VERSION 5.8 ;
BUSBITCHARS "[]" ;
DIVIDERCHAR "/" ;
UNITS
    DATABASE MICRONS 1000 ;
END UNITS

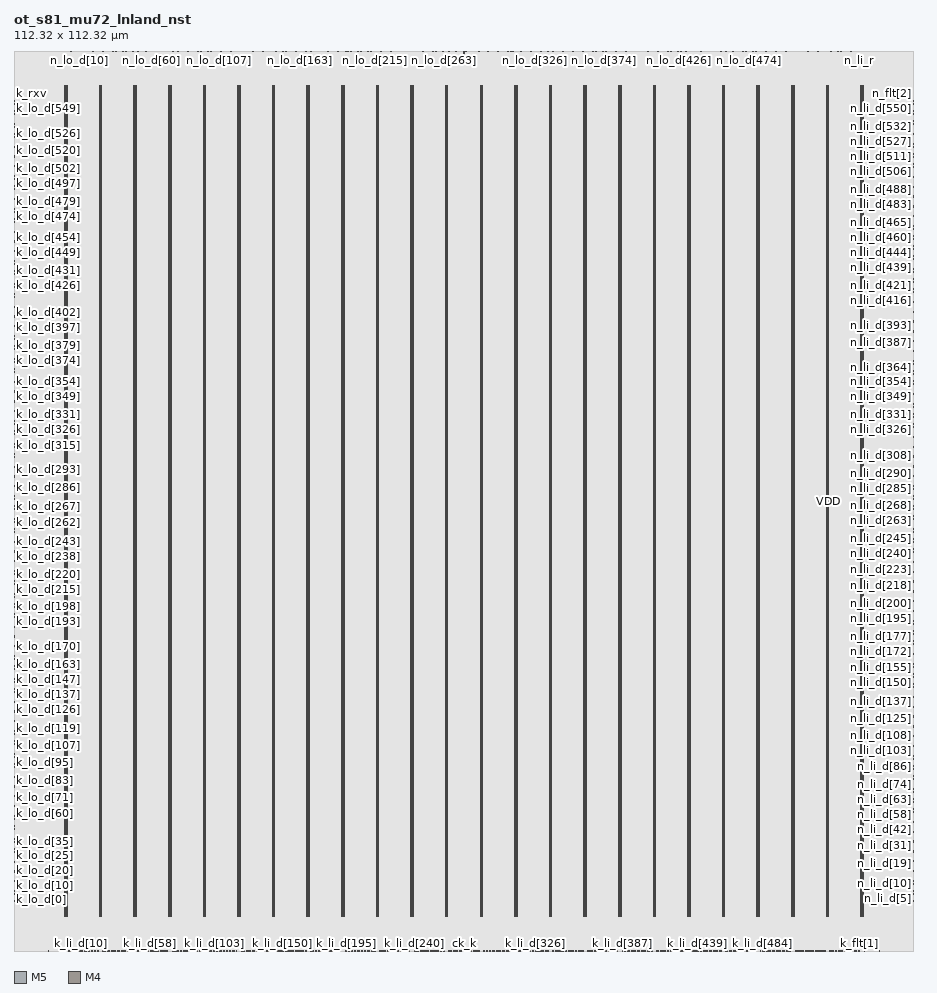
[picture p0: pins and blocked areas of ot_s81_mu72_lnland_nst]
MACRO ot_s81_mu72_lnland_nst
  FOREIGN ot_s81_mu72_lnland_nst 0 0 ;
  CLASS BLOCK ;
  SIZE 112.32 BY 112.32 ;
  PIN ck_k
    DIRECTION INPUT ;
    USE SIGNAL ;
    PORT
      LAYER M5 ;
        RECT  56.148 0 56.196 0.48 ;
    END
  END ck_k
  PIN ck_n
    DIRECTION INPUT ;
    USE SIGNAL ;
    PORT
      LAYER M5 ;
        RECT  56.148 111.84 56.196 112.32 ;
    END
  END ck_n
  PIN k_flt[0]
    DIRECTION OUTPUT ;
    USE SIGNAL ;
    PORT
      LAYER M5 ;
        RECT  105.504 0 105.528 0.084 ;
    END
  END k_flt[0]
  PIN k_flt[1]
    DIRECTION OUTPUT ;
    USE SIGNAL ;
    PORT
      LAYER M5 ;
        RECT  105.552 0 105.576 0.084 ;
    END
  END k_flt[1]
  PIN k_flt[2]
    DIRECTION OUTPUT ;
    USE SIGNAL ;
    PORT
      LAYER M5 ;
        RECT  106.128 0 106.152 0.084 ;
    END
  END k_flt[2]
  PIN k_li_d[0]
    DIRECTION OUTPUT ;
    USE SIGNAL ;
    PORT
      LAYER M5 ;
        RECT  6.816 0 6.84 0.084 ;
    END
  END k_li_d[0]
  PIN k_li_d[100]
    DIRECTION OUTPUT ;
    USE SIGNAL ;
    PORT
      LAYER M5 ;
        RECT  24.528 0 24.552 0.084 ;
    END
  END k_li_d[100]
  PIN k_li_d[101]
    DIRECTION OUTPUT ;
    USE SIGNAL ;
    PORT
      LAYER M5 ;
        RECT  24.672 0 24.696 0.084 ;
    END
  END k_li_d[101]
  PIN k_li_d[102]
    DIRECTION OUTPUT ;
    USE SIGNAL ;
    PORT
      LAYER M5 ;
        RECT  24.864 0 24.888 0.084 ;
    END
  END k_li_d[102]
  PIN k_li_d[103]
    DIRECTION OUTPUT ;
    USE SIGNAL ;
    PORT
      LAYER M5 ;
        RECT  25.056 0 25.08 0.084 ;
    END
  END k_li_d[103]
  PIN k_li_d[104]
    DIRECTION OUTPUT ;
    USE SIGNAL ;
    PORT
      LAYER M5 ;
        RECT  25.248 0 25.272 0.084 ;
    END
  END k_li_d[104]
  PIN k_li_d[105]
    DIRECTION OUTPUT ;
    USE SIGNAL ;
    PORT
      LAYER M5 ;
        RECT  25.392 0 25.416 0.084 ;
    END
  END k_li_d[105]
  PIN k_li_d[106]
    DIRECTION OUTPUT ;
    USE SIGNAL ;
    PORT
      LAYER M5 ;
        RECT  25.584 0 25.608 0.084 ;
    END
  END k_li_d[106]
  PIN k_li_d[107]
    DIRECTION OUTPUT ;
    USE SIGNAL ;
    PORT
      LAYER M5 ;
        RECT  25.776 0 25.8 0.084 ;
    END
  END k_li_d[107]
  PIN k_li_d[108]
    DIRECTION OUTPUT ;
    USE SIGNAL ;
    PORT
      LAYER M5 ;
        RECT  25.92 0 25.944 0.084 ;
    END
  END k_li_d[108]
  PIN k_li_d[109]
    DIRECTION OUTPUT ;
    USE SIGNAL ;
    PORT
      LAYER M5 ;
        RECT  26.112 0 26.136 0.084 ;
    END
  END k_li_d[109]
  PIN k_li_d[10]
    DIRECTION OUTPUT ;
    USE SIGNAL ;
    PORT
      LAYER M5 ;
        RECT  8.352 0 8.376 0.084 ;
    END
  END k_li_d[10]
  PIN k_li_d[110]
    DIRECTION OUTPUT ;
    USE SIGNAL ;
    PORT
      LAYER M5 ;
        RECT  26.304 0 26.328 0.084 ;
    END
  END k_li_d[110]
  PIN k_li_d[111]
    DIRECTION OUTPUT ;
    USE SIGNAL ;
    PORT
      LAYER M5 ;
        RECT  26.496 0 26.52 0.084 ;
    END
  END k_li_d[111]
  PIN k_li_d[112]
    DIRECTION OUTPUT ;
    USE SIGNAL ;
    PORT
      LAYER M5 ;
        RECT  26.64 0 26.664 0.084 ;
    END
  END k_li_d[112]
  PIN k_li_d[113]
    DIRECTION OUTPUT ;
    USE SIGNAL ;
    PORT
      LAYER M5 ;
        RECT  26.832 0 26.856 0.084 ;
    END
  END k_li_d[113]
  PIN k_li_d[114]
    DIRECTION OUTPUT ;
    USE SIGNAL ;
    PORT
      LAYER M5 ;
        RECT  27.024 0 27.048 0.084 ;
    END
  END k_li_d[114]
  PIN k_li_d[115]
    DIRECTION OUTPUT ;
    USE SIGNAL ;
    PORT
      LAYER M5 ;
        RECT  27.216 0 27.24 0.084 ;
    END
  END k_li_d[115]
  PIN k_li_d[116]
    DIRECTION OUTPUT ;
    USE SIGNAL ;
    PORT
      LAYER M5 ;
        RECT  27.36 0 27.384 0.084 ;
    END
  END k_li_d[116]
  PIN k_li_d[117]
    DIRECTION OUTPUT ;
    USE SIGNAL ;
    PORT
      LAYER M5 ;
        RECT  27.552 0 27.576 0.084 ;
    END
  END k_li_d[117]
  PIN k_li_d[118]
    DIRECTION OUTPUT ;
    USE SIGNAL ;
    PORT
      LAYER M5 ;
        RECT  27.744 0 27.768 0.084 ;
    END
  END k_li_d[118]
  PIN k_li_d[119]
    DIRECTION OUTPUT ;
    USE SIGNAL ;
    PORT
      LAYER M5 ;
        RECT  27.792 0 27.816 0.084 ;
    END
  END k_li_d[119]
  PIN k_li_d[11]
    DIRECTION OUTPUT ;
    USE SIGNAL ;
    PORT
      LAYER M5 ;
        RECT  8.544 0 8.568 0.084 ;
    END
  END k_li_d[11]
  PIN k_li_d[120]
    DIRECTION OUTPUT ;
    USE SIGNAL ;
    PORT
      LAYER M5 ;
        RECT  28.368 0 28.392 0.084 ;
    END
  END k_li_d[120]
  PIN k_li_d[121]
    DIRECTION OUTPUT ;
    USE SIGNAL ;
    PORT
      LAYER M5 ;
        RECT  28.416 0 28.44 0.084 ;
    END
  END k_li_d[121]
  PIN k_li_d[122]
    DIRECTION OUTPUT ;
    USE SIGNAL ;
    PORT
      LAYER M5 ;
        RECT  28.464 0 28.488 0.084 ;
    END
  END k_li_d[122]
  PIN k_li_d[123]
    DIRECTION OUTPUT ;
    USE SIGNAL ;
    PORT
      LAYER M5 ;
        RECT  28.608 0 28.632 0.084 ;
    END
  END k_li_d[123]
  PIN k_li_d[124]
    DIRECTION OUTPUT ;
    USE SIGNAL ;
    PORT
      LAYER M5 ;
        RECT  28.8 0 28.824 0.084 ;
    END
  END k_li_d[124]
  PIN k_li_d[125]
    DIRECTION OUTPUT ;
    USE SIGNAL ;
    PORT
      LAYER M5 ;
        RECT  28.992 0 29.016 0.084 ;
    END
  END k_li_d[125]
  PIN k_li_d[126]
    DIRECTION OUTPUT ;
    USE SIGNAL ;
    PORT
      LAYER M5 ;
        RECT  29.184 0 29.208 0.084 ;
    END
  END k_li_d[126]
  PIN k_li_d[127]
    DIRECTION OUTPUT ;
    USE SIGNAL ;
    PORT
      LAYER M5 ;
        RECT  29.328 0 29.352 0.084 ;
    END
  END k_li_d[127]
  PIN k_li_d[128]
    DIRECTION OUTPUT ;
    USE SIGNAL ;
    PORT
      LAYER M5 ;
        RECT  29.52 0 29.544 0.084 ;
    END
  END k_li_d[128]
  PIN k_li_d[129]
    DIRECTION OUTPUT ;
    USE SIGNAL ;
    PORT
      LAYER M5 ;
        RECT  29.712 0 29.736 0.084 ;
    END
  END k_li_d[129]
  PIN k_li_d[12]
    DIRECTION OUTPUT ;
    USE SIGNAL ;
    PORT
      LAYER M5 ;
        RECT  8.736 0 8.76 0.084 ;
    END
  END k_li_d[12]
  PIN k_li_d[130]
    DIRECTION OUTPUT ;
    USE SIGNAL ;
    PORT
      LAYER M5 ;
        RECT  29.904 0 29.928 0.084 ;
    END
  END k_li_d[130]
  PIN k_li_d[131]
    DIRECTION OUTPUT ;
    USE SIGNAL ;
    PORT
      LAYER M5 ;
        RECT  30.048 0 30.072 0.084 ;
    END
  END k_li_d[131]
  PIN k_li_d[132]
    DIRECTION OUTPUT ;
    USE SIGNAL ;
    PORT
      LAYER M5 ;
        RECT  30.24 0 30.264 0.084 ;
    END
  END k_li_d[132]
  PIN k_li_d[133]
    DIRECTION OUTPUT ;
    USE SIGNAL ;
    PORT
      LAYER M5 ;
        RECT  30.432 0 30.456 0.084 ;
    END
  END k_li_d[133]
  PIN k_li_d[134]
    DIRECTION OUTPUT ;
    USE SIGNAL ;
    PORT
      LAYER M5 ;
        RECT  30.624 0 30.648 0.084 ;
    END
  END k_li_d[134]
  PIN k_li_d[135]
    DIRECTION OUTPUT ;
    USE SIGNAL ;
    PORT
      LAYER M5 ;
        RECT  30.768 0 30.792 0.084 ;
    END
  END k_li_d[135]
  PIN k_li_d[136]
    DIRECTION OUTPUT ;
    USE SIGNAL ;
    PORT
      LAYER M5 ;
        RECT  30.96 0 30.984 0.084 ;
    END
  END k_li_d[136]
  PIN k_li_d[137]
    DIRECTION OUTPUT ;
    USE SIGNAL ;
    PORT
      LAYER M5 ;
        RECT  31.152 0 31.176 0.084 ;
    END
  END k_li_d[137]
  PIN k_li_d[138]
    DIRECTION OUTPUT ;
    USE SIGNAL ;
    PORT
      LAYER M5 ;
        RECT  31.296 0 31.32 0.084 ;
    END
  END k_li_d[138]
  PIN k_li_d[139]
    DIRECTION OUTPUT ;
    USE SIGNAL ;
    PORT
      LAYER M5 ;
        RECT  31.488 0 31.512 0.084 ;
    END
  END k_li_d[139]
  PIN k_li_d[13]
    DIRECTION OUTPUT ;
    USE SIGNAL ;
    PORT
      LAYER M5 ;
        RECT  8.928 0 8.952 0.084 ;
    END
  END k_li_d[13]
  PIN k_li_d[140]
    DIRECTION OUTPUT ;
    USE SIGNAL ;
    PORT
      LAYER M5 ;
        RECT  31.68 0 31.704 0.084 ;
    END
  END k_li_d[140]
  PIN k_li_d[141]
    DIRECTION OUTPUT ;
    USE SIGNAL ;
    PORT
      LAYER M5 ;
        RECT  31.872 0 31.896 0.084 ;
    END
  END k_li_d[141]
  PIN k_li_d[142]
    DIRECTION OUTPUT ;
    USE SIGNAL ;
    PORT
      LAYER M5 ;
        RECT  32.016 0 32.04 0.084 ;
    END
  END k_li_d[142]
  PIN k_li_d[143]
    DIRECTION OUTPUT ;
    USE SIGNAL ;
    PORT
      LAYER M5 ;
        RECT  32.112 0 32.136 0.084 ;
    END
  END k_li_d[143]
  PIN k_li_d[144]
    DIRECTION OUTPUT ;
    USE SIGNAL ;
    PORT
      LAYER M5 ;
        RECT  32.688 0 32.712 0.084 ;
    END
  END k_li_d[144]
  PIN k_li_d[145]
    DIRECTION OUTPUT ;
    USE SIGNAL ;
    PORT
      LAYER M5 ;
        RECT  32.736 0 32.76 0.084 ;
    END
  END k_li_d[145]
  PIN k_li_d[146]
    DIRECTION OUTPUT ;
    USE SIGNAL ;
    PORT
      LAYER M5 ;
        RECT  32.784 0 32.808 0.084 ;
    END
  END k_li_d[146]
  PIN k_li_d[147]
    DIRECTION OUTPUT ;
    USE SIGNAL ;
    PORT
      LAYER M5 ;
        RECT  32.928 0 32.952 0.084 ;
    END
  END k_li_d[147]
  PIN k_li_d[148]
    DIRECTION OUTPUT ;
    USE SIGNAL ;
    PORT
      LAYER M5 ;
        RECT  33.12 0 33.144 0.084 ;
    END
  END k_li_d[148]
  PIN k_li_d[149]
    DIRECTION OUTPUT ;
    USE SIGNAL ;
    PORT
      LAYER M5 ;
        RECT  33.312 0 33.336 0.084 ;
    END
  END k_li_d[149]
  PIN k_li_d[14]
    DIRECTION OUTPUT ;
    USE SIGNAL ;
    PORT
      LAYER M5 ;
        RECT  9.072 0 9.096 0.084 ;
    END
  END k_li_d[14]
  PIN k_li_d[150]
    DIRECTION OUTPUT ;
    USE SIGNAL ;
    PORT
      LAYER M5 ;
        RECT  33.456 0 33.48 0.084 ;
    END
  END k_li_d[150]
  PIN k_li_d[151]
    DIRECTION OUTPUT ;
    USE SIGNAL ;
    PORT
      LAYER M5 ;
        RECT  33.648 0 33.672 0.084 ;
    END
  END k_li_d[151]
  PIN k_li_d[152]
    DIRECTION OUTPUT ;
    USE SIGNAL ;
    PORT
      LAYER M5 ;
        RECT  33.84 0 33.864 0.084 ;
    END
  END k_li_d[152]
  PIN k_li_d[153]
    DIRECTION OUTPUT ;
    USE SIGNAL ;
    PORT
      LAYER M5 ;
        RECT  34.032 0 34.056 0.084 ;
    END
  END k_li_d[153]
  PIN k_li_d[154]
    DIRECTION OUTPUT ;
    USE SIGNAL ;
    PORT
      LAYER M5 ;
        RECT  34.176 0 34.2 0.084 ;
    END
  END k_li_d[154]
  PIN k_li_d[155]
    DIRECTION OUTPUT ;
    USE SIGNAL ;
    PORT
      LAYER M5 ;
        RECT  34.368 0 34.392 0.084 ;
    END
  END k_li_d[155]
  PIN k_li_d[156]
    DIRECTION OUTPUT ;
    USE SIGNAL ;
    PORT
      LAYER M5 ;
        RECT  34.56 0 34.584 0.084 ;
    END
  END k_li_d[156]
  PIN k_li_d[157]
    DIRECTION OUTPUT ;
    USE SIGNAL ;
    PORT
      LAYER M5 ;
        RECT  34.704 0 34.728 0.084 ;
    END
  END k_li_d[157]
  PIN k_li_d[158]
    DIRECTION OUTPUT ;
    USE SIGNAL ;
    PORT
      LAYER M5 ;
        RECT  34.896 0 34.92 0.084 ;
    END
  END k_li_d[158]
  PIN k_li_d[159]
    DIRECTION OUTPUT ;
    USE SIGNAL ;
    PORT
      LAYER M5 ;
        RECT  35.088 0 35.112 0.084 ;
    END
  END k_li_d[159]
  PIN k_li_d[15]
    DIRECTION OUTPUT ;
    USE SIGNAL ;
    PORT
      LAYER M5 ;
        RECT  9.264 0 9.288 0.084 ;
    END
  END k_li_d[15]
  PIN k_li_d[160]
    DIRECTION OUTPUT ;
    USE SIGNAL ;
    PORT
      LAYER M5 ;
        RECT  35.28 0 35.304 0.084 ;
    END
  END k_li_d[160]
  PIN k_li_d[161]
    DIRECTION OUTPUT ;
    USE SIGNAL ;
    PORT
      LAYER M5 ;
        RECT  35.424 0 35.448 0.084 ;
    END
  END k_li_d[161]
  PIN k_li_d[162]
    DIRECTION OUTPUT ;
    USE SIGNAL ;
    PORT
      LAYER M5 ;
        RECT  35.616 0 35.64 0.084 ;
    END
  END k_li_d[162]
  PIN k_li_d[163]
    DIRECTION OUTPUT ;
    USE SIGNAL ;
    PORT
      LAYER M5 ;
        RECT  35.808 0 35.832 0.084 ;
    END
  END k_li_d[163]
  PIN k_li_d[164]
    DIRECTION OUTPUT ;
    USE SIGNAL ;
    PORT
      LAYER M5 ;
        RECT  36 0 36.024 0.084 ;
    END
  END k_li_d[164]
  PIN k_li_d[165]
    DIRECTION OUTPUT ;
    USE SIGNAL ;
    PORT
      LAYER M5 ;
        RECT  36.144 0 36.168 0.084 ;
    END
  END k_li_d[165]
  PIN k_li_d[166]
    DIRECTION OUTPUT ;
    USE SIGNAL ;
    PORT
      LAYER M5 ;
        RECT  36.336 0 36.36 0.084 ;
    END
  END k_li_d[166]
  PIN k_li_d[167]
    DIRECTION OUTPUT ;
    USE SIGNAL ;
    PORT
      LAYER M5 ;
        RECT  36.432 0 36.456 0.084 ;
    END
  END k_li_d[167]
  PIN k_li_d[168]
    DIRECTION OUTPUT ;
    USE SIGNAL ;
    PORT
      LAYER M5 ;
        RECT  37.008 0 37.032 0.084 ;
    END
  END k_li_d[168]
  PIN k_li_d[169]
    DIRECTION OUTPUT ;
    USE SIGNAL ;
    PORT
      LAYER M5 ;
        RECT  37.056 0 37.08 0.084 ;
    END
  END k_li_d[169]
  PIN k_li_d[16]
    DIRECTION OUTPUT ;
    USE SIGNAL ;
    PORT
      LAYER M5 ;
        RECT  9.456 0 9.48 0.084 ;
    END
  END k_li_d[16]
  PIN k_li_d[170]
    DIRECTION OUTPUT ;
    USE SIGNAL ;
    PORT
      LAYER M5 ;
        RECT  37.104 0 37.128 0.084 ;
    END
  END k_li_d[170]
  PIN k_li_d[171]
    DIRECTION OUTPUT ;
    USE SIGNAL ;
    PORT
      LAYER M5 ;
        RECT  37.248 0 37.272 0.084 ;
    END
  END k_li_d[171]
  PIN k_li_d[172]
    DIRECTION OUTPUT ;
    USE SIGNAL ;
    PORT
      LAYER M5 ;
        RECT  37.392 0 37.416 0.084 ;
    END
  END k_li_d[172]
  PIN k_li_d[173]
    DIRECTION OUTPUT ;
    USE SIGNAL ;
    PORT
      LAYER M5 ;
        RECT  37.584 0 37.608 0.084 ;
    END
  END k_li_d[173]
  PIN k_li_d[174]
    DIRECTION OUTPUT ;
    USE SIGNAL ;
    PORT
      LAYER M5 ;
        RECT  37.776 0 37.8 0.084 ;
    END
  END k_li_d[174]
  PIN k_li_d[175]
    DIRECTION OUTPUT ;
    USE SIGNAL ;
    PORT
      LAYER M5 ;
        RECT  37.968 0 37.992 0.084 ;
    END
  END k_li_d[175]
  PIN k_li_d[176]
    DIRECTION OUTPUT ;
    USE SIGNAL ;
    PORT
      LAYER M5 ;
        RECT  38.112 0 38.136 0.084 ;
    END
  END k_li_d[176]
  PIN k_li_d[177]
    DIRECTION OUTPUT ;
    USE SIGNAL ;
    PORT
      LAYER M5 ;
        RECT  38.304 0 38.328 0.084 ;
    END
  END k_li_d[177]
  PIN k_li_d[178]
    DIRECTION OUTPUT ;
    USE SIGNAL ;
    PORT
      LAYER M5 ;
        RECT  38.496 0 38.52 0.084 ;
    END
  END k_li_d[178]
  PIN k_li_d[179]
    DIRECTION OUTPUT ;
    USE SIGNAL ;
    PORT
      LAYER M5 ;
        RECT  38.688 0 38.712 0.084 ;
    END
  END k_li_d[179]
  PIN k_li_d[17]
    DIRECTION OUTPUT ;
    USE SIGNAL ;
    PORT
      LAYER M5 ;
        RECT  9.648 0 9.672 0.084 ;
    END
  END k_li_d[17]
  PIN k_li_d[180]
    DIRECTION OUTPUT ;
    USE SIGNAL ;
    PORT
      LAYER M5 ;
        RECT  38.832 0 38.856 0.084 ;
    END
  END k_li_d[180]
  PIN k_li_d[181]
    DIRECTION OUTPUT ;
    USE SIGNAL ;
    PORT
      LAYER M5 ;
        RECT  39.024 0 39.048 0.084 ;
    END
  END k_li_d[181]
  PIN k_li_d[182]
    DIRECTION OUTPUT ;
    USE SIGNAL ;
    PORT
      LAYER M5 ;
        RECT  39.216 0 39.24 0.084 ;
    END
  END k_li_d[182]
  PIN k_li_d[183]
    DIRECTION OUTPUT ;
    USE SIGNAL ;
    PORT
      LAYER M5 ;
        RECT  39.408 0 39.432 0.084 ;
    END
  END k_li_d[183]
  PIN k_li_d[184]
    DIRECTION OUTPUT ;
    USE SIGNAL ;
    PORT
      LAYER M5 ;
        RECT  39.552 0 39.576 0.084 ;
    END
  END k_li_d[184]
  PIN k_li_d[185]
    DIRECTION OUTPUT ;
    USE SIGNAL ;
    PORT
      LAYER M5 ;
        RECT  39.744 0 39.768 0.084 ;
    END
  END k_li_d[185]
  PIN k_li_d[186]
    DIRECTION OUTPUT ;
    USE SIGNAL ;
    PORT
      LAYER M5 ;
        RECT  39.936 0 39.96 0.084 ;
    END
  END k_li_d[186]
  PIN k_li_d[187]
    DIRECTION OUTPUT ;
    USE SIGNAL ;
    PORT
      LAYER M5 ;
        RECT  40.08 0 40.104 0.084 ;
    END
  END k_li_d[187]
  PIN k_li_d[188]
    DIRECTION OUTPUT ;
    USE SIGNAL ;
    PORT
      LAYER M5 ;
        RECT  40.272 0 40.296 0.084 ;
    END
  END k_li_d[188]
  PIN k_li_d[189]
    DIRECTION OUTPUT ;
    USE SIGNAL ;
    PORT
      LAYER M5 ;
        RECT  40.464 0 40.488 0.084 ;
    END
  END k_li_d[189]
  PIN k_li_d[18]
    DIRECTION OUTPUT ;
    USE SIGNAL ;
    PORT
      LAYER M5 ;
        RECT  9.792 0 9.816 0.084 ;
    END
  END k_li_d[18]
  PIN k_li_d[190]
    DIRECTION OUTPUT ;
    USE SIGNAL ;
    PORT
      LAYER M5 ;
        RECT  40.656 0 40.68 0.084 ;
    END
  END k_li_d[190]
  PIN k_li_d[191]
    DIRECTION OUTPUT ;
    USE SIGNAL ;
    PORT
      LAYER M5 ;
        RECT  40.752 0 40.776 0.084 ;
    END
  END k_li_d[191]
  PIN k_li_d[192]
    DIRECTION OUTPUT ;
    USE SIGNAL ;
    PORT
      LAYER M5 ;
        RECT  41.328 0 41.352 0.084 ;
    END
  END k_li_d[192]
  PIN k_li_d[193]
    DIRECTION OUTPUT ;
    USE SIGNAL ;
    PORT
      LAYER M5 ;
        RECT  41.376 0 41.4 0.084 ;
    END
  END k_li_d[193]
  PIN k_li_d[194]
    DIRECTION OUTPUT ;
    USE SIGNAL ;
    PORT
      LAYER M5 ;
        RECT  41.424 0 41.448 0.084 ;
    END
  END k_li_d[194]
  PIN k_li_d[195]
    DIRECTION OUTPUT ;
    USE SIGNAL ;
    PORT
      LAYER M5 ;
        RECT  41.52 0 41.544 0.084 ;
    END
  END k_li_d[195]
  PIN k_li_d[196]
    DIRECTION OUTPUT ;
    USE SIGNAL ;
    PORT
      LAYER M5 ;
        RECT  41.712 0 41.736 0.084 ;
    END
  END k_li_d[196]
  PIN k_li_d[197]
    DIRECTION OUTPUT ;
    USE SIGNAL ;
    PORT
      LAYER M5 ;
        RECT  41.904 0 41.928 0.084 ;
    END
  END k_li_d[197]
  PIN k_li_d[198]
    DIRECTION OUTPUT ;
    USE SIGNAL ;
    PORT
      LAYER M5 ;
        RECT  42.096 0 42.12 0.084 ;
    END
  END k_li_d[198]
  PIN k_li_d[199]
    DIRECTION OUTPUT ;
    USE SIGNAL ;
    PORT
      LAYER M5 ;
        RECT  42.24 0 42.264 0.084 ;
    END
  END k_li_d[199]
  PIN k_li_d[19]
    DIRECTION OUTPUT ;
    USE SIGNAL ;
    PORT
      LAYER M5 ;
        RECT  9.984 0 10.008 0.084 ;
    END
  END k_li_d[19]
  PIN k_li_d[1]
    DIRECTION OUTPUT ;
    USE SIGNAL ;
    PORT
      LAYER M5 ;
        RECT  6.864 0 6.888 0.084 ;
    END
  END k_li_d[1]
  PIN k_li_d[200]
    DIRECTION OUTPUT ;
    USE SIGNAL ;
    PORT
      LAYER M5 ;
        RECT  42.432 0 42.456 0.084 ;
    END
  END k_li_d[200]
  PIN k_li_d[201]
    DIRECTION OUTPUT ;
    USE SIGNAL ;
    PORT
      LAYER M5 ;
        RECT  42.624 0 42.648 0.084 ;
    END
  END k_li_d[201]
  PIN k_li_d[202]
    DIRECTION OUTPUT ;
    USE SIGNAL ;
    PORT
      LAYER M5 ;
        RECT  42.816 0 42.84 0.084 ;
    END
  END k_li_d[202]
  PIN k_li_d[203]
    DIRECTION OUTPUT ;
    USE SIGNAL ;
    PORT
      LAYER M5 ;
        RECT  42.96 0 42.984 0.084 ;
    END
  END k_li_d[203]
  PIN k_li_d[204]
    DIRECTION OUTPUT ;
    USE SIGNAL ;
    PORT
      LAYER M5 ;
        RECT  43.152 0 43.176 0.084 ;
    END
  END k_li_d[204]
  PIN k_li_d[205]
    DIRECTION OUTPUT ;
    USE SIGNAL ;
    PORT
      LAYER M5 ;
        RECT  43.344 0 43.368 0.084 ;
    END
  END k_li_d[205]
  PIN k_li_d[206]
    DIRECTION OUTPUT ;
    USE SIGNAL ;
    PORT
      LAYER M5 ;
        RECT  43.488 0 43.512 0.084 ;
    END
  END k_li_d[206]
  PIN k_li_d[207]
    DIRECTION OUTPUT ;
    USE SIGNAL ;
    PORT
      LAYER M5 ;
        RECT  43.68 0 43.704 0.084 ;
    END
  END k_li_d[207]
  PIN k_li_d[208]
    DIRECTION OUTPUT ;
    USE SIGNAL ;
    PORT
      LAYER M5 ;
        RECT  43.872 0 43.896 0.084 ;
    END
  END k_li_d[208]
  PIN k_li_d[209]
    DIRECTION OUTPUT ;
    USE SIGNAL ;
    PORT
      LAYER M5 ;
        RECT  44.064 0 44.088 0.084 ;
    END
  END k_li_d[209]
  PIN k_li_d[20]
    DIRECTION OUTPUT ;
    USE SIGNAL ;
    PORT
      LAYER M5 ;
        RECT  10.176 0 10.2 0.084 ;
    END
  END k_li_d[20]
  PIN k_li_d[210]
    DIRECTION OUTPUT ;
    USE SIGNAL ;
    PORT
      LAYER M5 ;
        RECT  44.208 0 44.232 0.084 ;
    END
  END k_li_d[210]
  PIN k_li_d[211]
    DIRECTION OUTPUT ;
    USE SIGNAL ;
    PORT
      LAYER M5 ;
        RECT  44.4 0 44.424 0.084 ;
    END
  END k_li_d[211]
  PIN k_li_d[212]
    DIRECTION OUTPUT ;
    USE SIGNAL ;
    PORT
      LAYER M5 ;
        RECT  44.592 0 44.616 0.084 ;
    END
  END k_li_d[212]
  PIN k_li_d[213]
    DIRECTION OUTPUT ;
    USE SIGNAL ;
    PORT
      LAYER M5 ;
        RECT  44.784 0 44.808 0.084 ;
    END
  END k_li_d[213]
  PIN k_li_d[214]
    DIRECTION OUTPUT ;
    USE SIGNAL ;
    PORT
      LAYER M5 ;
        RECT  44.928 0 44.952 0.084 ;
    END
  END k_li_d[214]
  PIN k_li_d[215]
    DIRECTION OUTPUT ;
    USE SIGNAL ;
    PORT
      LAYER M5 ;
        RECT  45.072 0 45.096 0.084 ;
    END
  END k_li_d[215]
  PIN k_li_d[216]
    DIRECTION OUTPUT ;
    USE SIGNAL ;
    PORT
      LAYER M5 ;
        RECT  45.648 0 45.672 0.084 ;
    END
  END k_li_d[216]
  PIN k_li_d[217]
    DIRECTION OUTPUT ;
    USE SIGNAL ;
    PORT
      LAYER M5 ;
        RECT  45.696 0 45.72 0.084 ;
    END
  END k_li_d[217]
  PIN k_li_d[218]
    DIRECTION OUTPUT ;
    USE SIGNAL ;
    PORT
      LAYER M5 ;
        RECT  45.744 0 45.768 0.084 ;
    END
  END k_li_d[218]
  PIN k_li_d[219]
    DIRECTION OUTPUT ;
    USE SIGNAL ;
    PORT
      LAYER M5 ;
        RECT  45.84 0 45.864 0.084 ;
    END
  END k_li_d[219]
  PIN k_li_d[21]
    DIRECTION OUTPUT ;
    USE SIGNAL ;
    PORT
      LAYER M5 ;
        RECT  10.368 0 10.392 0.084 ;
    END
  END k_li_d[21]
  PIN k_li_d[220]
    DIRECTION OUTPUT ;
    USE SIGNAL ;
    PORT
      LAYER M5 ;
        RECT  46.032 0 46.056 0.084 ;
    END
  END k_li_d[220]
  PIN k_li_d[221]
    DIRECTION OUTPUT ;
    USE SIGNAL ;
    PORT
      LAYER M5 ;
        RECT  46.176 0 46.2 0.084 ;
    END
  END k_li_d[221]
  PIN k_li_d[222]
    DIRECTION OUTPUT ;
    USE SIGNAL ;
    PORT
      LAYER M5 ;
        RECT  46.368 0 46.392 0.084 ;
    END
  END k_li_d[222]
  PIN k_li_d[223]
    DIRECTION OUTPUT ;
    USE SIGNAL ;
    PORT
      LAYER M5 ;
        RECT  46.56 0 46.584 0.084 ;
    END
  END k_li_d[223]
  PIN k_li_d[224]
    DIRECTION OUTPUT ;
    USE SIGNAL ;
    PORT
      LAYER M5 ;
        RECT  46.752 0 46.776 0.084 ;
    END
  END k_li_d[224]
  PIN k_li_d[225]
    DIRECTION OUTPUT ;
    USE SIGNAL ;
    PORT
      LAYER M5 ;
        RECT  46.896 0 46.92 0.084 ;
    END
  END k_li_d[225]
  PIN k_li_d[226]
    DIRECTION OUTPUT ;
    USE SIGNAL ;
    PORT
      LAYER M5 ;
        RECT  47.088 0 47.112 0.084 ;
    END
  END k_li_d[226]
  PIN k_li_d[227]
    DIRECTION OUTPUT ;
    USE SIGNAL ;
    PORT
      LAYER M5 ;
        RECT  47.28 0 47.304 0.084 ;
    END
  END k_li_d[227]
  PIN k_li_d[228]
    DIRECTION OUTPUT ;
    USE SIGNAL ;
    PORT
      LAYER M5 ;
        RECT  47.472 0 47.496 0.084 ;
    END
  END k_li_d[228]
  PIN k_li_d[229]
    DIRECTION OUTPUT ;
    USE SIGNAL ;
    PORT
      LAYER M5 ;
        RECT  47.616 0 47.64 0.084 ;
    END
  END k_li_d[229]
  PIN k_li_d[22]
    DIRECTION OUTPUT ;
    USE SIGNAL ;
    PORT
      LAYER M5 ;
        RECT  10.512 0 10.536 0.084 ;
    END
  END k_li_d[22]
  PIN k_li_d[230]
    DIRECTION OUTPUT ;
    USE SIGNAL ;
    PORT
      LAYER M5 ;
        RECT  47.808 0 47.832 0.084 ;
    END
  END k_li_d[230]
  PIN k_li_d[231]
    DIRECTION OUTPUT ;
    USE SIGNAL ;
    PORT
      LAYER M5 ;
        RECT  48 0 48.024 0.084 ;
    END
  END k_li_d[231]
  PIN k_li_d[232]
    DIRECTION OUTPUT ;
    USE SIGNAL ;
    PORT
      LAYER M5 ;
        RECT  48.192 0 48.216 0.084 ;
    END
  END k_li_d[232]
  PIN k_li_d[233]
    DIRECTION OUTPUT ;
    USE SIGNAL ;
    PORT
      LAYER M5 ;
        RECT  48.336 0 48.36 0.084 ;
    END
  END k_li_d[233]
  PIN k_li_d[234]
    DIRECTION OUTPUT ;
    USE SIGNAL ;
    PORT
      LAYER M5 ;
        RECT  48.528 0 48.552 0.084 ;
    END
  END k_li_d[234]
  PIN k_li_d[235]
    DIRECTION OUTPUT ;
    USE SIGNAL ;
    PORT
      LAYER M5 ;
        RECT  48.72 0 48.744 0.084 ;
    END
  END k_li_d[235]
  PIN k_li_d[236]
    DIRECTION OUTPUT ;
    USE SIGNAL ;
    PORT
      LAYER M5 ;
        RECT  48.864 0 48.888 0.084 ;
    END
  END k_li_d[236]
  PIN k_li_d[237]
    DIRECTION OUTPUT ;
    USE SIGNAL ;
    PORT
      LAYER M5 ;
        RECT  49.056 0 49.08 0.084 ;
    END
  END k_li_d[237]
  PIN k_li_d[238]
    DIRECTION OUTPUT ;
    USE SIGNAL ;
    PORT
      LAYER M5 ;
        RECT  49.248 0 49.272 0.084 ;
    END
  END k_li_d[238]
  PIN k_li_d[239]
    DIRECTION OUTPUT ;
    USE SIGNAL ;
    PORT
      LAYER M5 ;
        RECT  49.392 0 49.416 0.084 ;
    END
  END k_li_d[239]
  PIN k_li_d[23]
    DIRECTION OUTPUT ;
    USE SIGNAL ;
    PORT
      LAYER M5 ;
        RECT  11.088 0 11.112 0.084 ;
    END
  END k_li_d[23]
  PIN k_li_d[240]
    DIRECTION OUTPUT ;
    USE SIGNAL ;
    PORT
      LAYER M5 ;
        RECT  49.968 0 49.992 0.084 ;
    END
  END k_li_d[240]
  PIN k_li_d[241]
    DIRECTION OUTPUT ;
    USE SIGNAL ;
    PORT
      LAYER M5 ;
        RECT  50.016 0 50.04 0.084 ;
    END
  END k_li_d[241]
  PIN k_li_d[242]
    DIRECTION OUTPUT ;
    USE SIGNAL ;
    PORT
      LAYER M5 ;
        RECT  50.064 0 50.088 0.084 ;
    END
  END k_li_d[242]
  PIN k_li_d[243]
    DIRECTION OUTPUT ;
    USE SIGNAL ;
    PORT
      LAYER M5 ;
        RECT  50.16 0 50.184 0.084 ;
    END
  END k_li_d[243]
  PIN k_li_d[244]
    DIRECTION OUTPUT ;
    USE SIGNAL ;
    PORT
      LAYER M5 ;
        RECT  50.304 0 50.328 0.084 ;
    END
  END k_li_d[244]
  PIN k_li_d[245]
    DIRECTION OUTPUT ;
    USE SIGNAL ;
    PORT
      LAYER M5 ;
        RECT  50.496 0 50.52 0.084 ;
    END
  END k_li_d[245]
  PIN k_li_d[246]
    DIRECTION OUTPUT ;
    USE SIGNAL ;
    PORT
      LAYER M5 ;
        RECT  50.688 0 50.712 0.084 ;
    END
  END k_li_d[246]
  PIN k_li_d[247]
    DIRECTION OUTPUT ;
    USE SIGNAL ;
    PORT
      LAYER M5 ;
        RECT  50.88 0 50.904 0.084 ;
    END
  END k_li_d[247]
  PIN k_li_d[248]
    DIRECTION OUTPUT ;
    USE SIGNAL ;
    PORT
      LAYER M5 ;
        RECT  51.024 0 51.048 0.084 ;
    END
  END k_li_d[248]
  PIN k_li_d[249]
    DIRECTION OUTPUT ;
    USE SIGNAL ;
    PORT
      LAYER M5 ;
        RECT  51.216 0 51.24 0.084 ;
    END
  END k_li_d[249]
  PIN k_li_d[24]
    DIRECTION OUTPUT ;
    USE SIGNAL ;
    PORT
      LAYER M5 ;
        RECT  11.136 0 11.16 0.084 ;
    END
  END k_li_d[24]
  PIN k_li_d[250]
    DIRECTION OUTPUT ;
    USE SIGNAL ;
    PORT
      LAYER M5 ;
        RECT  51.408 0 51.432 0.084 ;
    END
  END k_li_d[250]
  PIN k_li_d[251]
    DIRECTION OUTPUT ;
    USE SIGNAL ;
    PORT
      LAYER M5 ;
        RECT  51.6 0 51.624 0.084 ;
    END
  END k_li_d[251]
  PIN k_li_d[252]
    DIRECTION OUTPUT ;
    USE SIGNAL ;
    PORT
      LAYER M5 ;
        RECT  51.744 0 51.768 0.084 ;
    END
  END k_li_d[252]
  PIN k_li_d[253]
    DIRECTION OUTPUT ;
    USE SIGNAL ;
    PORT
      LAYER M5 ;
        RECT  51.936 0 51.96 0.084 ;
    END
  END k_li_d[253]
  PIN k_li_d[254]
    DIRECTION OUTPUT ;
    USE SIGNAL ;
    PORT
      LAYER M5 ;
        RECT  52.128 0 52.152 0.084 ;
    END
  END k_li_d[254]
  PIN k_li_d[255]
    DIRECTION OUTPUT ;
    USE SIGNAL ;
    PORT
      LAYER M5 ;
        RECT  52.272 0 52.296 0.084 ;
    END
  END k_li_d[255]
  PIN k_li_d[256]
    DIRECTION OUTPUT ;
    USE SIGNAL ;
    PORT
      LAYER M5 ;
        RECT  52.464 0 52.488 0.084 ;
    END
  END k_li_d[256]
  PIN k_li_d[257]
    DIRECTION OUTPUT ;
    USE SIGNAL ;
    PORT
      LAYER M5 ;
        RECT  52.656 0 52.68 0.084 ;
    END
  END k_li_d[257]
  PIN k_li_d[258]
    DIRECTION OUTPUT ;
    USE SIGNAL ;
    PORT
      LAYER M5 ;
        RECT  52.848 0 52.872 0.084 ;
    END
  END k_li_d[258]
  PIN k_li_d[259]
    DIRECTION OUTPUT ;
    USE SIGNAL ;
    PORT
      LAYER M5 ;
        RECT  52.992 0 53.016 0.084 ;
    END
  END k_li_d[259]
  PIN k_li_d[25]
    DIRECTION OUTPUT ;
    USE SIGNAL ;
    PORT
      LAYER M5 ;
        RECT  11.184 0 11.208 0.084 ;
    END
  END k_li_d[25]
  PIN k_li_d[260]
    DIRECTION OUTPUT ;
    USE SIGNAL ;
    PORT
      LAYER M5 ;
        RECT  53.184 0 53.208 0.084 ;
    END
  END k_li_d[260]
  PIN k_li_d[261]
    DIRECTION OUTPUT ;
    USE SIGNAL ;
    PORT
      LAYER M5 ;
        RECT  53.376 0 53.4 0.084 ;
    END
  END k_li_d[261]
  PIN k_li_d[262]
    DIRECTION OUTPUT ;
    USE SIGNAL ;
    PORT
      LAYER M5 ;
        RECT  53.568 0 53.592 0.084 ;
    END
  END k_li_d[262]
  PIN k_li_d[263]
    DIRECTION OUTPUT ;
    USE SIGNAL ;
    PORT
      LAYER M5 ;
        RECT  53.712 0 53.736 0.084 ;
    END
  END k_li_d[263]
  PIN k_li_d[264]
    DIRECTION OUTPUT ;
    USE SIGNAL ;
    PORT
      LAYER M5 ;
        RECT  54.288 0 54.312 0.084 ;
    END
  END k_li_d[264]
  PIN k_li_d[265]
    DIRECTION OUTPUT ;
    USE SIGNAL ;
    PORT
      LAYER M5 ;
        RECT  54.336 0 54.36 0.084 ;
    END
  END k_li_d[265]
  PIN k_li_d[266]
    DIRECTION OUTPUT ;
    USE SIGNAL ;
    PORT
      LAYER M5 ;
        RECT  54.384 0 54.408 0.084 ;
    END
  END k_li_d[266]
  PIN k_li_d[267]
    DIRECTION OUTPUT ;
    USE SIGNAL ;
    PORT
      LAYER M5 ;
        RECT  54.432 0 54.456 0.084 ;
    END
  END k_li_d[267]
  PIN k_li_d[268]
    DIRECTION OUTPUT ;
    USE SIGNAL ;
    PORT
      LAYER M5 ;
        RECT  54.624 0 54.648 0.084 ;
    END
  END k_li_d[268]
  PIN k_li_d[269]
    DIRECTION OUTPUT ;
    USE SIGNAL ;
    PORT
      LAYER M5 ;
        RECT  54.816 0 54.84 0.084 ;
    END
  END k_li_d[269]
  PIN k_li_d[26]
    DIRECTION OUTPUT ;
    USE SIGNAL ;
    PORT
      LAYER M5 ;
        RECT  11.232 0 11.256 0.084 ;
    END
  END k_li_d[26]
  PIN k_li_d[270]
    DIRECTION OUTPUT ;
    USE SIGNAL ;
    PORT
      LAYER M5 ;
        RECT  54.96 0 54.984 0.084 ;
    END
  END k_li_d[270]
  PIN k_li_d[271]
    DIRECTION OUTPUT ;
    USE SIGNAL ;
    PORT
      LAYER M5 ;
        RECT  55.152 0 55.176 0.084 ;
    END
  END k_li_d[271]
  PIN k_li_d[272]
    DIRECTION OUTPUT ;
    USE SIGNAL ;
    PORT
      LAYER M5 ;
        RECT  55.344 0 55.368 0.084 ;
    END
  END k_li_d[272]
  PIN k_li_d[273]
    DIRECTION OUTPUT ;
    USE SIGNAL ;
    PORT
      LAYER M5 ;
        RECT  55.536 0 55.56 0.084 ;
    END
  END k_li_d[273]
  PIN k_li_d[274]
    DIRECTION OUTPUT ;
    USE SIGNAL ;
    PORT
      LAYER M5 ;
        RECT  55.68 0 55.704 0.084 ;
    END
  END k_li_d[274]
  PIN k_li_d[275]
    DIRECTION OUTPUT ;
    USE SIGNAL ;
    PORT
      LAYER M5 ;
        RECT  55.872 0 55.896 0.084 ;
    END
  END k_li_d[275]
  PIN k_li_d[276]
    DIRECTION OUTPUT ;
    USE SIGNAL ;
    PORT
      LAYER M5 ;
        RECT  56.064 0 56.088 0.084 ;
    END
  END k_li_d[276]
  PIN k_li_d[277]
    DIRECTION OUTPUT ;
    USE SIGNAL ;
    PORT
      LAYER M5 ;
        RECT  56.256 0 56.28 0.084 ;
    END
  END k_li_d[277]
  PIN k_li_d[278]
    DIRECTION OUTPUT ;
    USE SIGNAL ;
    PORT
      LAYER M5 ;
        RECT  56.4 0 56.424 0.084 ;
    END
  END k_li_d[278]
  PIN k_li_d[279]
    DIRECTION OUTPUT ;
    USE SIGNAL ;
    PORT
      LAYER M5 ;
        RECT  56.592 0 56.616 0.084 ;
    END
  END k_li_d[279]
  PIN k_li_d[27]
    DIRECTION OUTPUT ;
    USE SIGNAL ;
    PORT
      LAYER M5 ;
        RECT  11.424 0 11.448 0.084 ;
    END
  END k_li_d[27]
  PIN k_li_d[280]
    DIRECTION OUTPUT ;
    USE SIGNAL ;
    PORT
      LAYER M5 ;
        RECT  56.784 0 56.808 0.084 ;
    END
  END k_li_d[280]
  PIN k_li_d[281]
    DIRECTION OUTPUT ;
    USE SIGNAL ;
    PORT
      LAYER M5 ;
        RECT  56.976 0 57 0.084 ;
    END
  END k_li_d[281]
  PIN k_li_d[282]
    DIRECTION OUTPUT ;
    USE SIGNAL ;
    PORT
      LAYER M5 ;
        RECT  57.12 0 57.144 0.084 ;
    END
  END k_li_d[282]
  PIN k_li_d[283]
    DIRECTION OUTPUT ;
    USE SIGNAL ;
    PORT
      LAYER M5 ;
        RECT  57.312 0 57.336 0.084 ;
    END
  END k_li_d[283]
  PIN k_li_d[284]
    DIRECTION OUTPUT ;
    USE SIGNAL ;
    PORT
      LAYER M5 ;
        RECT  57.504 0 57.528 0.084 ;
    END
  END k_li_d[284]
  PIN k_li_d[285]
    DIRECTION OUTPUT ;
    USE SIGNAL ;
    PORT
      LAYER M5 ;
        RECT  57.648 0 57.672 0.084 ;
    END
  END k_li_d[285]
  PIN k_li_d[286]
    DIRECTION OUTPUT ;
    USE SIGNAL ;
    PORT
      LAYER M5 ;
        RECT  57.84 0 57.864 0.084 ;
    END
  END k_li_d[286]
  PIN k_li_d[287]
    DIRECTION OUTPUT ;
    USE SIGNAL ;
    PORT
      LAYER M5 ;
        RECT  57.936 0 57.96 0.084 ;
    END
  END k_li_d[287]
  PIN k_li_d[288]
    DIRECTION OUTPUT ;
    USE SIGNAL ;
    PORT
      LAYER M5 ;
        RECT  57.984 0 58.008 0.084 ;
    END
  END k_li_d[288]
  PIN k_li_d[289]
    DIRECTION OUTPUT ;
    USE SIGNAL ;
    PORT
      LAYER M5 ;
        RECT  58.032 0 58.056 0.084 ;
    END
  END k_li_d[289]
  PIN k_li_d[28]
    DIRECTION OUTPUT ;
    USE SIGNAL ;
    PORT
      LAYER M5 ;
        RECT  11.616 0 11.64 0.084 ;
    END
  END k_li_d[28]
  PIN k_li_d[290]
    DIRECTION OUTPUT ;
    USE SIGNAL ;
    PORT
      LAYER M5 ;
        RECT  58.608 0 58.632 0.084 ;
    END
  END k_li_d[290]
  PIN k_li_d[291]
    DIRECTION OUTPUT ;
    USE SIGNAL ;
    PORT
      LAYER M5 ;
        RECT  58.752 0 58.776 0.084 ;
    END
  END k_li_d[291]
  PIN k_li_d[292]
    DIRECTION OUTPUT ;
    USE SIGNAL ;
    PORT
      LAYER M5 ;
        RECT  58.944 0 58.968 0.084 ;
    END
  END k_li_d[292]
  PIN k_li_d[293]
    DIRECTION OUTPUT ;
    USE SIGNAL ;
    PORT
      LAYER M5 ;
        RECT  59.088 0 59.112 0.084 ;
    END
  END k_li_d[293]
  PIN k_li_d[294]
    DIRECTION OUTPUT ;
    USE SIGNAL ;
    PORT
      LAYER M5 ;
        RECT  59.28 0 59.304 0.084 ;
    END
  END k_li_d[294]
  PIN k_li_d[295]
    DIRECTION OUTPUT ;
    USE SIGNAL ;
    PORT
      LAYER M5 ;
        RECT  59.472 0 59.496 0.084 ;
    END
  END k_li_d[295]
  PIN k_li_d[296]
    DIRECTION OUTPUT ;
    USE SIGNAL ;
    PORT
      LAYER M5 ;
        RECT  59.664 0 59.688 0.084 ;
    END
  END k_li_d[296]
  PIN k_li_d[297]
    DIRECTION OUTPUT ;
    USE SIGNAL ;
    PORT
      LAYER M5 ;
        RECT  59.808 0 59.832 0.084 ;
    END
  END k_li_d[297]
  PIN k_li_d[298]
    DIRECTION OUTPUT ;
    USE SIGNAL ;
    PORT
      LAYER M5 ;
        RECT  60 0 60.024 0.084 ;
    END
  END k_li_d[298]
  PIN k_li_d[299]
    DIRECTION OUTPUT ;
    USE SIGNAL ;
    PORT
      LAYER M5 ;
        RECT  60.192 0 60.216 0.084 ;
    END
  END k_li_d[299]
  PIN k_li_d[29]
    DIRECTION OUTPUT ;
    USE SIGNAL ;
    PORT
      LAYER M5 ;
        RECT  11.76 0 11.784 0.084 ;
    END
  END k_li_d[29]
  PIN k_li_d[2]
    DIRECTION OUTPUT ;
    USE SIGNAL ;
    PORT
      LAYER M5 ;
        RECT  6.96 0 6.984 0.084 ;
    END
  END k_li_d[2]
  PIN k_li_d[300]
    DIRECTION OUTPUT ;
    USE SIGNAL ;
    PORT
      LAYER M5 ;
        RECT  60.384 0 60.408 0.084 ;
    END
  END k_li_d[300]
  PIN k_li_d[301]
    DIRECTION OUTPUT ;
    USE SIGNAL ;
    PORT
      LAYER M5 ;
        RECT  60.528 0 60.552 0.084 ;
    END
  END k_li_d[301]
  PIN k_li_d[302]
    DIRECTION OUTPUT ;
    USE SIGNAL ;
    PORT
      LAYER M5 ;
        RECT  60.72 0 60.744 0.084 ;
    END
  END k_li_d[302]
  PIN k_li_d[303]
    DIRECTION OUTPUT ;
    USE SIGNAL ;
    PORT
      LAYER M5 ;
        RECT  60.912 0 60.936 0.084 ;
    END
  END k_li_d[303]
  PIN k_li_d[304]
    DIRECTION OUTPUT ;
    USE SIGNAL ;
    PORT
      LAYER M5 ;
        RECT  61.056 0 61.08 0.084 ;
    END
  END k_li_d[304]
  PIN k_li_d[305]
    DIRECTION OUTPUT ;
    USE SIGNAL ;
    PORT
      LAYER M5 ;
        RECT  61.248 0 61.272 0.084 ;
    END
  END k_li_d[305]
  PIN k_li_d[306]
    DIRECTION OUTPUT ;
    USE SIGNAL ;
    PORT
      LAYER M5 ;
        RECT  61.44 0 61.464 0.084 ;
    END
  END k_li_d[306]
  PIN k_li_d[307]
    DIRECTION OUTPUT ;
    USE SIGNAL ;
    PORT
      LAYER M5 ;
        RECT  61.632 0 61.656 0.084 ;
    END
  END k_li_d[307]
  PIN k_li_d[308]
    DIRECTION OUTPUT ;
    USE SIGNAL ;
    PORT
      LAYER M5 ;
        RECT  61.776 0 61.8 0.084 ;
    END
  END k_li_d[308]
  PIN k_li_d[309]
    DIRECTION OUTPUT ;
    USE SIGNAL ;
    PORT
      LAYER M5 ;
        RECT  61.968 0 61.992 0.084 ;
    END
  END k_li_d[309]
  PIN k_li_d[30]
    DIRECTION OUTPUT ;
    USE SIGNAL ;
    PORT
      LAYER M5 ;
        RECT  11.952 0 11.976 0.084 ;
    END
  END k_li_d[30]
  PIN k_li_d[310]
    DIRECTION OUTPUT ;
    USE SIGNAL ;
    PORT
      LAYER M5 ;
        RECT  62.16 0 62.184 0.084 ;
    END
  END k_li_d[310]
  PIN k_li_d[311]
    DIRECTION OUTPUT ;
    USE SIGNAL ;
    PORT
      LAYER M5 ;
        RECT  62.256 0 62.28 0.084 ;
    END
  END k_li_d[311]
  PIN k_li_d[312]
    DIRECTION OUTPUT ;
    USE SIGNAL ;
    PORT
      LAYER M5 ;
        RECT  62.304 0 62.328 0.084 ;
    END
  END k_li_d[312]
  PIN k_li_d[313]
    DIRECTION OUTPUT ;
    USE SIGNAL ;
    PORT
      LAYER M5 ;
        RECT  62.352 0 62.376 0.084 ;
    END
  END k_li_d[313]
  PIN k_li_d[314]
    DIRECTION OUTPUT ;
    USE SIGNAL ;
    PORT
      LAYER M5 ;
        RECT  62.928 0 62.952 0.084 ;
    END
  END k_li_d[314]
  PIN k_li_d[315]
    DIRECTION OUTPUT ;
    USE SIGNAL ;
    PORT
      LAYER M5 ;
        RECT  63.072 0 63.096 0.084 ;
    END
  END k_li_d[315]
  PIN k_li_d[316]
    DIRECTION OUTPUT ;
    USE SIGNAL ;
    PORT
      LAYER M5 ;
        RECT  63.216 0 63.24 0.084 ;
    END
  END k_li_d[316]
  PIN k_li_d[317]
    DIRECTION OUTPUT ;
    USE SIGNAL ;
    PORT
      LAYER M5 ;
        RECT  63.408 0 63.432 0.084 ;
    END
  END k_li_d[317]
  PIN k_li_d[318]
    DIRECTION OUTPUT ;
    USE SIGNAL ;
    PORT
      LAYER M5 ;
        RECT  63.6 0 63.624 0.084 ;
    END
  END k_li_d[318]
  PIN k_li_d[319]
    DIRECTION OUTPUT ;
    USE SIGNAL ;
    PORT
      LAYER M5 ;
        RECT  63.744 0 63.768 0.084 ;
    END
  END k_li_d[319]
  PIN k_li_d[31]
    DIRECTION OUTPUT ;
    USE SIGNAL ;
    PORT
      LAYER M5 ;
        RECT  12.144 0 12.168 0.084 ;
    END
  END k_li_d[31]
  PIN k_li_d[320]
    DIRECTION OUTPUT ;
    USE SIGNAL ;
    PORT
      LAYER M5 ;
        RECT  63.936 0 63.96 0.084 ;
    END
  END k_li_d[320]
  PIN k_li_d[321]
    DIRECTION OUTPUT ;
    USE SIGNAL ;
    PORT
      LAYER M5 ;
        RECT  64.128 0 64.152 0.084 ;
    END
  END k_li_d[321]
  PIN k_li_d[322]
    DIRECTION OUTPUT ;
    USE SIGNAL ;
    PORT
      LAYER M5 ;
        RECT  64.32 0 64.344 0.084 ;
    END
  END k_li_d[322]
  PIN k_li_d[323]
    DIRECTION OUTPUT ;
    USE SIGNAL ;
    PORT
      LAYER M5 ;
        RECT  64.464 0 64.488 0.084 ;
    END
  END k_li_d[323]
  PIN k_li_d[324]
    DIRECTION OUTPUT ;
    USE SIGNAL ;
    PORT
      LAYER M5 ;
        RECT  64.656 0 64.68 0.084 ;
    END
  END k_li_d[324]
  PIN k_li_d[325]
    DIRECTION OUTPUT ;
    USE SIGNAL ;
    PORT
      LAYER M5 ;
        RECT  64.848 0 64.872 0.084 ;
    END
  END k_li_d[325]
  PIN k_li_d[326]
    DIRECTION OUTPUT ;
    USE SIGNAL ;
    PORT
      LAYER M5 ;
        RECT  65.04 0 65.064 0.084 ;
    END
  END k_li_d[326]
  PIN k_li_d[327]
    DIRECTION OUTPUT ;
    USE SIGNAL ;
    PORT
      LAYER M5 ;
        RECT  65.184 0 65.208 0.084 ;
    END
  END k_li_d[327]
  PIN k_li_d[328]
    DIRECTION OUTPUT ;
    USE SIGNAL ;
    PORT
      LAYER M5 ;
        RECT  65.376 0 65.4 0.084 ;
    END
  END k_li_d[328]
  PIN k_li_d[329]
    DIRECTION OUTPUT ;
    USE SIGNAL ;
    PORT
      LAYER M5 ;
        RECT  65.568 0 65.592 0.084 ;
    END
  END k_li_d[329]
  PIN k_li_d[32]
    DIRECTION OUTPUT ;
    USE SIGNAL ;
    PORT
      LAYER M5 ;
        RECT  12.336 0 12.36 0.084 ;
    END
  END k_li_d[32]
  PIN k_li_d[330]
    DIRECTION OUTPUT ;
    USE SIGNAL ;
    PORT
      LAYER M5 ;
        RECT  65.76 0 65.784 0.084 ;
    END
  END k_li_d[330]
  PIN k_li_d[331]
    DIRECTION OUTPUT ;
    USE SIGNAL ;
    PORT
      LAYER M5 ;
        RECT  65.904 0 65.928 0.084 ;
    END
  END k_li_d[331]
  PIN k_li_d[332]
    DIRECTION OUTPUT ;
    USE SIGNAL ;
    PORT
      LAYER M5 ;
        RECT  66.096 0 66.12 0.084 ;
    END
  END k_li_d[332]
  PIN k_li_d[333]
    DIRECTION OUTPUT ;
    USE SIGNAL ;
    PORT
      LAYER M5 ;
        RECT  66.288 0 66.312 0.084 ;
    END
  END k_li_d[333]
  PIN k_li_d[334]
    DIRECTION OUTPUT ;
    USE SIGNAL ;
    PORT
      LAYER M5 ;
        RECT  66.432 0 66.456 0.084 ;
    END
  END k_li_d[334]
  PIN k_li_d[335]
    DIRECTION OUTPUT ;
    USE SIGNAL ;
    PORT
      LAYER M5 ;
        RECT  66.576 0 66.6 0.084 ;
    END
  END k_li_d[335]
  PIN k_li_d[336]
    DIRECTION OUTPUT ;
    USE SIGNAL ;
    PORT
      LAYER M5 ;
        RECT  66.624 0 66.648 0.084 ;
    END
  END k_li_d[336]
  PIN k_li_d[337]
    DIRECTION OUTPUT ;
    USE SIGNAL ;
    PORT
      LAYER M5 ;
        RECT  66.672 0 66.696 0.084 ;
    END
  END k_li_d[337]
  PIN k_li_d[338]
    DIRECTION OUTPUT ;
    USE SIGNAL ;
    PORT
      LAYER M5 ;
        RECT  67.248 0 67.272 0.084 ;
    END
  END k_li_d[338]
  PIN k_li_d[339]
    DIRECTION OUTPUT ;
    USE SIGNAL ;
    PORT
      LAYER M5 ;
        RECT  67.344 0 67.368 0.084 ;
    END
  END k_li_d[339]
  PIN k_li_d[33]
    DIRECTION OUTPUT ;
    USE SIGNAL ;
    PORT
      LAYER M5 ;
        RECT  12.48 0 12.504 0.084 ;
    END
  END k_li_d[33]
  PIN k_li_d[340]
    DIRECTION OUTPUT ;
    USE SIGNAL ;
    PORT
      LAYER M5 ;
        RECT  67.536 0 67.56 0.084 ;
    END
  END k_li_d[340]
  PIN k_li_d[341]
    DIRECTION OUTPUT ;
    USE SIGNAL ;
    PORT
      LAYER M5 ;
        RECT  67.728 0 67.752 0.084 ;
    END
  END k_li_d[341]
  PIN k_li_d[342]
    DIRECTION OUTPUT ;
    USE SIGNAL ;
    PORT
      LAYER M5 ;
        RECT  67.872 0 67.896 0.084 ;
    END
  END k_li_d[342]
  PIN k_li_d[343]
    DIRECTION OUTPUT ;
    USE SIGNAL ;
    PORT
      LAYER M5 ;
        RECT  68.064 0 68.088 0.084 ;
    END
  END k_li_d[343]
  PIN k_li_d[344]
    DIRECTION OUTPUT ;
    USE SIGNAL ;
    PORT
      LAYER M5 ;
        RECT  68.256 0 68.28 0.084 ;
    END
  END k_li_d[344]
  PIN k_li_d[345]
    DIRECTION OUTPUT ;
    USE SIGNAL ;
    PORT
      LAYER M5 ;
        RECT  68.448 0 68.472 0.084 ;
    END
  END k_li_d[345]
  PIN k_li_d[346]
    DIRECTION OUTPUT ;
    USE SIGNAL ;
    PORT
      LAYER M5 ;
        RECT  68.592 0 68.616 0.084 ;
    END
  END k_li_d[346]
  PIN k_li_d[347]
    DIRECTION OUTPUT ;
    USE SIGNAL ;
    PORT
      LAYER M5 ;
        RECT  68.784 0 68.808 0.084 ;
    END
  END k_li_d[347]
  PIN k_li_d[348]
    DIRECTION OUTPUT ;
    USE SIGNAL ;
    PORT
      LAYER M5 ;
        RECT  68.976 0 69 0.084 ;
    END
  END k_li_d[348]
  PIN k_li_d[349]
    DIRECTION OUTPUT ;
    USE SIGNAL ;
    PORT
      LAYER M5 ;
        RECT  69.168 0 69.192 0.084 ;
    END
  END k_li_d[349]
  PIN k_li_d[34]
    DIRECTION OUTPUT ;
    USE SIGNAL ;
    PORT
      LAYER M5 ;
        RECT  12.672 0 12.696 0.084 ;
    END
  END k_li_d[34]
  PIN k_li_d[350]
    DIRECTION OUTPUT ;
    USE SIGNAL ;
    PORT
      LAYER M5 ;
        RECT  69.312 0 69.336 0.084 ;
    END
  END k_li_d[350]
  PIN k_li_d[351]
    DIRECTION OUTPUT ;
    USE SIGNAL ;
    PORT
      LAYER M5 ;
        RECT  69.504 0 69.528 0.084 ;
    END
  END k_li_d[351]
  PIN k_li_d[352]
    DIRECTION OUTPUT ;
    USE SIGNAL ;
    PORT
      LAYER M5 ;
        RECT  69.696 0 69.72 0.084 ;
    END
  END k_li_d[352]
  PIN k_li_d[353]
    DIRECTION OUTPUT ;
    USE SIGNAL ;
    PORT
      LAYER M5 ;
        RECT  69.84 0 69.864 0.084 ;
    END
  END k_li_d[353]
  PIN k_li_d[354]
    DIRECTION OUTPUT ;
    USE SIGNAL ;
    PORT
      LAYER M5 ;
        RECT  70.032 0 70.056 0.084 ;
    END
  END k_li_d[354]
  PIN k_li_d[355]
    DIRECTION OUTPUT ;
    USE SIGNAL ;
    PORT
      LAYER M5 ;
        RECT  70.224 0 70.248 0.084 ;
    END
  END k_li_d[355]
  PIN k_li_d[356]
    DIRECTION OUTPUT ;
    USE SIGNAL ;
    PORT
      LAYER M5 ;
        RECT  70.416 0 70.44 0.084 ;
    END
  END k_li_d[356]
  PIN k_li_d[357]
    DIRECTION OUTPUT ;
    USE SIGNAL ;
    PORT
      LAYER M5 ;
        RECT  70.56 0 70.584 0.084 ;
    END
  END k_li_d[357]
  PIN k_li_d[358]
    DIRECTION OUTPUT ;
    USE SIGNAL ;
    PORT
      LAYER M5 ;
        RECT  70.752 0 70.776 0.084 ;
    END
  END k_li_d[358]
  PIN k_li_d[359]
    DIRECTION OUTPUT ;
    USE SIGNAL ;
    PORT
      LAYER M5 ;
        RECT  70.896 0 70.92 0.084 ;
    END
  END k_li_d[359]
  PIN k_li_d[35]
    DIRECTION OUTPUT ;
    USE SIGNAL ;
    PORT
      LAYER M5 ;
        RECT  12.864 0 12.888 0.084 ;
    END
  END k_li_d[35]
  PIN k_li_d[360]
    DIRECTION OUTPUT ;
    USE SIGNAL ;
    PORT
      LAYER M5 ;
        RECT  70.944 0 70.968 0.084 ;
    END
  END k_li_d[360]
  PIN k_li_d[361]
    DIRECTION OUTPUT ;
    USE SIGNAL ;
    PORT
      LAYER M5 ;
        RECT  70.992 0 71.016 0.084 ;
    END
  END k_li_d[361]
  PIN k_li_d[362]
    DIRECTION OUTPUT ;
    USE SIGNAL ;
    PORT
      LAYER M5 ;
        RECT  71.568 0 71.592 0.084 ;
    END
  END k_li_d[362]
  PIN k_li_d[363]
    DIRECTION OUTPUT ;
    USE SIGNAL ;
    PORT
      LAYER M5 ;
        RECT  71.664 0 71.688 0.084 ;
    END
  END k_li_d[363]
  PIN k_li_d[364]
    DIRECTION OUTPUT ;
    USE SIGNAL ;
    PORT
      LAYER M5 ;
        RECT  71.856 0 71.88 0.084 ;
    END
  END k_li_d[364]
  PIN k_li_d[365]
    DIRECTION OUTPUT ;
    USE SIGNAL ;
    PORT
      LAYER M5 ;
        RECT  72 0 72.024 0.084 ;
    END
  END k_li_d[365]
  PIN k_li_d[366]
    DIRECTION OUTPUT ;
    USE SIGNAL ;
    PORT
      LAYER M5 ;
        RECT  72.192 0 72.216 0.084 ;
    END
  END k_li_d[366]
  PIN k_li_d[367]
    DIRECTION OUTPUT ;
    USE SIGNAL ;
    PORT
      LAYER M5 ;
        RECT  72.384 0 72.408 0.084 ;
    END
  END k_li_d[367]
  PIN k_li_d[368]
    DIRECTION OUTPUT ;
    USE SIGNAL ;
    PORT
      LAYER M5 ;
        RECT  72.528 0 72.552 0.084 ;
    END
  END k_li_d[368]
  PIN k_li_d[369]
    DIRECTION OUTPUT ;
    USE SIGNAL ;
    PORT
      LAYER M5 ;
        RECT  72.72 0 72.744 0.084 ;
    END
  END k_li_d[369]
  PIN k_li_d[36]
    DIRECTION OUTPUT ;
    USE SIGNAL ;
    PORT
      LAYER M5 ;
        RECT  13.056 0 13.08 0.084 ;
    END
  END k_li_d[36]
  PIN k_li_d[370]
    DIRECTION OUTPUT ;
    USE SIGNAL ;
    PORT
      LAYER M5 ;
        RECT  72.912 0 72.936 0.084 ;
    END
  END k_li_d[370]
  PIN k_li_d[371]
    DIRECTION OUTPUT ;
    USE SIGNAL ;
    PORT
      LAYER M5 ;
        RECT  73.104 0 73.128 0.084 ;
    END
  END k_li_d[371]
  PIN k_li_d[372]
    DIRECTION OUTPUT ;
    USE SIGNAL ;
    PORT
      LAYER M5 ;
        RECT  73.248 0 73.272 0.084 ;
    END
  END k_li_d[372]
  PIN k_li_d[373]
    DIRECTION OUTPUT ;
    USE SIGNAL ;
    PORT
      LAYER M5 ;
        RECT  73.44 0 73.464 0.084 ;
    END
  END k_li_d[373]
  PIN k_li_d[374]
    DIRECTION OUTPUT ;
    USE SIGNAL ;
    PORT
      LAYER M5 ;
        RECT  73.632 0 73.656 0.084 ;
    END
  END k_li_d[374]
  PIN k_li_d[375]
    DIRECTION OUTPUT ;
    USE SIGNAL ;
    PORT
      LAYER M5 ;
        RECT  73.824 0 73.848 0.084 ;
    END
  END k_li_d[375]
  PIN k_li_d[376]
    DIRECTION OUTPUT ;
    USE SIGNAL ;
    PORT
      LAYER M5 ;
        RECT  73.968 0 73.992 0.084 ;
    END
  END k_li_d[376]
  PIN k_li_d[377]
    DIRECTION OUTPUT ;
    USE SIGNAL ;
    PORT
      LAYER M5 ;
        RECT  74.16 0 74.184 0.084 ;
    END
  END k_li_d[377]
  PIN k_li_d[378]
    DIRECTION OUTPUT ;
    USE SIGNAL ;
    PORT
      LAYER M5 ;
        RECT  74.352 0 74.376 0.084 ;
    END
  END k_li_d[378]
  PIN k_li_d[379]
    DIRECTION OUTPUT ;
    USE SIGNAL ;
    PORT
      LAYER M5 ;
        RECT  74.544 0 74.568 0.084 ;
    END
  END k_li_d[379]
  PIN k_li_d[37]
    DIRECTION OUTPUT ;
    USE SIGNAL ;
    PORT
      LAYER M5 ;
        RECT  13.2 0 13.224 0.084 ;
    END
  END k_li_d[37]
  PIN k_li_d[380]
    DIRECTION OUTPUT ;
    USE SIGNAL ;
    PORT
      LAYER M5 ;
        RECT  74.688 0 74.712 0.084 ;
    END
  END k_li_d[380]
  PIN k_li_d[381]
    DIRECTION OUTPUT ;
    USE SIGNAL ;
    PORT
      LAYER M5 ;
        RECT  74.88 0 74.904 0.084 ;
    END
  END k_li_d[381]
  PIN k_li_d[382]
    DIRECTION OUTPUT ;
    USE SIGNAL ;
    PORT
      LAYER M5 ;
        RECT  75.072 0 75.096 0.084 ;
    END
  END k_li_d[382]
  PIN k_li_d[383]
    DIRECTION OUTPUT ;
    USE SIGNAL ;
    PORT
      LAYER M5 ;
        RECT  75.216 0 75.24 0.084 ;
    END
  END k_li_d[383]
  PIN k_li_d[384]
    DIRECTION OUTPUT ;
    USE SIGNAL ;
    PORT
      LAYER M5 ;
        RECT  75.264 0 75.288 0.084 ;
    END
  END k_li_d[384]
  PIN k_li_d[385]
    DIRECTION OUTPUT ;
    USE SIGNAL ;
    PORT
      LAYER M5 ;
        RECT  75.312 0 75.336 0.084 ;
    END
  END k_li_d[385]
  PIN k_li_d[386]
    DIRECTION OUTPUT ;
    USE SIGNAL ;
    PORT
      LAYER M5 ;
        RECT  75.888 0 75.912 0.084 ;
    END
  END k_li_d[386]
  PIN k_li_d[387]
    DIRECTION OUTPUT ;
    USE SIGNAL ;
    PORT
      LAYER M5 ;
        RECT  75.936 0 75.96 0.084 ;
    END
  END k_li_d[387]
  PIN k_li_d[388]
    DIRECTION OUTPUT ;
    USE SIGNAL ;
    PORT
      LAYER M5 ;
        RECT  76.128 0 76.152 0.084 ;
    END
  END k_li_d[388]
  PIN k_li_d[389]
    DIRECTION OUTPUT ;
    USE SIGNAL ;
    PORT
      LAYER M5 ;
        RECT  76.32 0 76.344 0.084 ;
    END
  END k_li_d[389]
  PIN k_li_d[38]
    DIRECTION OUTPUT ;
    USE SIGNAL ;
    PORT
      LAYER M5 ;
        RECT  13.392 0 13.416 0.084 ;
    END
  END k_li_d[38]
  PIN k_li_d[390]
    DIRECTION OUTPUT ;
    USE SIGNAL ;
    PORT
      LAYER M5 ;
        RECT  76.512 0 76.536 0.084 ;
    END
  END k_li_d[390]
  PIN k_li_d[391]
    DIRECTION OUTPUT ;
    USE SIGNAL ;
    PORT
      LAYER M5 ;
        RECT  76.656 0 76.68 0.084 ;
    END
  END k_li_d[391]
  PIN k_li_d[392]
    DIRECTION OUTPUT ;
    USE SIGNAL ;
    PORT
      LAYER M5 ;
        RECT  76.848 0 76.872 0.084 ;
    END
  END k_li_d[392]
  PIN k_li_d[393]
    DIRECTION OUTPUT ;
    USE SIGNAL ;
    PORT
      LAYER M5 ;
        RECT  77.04 0 77.064 0.084 ;
    END
  END k_li_d[393]
  PIN k_li_d[394]
    DIRECTION OUTPUT ;
    USE SIGNAL ;
    PORT
      LAYER M5 ;
        RECT  77.232 0 77.256 0.084 ;
    END
  END k_li_d[394]
  PIN k_li_d[395]
    DIRECTION OUTPUT ;
    USE SIGNAL ;
    PORT
      LAYER M5 ;
        RECT  77.376 0 77.4 0.084 ;
    END
  END k_li_d[395]
  PIN k_li_d[396]
    DIRECTION OUTPUT ;
    USE SIGNAL ;
    PORT
      LAYER M5 ;
        RECT  77.568 0 77.592 0.084 ;
    END
  END k_li_d[396]
  PIN k_li_d[397]
    DIRECTION OUTPUT ;
    USE SIGNAL ;
    PORT
      LAYER M5 ;
        RECT  77.76 0 77.784 0.084 ;
    END
  END k_li_d[397]
  PIN k_li_d[398]
    DIRECTION OUTPUT ;
    USE SIGNAL ;
    PORT
      LAYER M5 ;
        RECT  77.952 0 77.976 0.084 ;
    END
  END k_li_d[398]
  PIN k_li_d[399]
    DIRECTION OUTPUT ;
    USE SIGNAL ;
    PORT
      LAYER M5 ;
        RECT  78.096 0 78.12 0.084 ;
    END
  END k_li_d[399]
  PIN k_li_d[39]
    DIRECTION OUTPUT ;
    USE SIGNAL ;
    PORT
      LAYER M5 ;
        RECT  13.584 0 13.608 0.084 ;
    END
  END k_li_d[39]
  PIN k_li_d[3]
    DIRECTION OUTPUT ;
    USE SIGNAL ;
    PORT
      LAYER M5 ;
        RECT  7.104 0 7.128 0.084 ;
    END
  END k_li_d[3]
  PIN k_li_d[400]
    DIRECTION OUTPUT ;
    USE SIGNAL ;
    PORT
      LAYER M5 ;
        RECT  78.288 0 78.312 0.084 ;
    END
  END k_li_d[400]
  PIN k_li_d[401]
    DIRECTION OUTPUT ;
    USE SIGNAL ;
    PORT
      LAYER M5 ;
        RECT  78.48 0 78.504 0.084 ;
    END
  END k_li_d[401]
  PIN k_li_d[402]
    DIRECTION OUTPUT ;
    USE SIGNAL ;
    PORT
      LAYER M5 ;
        RECT  78.624 0 78.648 0.084 ;
    END
  END k_li_d[402]
  PIN k_li_d[403]
    DIRECTION OUTPUT ;
    USE SIGNAL ;
    PORT
      LAYER M5 ;
        RECT  78.816 0 78.84 0.084 ;
    END
  END k_li_d[403]
  PIN k_li_d[404]
    DIRECTION OUTPUT ;
    USE SIGNAL ;
    PORT
      LAYER M5 ;
        RECT  79.008 0 79.032 0.084 ;
    END
  END k_li_d[404]
  PIN k_li_d[405]
    DIRECTION OUTPUT ;
    USE SIGNAL ;
    PORT
      LAYER M5 ;
        RECT  79.2 0 79.224 0.084 ;
    END
  END k_li_d[405]
  PIN k_li_d[406]
    DIRECTION OUTPUT ;
    USE SIGNAL ;
    PORT
      LAYER M5 ;
        RECT  79.344 0 79.368 0.084 ;
    END
  END k_li_d[406]
  PIN k_li_d[407]
    DIRECTION OUTPUT ;
    USE SIGNAL ;
    PORT
      LAYER M5 ;
        RECT  79.536 0 79.56 0.084 ;
    END
  END k_li_d[407]
  PIN k_li_d[408]
    DIRECTION OUTPUT ;
    USE SIGNAL ;
    PORT
      LAYER M5 ;
        RECT  79.584 0 79.608 0.084 ;
    END
  END k_li_d[408]
  PIN k_li_d[409]
    DIRECTION OUTPUT ;
    USE SIGNAL ;
    PORT
      LAYER M5 ;
        RECT  79.632 0 79.656 0.084 ;
    END
  END k_li_d[409]
  PIN k_li_d[40]
    DIRECTION OUTPUT ;
    USE SIGNAL ;
    PORT
      LAYER M5 ;
        RECT  13.728 0 13.752 0.084 ;
    END
  END k_li_d[40]
  PIN k_li_d[410]
    DIRECTION OUTPUT ;
    USE SIGNAL ;
    PORT
      LAYER M5 ;
        RECT  80.208 0 80.232 0.084 ;
    END
  END k_li_d[410]
  PIN k_li_d[411]
    DIRECTION OUTPUT ;
    USE SIGNAL ;
    PORT
      LAYER M5 ;
        RECT  80.256 0 80.28 0.084 ;
    END
  END k_li_d[411]
  PIN k_li_d[412]
    DIRECTION OUTPUT ;
    USE SIGNAL ;
    PORT
      LAYER M5 ;
        RECT  80.448 0 80.472 0.084 ;
    END
  END k_li_d[412]
  PIN k_li_d[413]
    DIRECTION OUTPUT ;
    USE SIGNAL ;
    PORT
      LAYER M5 ;
        RECT  80.64 0 80.664 0.084 ;
    END
  END k_li_d[413]
  PIN k_li_d[414]
    DIRECTION OUTPUT ;
    USE SIGNAL ;
    PORT
      LAYER M5 ;
        RECT  80.784 0 80.808 0.084 ;
    END
  END k_li_d[414]
  PIN k_li_d[415]
    DIRECTION OUTPUT ;
    USE SIGNAL ;
    PORT
      LAYER M5 ;
        RECT  80.976 0 81 0.084 ;
    END
  END k_li_d[415]
  PIN k_li_d[416]
    DIRECTION OUTPUT ;
    USE SIGNAL ;
    PORT
      LAYER M5 ;
        RECT  81.168 0 81.192 0.084 ;
    END
  END k_li_d[416]
  PIN k_li_d[417]
    DIRECTION OUTPUT ;
    USE SIGNAL ;
    PORT
      LAYER M5 ;
        RECT  81.312 0 81.336 0.084 ;
    END
  END k_li_d[417]
  PIN k_li_d[418]
    DIRECTION OUTPUT ;
    USE SIGNAL ;
    PORT
      LAYER M5 ;
        RECT  81.504 0 81.528 0.084 ;
    END
  END k_li_d[418]
  PIN k_li_d[419]
    DIRECTION OUTPUT ;
    USE SIGNAL ;
    PORT
      LAYER M5 ;
        RECT  81.696 0 81.72 0.084 ;
    END
  END k_li_d[419]
  PIN k_li_d[41]
    DIRECTION OUTPUT ;
    USE SIGNAL ;
    PORT
      LAYER M5 ;
        RECT  13.92 0 13.944 0.084 ;
    END
  END k_li_d[41]
  PIN k_li_d[420]
    DIRECTION OUTPUT ;
    USE SIGNAL ;
    PORT
      LAYER M5 ;
        RECT  81.888 0 81.912 0.084 ;
    END
  END k_li_d[420]
  PIN k_li_d[421]
    DIRECTION OUTPUT ;
    USE SIGNAL ;
    PORT
      LAYER M5 ;
        RECT  82.032 0 82.056 0.084 ;
    END
  END k_li_d[421]
  PIN k_li_d[422]
    DIRECTION OUTPUT ;
    USE SIGNAL ;
    PORT
      LAYER M5 ;
        RECT  82.224 0 82.248 0.084 ;
    END
  END k_li_d[422]
  PIN k_li_d[423]
    DIRECTION OUTPUT ;
    USE SIGNAL ;
    PORT
      LAYER M5 ;
        RECT  82.416 0 82.44 0.084 ;
    END
  END k_li_d[423]
  PIN k_li_d[424]
    DIRECTION OUTPUT ;
    USE SIGNAL ;
    PORT
      LAYER M5 ;
        RECT  82.608 0 82.632 0.084 ;
    END
  END k_li_d[424]
  PIN k_li_d[425]
    DIRECTION OUTPUT ;
    USE SIGNAL ;
    PORT
      LAYER M5 ;
        RECT  82.752 0 82.776 0.084 ;
    END
  END k_li_d[425]
  PIN k_li_d[426]
    DIRECTION OUTPUT ;
    USE SIGNAL ;
    PORT
      LAYER M5 ;
        RECT  82.944 0 82.968 0.084 ;
    END
  END k_li_d[426]
  PIN k_li_d[427]
    DIRECTION OUTPUT ;
    USE SIGNAL ;
    PORT
      LAYER M5 ;
        RECT  83.136 0 83.16 0.084 ;
    END
  END k_li_d[427]
  PIN k_li_d[428]
    DIRECTION OUTPUT ;
    USE SIGNAL ;
    PORT
      LAYER M5 ;
        RECT  83.328 0 83.352 0.084 ;
    END
  END k_li_d[428]
  PIN k_li_d[429]
    DIRECTION OUTPUT ;
    USE SIGNAL ;
    PORT
      LAYER M5 ;
        RECT  83.472 0 83.496 0.084 ;
    END
  END k_li_d[429]
  PIN k_li_d[42]
    DIRECTION OUTPUT ;
    USE SIGNAL ;
    PORT
      LAYER M5 ;
        RECT  14.112 0 14.136 0.084 ;
    END
  END k_li_d[42]
  PIN k_li_d[430]
    DIRECTION OUTPUT ;
    USE SIGNAL ;
    PORT
      LAYER M5 ;
        RECT  83.664 0 83.688 0.084 ;
    END
  END k_li_d[430]
  PIN k_li_d[431]
    DIRECTION OUTPUT ;
    USE SIGNAL ;
    PORT
      LAYER M5 ;
        RECT  83.856 0 83.88 0.084 ;
    END
  END k_li_d[431]
  PIN k_li_d[432]
    DIRECTION OUTPUT ;
    USE SIGNAL ;
    PORT
      LAYER M5 ;
        RECT  83.904 0 83.928 0.084 ;
    END
  END k_li_d[432]
  PIN k_li_d[433]
    DIRECTION OUTPUT ;
    USE SIGNAL ;
    PORT
      LAYER M5 ;
        RECT  83.952 0 83.976 0.084 ;
    END
  END k_li_d[433]
  PIN k_li_d[434]
    DIRECTION OUTPUT ;
    USE SIGNAL ;
    PORT
      LAYER M5 ;
        RECT  84.528 0 84.552 0.084 ;
    END
  END k_li_d[434]
  PIN k_li_d[435]
    DIRECTION OUTPUT ;
    USE SIGNAL ;
    PORT
      LAYER M5 ;
        RECT  84.576 0 84.6 0.084 ;
    END
  END k_li_d[435]
  PIN k_li_d[436]
    DIRECTION OUTPUT ;
    USE SIGNAL ;
    PORT
      LAYER M5 ;
        RECT  84.72 0 84.744 0.084 ;
    END
  END k_li_d[436]
  PIN k_li_d[437]
    DIRECTION OUTPUT ;
    USE SIGNAL ;
    PORT
      LAYER M5 ;
        RECT  84.912 0 84.936 0.084 ;
    END
  END k_li_d[437]
  PIN k_li_d[438]
    DIRECTION OUTPUT ;
    USE SIGNAL ;
    PORT
      LAYER M5 ;
        RECT  85.104 0 85.128 0.084 ;
    END
  END k_li_d[438]
  PIN k_li_d[439]
    DIRECTION OUTPUT ;
    USE SIGNAL ;
    PORT
      LAYER M5 ;
        RECT  85.296 0 85.32 0.084 ;
    END
  END k_li_d[439]
  PIN k_li_d[43]
    DIRECTION OUTPUT ;
    USE SIGNAL ;
    PORT
      LAYER M5 ;
        RECT  14.304 0 14.328 0.084 ;
    END
  END k_li_d[43]
  PIN k_li_d[440]
    DIRECTION OUTPUT ;
    USE SIGNAL ;
    PORT
      LAYER M5 ;
        RECT  85.44 0 85.464 0.084 ;
    END
  END k_li_d[440]
  PIN k_li_d[441]
    DIRECTION OUTPUT ;
    USE SIGNAL ;
    PORT
      LAYER M5 ;
        RECT  85.632 0 85.656 0.084 ;
    END
  END k_li_d[441]
  PIN k_li_d[442]
    DIRECTION OUTPUT ;
    USE SIGNAL ;
    PORT
      LAYER M5 ;
        RECT  85.824 0 85.848 0.084 ;
    END
  END k_li_d[442]
  PIN k_li_d[443]
    DIRECTION OUTPUT ;
    USE SIGNAL ;
    PORT
      LAYER M5 ;
        RECT  86.016 0 86.04 0.084 ;
    END
  END k_li_d[443]
  PIN k_li_d[444]
    DIRECTION OUTPUT ;
    USE SIGNAL ;
    PORT
      LAYER M5 ;
        RECT  86.16 0 86.184 0.084 ;
    END
  END k_li_d[444]
  PIN k_li_d[445]
    DIRECTION OUTPUT ;
    USE SIGNAL ;
    PORT
      LAYER M5 ;
        RECT  86.352 0 86.376 0.084 ;
    END
  END k_li_d[445]
  PIN k_li_d[446]
    DIRECTION OUTPUT ;
    USE SIGNAL ;
    PORT
      LAYER M5 ;
        RECT  86.544 0 86.568 0.084 ;
    END
  END k_li_d[446]
  PIN k_li_d[447]
    DIRECTION OUTPUT ;
    USE SIGNAL ;
    PORT
      LAYER M5 ;
        RECT  86.736 0 86.76 0.084 ;
    END
  END k_li_d[447]
  PIN k_li_d[448]
    DIRECTION OUTPUT ;
    USE SIGNAL ;
    PORT
      LAYER M5 ;
        RECT  86.88 0 86.904 0.084 ;
    END
  END k_li_d[448]
  PIN k_li_d[449]
    DIRECTION OUTPUT ;
    USE SIGNAL ;
    PORT
      LAYER M5 ;
        RECT  87.072 0 87.096 0.084 ;
    END
  END k_li_d[449]
  PIN k_li_d[44]
    DIRECTION OUTPUT ;
    USE SIGNAL ;
    PORT
      LAYER M5 ;
        RECT  14.448 0 14.472 0.084 ;
    END
  END k_li_d[44]
  PIN k_li_d[450]
    DIRECTION OUTPUT ;
    USE SIGNAL ;
    PORT
      LAYER M5 ;
        RECT  87.264 0 87.288 0.084 ;
    END
  END k_li_d[450]
  PIN k_li_d[451]
    DIRECTION OUTPUT ;
    USE SIGNAL ;
    PORT
      LAYER M5 ;
        RECT  87.408 0 87.432 0.084 ;
    END
  END k_li_d[451]
  PIN k_li_d[452]
    DIRECTION OUTPUT ;
    USE SIGNAL ;
    PORT
      LAYER M5 ;
        RECT  87.6 0 87.624 0.084 ;
    END
  END k_li_d[452]
  PIN k_li_d[453]
    DIRECTION OUTPUT ;
    USE SIGNAL ;
    PORT
      LAYER M5 ;
        RECT  87.792 0 87.816 0.084 ;
    END
  END k_li_d[453]
  PIN k_li_d[454]
    DIRECTION OUTPUT ;
    USE SIGNAL ;
    PORT
      LAYER M5 ;
        RECT  87.984 0 88.008 0.084 ;
    END
  END k_li_d[454]
  PIN k_li_d[455]
    DIRECTION OUTPUT ;
    USE SIGNAL ;
    PORT
      LAYER M5 ;
        RECT  88.128 0 88.152 0.084 ;
    END
  END k_li_d[455]
  PIN k_li_d[456]
    DIRECTION OUTPUT ;
    USE SIGNAL ;
    PORT
      LAYER M5 ;
        RECT  88.176 0 88.2 0.084 ;
    END
  END k_li_d[456]
  PIN k_li_d[457]
    DIRECTION OUTPUT ;
    USE SIGNAL ;
    PORT
      LAYER M5 ;
        RECT  88.224 0 88.248 0.084 ;
    END
  END k_li_d[457]
  PIN k_li_d[458]
    DIRECTION OUTPUT ;
    USE SIGNAL ;
    PORT
      LAYER M5 ;
        RECT  88.272 0 88.296 0.084 ;
    END
  END k_li_d[458]
  PIN k_li_d[459]
    DIRECTION OUTPUT ;
    USE SIGNAL ;
    PORT
      LAYER M5 ;
        RECT  88.848 0 88.872 0.084 ;
    END
  END k_li_d[459]
  PIN k_li_d[45]
    DIRECTION OUTPUT ;
    USE SIGNAL ;
    PORT
      LAYER M5 ;
        RECT  14.64 0 14.664 0.084 ;
    END
  END k_li_d[45]
  PIN k_li_d[460]
    DIRECTION OUTPUT ;
    USE SIGNAL ;
    PORT
      LAYER M5 ;
        RECT  89.04 0 89.064 0.084 ;
    END
  END k_li_d[460]
  PIN k_li_d[461]
    DIRECTION OUTPUT ;
    USE SIGNAL ;
    PORT
      LAYER M5 ;
        RECT  89.232 0 89.256 0.084 ;
    END
  END k_li_d[461]
  PIN k_li_d[462]
    DIRECTION OUTPUT ;
    USE SIGNAL ;
    PORT
      LAYER M5 ;
        RECT  89.424 0 89.448 0.084 ;
    END
  END k_li_d[462]
  PIN k_li_d[463]
    DIRECTION OUTPUT ;
    USE SIGNAL ;
    PORT
      LAYER M5 ;
        RECT  89.568 0 89.592 0.084 ;
    END
  END k_li_d[463]
  PIN k_li_d[464]
    DIRECTION OUTPUT ;
    USE SIGNAL ;
    PORT
      LAYER M5 ;
        RECT  89.76 0 89.784 0.084 ;
    END
  END k_li_d[464]
  PIN k_li_d[465]
    DIRECTION OUTPUT ;
    USE SIGNAL ;
    PORT
      LAYER M5 ;
        RECT  89.952 0 89.976 0.084 ;
    END
  END k_li_d[465]
  PIN k_li_d[466]
    DIRECTION OUTPUT ;
    USE SIGNAL ;
    PORT
      LAYER M5 ;
        RECT  90.096 0 90.12 0.084 ;
    END
  END k_li_d[466]
  PIN k_li_d[467]
    DIRECTION OUTPUT ;
    USE SIGNAL ;
    PORT
      LAYER M5 ;
        RECT  90.288 0 90.312 0.084 ;
    END
  END k_li_d[467]
  PIN k_li_d[468]
    DIRECTION OUTPUT ;
    USE SIGNAL ;
    PORT
      LAYER M5 ;
        RECT  90.48 0 90.504 0.084 ;
    END
  END k_li_d[468]
  PIN k_li_d[469]
    DIRECTION OUTPUT ;
    USE SIGNAL ;
    PORT
      LAYER M5 ;
        RECT  90.672 0 90.696 0.084 ;
    END
  END k_li_d[469]
  PIN k_li_d[46]
    DIRECTION OUTPUT ;
    USE SIGNAL ;
    PORT
      LAYER M5 ;
        RECT  14.832 0 14.856 0.084 ;
    END
  END k_li_d[46]
  PIN k_li_d[470]
    DIRECTION OUTPUT ;
    USE SIGNAL ;
    PORT
      LAYER M5 ;
        RECT  90.816 0 90.84 0.084 ;
    END
  END k_li_d[470]
  PIN k_li_d[471]
    DIRECTION OUTPUT ;
    USE SIGNAL ;
    PORT
      LAYER M5 ;
        RECT  91.008 0 91.032 0.084 ;
    END
  END k_li_d[471]
  PIN k_li_d[472]
    DIRECTION OUTPUT ;
    USE SIGNAL ;
    PORT
      LAYER M5 ;
        RECT  91.2 0 91.224 0.084 ;
    END
  END k_li_d[472]
  PIN k_li_d[473]
    DIRECTION OUTPUT ;
    USE SIGNAL ;
    PORT
      LAYER M5 ;
        RECT  91.392 0 91.416 0.084 ;
    END
  END k_li_d[473]
  PIN k_li_d[474]
    DIRECTION OUTPUT ;
    USE SIGNAL ;
    PORT
      LAYER M5 ;
        RECT  91.536 0 91.56 0.084 ;
    END
  END k_li_d[474]
  PIN k_li_d[475]
    DIRECTION OUTPUT ;
    USE SIGNAL ;
    PORT
      LAYER M5 ;
        RECT  91.728 0 91.752 0.084 ;
    END
  END k_li_d[475]
  PIN k_li_d[476]
    DIRECTION OUTPUT ;
    USE SIGNAL ;
    PORT
      LAYER M5 ;
        RECT  91.92 0 91.944 0.084 ;
    END
  END k_li_d[476]
  PIN k_li_d[477]
    DIRECTION OUTPUT ;
    USE SIGNAL ;
    PORT
      LAYER M5 ;
        RECT  92.112 0 92.136 0.084 ;
    END
  END k_li_d[477]
  PIN k_li_d[478]
    DIRECTION OUTPUT ;
    USE SIGNAL ;
    PORT
      LAYER M5 ;
        RECT  92.256 0 92.28 0.084 ;
    END
  END k_li_d[478]
  PIN k_li_d[479]
    DIRECTION OUTPUT ;
    USE SIGNAL ;
    PORT
      LAYER M5 ;
        RECT  92.448 0 92.472 0.084 ;
    END
  END k_li_d[479]
  PIN k_li_d[47]
    DIRECTION OUTPUT ;
    USE SIGNAL ;
    PORT
      LAYER M5 ;
        RECT  15.408 0 15.432 0.084 ;
    END
  END k_li_d[47]
  PIN k_li_d[480]
    DIRECTION OUTPUT ;
    USE SIGNAL ;
    PORT
      LAYER M5 ;
        RECT  92.496 0 92.52 0.084 ;
    END
  END k_li_d[480]
  PIN k_li_d[481]
    DIRECTION OUTPUT ;
    USE SIGNAL ;
    PORT
      LAYER M5 ;
        RECT  92.544 0 92.568 0.084 ;
    END
  END k_li_d[481]
  PIN k_li_d[482]
    DIRECTION OUTPUT ;
    USE SIGNAL ;
    PORT
      LAYER M5 ;
        RECT  92.592 0 92.616 0.084 ;
    END
  END k_li_d[482]
  PIN k_li_d[483]
    DIRECTION OUTPUT ;
    USE SIGNAL ;
    PORT
      LAYER M5 ;
        RECT  93.168 0 93.192 0.084 ;
    END
  END k_li_d[483]
  PIN k_li_d[484]
    DIRECTION OUTPUT ;
    USE SIGNAL ;
    PORT
      LAYER M5 ;
        RECT  93.36 0 93.384 0.084 ;
    END
  END k_li_d[484]
  PIN k_li_d[485]
    DIRECTION OUTPUT ;
    USE SIGNAL ;
    PORT
      LAYER M5 ;
        RECT  93.504 0 93.528 0.084 ;
    END
  END k_li_d[485]
  PIN k_li_d[486]
    DIRECTION OUTPUT ;
    USE SIGNAL ;
    PORT
      LAYER M5 ;
        RECT  93.696 0 93.72 0.084 ;
    END
  END k_li_d[486]
  PIN k_li_d[487]
    DIRECTION OUTPUT ;
    USE SIGNAL ;
    PORT
      LAYER M5 ;
        RECT  93.888 0 93.912 0.084 ;
    END
  END k_li_d[487]
  PIN k_li_d[488]
    DIRECTION OUTPUT ;
    USE SIGNAL ;
    PORT
      LAYER M5 ;
        RECT  94.08 0 94.104 0.084 ;
    END
  END k_li_d[488]
  PIN k_li_d[489]
    DIRECTION OUTPUT ;
    USE SIGNAL ;
    PORT
      LAYER M5 ;
        RECT  94.224 0 94.248 0.084 ;
    END
  END k_li_d[489]
  PIN k_li_d[48]
    DIRECTION OUTPUT ;
    USE SIGNAL ;
    PORT
      LAYER M5 ;
        RECT  15.456 0 15.48 0.084 ;
    END
  END k_li_d[48]
  PIN k_li_d[490]
    DIRECTION OUTPUT ;
    USE SIGNAL ;
    PORT
      LAYER M5 ;
        RECT  94.416 0 94.44 0.084 ;
    END
  END k_li_d[490]
  PIN k_li_d[491]
    DIRECTION OUTPUT ;
    USE SIGNAL ;
    PORT
      LAYER M5 ;
        RECT  94.608 0 94.632 0.084 ;
    END
  END k_li_d[491]
  PIN k_li_d[492]
    DIRECTION OUTPUT ;
    USE SIGNAL ;
    PORT
      LAYER M5 ;
        RECT  94.8 0 94.824 0.084 ;
    END
  END k_li_d[492]
  PIN k_li_d[493]
    DIRECTION OUTPUT ;
    USE SIGNAL ;
    PORT
      LAYER M5 ;
        RECT  94.944 0 94.968 0.084 ;
    END
  END k_li_d[493]
  PIN k_li_d[494]
    DIRECTION OUTPUT ;
    USE SIGNAL ;
    PORT
      LAYER M5 ;
        RECT  95.136 0 95.16 0.084 ;
    END
  END k_li_d[494]
  PIN k_li_d[495]
    DIRECTION OUTPUT ;
    USE SIGNAL ;
    PORT
      LAYER M5 ;
        RECT  95.328 0 95.352 0.084 ;
    END
  END k_li_d[495]
  PIN k_li_d[496]
    DIRECTION OUTPUT ;
    USE SIGNAL ;
    PORT
      LAYER M5 ;
        RECT  95.52 0 95.544 0.084 ;
    END
  END k_li_d[496]
  PIN k_li_d[497]
    DIRECTION OUTPUT ;
    USE SIGNAL ;
    PORT
      LAYER M5 ;
        RECT  95.664 0 95.688 0.084 ;
    END
  END k_li_d[497]
  PIN k_li_d[498]
    DIRECTION OUTPUT ;
    USE SIGNAL ;
    PORT
      LAYER M5 ;
        RECT  95.856 0 95.88 0.084 ;
    END
  END k_li_d[498]
  PIN k_li_d[499]
    DIRECTION OUTPUT ;
    USE SIGNAL ;
    PORT
      LAYER M5 ;
        RECT  96.048 0 96.072 0.084 ;
    END
  END k_li_d[499]
  PIN k_li_d[49]
    DIRECTION OUTPUT ;
    USE SIGNAL ;
    PORT
      LAYER M5 ;
        RECT  15.504 0 15.528 0.084 ;
    END
  END k_li_d[49]
  PIN k_li_d[4]
    DIRECTION OUTPUT ;
    USE SIGNAL ;
    PORT
      LAYER M5 ;
        RECT  7.296 0 7.32 0.084 ;
    END
  END k_li_d[4]
  PIN k_li_d[500]
    DIRECTION OUTPUT ;
    USE SIGNAL ;
    PORT
      LAYER M5 ;
        RECT  96.192 0 96.216 0.084 ;
    END
  END k_li_d[500]
  PIN k_li_d[501]
    DIRECTION OUTPUT ;
    USE SIGNAL ;
    PORT
      LAYER M5 ;
        RECT  96.384 0 96.408 0.084 ;
    END
  END k_li_d[501]
  PIN k_li_d[502]
    DIRECTION OUTPUT ;
    USE SIGNAL ;
    PORT
      LAYER M5 ;
        RECT  96.576 0 96.6 0.084 ;
    END
  END k_li_d[502]
  PIN k_li_d[503]
    DIRECTION OUTPUT ;
    USE SIGNAL ;
    PORT
      LAYER M5 ;
        RECT  96.768 0 96.792 0.084 ;
    END
  END k_li_d[503]
  PIN k_li_d[504]
    DIRECTION OUTPUT ;
    USE SIGNAL ;
    PORT
      LAYER M5 ;
        RECT  96.816 0 96.84 0.084 ;
    END
  END k_li_d[504]
  PIN k_li_d[505]
    DIRECTION OUTPUT ;
    USE SIGNAL ;
    PORT
      LAYER M5 ;
        RECT  96.864 0 96.888 0.084 ;
    END
  END k_li_d[505]
  PIN k_li_d[506]
    DIRECTION OUTPUT ;
    USE SIGNAL ;
    PORT
      LAYER M5 ;
        RECT  96.912 0 96.936 0.084 ;
    END
  END k_li_d[506]
  PIN k_li_d[507]
    DIRECTION OUTPUT ;
    USE SIGNAL ;
    PORT
      LAYER M5 ;
        RECT  97.488 0 97.512 0.084 ;
    END
  END k_li_d[507]
  PIN k_li_d[508]
    DIRECTION OUTPUT ;
    USE SIGNAL ;
    PORT
      LAYER M5 ;
        RECT  97.632 0 97.656 0.084 ;
    END
  END k_li_d[508]
  PIN k_li_d[509]
    DIRECTION OUTPUT ;
    USE SIGNAL ;
    PORT
      LAYER M5 ;
        RECT  97.824 0 97.848 0.084 ;
    END
  END k_li_d[509]
  PIN k_li_d[50]
    DIRECTION OUTPUT ;
    USE SIGNAL ;
    PORT
      LAYER M5 ;
        RECT  15.552 0 15.576 0.084 ;
    END
  END k_li_d[50]
  PIN k_li_d[510]
    DIRECTION OUTPUT ;
    USE SIGNAL ;
    PORT
      LAYER M5 ;
        RECT  98.016 0 98.04 0.084 ;
    END
  END k_li_d[510]
  PIN k_li_d[511]
    DIRECTION OUTPUT ;
    USE SIGNAL ;
    PORT
      LAYER M5 ;
        RECT  98.208 0 98.232 0.084 ;
    END
  END k_li_d[511]
  PIN k_li_d[512]
    DIRECTION OUTPUT ;
    USE SIGNAL ;
    PORT
      LAYER M5 ;
        RECT  98.352 0 98.376 0.084 ;
    END
  END k_li_d[512]
  PIN k_li_d[513]
    DIRECTION OUTPUT ;
    USE SIGNAL ;
    PORT
      LAYER M5 ;
        RECT  98.544 0 98.568 0.084 ;
    END
  END k_li_d[513]
  PIN k_li_d[514]
    DIRECTION OUTPUT ;
    USE SIGNAL ;
    PORT
      LAYER M5 ;
        RECT  98.736 0 98.76 0.084 ;
    END
  END k_li_d[514]
  PIN k_li_d[515]
    DIRECTION OUTPUT ;
    USE SIGNAL ;
    PORT
      LAYER M5 ;
        RECT  98.88 0 98.904 0.084 ;
    END
  END k_li_d[515]
  PIN k_li_d[516]
    DIRECTION OUTPUT ;
    USE SIGNAL ;
    PORT
      LAYER M5 ;
        RECT  99.072 0 99.096 0.084 ;
    END
  END k_li_d[516]
  PIN k_li_d[517]
    DIRECTION OUTPUT ;
    USE SIGNAL ;
    PORT
      LAYER M5 ;
        RECT  99.264 0 99.288 0.084 ;
    END
  END k_li_d[517]
  PIN k_li_d[518]
    DIRECTION OUTPUT ;
    USE SIGNAL ;
    PORT
      LAYER M5 ;
        RECT  99.456 0 99.48 0.084 ;
    END
  END k_li_d[518]
  PIN k_li_d[519]
    DIRECTION OUTPUT ;
    USE SIGNAL ;
    PORT
      LAYER M5 ;
        RECT  99.6 0 99.624 0.084 ;
    END
  END k_li_d[519]
  PIN k_li_d[51]
    DIRECTION OUTPUT ;
    USE SIGNAL ;
    PORT
      LAYER M5 ;
        RECT  15.744 0 15.768 0.084 ;
    END
  END k_li_d[51]
  PIN k_li_d[520]
    DIRECTION OUTPUT ;
    USE SIGNAL ;
    PORT
      LAYER M5 ;
        RECT  99.792 0 99.816 0.084 ;
    END
  END k_li_d[520]
  PIN k_li_d[521]
    DIRECTION OUTPUT ;
    USE SIGNAL ;
    PORT
      LAYER M5 ;
        RECT  99.984 0 100.008 0.084 ;
    END
  END k_li_d[521]
  PIN k_li_d[522]
    DIRECTION OUTPUT ;
    USE SIGNAL ;
    PORT
      LAYER M5 ;
        RECT  100.176 0 100.2 0.084 ;
    END
  END k_li_d[522]
  PIN k_li_d[523]
    DIRECTION OUTPUT ;
    USE SIGNAL ;
    PORT
      LAYER M5 ;
        RECT  100.32 0 100.344 0.084 ;
    END
  END k_li_d[523]
  PIN k_li_d[524]
    DIRECTION OUTPUT ;
    USE SIGNAL ;
    PORT
      LAYER M5 ;
        RECT  100.512 0 100.536 0.084 ;
    END
  END k_li_d[524]
  PIN k_li_d[525]
    DIRECTION OUTPUT ;
    USE SIGNAL ;
    PORT
      LAYER M5 ;
        RECT  100.704 0 100.728 0.084 ;
    END
  END k_li_d[525]
  PIN k_li_d[526]
    DIRECTION OUTPUT ;
    USE SIGNAL ;
    PORT
      LAYER M5 ;
        RECT  100.896 0 100.92 0.084 ;
    END
  END k_li_d[526]
  PIN k_li_d[527]
    DIRECTION OUTPUT ;
    USE SIGNAL ;
    PORT
      LAYER M5 ;
        RECT  101.04 0 101.064 0.084 ;
    END
  END k_li_d[527]
  PIN k_li_d[528]
    DIRECTION OUTPUT ;
    USE SIGNAL ;
    PORT
      LAYER M5 ;
        RECT  101.136 0 101.16 0.084 ;
    END
  END k_li_d[528]
  PIN k_li_d[529]
    DIRECTION OUTPUT ;
    USE SIGNAL ;
    PORT
      LAYER M5 ;
        RECT  101.184 0 101.208 0.084 ;
    END
  END k_li_d[529]
  PIN k_li_d[52]
    DIRECTION OUTPUT ;
    USE SIGNAL ;
    PORT
      LAYER M5 ;
        RECT  15.888 0 15.912 0.084 ;
    END
  END k_li_d[52]
  PIN k_li_d[530]
    DIRECTION OUTPUT ;
    USE SIGNAL ;
    PORT
      LAYER M5 ;
        RECT  101.232 0 101.256 0.084 ;
    END
  END k_li_d[530]
  PIN k_li_d[531]
    DIRECTION OUTPUT ;
    USE SIGNAL ;
    PORT
      LAYER M5 ;
        RECT  101.808 0 101.832 0.084 ;
    END
  END k_li_d[531]
  PIN k_li_d[532]
    DIRECTION OUTPUT ;
    USE SIGNAL ;
    PORT
      LAYER M5 ;
        RECT  101.952 0 101.976 0.084 ;
    END
  END k_li_d[532]
  PIN k_li_d[533]
    DIRECTION OUTPUT ;
    USE SIGNAL ;
    PORT
      LAYER M5 ;
        RECT  102.144 0 102.168 0.084 ;
    END
  END k_li_d[533]
  PIN k_li_d[534]
    DIRECTION OUTPUT ;
    USE SIGNAL ;
    PORT
      LAYER M5 ;
        RECT  102.288 0 102.312 0.084 ;
    END
  END k_li_d[534]
  PIN k_li_d[535]
    DIRECTION OUTPUT ;
    USE SIGNAL ;
    PORT
      LAYER M5 ;
        RECT  102.48 0 102.504 0.084 ;
    END
  END k_li_d[535]
  PIN k_li_d[536]
    DIRECTION OUTPUT ;
    USE SIGNAL ;
    PORT
      LAYER M5 ;
        RECT  102.672 0 102.696 0.084 ;
    END
  END k_li_d[536]
  PIN k_li_d[537]
    DIRECTION OUTPUT ;
    USE SIGNAL ;
    PORT
      LAYER M5 ;
        RECT  102.864 0 102.888 0.084 ;
    END
  END k_li_d[537]
  PIN k_li_d[538]
    DIRECTION OUTPUT ;
    USE SIGNAL ;
    PORT
      LAYER M5 ;
        RECT  103.008 0 103.032 0.084 ;
    END
  END k_li_d[538]
  PIN k_li_d[539]
    DIRECTION OUTPUT ;
    USE SIGNAL ;
    PORT
      LAYER M5 ;
        RECT  103.2 0 103.224 0.084 ;
    END
  END k_li_d[539]
  PIN k_li_d[53]
    DIRECTION OUTPUT ;
    USE SIGNAL ;
    PORT
      LAYER M5 ;
        RECT  16.08 0 16.104 0.084 ;
    END
  END k_li_d[53]
  PIN k_li_d[540]
    DIRECTION OUTPUT ;
    USE SIGNAL ;
    PORT
      LAYER M5 ;
        RECT  103.392 0 103.416 0.084 ;
    END
  END k_li_d[540]
  PIN k_li_d[541]
    DIRECTION OUTPUT ;
    USE SIGNAL ;
    PORT
      LAYER M5 ;
        RECT  103.584 0 103.608 0.084 ;
    END
  END k_li_d[541]
  PIN k_li_d[542]
    DIRECTION OUTPUT ;
    USE SIGNAL ;
    PORT
      LAYER M5 ;
        RECT  103.728 0 103.752 0.084 ;
    END
  END k_li_d[542]
  PIN k_li_d[543]
    DIRECTION OUTPUT ;
    USE SIGNAL ;
    PORT
      LAYER M5 ;
        RECT  103.92 0 103.944 0.084 ;
    END
  END k_li_d[543]
  PIN k_li_d[544]
    DIRECTION OUTPUT ;
    USE SIGNAL ;
    PORT
      LAYER M5 ;
        RECT  104.112 0 104.136 0.084 ;
    END
  END k_li_d[544]
  PIN k_li_d[545]
    DIRECTION OUTPUT ;
    USE SIGNAL ;
    PORT
      LAYER M5 ;
        RECT  104.304 0 104.328 0.084 ;
    END
  END k_li_d[545]
  PIN k_li_d[546]
    DIRECTION OUTPUT ;
    USE SIGNAL ;
    PORT
      LAYER M5 ;
        RECT  104.448 0 104.472 0.084 ;
    END
  END k_li_d[546]
  PIN k_li_d[547]
    DIRECTION OUTPUT ;
    USE SIGNAL ;
    PORT
      LAYER M5 ;
        RECT  104.64 0 104.664 0.084 ;
    END
  END k_li_d[547]
  PIN k_li_d[548]
    DIRECTION OUTPUT ;
    USE SIGNAL ;
    PORT
      LAYER M5 ;
        RECT  104.832 0 104.856 0.084 ;
    END
  END k_li_d[548]
  PIN k_li_d[549]
    DIRECTION OUTPUT ;
    USE SIGNAL ;
    PORT
      LAYER M5 ;
        RECT  104.976 0 105 0.084 ;
    END
  END k_li_d[549]
  PIN k_li_d[54]
    DIRECTION OUTPUT ;
    USE SIGNAL ;
    PORT
      LAYER M5 ;
        RECT  16.272 0 16.296 0.084 ;
    END
  END k_li_d[54]
  PIN k_li_d[550]
    DIRECTION OUTPUT ;
    USE SIGNAL ;
    PORT
      LAYER M5 ;
        RECT  105.168 0 105.192 0.084 ;
    END
  END k_li_d[550]
  PIN k_li_d[551]
    DIRECTION OUTPUT ;
    USE SIGNAL ;
    PORT
      LAYER M5 ;
        RECT  105.36 0 105.384 0.084 ;
    END
  END k_li_d[551]
  PIN k_li_d[552]
    DIRECTION OUTPUT ;
    USE SIGNAL ;
    PORT
      LAYER M5 ;
        RECT  105.456 0 105.48 0.084 ;
    END
  END k_li_d[552]
  PIN k_li_d[55]
    DIRECTION OUTPUT ;
    USE SIGNAL ;
    PORT
      LAYER M5 ;
        RECT  16.416 0 16.44 0.084 ;
    END
  END k_li_d[55]
  PIN k_li_d[56]
    DIRECTION OUTPUT ;
    USE SIGNAL ;
    PORT
      LAYER M5 ;
        RECT  16.608 0 16.632 0.084 ;
    END
  END k_li_d[56]
  PIN k_li_d[57]
    DIRECTION OUTPUT ;
    USE SIGNAL ;
    PORT
      LAYER M5 ;
        RECT  16.8 0 16.824 0.084 ;
    END
  END k_li_d[57]
  PIN k_li_d[58]
    DIRECTION OUTPUT ;
    USE SIGNAL ;
    PORT
      LAYER M5 ;
        RECT  16.992 0 17.016 0.084 ;
    END
  END k_li_d[58]
  PIN k_li_d[59]
    DIRECTION OUTPUT ;
    USE SIGNAL ;
    PORT
      LAYER M5 ;
        RECT  17.136 0 17.16 0.084 ;
    END
  END k_li_d[59]
  PIN k_li_d[5]
    DIRECTION OUTPUT ;
    USE SIGNAL ;
    PORT
      LAYER M5 ;
        RECT  7.488 0 7.512 0.084 ;
    END
  END k_li_d[5]
  PIN k_li_d[60]
    DIRECTION OUTPUT ;
    USE SIGNAL ;
    PORT
      LAYER M5 ;
        RECT  17.328 0 17.352 0.084 ;
    END
  END k_li_d[60]
  PIN k_li_d[61]
    DIRECTION OUTPUT ;
    USE SIGNAL ;
    PORT
      LAYER M5 ;
        RECT  17.52 0 17.544 0.084 ;
    END
  END k_li_d[61]
  PIN k_li_d[62]
    DIRECTION OUTPUT ;
    USE SIGNAL ;
    PORT
      LAYER M5 ;
        RECT  17.712 0 17.736 0.084 ;
    END
  END k_li_d[62]
  PIN k_li_d[63]
    DIRECTION OUTPUT ;
    USE SIGNAL ;
    PORT
      LAYER M5 ;
        RECT  17.856 0 17.88 0.084 ;
    END
  END k_li_d[63]
  PIN k_li_d[64]
    DIRECTION OUTPUT ;
    USE SIGNAL ;
    PORT
      LAYER M5 ;
        RECT  18.048 0 18.072 0.084 ;
    END
  END k_li_d[64]
  PIN k_li_d[65]
    DIRECTION OUTPUT ;
    USE SIGNAL ;
    PORT
      LAYER M5 ;
        RECT  18.24 0 18.264 0.084 ;
    END
  END k_li_d[65]
  PIN k_li_d[66]
    DIRECTION OUTPUT ;
    USE SIGNAL ;
    PORT
      LAYER M5 ;
        RECT  18.432 0 18.456 0.084 ;
    END
  END k_li_d[66]
  PIN k_li_d[67]
    DIRECTION OUTPUT ;
    USE SIGNAL ;
    PORT
      LAYER M5 ;
        RECT  18.576 0 18.6 0.084 ;
    END
  END k_li_d[67]
  PIN k_li_d[68]
    DIRECTION OUTPUT ;
    USE SIGNAL ;
    PORT
      LAYER M5 ;
        RECT  18.768 0 18.792 0.084 ;
    END
  END k_li_d[68]
  PIN k_li_d[69]
    DIRECTION OUTPUT ;
    USE SIGNAL ;
    PORT
      LAYER M5 ;
        RECT  18.96 0 18.984 0.084 ;
    END
  END k_li_d[69]
  PIN k_li_d[6]
    DIRECTION OUTPUT ;
    USE SIGNAL ;
    PORT
      LAYER M5 ;
        RECT  7.632 0 7.656 0.084 ;
    END
  END k_li_d[6]
  PIN k_li_d[70]
    DIRECTION OUTPUT ;
    USE SIGNAL ;
    PORT
      LAYER M5 ;
        RECT  19.152 0 19.176 0.084 ;
    END
  END k_li_d[70]
  PIN k_li_d[71]
    DIRECTION OUTPUT ;
    USE SIGNAL ;
    PORT
      LAYER M5 ;
        RECT  19.728 0 19.752 0.084 ;
    END
  END k_li_d[71]
  PIN k_li_d[72]
    DIRECTION OUTPUT ;
    USE SIGNAL ;
    PORT
      LAYER M5 ;
        RECT  19.776 0 19.8 0.084 ;
    END
  END k_li_d[72]
  PIN k_li_d[73]
    DIRECTION OUTPUT ;
    USE SIGNAL ;
    PORT
      LAYER M5 ;
        RECT  19.824 0 19.848 0.084 ;
    END
  END k_li_d[73]
  PIN k_li_d[74]
    DIRECTION OUTPUT ;
    USE SIGNAL ;
    PORT
      LAYER M5 ;
        RECT  19.872 0 19.896 0.084 ;
    END
  END k_li_d[74]
  PIN k_li_d[75]
    DIRECTION OUTPUT ;
    USE SIGNAL ;
    PORT
      LAYER M5 ;
        RECT  20.016 0 20.04 0.084 ;
    END
  END k_li_d[75]
  PIN k_li_d[76]
    DIRECTION OUTPUT ;
    USE SIGNAL ;
    PORT
      LAYER M5 ;
        RECT  20.208 0 20.232 0.084 ;
    END
  END k_li_d[76]
  PIN k_li_d[77]
    DIRECTION OUTPUT ;
    USE SIGNAL ;
    PORT
      LAYER M5 ;
        RECT  20.4 0 20.424 0.084 ;
    END
  END k_li_d[77]
  PIN k_li_d[78]
    DIRECTION OUTPUT ;
    USE SIGNAL ;
    PORT
      LAYER M5 ;
        RECT  20.544 0 20.568 0.084 ;
    END
  END k_li_d[78]
  PIN k_li_d[79]
    DIRECTION OUTPUT ;
    USE SIGNAL ;
    PORT
      LAYER M5 ;
        RECT  20.736 0 20.76 0.084 ;
    END
  END k_li_d[79]
  PIN k_li_d[7]
    DIRECTION OUTPUT ;
    USE SIGNAL ;
    PORT
      LAYER M5 ;
        RECT  7.824 0 7.848 0.084 ;
    END
  END k_li_d[7]
  PIN k_li_d[80]
    DIRECTION OUTPUT ;
    USE SIGNAL ;
    PORT
      LAYER M5 ;
        RECT  20.928 0 20.952 0.084 ;
    END
  END k_li_d[80]
  PIN k_li_d[81]
    DIRECTION OUTPUT ;
    USE SIGNAL ;
    PORT
      LAYER M5 ;
        RECT  21.12 0 21.144 0.084 ;
    END
  END k_li_d[81]
  PIN k_li_d[82]
    DIRECTION OUTPUT ;
    USE SIGNAL ;
    PORT
      LAYER M5 ;
        RECT  21.264 0 21.288 0.084 ;
    END
  END k_li_d[82]
  PIN k_li_d[83]
    DIRECTION OUTPUT ;
    USE SIGNAL ;
    PORT
      LAYER M5 ;
        RECT  21.456 0 21.48 0.084 ;
    END
  END k_li_d[83]
  PIN k_li_d[84]
    DIRECTION OUTPUT ;
    USE SIGNAL ;
    PORT
      LAYER M5 ;
        RECT  21.648 0 21.672 0.084 ;
    END
  END k_li_d[84]
  PIN k_li_d[85]
    DIRECTION OUTPUT ;
    USE SIGNAL ;
    PORT
      LAYER M5 ;
        RECT  21.84 0 21.864 0.084 ;
    END
  END k_li_d[85]
  PIN k_li_d[86]
    DIRECTION OUTPUT ;
    USE SIGNAL ;
    PORT
      LAYER M5 ;
        RECT  21.984 0 22.008 0.084 ;
    END
  END k_li_d[86]
  PIN k_li_d[87]
    DIRECTION OUTPUT ;
    USE SIGNAL ;
    PORT
      LAYER M5 ;
        RECT  22.176 0 22.2 0.084 ;
    END
  END k_li_d[87]
  PIN k_li_d[88]
    DIRECTION OUTPUT ;
    USE SIGNAL ;
    PORT
      LAYER M5 ;
        RECT  22.368 0 22.392 0.084 ;
    END
  END k_li_d[88]
  PIN k_li_d[89]
    DIRECTION OUTPUT ;
    USE SIGNAL ;
    PORT
      LAYER M5 ;
        RECT  22.512 0 22.536 0.084 ;
    END
  END k_li_d[89]
  PIN k_li_d[8]
    DIRECTION OUTPUT ;
    USE SIGNAL ;
    PORT
      LAYER M5 ;
        RECT  8.016 0 8.04 0.084 ;
    END
  END k_li_d[8]
  PIN k_li_d[90]
    DIRECTION OUTPUT ;
    USE SIGNAL ;
    PORT
      LAYER M5 ;
        RECT  22.704 0 22.728 0.084 ;
    END
  END k_li_d[90]
  PIN k_li_d[91]
    DIRECTION OUTPUT ;
    USE SIGNAL ;
    PORT
      LAYER M5 ;
        RECT  22.896 0 22.92 0.084 ;
    END
  END k_li_d[91]
  PIN k_li_d[92]
    DIRECTION OUTPUT ;
    USE SIGNAL ;
    PORT
      LAYER M5 ;
        RECT  23.088 0 23.112 0.084 ;
    END
  END k_li_d[92]
  PIN k_li_d[93]
    DIRECTION OUTPUT ;
    USE SIGNAL ;
    PORT
      LAYER M5 ;
        RECT  23.232 0 23.256 0.084 ;
    END
  END k_li_d[93]
  PIN k_li_d[94]
    DIRECTION OUTPUT ;
    USE SIGNAL ;
    PORT
      LAYER M5 ;
        RECT  23.424 0 23.448 0.084 ;
    END
  END k_li_d[94]
  PIN k_li_d[95]
    DIRECTION OUTPUT ;
    USE SIGNAL ;
    PORT
      LAYER M5 ;
        RECT  23.472 0 23.496 0.084 ;
    END
  END k_li_d[95]
  PIN k_li_d[96]
    DIRECTION OUTPUT ;
    USE SIGNAL ;
    PORT
      LAYER M5 ;
        RECT  24.048 0 24.072 0.084 ;
    END
  END k_li_d[96]
  PIN k_li_d[97]
    DIRECTION OUTPUT ;
    USE SIGNAL ;
    PORT
      LAYER M5 ;
        RECT  24.096 0 24.12 0.084 ;
    END
  END k_li_d[97]
  PIN k_li_d[98]
    DIRECTION OUTPUT ;
    USE SIGNAL ;
    PORT
      LAYER M5 ;
        RECT  24.144 0 24.168 0.084 ;
    END
  END k_li_d[98]
  PIN k_li_d[99]
    DIRECTION OUTPUT ;
    USE SIGNAL ;
    PORT
      LAYER M5 ;
        RECT  24.336 0 24.36 0.084 ;
    END
  END k_li_d[99]
  PIN k_li_d[9]
    DIRECTION OUTPUT ;
    USE SIGNAL ;
    PORT
      LAYER M5 ;
        RECT  8.208 0 8.232 0.084 ;
    END
  END k_li_d[9]
  PIN k_li_r
    DIRECTION INPUT ;
    USE SIGNAL ;
    PORT
      LAYER M4 ;
        RECT  0 105.888 0.084 105.912 ;
    END
  END k_li_r
  PIN k_li_v
    DIRECTION OUTPUT ;
    USE SIGNAL ;
    PORT
      LAYER M5 ;
        RECT  6.768 0 6.792 0.084 ;
    END
  END k_li_v
  PIN k_lo_d[0]
    DIRECTION INPUT ;
    USE SIGNAL ;
    PORT
      LAYER M4 ;
        RECT  0 6.384 0.084 6.408 ;
    END
  END k_lo_d[0]
  PIN k_lo_d[100]
    DIRECTION INPUT ;
    USE SIGNAL ;
    PORT
      LAYER M4 ;
        RECT  0 24.384 0.084 24.408 ;
    END
  END k_lo_d[100]
  PIN k_lo_d[101]
    DIRECTION INPUT ;
    USE SIGNAL ;
    PORT
      LAYER M4 ;
        RECT  0 24.576 0.084 24.6 ;
    END
  END k_lo_d[101]
  PIN k_lo_d[102]
    DIRECTION INPUT ;
    USE SIGNAL ;
    PORT
      LAYER M4 ;
        RECT  0 24.768 0.084 24.792 ;
    END
  END k_lo_d[102]
  PIN k_lo_d[103]
    DIRECTION INPUT ;
    USE SIGNAL ;
    PORT
      LAYER M4 ;
        RECT  0 24.912 0.084 24.936 ;
    END
  END k_lo_d[103]
  PIN k_lo_d[104]
    DIRECTION INPUT ;
    USE SIGNAL ;
    PORT
      LAYER M4 ;
        RECT  0 25.104 0.084 25.128 ;
    END
  END k_lo_d[104]
  PIN k_lo_d[105]
    DIRECTION INPUT ;
    USE SIGNAL ;
    PORT
      LAYER M4 ;
        RECT  0 25.296 0.084 25.32 ;
    END
  END k_lo_d[105]
  PIN k_lo_d[106]
    DIRECTION INPUT ;
    USE SIGNAL ;
    PORT
      LAYER M4 ;
        RECT  0 25.488 0.084 25.512 ;
    END
  END k_lo_d[106]
  PIN k_lo_d[107]
    DIRECTION INPUT ;
    USE SIGNAL ;
    PORT
      LAYER M4 ;
        RECT  0 25.632 0.084 25.656 ;
    END
  END k_lo_d[107]
  PIN k_lo_d[108]
    DIRECTION INPUT ;
    USE SIGNAL ;
    PORT
      LAYER M4 ;
        RECT  0 25.824 0.084 25.848 ;
    END
  END k_lo_d[108]
  PIN k_lo_d[109]
    DIRECTION INPUT ;
    USE SIGNAL ;
    PORT
      LAYER M4 ;
        RECT  0 26.016 0.084 26.04 ;
    END
  END k_lo_d[109]
  PIN k_lo_d[10]
    DIRECTION INPUT ;
    USE SIGNAL ;
    PORT
      LAYER M4 ;
        RECT  0 8.208 0.084 8.232 ;
    END
  END k_lo_d[10]
  PIN k_lo_d[110]
    DIRECTION INPUT ;
    USE SIGNAL ;
    PORT
      LAYER M4 ;
        RECT  0 26.208 0.084 26.232 ;
    END
  END k_lo_d[110]
  PIN k_lo_d[111]
    DIRECTION INPUT ;
    USE SIGNAL ;
    PORT
      LAYER M4 ;
        RECT  0 26.352 0.084 26.376 ;
    END
  END k_lo_d[111]
  PIN k_lo_d[112]
    DIRECTION INPUT ;
    USE SIGNAL ;
    PORT
      LAYER M4 ;
        RECT  0 26.544 0.084 26.568 ;
    END
  END k_lo_d[112]
  PIN k_lo_d[113]
    DIRECTION INPUT ;
    USE SIGNAL ;
    PORT
      LAYER M4 ;
        RECT  0 26.736 0.084 26.76 ;
    END
  END k_lo_d[113]
  PIN k_lo_d[114]
    DIRECTION INPUT ;
    USE SIGNAL ;
    PORT
      LAYER M4 ;
        RECT  0 26.928 0.084 26.952 ;
    END
  END k_lo_d[114]
  PIN k_lo_d[115]
    DIRECTION INPUT ;
    USE SIGNAL ;
    PORT
      LAYER M4 ;
        RECT  0 27.072 0.084 27.096 ;
    END
  END k_lo_d[115]
  PIN k_lo_d[116]
    DIRECTION INPUT ;
    USE SIGNAL ;
    PORT
      LAYER M4 ;
        RECT  0 27.264 0.084 27.288 ;
    END
  END k_lo_d[116]
  PIN k_lo_d[117]
    DIRECTION INPUT ;
    USE SIGNAL ;
    PORT
      LAYER M4 ;
        RECT  0 27.456 0.084 27.48 ;
    END
  END k_lo_d[117]
  PIN k_lo_d[118]
    DIRECTION INPUT ;
    USE SIGNAL ;
    PORT
      LAYER M4 ;
        RECT  0 27.648 0.084 27.672 ;
    END
  END k_lo_d[118]
  PIN k_lo_d[119]
    DIRECTION INPUT ;
    USE SIGNAL ;
    PORT
      LAYER M4 ;
        RECT  0 27.792 0.084 27.816 ;
    END
  END k_lo_d[119]
  PIN k_lo_d[11]
    DIRECTION INPUT ;
    USE SIGNAL ;
    PORT
      LAYER M4 ;
        RECT  0 8.4 0.084 8.424 ;
    END
  END k_lo_d[11]
  PIN k_lo_d[120]
    DIRECTION INPUT ;
    USE SIGNAL ;
    PORT
      LAYER M4 ;
        RECT  0 27.984 0.084 28.008 ;
    END
  END k_lo_d[120]
  PIN k_lo_d[121]
    DIRECTION INPUT ;
    USE SIGNAL ;
    PORT
      LAYER M4 ;
        RECT  0 28.176 0.084 28.2 ;
    END
  END k_lo_d[121]
  PIN k_lo_d[122]
    DIRECTION INPUT ;
    USE SIGNAL ;
    PORT
      LAYER M4 ;
        RECT  0 28.368 0.084 28.392 ;
    END
  END k_lo_d[122]
  PIN k_lo_d[123]
    DIRECTION INPUT ;
    USE SIGNAL ;
    PORT
      LAYER M4 ;
        RECT  0 28.512 0.084 28.536 ;
    END
  END k_lo_d[123]
  PIN k_lo_d[124]
    DIRECTION INPUT ;
    USE SIGNAL ;
    PORT
      LAYER M4 ;
        RECT  0 28.704 0.084 28.728 ;
    END
  END k_lo_d[124]
  PIN k_lo_d[125]
    DIRECTION INPUT ;
    USE SIGNAL ;
    PORT
      LAYER M4 ;
        RECT  0 28.896 0.084 28.92 ;
    END
  END k_lo_d[125]
  PIN k_lo_d[126]
    DIRECTION INPUT ;
    USE SIGNAL ;
    PORT
      LAYER M4 ;
        RECT  0 29.088 0.084 29.112 ;
    END
  END k_lo_d[126]
  PIN k_lo_d[127]
    DIRECTION INPUT ;
    USE SIGNAL ;
    PORT
      LAYER M4 ;
        RECT  0 29.232 0.084 29.256 ;
    END
  END k_lo_d[127]
  PIN k_lo_d[128]
    DIRECTION INPUT ;
    USE SIGNAL ;
    PORT
      LAYER M4 ;
        RECT  0 29.424 0.084 29.448 ;
    END
  END k_lo_d[128]
  PIN k_lo_d[129]
    DIRECTION INPUT ;
    USE SIGNAL ;
    PORT
      LAYER M4 ;
        RECT  0 29.616 0.084 29.64 ;
    END
  END k_lo_d[129]
  PIN k_lo_d[12]
    DIRECTION INPUT ;
    USE SIGNAL ;
    PORT
      LAYER M4 ;
        RECT  0 8.544 0.084 8.568 ;
    END
  END k_lo_d[12]
  PIN k_lo_d[130]
    DIRECTION INPUT ;
    USE SIGNAL ;
    PORT
      LAYER M4 ;
        RECT  0 29.808 0.084 29.832 ;
    END
  END k_lo_d[130]
  PIN k_lo_d[131]
    DIRECTION INPUT ;
    USE SIGNAL ;
    PORT
      LAYER M4 ;
        RECT  0 29.952 0.084 29.976 ;
    END
  END k_lo_d[131]
  PIN k_lo_d[132]
    DIRECTION INPUT ;
    USE SIGNAL ;
    PORT
      LAYER M4 ;
        RECT  0 30.144 0.084 30.168 ;
    END
  END k_lo_d[132]
  PIN k_lo_d[133]
    DIRECTION INPUT ;
    USE SIGNAL ;
    PORT
      LAYER M4 ;
        RECT  0 30.336 0.084 30.36 ;
    END
  END k_lo_d[133]
  PIN k_lo_d[134]
    DIRECTION INPUT ;
    USE SIGNAL ;
    PORT
      LAYER M4 ;
        RECT  0 30.528 0.084 30.552 ;
    END
  END k_lo_d[134]
  PIN k_lo_d[135]
    DIRECTION INPUT ;
    USE SIGNAL ;
    PORT
      LAYER M4 ;
        RECT  0 30.672 0.084 30.696 ;
    END
  END k_lo_d[135]
  PIN k_lo_d[136]
    DIRECTION INPUT ;
    USE SIGNAL ;
    PORT
      LAYER M4 ;
        RECT  0 30.864 0.084 30.888 ;
    END
  END k_lo_d[136]
  PIN k_lo_d[137]
    DIRECTION INPUT ;
    USE SIGNAL ;
    PORT
      LAYER M4 ;
        RECT  0 31.056 0.084 31.08 ;
    END
  END k_lo_d[137]
  PIN k_lo_d[138]
    DIRECTION INPUT ;
    USE SIGNAL ;
    PORT
      LAYER M4 ;
        RECT  0 31.248 0.084 31.272 ;
    END
  END k_lo_d[138]
  PIN k_lo_d[139]
    DIRECTION INPUT ;
    USE SIGNAL ;
    PORT
      LAYER M4 ;
        RECT  0 31.392 0.084 31.416 ;
    END
  END k_lo_d[139]
  PIN k_lo_d[13]
    DIRECTION INPUT ;
    USE SIGNAL ;
    PORT
      LAYER M4 ;
        RECT  0 8.736 0.084 8.76 ;
    END
  END k_lo_d[13]
  PIN k_lo_d[140]
    DIRECTION INPUT ;
    USE SIGNAL ;
    PORT
      LAYER M4 ;
        RECT  0 31.584 0.084 31.608 ;
    END
  END k_lo_d[140]
  PIN k_lo_d[141]
    DIRECTION INPUT ;
    USE SIGNAL ;
    PORT
      LAYER M4 ;
        RECT  0 31.776 0.084 31.8 ;
    END
  END k_lo_d[141]
  PIN k_lo_d[142]
    DIRECTION INPUT ;
    USE SIGNAL ;
    PORT
      LAYER M4 ;
        RECT  0 31.968 0.084 31.992 ;
    END
  END k_lo_d[142]
  PIN k_lo_d[143]
    DIRECTION INPUT ;
    USE SIGNAL ;
    PORT
      LAYER M4 ;
        RECT  0 32.112 0.084 32.136 ;
    END
  END k_lo_d[143]
  PIN k_lo_d[144]
    DIRECTION INPUT ;
    USE SIGNAL ;
    PORT
      LAYER M4 ;
        RECT  0 32.304 0.084 32.328 ;
    END
  END k_lo_d[144]
  PIN k_lo_d[145]
    DIRECTION INPUT ;
    USE SIGNAL ;
    PORT
      LAYER M4 ;
        RECT  0 32.496 0.084 32.52 ;
    END
  END k_lo_d[145]
  PIN k_lo_d[146]
    DIRECTION INPUT ;
    USE SIGNAL ;
    PORT
      LAYER M4 ;
        RECT  0 32.688 0.084 32.712 ;
    END
  END k_lo_d[146]
  PIN k_lo_d[147]
    DIRECTION INPUT ;
    USE SIGNAL ;
    PORT
      LAYER M4 ;
        RECT  0 32.832 0.084 32.856 ;
    END
  END k_lo_d[147]
  PIN k_lo_d[148]
    DIRECTION INPUT ;
    USE SIGNAL ;
    PORT
      LAYER M4 ;
        RECT  0 33.024 0.084 33.048 ;
    END
  END k_lo_d[148]
  PIN k_lo_d[149]
    DIRECTION INPUT ;
    USE SIGNAL ;
    PORT
      LAYER M4 ;
        RECT  0 33.216 0.084 33.24 ;
    END
  END k_lo_d[149]
  PIN k_lo_d[14]
    DIRECTION INPUT ;
    USE SIGNAL ;
    PORT
      LAYER M4 ;
        RECT  0 8.928 0.084 8.952 ;
    END
  END k_lo_d[14]
  PIN k_lo_d[150]
    DIRECTION INPUT ;
    USE SIGNAL ;
    PORT
      LAYER M4 ;
        RECT  0 33.408 0.084 33.432 ;
    END
  END k_lo_d[150]
  PIN k_lo_d[151]
    DIRECTION INPUT ;
    USE SIGNAL ;
    PORT
      LAYER M4 ;
        RECT  0 33.552 0.084 33.576 ;
    END
  END k_lo_d[151]
  PIN k_lo_d[152]
    DIRECTION INPUT ;
    USE SIGNAL ;
    PORT
      LAYER M4 ;
        RECT  0 33.744 0.084 33.768 ;
    END
  END k_lo_d[152]
  PIN k_lo_d[153]
    DIRECTION INPUT ;
    USE SIGNAL ;
    PORT
      LAYER M4 ;
        RECT  0 33.936 0.084 33.96 ;
    END
  END k_lo_d[153]
  PIN k_lo_d[154]
    DIRECTION INPUT ;
    USE SIGNAL ;
    PORT
      LAYER M4 ;
        RECT  0 34.128 0.084 34.152 ;
    END
  END k_lo_d[154]
  PIN k_lo_d[155]
    DIRECTION INPUT ;
    USE SIGNAL ;
    PORT
      LAYER M4 ;
        RECT  0 34.272 0.084 34.296 ;
    END
  END k_lo_d[155]
  PIN k_lo_d[156]
    DIRECTION INPUT ;
    USE SIGNAL ;
    PORT
      LAYER M4 ;
        RECT  0 34.464 0.084 34.488 ;
    END
  END k_lo_d[156]
  PIN k_lo_d[157]
    DIRECTION INPUT ;
    USE SIGNAL ;
    PORT
      LAYER M4 ;
        RECT  0 34.656 0.084 34.68 ;
    END
  END k_lo_d[157]
  PIN k_lo_d[158]
    DIRECTION INPUT ;
    USE SIGNAL ;
    PORT
      LAYER M4 ;
        RECT  0 34.848 0.084 34.872 ;
    END
  END k_lo_d[158]
  PIN k_lo_d[159]
    DIRECTION INPUT ;
    USE SIGNAL ;
    PORT
      LAYER M4 ;
        RECT  0 34.992 0.084 35.016 ;
    END
  END k_lo_d[159]
  PIN k_lo_d[15]
    DIRECTION INPUT ;
    USE SIGNAL ;
    PORT
      LAYER M4 ;
        RECT  0 9.12 0.084 9.144 ;
    END
  END k_lo_d[15]
  PIN k_lo_d[160]
    DIRECTION INPUT ;
    USE SIGNAL ;
    PORT
      LAYER M4 ;
        RECT  0 35.184 0.084 35.208 ;
    END
  END k_lo_d[160]
  PIN k_lo_d[161]
    DIRECTION INPUT ;
    USE SIGNAL ;
    PORT
      LAYER M4 ;
        RECT  0 35.376 0.084 35.4 ;
    END
  END k_lo_d[161]
  PIN k_lo_d[162]
    DIRECTION INPUT ;
    USE SIGNAL ;
    PORT
      LAYER M4 ;
        RECT  0 35.568 0.084 35.592 ;
    END
  END k_lo_d[162]
  PIN k_lo_d[163]
    DIRECTION INPUT ;
    USE SIGNAL ;
    PORT
      LAYER M4 ;
        RECT  0 35.712 0.084 35.736 ;
    END
  END k_lo_d[163]
  PIN k_lo_d[164]
    DIRECTION INPUT ;
    USE SIGNAL ;
    PORT
      LAYER M4 ;
        RECT  0 35.904 0.084 35.928 ;
    END
  END k_lo_d[164]
  PIN k_lo_d[165]
    DIRECTION INPUT ;
    USE SIGNAL ;
    PORT
      LAYER M4 ;
        RECT  0 36.096 0.084 36.12 ;
    END
  END k_lo_d[165]
  PIN k_lo_d[166]
    DIRECTION INPUT ;
    USE SIGNAL ;
    PORT
      LAYER M4 ;
        RECT  0 36.288 0.084 36.312 ;
    END
  END k_lo_d[166]
  PIN k_lo_d[167]
    DIRECTION INPUT ;
    USE SIGNAL ;
    PORT
      LAYER M4 ;
        RECT  0 36.432 0.084 36.456 ;
    END
  END k_lo_d[167]
  PIN k_lo_d[168]
    DIRECTION INPUT ;
    USE SIGNAL ;
    PORT
      LAYER M4 ;
        RECT  0 36.624 0.084 36.648 ;
    END
  END k_lo_d[168]
  PIN k_lo_d[169]
    DIRECTION INPUT ;
    USE SIGNAL ;
    PORT
      LAYER M4 ;
        RECT  0 36.816 0.084 36.84 ;
    END
  END k_lo_d[169]
  PIN k_lo_d[16]
    DIRECTION INPUT ;
    USE SIGNAL ;
    PORT
      LAYER M4 ;
        RECT  0 9.264 0.084 9.288 ;
    END
  END k_lo_d[16]
  PIN k_lo_d[170]
    DIRECTION INPUT ;
    USE SIGNAL ;
    PORT
      LAYER M4 ;
        RECT  0 37.008 0.084 37.032 ;
    END
  END k_lo_d[170]
  PIN k_lo_d[171]
    DIRECTION INPUT ;
    USE SIGNAL ;
    PORT
      LAYER M4 ;
        RECT  0 37.152 0.084 37.176 ;
    END
  END k_lo_d[171]
  PIN k_lo_d[172]
    DIRECTION INPUT ;
    USE SIGNAL ;
    PORT
      LAYER M4 ;
        RECT  0 37.344 0.084 37.368 ;
    END
  END k_lo_d[172]
  PIN k_lo_d[173]
    DIRECTION INPUT ;
    USE SIGNAL ;
    PORT
      LAYER M4 ;
        RECT  0 37.536 0.084 37.56 ;
    END
  END k_lo_d[173]
  PIN k_lo_d[174]
    DIRECTION INPUT ;
    USE SIGNAL ;
    PORT
      LAYER M4 ;
        RECT  0 37.728 0.084 37.752 ;
    END
  END k_lo_d[174]
  PIN k_lo_d[175]
    DIRECTION INPUT ;
    USE SIGNAL ;
    PORT
      LAYER M4 ;
        RECT  0 37.872 0.084 37.896 ;
    END
  END k_lo_d[175]
  PIN k_lo_d[176]
    DIRECTION INPUT ;
    USE SIGNAL ;
    PORT
      LAYER M4 ;
        RECT  0 38.064 0.084 38.088 ;
    END
  END k_lo_d[176]
  PIN k_lo_d[177]
    DIRECTION INPUT ;
    USE SIGNAL ;
    PORT
      LAYER M4 ;
        RECT  0 38.256 0.084 38.28 ;
    END
  END k_lo_d[177]
  PIN k_lo_d[178]
    DIRECTION INPUT ;
    USE SIGNAL ;
    PORT
      LAYER M4 ;
        RECT  0 38.448 0.084 38.472 ;
    END
  END k_lo_d[178]
  PIN k_lo_d[179]
    DIRECTION INPUT ;
    USE SIGNAL ;
    PORT
      LAYER M4 ;
        RECT  0 38.592 0.084 38.616 ;
    END
  END k_lo_d[179]
  PIN k_lo_d[17]
    DIRECTION INPUT ;
    USE SIGNAL ;
    PORT
      LAYER M4 ;
        RECT  0 9.456 0.084 9.48 ;
    END
  END k_lo_d[17]
  PIN k_lo_d[180]
    DIRECTION INPUT ;
    USE SIGNAL ;
    PORT
      LAYER M4 ;
        RECT  0 38.784 0.084 38.808 ;
    END
  END k_lo_d[180]
  PIN k_lo_d[181]
    DIRECTION INPUT ;
    USE SIGNAL ;
    PORT
      LAYER M4 ;
        RECT  0 38.976 0.084 39 ;
    END
  END k_lo_d[181]
  PIN k_lo_d[182]
    DIRECTION INPUT ;
    USE SIGNAL ;
    PORT
      LAYER M4 ;
        RECT  0 39.168 0.084 39.192 ;
    END
  END k_lo_d[182]
  PIN k_lo_d[183]
    DIRECTION INPUT ;
    USE SIGNAL ;
    PORT
      LAYER M4 ;
        RECT  0 39.312 0.084 39.336 ;
    END
  END k_lo_d[183]
  PIN k_lo_d[184]
    DIRECTION INPUT ;
    USE SIGNAL ;
    PORT
      LAYER M4 ;
        RECT  0 39.504 0.084 39.528 ;
    END
  END k_lo_d[184]
  PIN k_lo_d[185]
    DIRECTION INPUT ;
    USE SIGNAL ;
    PORT
      LAYER M4 ;
        RECT  0 39.696 0.084 39.72 ;
    END
  END k_lo_d[185]
  PIN k_lo_d[186]
    DIRECTION INPUT ;
    USE SIGNAL ;
    PORT
      LAYER M4 ;
        RECT  0 39.888 0.084 39.912 ;
    END
  END k_lo_d[186]
  PIN k_lo_d[187]
    DIRECTION INPUT ;
    USE SIGNAL ;
    PORT
      LAYER M4 ;
        RECT  0 40.032 0.084 40.056 ;
    END
  END k_lo_d[187]
  PIN k_lo_d[188]
    DIRECTION INPUT ;
    USE SIGNAL ;
    PORT
      LAYER M4 ;
        RECT  0 40.224 0.084 40.248 ;
    END
  END k_lo_d[188]
  PIN k_lo_d[189]
    DIRECTION INPUT ;
    USE SIGNAL ;
    PORT
      LAYER M4 ;
        RECT  0 40.416 0.084 40.44 ;
    END
  END k_lo_d[189]
  PIN k_lo_d[18]
    DIRECTION INPUT ;
    USE SIGNAL ;
    PORT
      LAYER M4 ;
        RECT  0 9.648 0.084 9.672 ;
    END
  END k_lo_d[18]
  PIN k_lo_d[190]
    DIRECTION INPUT ;
    USE SIGNAL ;
    PORT
      LAYER M4 ;
        RECT  0 40.608 0.084 40.632 ;
    END
  END k_lo_d[190]
  PIN k_lo_d[191]
    DIRECTION INPUT ;
    USE SIGNAL ;
    PORT
      LAYER M4 ;
        RECT  0 40.752 0.084 40.776 ;
    END
  END k_lo_d[191]
  PIN k_lo_d[192]
    DIRECTION INPUT ;
    USE SIGNAL ;
    PORT
      LAYER M4 ;
        RECT  0 40.944 0.084 40.968 ;
    END
  END k_lo_d[192]
  PIN k_lo_d[193]
    DIRECTION INPUT ;
    USE SIGNAL ;
    PORT
      LAYER M4 ;
        RECT  0 41.136 0.084 41.16 ;
    END
  END k_lo_d[193]
  PIN k_lo_d[194]
    DIRECTION INPUT ;
    USE SIGNAL ;
    PORT
      LAYER M4 ;
        RECT  0 41.328 0.084 41.352 ;
    END
  END k_lo_d[194]
  PIN k_lo_d[195]
    DIRECTION INPUT ;
    USE SIGNAL ;
    PORT
      LAYER M4 ;
        RECT  0 41.472 0.084 41.496 ;
    END
  END k_lo_d[195]
  PIN k_lo_d[196]
    DIRECTION INPUT ;
    USE SIGNAL ;
    PORT
      LAYER M4 ;
        RECT  0 41.664 0.084 41.688 ;
    END
  END k_lo_d[196]
  PIN k_lo_d[197]
    DIRECTION INPUT ;
    USE SIGNAL ;
    PORT
      LAYER M4 ;
        RECT  0 41.856 0.084 41.88 ;
    END
  END k_lo_d[197]
  PIN k_lo_d[198]
    DIRECTION INPUT ;
    USE SIGNAL ;
    PORT
      LAYER M4 ;
        RECT  0 42.048 0.084 42.072 ;
    END
  END k_lo_d[198]
  PIN k_lo_d[199]
    DIRECTION INPUT ;
    USE SIGNAL ;
    PORT
      LAYER M4 ;
        RECT  0 42.192 0.084 42.216 ;
    END
  END k_lo_d[199]
  PIN k_lo_d[19]
    DIRECTION INPUT ;
    USE SIGNAL ;
    PORT
      LAYER M4 ;
        RECT  0 9.84 0.084 9.864 ;
    END
  END k_lo_d[19]
  PIN k_lo_d[1]
    DIRECTION INPUT ;
    USE SIGNAL ;
    PORT
      LAYER M4 ;
        RECT  0 6.576 0.084 6.6 ;
    END
  END k_lo_d[1]
  PIN k_lo_d[200]
    DIRECTION INPUT ;
    USE SIGNAL ;
    PORT
      LAYER M4 ;
        RECT  0 42.384 0.084 42.408 ;
    END
  END k_lo_d[200]
  PIN k_lo_d[201]
    DIRECTION INPUT ;
    USE SIGNAL ;
    PORT
      LAYER M4 ;
        RECT  0 42.576 0.084 42.6 ;
    END
  END k_lo_d[201]
  PIN k_lo_d[202]
    DIRECTION INPUT ;
    USE SIGNAL ;
    PORT
      LAYER M4 ;
        RECT  0 42.768 0.084 42.792 ;
    END
  END k_lo_d[202]
  PIN k_lo_d[203]
    DIRECTION INPUT ;
    USE SIGNAL ;
    PORT
      LAYER M4 ;
        RECT  0 42.912 0.084 42.936 ;
    END
  END k_lo_d[203]
  PIN k_lo_d[204]
    DIRECTION INPUT ;
    USE SIGNAL ;
    PORT
      LAYER M4 ;
        RECT  0 43.104 0.084 43.128 ;
    END
  END k_lo_d[204]
  PIN k_lo_d[205]
    DIRECTION INPUT ;
    USE SIGNAL ;
    PORT
      LAYER M4 ;
        RECT  0 43.296 0.084 43.32 ;
    END
  END k_lo_d[205]
  PIN k_lo_d[206]
    DIRECTION INPUT ;
    USE SIGNAL ;
    PORT
      LAYER M4 ;
        RECT  0 43.488 0.084 43.512 ;
    END
  END k_lo_d[206]
  PIN k_lo_d[207]
    DIRECTION INPUT ;
    USE SIGNAL ;
    PORT
      LAYER M4 ;
        RECT  0 43.632 0.084 43.656 ;
    END
  END k_lo_d[207]
  PIN k_lo_d[208]
    DIRECTION INPUT ;
    USE SIGNAL ;
    PORT
      LAYER M4 ;
        RECT  0 43.824 0.084 43.848 ;
    END
  END k_lo_d[208]
  PIN k_lo_d[209]
    DIRECTION INPUT ;
    USE SIGNAL ;
    PORT
      LAYER M4 ;
        RECT  0 44.016 0.084 44.04 ;
    END
  END k_lo_d[209]
  PIN k_lo_d[20]
    DIRECTION INPUT ;
    USE SIGNAL ;
    PORT
      LAYER M4 ;
        RECT  0 9.984 0.084 10.008 ;
    END
  END k_lo_d[20]
  PIN k_lo_d[210]
    DIRECTION INPUT ;
    USE SIGNAL ;
    PORT
      LAYER M4 ;
        RECT  0 44.16 0.084 44.184 ;
    END
  END k_lo_d[210]
  PIN k_lo_d[211]
    DIRECTION INPUT ;
    USE SIGNAL ;
    PORT
      LAYER M4 ;
        RECT  0 44.352 0.084 44.376 ;
    END
  END k_lo_d[211]
  PIN k_lo_d[212]
    DIRECTION INPUT ;
    USE SIGNAL ;
    PORT
      LAYER M4 ;
        RECT  0 44.544 0.084 44.568 ;
    END
  END k_lo_d[212]
  PIN k_lo_d[213]
    DIRECTION INPUT ;
    USE SIGNAL ;
    PORT
      LAYER M4 ;
        RECT  0 44.736 0.084 44.76 ;
    END
  END k_lo_d[213]
  PIN k_lo_d[214]
    DIRECTION INPUT ;
    USE SIGNAL ;
    PORT
      LAYER M4 ;
        RECT  0 44.88 0.084 44.904 ;
    END
  END k_lo_d[214]
  PIN k_lo_d[215]
    DIRECTION INPUT ;
    USE SIGNAL ;
    PORT
      LAYER M4 ;
        RECT  0 45.072 0.084 45.096 ;
    END
  END k_lo_d[215]
  PIN k_lo_d[216]
    DIRECTION INPUT ;
    USE SIGNAL ;
    PORT
      LAYER M4 ;
        RECT  0 45.264 0.084 45.288 ;
    END
  END k_lo_d[216]
  PIN k_lo_d[217]
    DIRECTION INPUT ;
    USE SIGNAL ;
    PORT
      LAYER M4 ;
        RECT  0 45.456 0.084 45.48 ;
    END
  END k_lo_d[217]
  PIN k_lo_d[218]
    DIRECTION INPUT ;
    USE SIGNAL ;
    PORT
      LAYER M4 ;
        RECT  0 45.6 0.084 45.624 ;
    END
  END k_lo_d[218]
  PIN k_lo_d[219]
    DIRECTION INPUT ;
    USE SIGNAL ;
    PORT
      LAYER M4 ;
        RECT  0 45.792 0.084 45.816 ;
    END
  END k_lo_d[219]
  PIN k_lo_d[21]
    DIRECTION INPUT ;
    USE SIGNAL ;
    PORT
      LAYER M4 ;
        RECT  0 10.176 0.084 10.2 ;
    END
  END k_lo_d[21]
  PIN k_lo_d[220]
    DIRECTION INPUT ;
    USE SIGNAL ;
    PORT
      LAYER M4 ;
        RECT  0 45.984 0.084 46.008 ;
    END
  END k_lo_d[220]
  PIN k_lo_d[221]
    DIRECTION INPUT ;
    USE SIGNAL ;
    PORT
      LAYER M4 ;
        RECT  0 46.176 0.084 46.2 ;
    END
  END k_lo_d[221]
  PIN k_lo_d[222]
    DIRECTION INPUT ;
    USE SIGNAL ;
    PORT
      LAYER M4 ;
        RECT  0 46.32 0.084 46.344 ;
    END
  END k_lo_d[222]
  PIN k_lo_d[223]
    DIRECTION INPUT ;
    USE SIGNAL ;
    PORT
      LAYER M4 ;
        RECT  0 46.512 0.084 46.536 ;
    END
  END k_lo_d[223]
  PIN k_lo_d[224]
    DIRECTION INPUT ;
    USE SIGNAL ;
    PORT
      LAYER M4 ;
        RECT  0 46.704 0.084 46.728 ;
    END
  END k_lo_d[224]
  PIN k_lo_d[225]
    DIRECTION INPUT ;
    USE SIGNAL ;
    PORT
      LAYER M4 ;
        RECT  0 46.896 0.084 46.92 ;
    END
  END k_lo_d[225]
  PIN k_lo_d[226]
    DIRECTION INPUT ;
    USE SIGNAL ;
    PORT
      LAYER M4 ;
        RECT  0 47.04 0.084 47.064 ;
    END
  END k_lo_d[226]
  PIN k_lo_d[227]
    DIRECTION INPUT ;
    USE SIGNAL ;
    PORT
      LAYER M4 ;
        RECT  0 47.232 0.084 47.256 ;
    END
  END k_lo_d[227]
  PIN k_lo_d[228]
    DIRECTION INPUT ;
    USE SIGNAL ;
    PORT
      LAYER M4 ;
        RECT  0 47.424 0.084 47.448 ;
    END
  END k_lo_d[228]
  PIN k_lo_d[229]
    DIRECTION INPUT ;
    USE SIGNAL ;
    PORT
      LAYER M4 ;
        RECT  0 47.616 0.084 47.64 ;
    END
  END k_lo_d[229]
  PIN k_lo_d[22]
    DIRECTION INPUT ;
    USE SIGNAL ;
    PORT
      LAYER M4 ;
        RECT  0 10.368 0.084 10.392 ;
    END
  END k_lo_d[22]
  PIN k_lo_d[230]
    DIRECTION INPUT ;
    USE SIGNAL ;
    PORT
      LAYER M4 ;
        RECT  0 47.76 0.084 47.784 ;
    END
  END k_lo_d[230]
  PIN k_lo_d[231]
    DIRECTION INPUT ;
    USE SIGNAL ;
    PORT
      LAYER M4 ;
        RECT  0 47.952 0.084 47.976 ;
    END
  END k_lo_d[231]
  PIN k_lo_d[232]
    DIRECTION INPUT ;
    USE SIGNAL ;
    PORT
      LAYER M4 ;
        RECT  0 48.144 0.084 48.168 ;
    END
  END k_lo_d[232]
  PIN k_lo_d[233]
    DIRECTION INPUT ;
    USE SIGNAL ;
    PORT
      LAYER M4 ;
        RECT  0 48.336 0.084 48.36 ;
    END
  END k_lo_d[233]
  PIN k_lo_d[234]
    DIRECTION INPUT ;
    USE SIGNAL ;
    PORT
      LAYER M4 ;
        RECT  0 48.48 0.084 48.504 ;
    END
  END k_lo_d[234]
  PIN k_lo_d[235]
    DIRECTION INPUT ;
    USE SIGNAL ;
    PORT
      LAYER M4 ;
        RECT  0 48.672 0.084 48.696 ;
    END
  END k_lo_d[235]
  PIN k_lo_d[236]
    DIRECTION INPUT ;
    USE SIGNAL ;
    PORT
      LAYER M4 ;
        RECT  0 48.864 0.084 48.888 ;
    END
  END k_lo_d[236]
  PIN k_lo_d[237]
    DIRECTION INPUT ;
    USE SIGNAL ;
    PORT
      LAYER M4 ;
        RECT  0 49.056 0.084 49.08 ;
    END
  END k_lo_d[237]
  PIN k_lo_d[238]
    DIRECTION INPUT ;
    USE SIGNAL ;
    PORT
      LAYER M4 ;
        RECT  0 49.2 0.084 49.224 ;
    END
  END k_lo_d[238]
  PIN k_lo_d[239]
    DIRECTION INPUT ;
    USE SIGNAL ;
    PORT
      LAYER M4 ;
        RECT  0 49.392 0.084 49.416 ;
    END
  END k_lo_d[239]
  PIN k_lo_d[23]
    DIRECTION INPUT ;
    USE SIGNAL ;
    PORT
      LAYER M4 ;
        RECT  0 10.56 0.084 10.584 ;
    END
  END k_lo_d[23]
  PIN k_lo_d[240]
    DIRECTION INPUT ;
    USE SIGNAL ;
    PORT
      LAYER M4 ;
        RECT  0 49.584 0.084 49.608 ;
    END
  END k_lo_d[240]
  PIN k_lo_d[241]
    DIRECTION INPUT ;
    USE SIGNAL ;
    PORT
      LAYER M4 ;
        RECT  0 49.776 0.084 49.8 ;
    END
  END k_lo_d[241]
  PIN k_lo_d[242]
    DIRECTION INPUT ;
    USE SIGNAL ;
    PORT
      LAYER M4 ;
        RECT  0 49.92 0.084 49.944 ;
    END
  END k_lo_d[242]
  PIN k_lo_d[243]
    DIRECTION INPUT ;
    USE SIGNAL ;
    PORT
      LAYER M4 ;
        RECT  0 50.112 0.084 50.136 ;
    END
  END k_lo_d[243]
  PIN k_lo_d[244]
    DIRECTION INPUT ;
    USE SIGNAL ;
    PORT
      LAYER M4 ;
        RECT  0 50.304 0.084 50.328 ;
    END
  END k_lo_d[244]
  PIN k_lo_d[245]
    DIRECTION INPUT ;
    USE SIGNAL ;
    PORT
      LAYER M4 ;
        RECT  0 50.496 0.084 50.52 ;
    END
  END k_lo_d[245]
  PIN k_lo_d[246]
    DIRECTION INPUT ;
    USE SIGNAL ;
    PORT
      LAYER M4 ;
        RECT  0 50.64 0.084 50.664 ;
    END
  END k_lo_d[246]
  PIN k_lo_d[247]
    DIRECTION INPUT ;
    USE SIGNAL ;
    PORT
      LAYER M4 ;
        RECT  0 50.832 0.084 50.856 ;
    END
  END k_lo_d[247]
  PIN k_lo_d[248]
    DIRECTION INPUT ;
    USE SIGNAL ;
    PORT
      LAYER M4 ;
        RECT  0 51.024 0.084 51.048 ;
    END
  END k_lo_d[248]
  PIN k_lo_d[249]
    DIRECTION INPUT ;
    USE SIGNAL ;
    PORT
      LAYER M4 ;
        RECT  0 51.216 0.084 51.24 ;
    END
  END k_lo_d[249]
  PIN k_lo_d[24]
    DIRECTION INPUT ;
    USE SIGNAL ;
    PORT
      LAYER M4 ;
        RECT  0 10.704 0.084 10.728 ;
    END
  END k_lo_d[24]
  PIN k_lo_d[250]
    DIRECTION INPUT ;
    USE SIGNAL ;
    PORT
      LAYER M4 ;
        RECT  0 51.36 0.084 51.384 ;
    END
  END k_lo_d[250]
  PIN k_lo_d[251]
    DIRECTION INPUT ;
    USE SIGNAL ;
    PORT
      LAYER M4 ;
        RECT  0 51.552 0.084 51.576 ;
    END
  END k_lo_d[251]
  PIN k_lo_d[252]
    DIRECTION INPUT ;
    USE SIGNAL ;
    PORT
      LAYER M4 ;
        RECT  0 51.744 0.084 51.768 ;
    END
  END k_lo_d[252]
  PIN k_lo_d[253]
    DIRECTION INPUT ;
    USE SIGNAL ;
    PORT
      LAYER M4 ;
        RECT  0 51.936 0.084 51.96 ;
    END
  END k_lo_d[253]
  PIN k_lo_d[254]
    DIRECTION INPUT ;
    USE SIGNAL ;
    PORT
      LAYER M4 ;
        RECT  0 52.08 0.084 52.104 ;
    END
  END k_lo_d[254]
  PIN k_lo_d[255]
    DIRECTION INPUT ;
    USE SIGNAL ;
    PORT
      LAYER M4 ;
        RECT  0 52.272 0.084 52.296 ;
    END
  END k_lo_d[255]
  PIN k_lo_d[256]
    DIRECTION INPUT ;
    USE SIGNAL ;
    PORT
      LAYER M4 ;
        RECT  0 52.464 0.084 52.488 ;
    END
  END k_lo_d[256]
  PIN k_lo_d[257]
    DIRECTION INPUT ;
    USE SIGNAL ;
    PORT
      LAYER M4 ;
        RECT  0 52.656 0.084 52.68 ;
    END
  END k_lo_d[257]
  PIN k_lo_d[258]
    DIRECTION INPUT ;
    USE SIGNAL ;
    PORT
      LAYER M4 ;
        RECT  0 52.8 0.084 52.824 ;
    END
  END k_lo_d[258]
  PIN k_lo_d[259]
    DIRECTION INPUT ;
    USE SIGNAL ;
    PORT
      LAYER M4 ;
        RECT  0 52.992 0.084 53.016 ;
    END
  END k_lo_d[259]
  PIN k_lo_d[25]
    DIRECTION INPUT ;
    USE SIGNAL ;
    PORT
      LAYER M4 ;
        RECT  0 10.896 0.084 10.92 ;
    END
  END k_lo_d[25]
  PIN k_lo_d[260]
    DIRECTION INPUT ;
    USE SIGNAL ;
    PORT
      LAYER M4 ;
        RECT  0 53.184 0.084 53.208 ;
    END
  END k_lo_d[260]
  PIN k_lo_d[261]
    DIRECTION INPUT ;
    USE SIGNAL ;
    PORT
      LAYER M4 ;
        RECT  0 53.376 0.084 53.4 ;
    END
  END k_lo_d[261]
  PIN k_lo_d[262]
    DIRECTION INPUT ;
    USE SIGNAL ;
    PORT
      LAYER M4 ;
        RECT  0 53.52 0.084 53.544 ;
    END
  END k_lo_d[262]
  PIN k_lo_d[263]
    DIRECTION INPUT ;
    USE SIGNAL ;
    PORT
      LAYER M4 ;
        RECT  0 53.712 0.084 53.736 ;
    END
  END k_lo_d[263]
  PIN k_lo_d[264]
    DIRECTION INPUT ;
    USE SIGNAL ;
    PORT
      LAYER M4 ;
        RECT  0 53.904 0.084 53.928 ;
    END
  END k_lo_d[264]
  PIN k_lo_d[265]
    DIRECTION INPUT ;
    USE SIGNAL ;
    PORT
      LAYER M4 ;
        RECT  0 54.096 0.084 54.12 ;
    END
  END k_lo_d[265]
  PIN k_lo_d[266]
    DIRECTION INPUT ;
    USE SIGNAL ;
    PORT
      LAYER M4 ;
        RECT  0 54.24 0.084 54.264 ;
    END
  END k_lo_d[266]
  PIN k_lo_d[267]
    DIRECTION INPUT ;
    USE SIGNAL ;
    PORT
      LAYER M4 ;
        RECT  0 54.432 0.084 54.456 ;
    END
  END k_lo_d[267]
  PIN k_lo_d[268]
    DIRECTION INPUT ;
    USE SIGNAL ;
    PORT
      LAYER M4 ;
        RECT  0 54.624 0.084 54.648 ;
    END
  END k_lo_d[268]
  PIN k_lo_d[269]
    DIRECTION INPUT ;
    USE SIGNAL ;
    PORT
      LAYER M4 ;
        RECT  0 54.816 0.084 54.84 ;
    END
  END k_lo_d[269]
  PIN k_lo_d[26]
    DIRECTION INPUT ;
    USE SIGNAL ;
    PORT
      LAYER M4 ;
        RECT  0 11.088 0.084 11.112 ;
    END
  END k_lo_d[26]
  PIN k_lo_d[270]
    DIRECTION INPUT ;
    USE SIGNAL ;
    PORT
      LAYER M4 ;
        RECT  0 54.96 0.084 54.984 ;
    END
  END k_lo_d[270]
  PIN k_lo_d[271]
    DIRECTION INPUT ;
    USE SIGNAL ;
    PORT
      LAYER M4 ;
        RECT  0 55.152 0.084 55.176 ;
    END
  END k_lo_d[271]
  PIN k_lo_d[272]
    DIRECTION INPUT ;
    USE SIGNAL ;
    PORT
      LAYER M4 ;
        RECT  0 55.344 0.084 55.368 ;
    END
  END k_lo_d[272]
  PIN k_lo_d[273]
    DIRECTION INPUT ;
    USE SIGNAL ;
    PORT
      LAYER M4 ;
        RECT  0 55.536 0.084 55.56 ;
    END
  END k_lo_d[273]
  PIN k_lo_d[274]
    DIRECTION INPUT ;
    USE SIGNAL ;
    PORT
      LAYER M4 ;
        RECT  0 55.68 0.084 55.704 ;
    END
  END k_lo_d[274]
  PIN k_lo_d[275]
    DIRECTION INPUT ;
    USE SIGNAL ;
    PORT
      LAYER M4 ;
        RECT  0 55.872 0.084 55.896 ;
    END
  END k_lo_d[275]
  PIN k_lo_d[276]
    DIRECTION INPUT ;
    USE SIGNAL ;
    PORT
      LAYER M4 ;
        RECT  0 56.064 0.084 56.088 ;
    END
  END k_lo_d[276]
  PIN k_lo_d[277]
    DIRECTION INPUT ;
    USE SIGNAL ;
    PORT
      LAYER M4 ;
        RECT  0 56.256 0.084 56.28 ;
    END
  END k_lo_d[277]
  PIN k_lo_d[278]
    DIRECTION INPUT ;
    USE SIGNAL ;
    PORT
      LAYER M4 ;
        RECT  0 56.4 0.084 56.424 ;
    END
  END k_lo_d[278]
  PIN k_lo_d[279]
    DIRECTION INPUT ;
    USE SIGNAL ;
    PORT
      LAYER M4 ;
        RECT  0 56.592 0.084 56.616 ;
    END
  END k_lo_d[279]
  PIN k_lo_d[27]
    DIRECTION INPUT ;
    USE SIGNAL ;
    PORT
      LAYER M4 ;
        RECT  0 11.28 0.084 11.304 ;
    END
  END k_lo_d[27]
  PIN k_lo_d[280]
    DIRECTION INPUT ;
    USE SIGNAL ;
    PORT
      LAYER M4 ;
        RECT  0 56.784 0.084 56.808 ;
    END
  END k_lo_d[280]
  PIN k_lo_d[281]
    DIRECTION INPUT ;
    USE SIGNAL ;
    PORT
      LAYER M4 ;
        RECT  0 56.976 0.084 57 ;
    END
  END k_lo_d[281]
  PIN k_lo_d[282]
    DIRECTION INPUT ;
    USE SIGNAL ;
    PORT
      LAYER M4 ;
        RECT  0 57.12 0.084 57.144 ;
    END
  END k_lo_d[282]
  PIN k_lo_d[283]
    DIRECTION INPUT ;
    USE SIGNAL ;
    PORT
      LAYER M4 ;
        RECT  0 57.312 0.084 57.336 ;
    END
  END k_lo_d[283]
  PIN k_lo_d[284]
    DIRECTION INPUT ;
    USE SIGNAL ;
    PORT
      LAYER M4 ;
        RECT  0 57.504 0.084 57.528 ;
    END
  END k_lo_d[284]
  PIN k_lo_d[285]
    DIRECTION INPUT ;
    USE SIGNAL ;
    PORT
      LAYER M4 ;
        RECT  0 57.696 0.084 57.72 ;
    END
  END k_lo_d[285]
  PIN k_lo_d[286]
    DIRECTION INPUT ;
    USE SIGNAL ;
    PORT
      LAYER M4 ;
        RECT  0 57.84 0.084 57.864 ;
    END
  END k_lo_d[286]
  PIN k_lo_d[287]
    DIRECTION INPUT ;
    USE SIGNAL ;
    PORT
      LAYER M4 ;
        RECT  0 58.032 0.084 58.056 ;
    END
  END k_lo_d[287]
  PIN k_lo_d[288]
    DIRECTION INPUT ;
    USE SIGNAL ;
    PORT
      LAYER M4 ;
        RECT  0 58.224 0.084 58.248 ;
    END
  END k_lo_d[288]
  PIN k_lo_d[289]
    DIRECTION INPUT ;
    USE SIGNAL ;
    PORT
      LAYER M4 ;
        RECT  0 58.416 0.084 58.44 ;
    END
  END k_lo_d[289]
  PIN k_lo_d[28]
    DIRECTION INPUT ;
    USE SIGNAL ;
    PORT
      LAYER M4 ;
        RECT  0 11.424 0.084 11.448 ;
    END
  END k_lo_d[28]
  PIN k_lo_d[290]
    DIRECTION INPUT ;
    USE SIGNAL ;
    PORT
      LAYER M4 ;
        RECT  0 58.56 0.084 58.584 ;
    END
  END k_lo_d[290]
  PIN k_lo_d[291]
    DIRECTION INPUT ;
    USE SIGNAL ;
    PORT
      LAYER M4 ;
        RECT  0 58.752 0.084 58.776 ;
    END
  END k_lo_d[291]
  PIN k_lo_d[292]
    DIRECTION INPUT ;
    USE SIGNAL ;
    PORT
      LAYER M4 ;
        RECT  0 58.944 0.084 58.968 ;
    END
  END k_lo_d[292]
  PIN k_lo_d[293]
    DIRECTION INPUT ;
    USE SIGNAL ;
    PORT
      LAYER M4 ;
        RECT  0 59.136 0.084 59.16 ;
    END
  END k_lo_d[293]
  PIN k_lo_d[294]
    DIRECTION INPUT ;
    USE SIGNAL ;
    PORT
      LAYER M4 ;
        RECT  0 59.28 0.084 59.304 ;
    END
  END k_lo_d[294]
  PIN k_lo_d[295]
    DIRECTION INPUT ;
    USE SIGNAL ;
    PORT
      LAYER M4 ;
        RECT  0 59.472 0.084 59.496 ;
    END
  END k_lo_d[295]
  PIN k_lo_d[296]
    DIRECTION INPUT ;
    USE SIGNAL ;
    PORT
      LAYER M4 ;
        RECT  0 59.664 0.084 59.688 ;
    END
  END k_lo_d[296]
  PIN k_lo_d[297]
    DIRECTION INPUT ;
    USE SIGNAL ;
    PORT
      LAYER M4 ;
        RECT  0 59.856 0.084 59.88 ;
    END
  END k_lo_d[297]
  PIN k_lo_d[298]
    DIRECTION INPUT ;
    USE SIGNAL ;
    PORT
      LAYER M4 ;
        RECT  0 60 0.084 60.024 ;
    END
  END k_lo_d[298]
  PIN k_lo_d[299]
    DIRECTION INPUT ;
    USE SIGNAL ;
    PORT
      LAYER M4 ;
        RECT  0 60.192 0.084 60.216 ;
    END
  END k_lo_d[299]
  PIN k_lo_d[29]
    DIRECTION INPUT ;
    USE SIGNAL ;
    PORT
      LAYER M4 ;
        RECT  0 11.616 0.084 11.64 ;
    END
  END k_lo_d[29]
  PIN k_lo_d[2]
    DIRECTION INPUT ;
    USE SIGNAL ;
    PORT
      LAYER M4 ;
        RECT  0 6.768 0.084 6.792 ;
    END
  END k_lo_d[2]
  PIN k_lo_d[300]
    DIRECTION INPUT ;
    USE SIGNAL ;
    PORT
      LAYER M4 ;
        RECT  0 60.384 0.084 60.408 ;
    END
  END k_lo_d[300]
  PIN k_lo_d[301]
    DIRECTION INPUT ;
    USE SIGNAL ;
    PORT
      LAYER M4 ;
        RECT  0 60.576 0.084 60.6 ;
    END
  END k_lo_d[301]
  PIN k_lo_d[302]
    DIRECTION INPUT ;
    USE SIGNAL ;
    PORT
      LAYER M4 ;
        RECT  0 60.72 0.084 60.744 ;
    END
  END k_lo_d[302]
  PIN k_lo_d[303]
    DIRECTION INPUT ;
    USE SIGNAL ;
    PORT
      LAYER M4 ;
        RECT  0 60.912 0.084 60.936 ;
    END
  END k_lo_d[303]
  PIN k_lo_d[304]
    DIRECTION INPUT ;
    USE SIGNAL ;
    PORT
      LAYER M4 ;
        RECT  0 61.104 0.084 61.128 ;
    END
  END k_lo_d[304]
  PIN k_lo_d[305]
    DIRECTION INPUT ;
    USE SIGNAL ;
    PORT
      LAYER M4 ;
        RECT  0 61.296 0.084 61.32 ;
    END
  END k_lo_d[305]
  PIN k_lo_d[306]
    DIRECTION INPUT ;
    USE SIGNAL ;
    PORT
      LAYER M4 ;
        RECT  0 61.44 0.084 61.464 ;
    END
  END k_lo_d[306]
  PIN k_lo_d[307]
    DIRECTION INPUT ;
    USE SIGNAL ;
    PORT
      LAYER M4 ;
        RECT  0 61.632 0.084 61.656 ;
    END
  END k_lo_d[307]
  PIN k_lo_d[308]
    DIRECTION INPUT ;
    USE SIGNAL ;
    PORT
      LAYER M4 ;
        RECT  0 61.824 0.084 61.848 ;
    END
  END k_lo_d[308]
  PIN k_lo_d[309]
    DIRECTION INPUT ;
    USE SIGNAL ;
    PORT
      LAYER M4 ;
        RECT  0 62.016 0.084 62.04 ;
    END
  END k_lo_d[309]
  PIN k_lo_d[30]
    DIRECTION INPUT ;
    USE SIGNAL ;
    PORT
      LAYER M4 ;
        RECT  0 11.808 0.084 11.832 ;
    END
  END k_lo_d[30]
  PIN k_lo_d[310]
    DIRECTION INPUT ;
    USE SIGNAL ;
    PORT
      LAYER M4 ;
        RECT  0 62.16 0.084 62.184 ;
    END
  END k_lo_d[310]
  PIN k_lo_d[311]
    DIRECTION INPUT ;
    USE SIGNAL ;
    PORT
      LAYER M4 ;
        RECT  0 62.352 0.084 62.376 ;
    END
  END k_lo_d[311]
  PIN k_lo_d[312]
    DIRECTION INPUT ;
    USE SIGNAL ;
    PORT
      LAYER M4 ;
        RECT  0 62.544 0.084 62.568 ;
    END
  END k_lo_d[312]
  PIN k_lo_d[313]
    DIRECTION INPUT ;
    USE SIGNAL ;
    PORT
      LAYER M4 ;
        RECT  0 62.736 0.084 62.76 ;
    END
  END k_lo_d[313]
  PIN k_lo_d[314]
    DIRECTION INPUT ;
    USE SIGNAL ;
    PORT
      LAYER M4 ;
        RECT  0 62.88 0.084 62.904 ;
    END
  END k_lo_d[314]
  PIN k_lo_d[315]
    DIRECTION INPUT ;
    USE SIGNAL ;
    PORT
      LAYER M4 ;
        RECT  0 63.072 0.084 63.096 ;
    END
  END k_lo_d[315]
  PIN k_lo_d[316]
    DIRECTION INPUT ;
    USE SIGNAL ;
    PORT
      LAYER M4 ;
        RECT  0 63.264 0.084 63.288 ;
    END
  END k_lo_d[316]
  PIN k_lo_d[317]
    DIRECTION INPUT ;
    USE SIGNAL ;
    PORT
      LAYER M4 ;
        RECT  0 63.456 0.084 63.48 ;
    END
  END k_lo_d[317]
  PIN k_lo_d[318]
    DIRECTION INPUT ;
    USE SIGNAL ;
    PORT
      LAYER M4 ;
        RECT  0 63.6 0.084 63.624 ;
    END
  END k_lo_d[318]
  PIN k_lo_d[319]
    DIRECTION INPUT ;
    USE SIGNAL ;
    PORT
      LAYER M4 ;
        RECT  0 63.792 0.084 63.816 ;
    END
  END k_lo_d[319]
  PIN k_lo_d[31]
    DIRECTION INPUT ;
    USE SIGNAL ;
    PORT
      LAYER M4 ;
        RECT  0 12 0.084 12.024 ;
    END
  END k_lo_d[31]
  PIN k_lo_d[320]
    DIRECTION INPUT ;
    USE SIGNAL ;
    PORT
      LAYER M4 ;
        RECT  0 63.984 0.084 64.008 ;
    END
  END k_lo_d[320]
  PIN k_lo_d[321]
    DIRECTION INPUT ;
    USE SIGNAL ;
    PORT
      LAYER M4 ;
        RECT  0 64.176 0.084 64.2 ;
    END
  END k_lo_d[321]
  PIN k_lo_d[322]
    DIRECTION INPUT ;
    USE SIGNAL ;
    PORT
      LAYER M4 ;
        RECT  0 64.32 0.084 64.344 ;
    END
  END k_lo_d[322]
  PIN k_lo_d[323]
    DIRECTION INPUT ;
    USE SIGNAL ;
    PORT
      LAYER M4 ;
        RECT  0 64.512 0.084 64.536 ;
    END
  END k_lo_d[323]
  PIN k_lo_d[324]
    DIRECTION INPUT ;
    USE SIGNAL ;
    PORT
      LAYER M4 ;
        RECT  0 64.704 0.084 64.728 ;
    END
  END k_lo_d[324]
  PIN k_lo_d[325]
    DIRECTION INPUT ;
    USE SIGNAL ;
    PORT
      LAYER M4 ;
        RECT  0 64.896 0.084 64.92 ;
    END
  END k_lo_d[325]
  PIN k_lo_d[326]
    DIRECTION INPUT ;
    USE SIGNAL ;
    PORT
      LAYER M4 ;
        RECT  0 65.04 0.084 65.064 ;
    END
  END k_lo_d[326]
  PIN k_lo_d[327]
    DIRECTION INPUT ;
    USE SIGNAL ;
    PORT
      LAYER M4 ;
        RECT  0 65.232 0.084 65.256 ;
    END
  END k_lo_d[327]
  PIN k_lo_d[328]
    DIRECTION INPUT ;
    USE SIGNAL ;
    PORT
      LAYER M4 ;
        RECT  0 65.424 0.084 65.448 ;
    END
  END k_lo_d[328]
  PIN k_lo_d[329]
    DIRECTION INPUT ;
    USE SIGNAL ;
    PORT
      LAYER M4 ;
        RECT  0 65.616 0.084 65.64 ;
    END
  END k_lo_d[329]
  PIN k_lo_d[32]
    DIRECTION INPUT ;
    USE SIGNAL ;
    PORT
      LAYER M4 ;
        RECT  0 12.144 0.084 12.168 ;
    END
  END k_lo_d[32]
  PIN k_lo_d[330]
    DIRECTION INPUT ;
    USE SIGNAL ;
    PORT
      LAYER M4 ;
        RECT  0 65.76 0.084 65.784 ;
    END
  END k_lo_d[330]
  PIN k_lo_d[331]
    DIRECTION INPUT ;
    USE SIGNAL ;
    PORT
      LAYER M4 ;
        RECT  0 65.952 0.084 65.976 ;
    END
  END k_lo_d[331]
  PIN k_lo_d[332]
    DIRECTION INPUT ;
    USE SIGNAL ;
    PORT
      LAYER M4 ;
        RECT  0 66.144 0.084 66.168 ;
    END
  END k_lo_d[332]
  PIN k_lo_d[333]
    DIRECTION INPUT ;
    USE SIGNAL ;
    PORT
      LAYER M4 ;
        RECT  0 66.336 0.084 66.36 ;
    END
  END k_lo_d[333]
  PIN k_lo_d[334]
    DIRECTION INPUT ;
    USE SIGNAL ;
    PORT
      LAYER M4 ;
        RECT  0 66.48 0.084 66.504 ;
    END
  END k_lo_d[334]
  PIN k_lo_d[335]
    DIRECTION INPUT ;
    USE SIGNAL ;
    PORT
      LAYER M4 ;
        RECT  0 66.672 0.084 66.696 ;
    END
  END k_lo_d[335]
  PIN k_lo_d[336]
    DIRECTION INPUT ;
    USE SIGNAL ;
    PORT
      LAYER M4 ;
        RECT  0 66.864 0.084 66.888 ;
    END
  END k_lo_d[336]
  PIN k_lo_d[337]
    DIRECTION INPUT ;
    USE SIGNAL ;
    PORT
      LAYER M4 ;
        RECT  0 67.056 0.084 67.08 ;
    END
  END k_lo_d[337]
  PIN k_lo_d[338]
    DIRECTION INPUT ;
    USE SIGNAL ;
    PORT
      LAYER M4 ;
        RECT  0 67.2 0.084 67.224 ;
    END
  END k_lo_d[338]
  PIN k_lo_d[339]
    DIRECTION INPUT ;
    USE SIGNAL ;
    PORT
      LAYER M4 ;
        RECT  0 67.392 0.084 67.416 ;
    END
  END k_lo_d[339]
  PIN k_lo_d[33]
    DIRECTION INPUT ;
    USE SIGNAL ;
    PORT
      LAYER M4 ;
        RECT  0 12.336 0.084 12.36 ;
    END
  END k_lo_d[33]
  PIN k_lo_d[340]
    DIRECTION INPUT ;
    USE SIGNAL ;
    PORT
      LAYER M4 ;
        RECT  0 67.584 0.084 67.608 ;
    END
  END k_lo_d[340]
  PIN k_lo_d[341]
    DIRECTION INPUT ;
    USE SIGNAL ;
    PORT
      LAYER M4 ;
        RECT  0 67.776 0.084 67.8 ;
    END
  END k_lo_d[341]
  PIN k_lo_d[342]
    DIRECTION INPUT ;
    USE SIGNAL ;
    PORT
      LAYER M4 ;
        RECT  0 67.92 0.084 67.944 ;
    END
  END k_lo_d[342]
  PIN k_lo_d[343]
    DIRECTION INPUT ;
    USE SIGNAL ;
    PORT
      LAYER M4 ;
        RECT  0 68.112 0.084 68.136 ;
    END
  END k_lo_d[343]
  PIN k_lo_d[344]
    DIRECTION INPUT ;
    USE SIGNAL ;
    PORT
      LAYER M4 ;
        RECT  0 68.304 0.084 68.328 ;
    END
  END k_lo_d[344]
  PIN k_lo_d[345]
    DIRECTION INPUT ;
    USE SIGNAL ;
    PORT
      LAYER M4 ;
        RECT  0 68.496 0.084 68.52 ;
    END
  END k_lo_d[345]
  PIN k_lo_d[346]
    DIRECTION INPUT ;
    USE SIGNAL ;
    PORT
      LAYER M4 ;
        RECT  0 68.64 0.084 68.664 ;
    END
  END k_lo_d[346]
  PIN k_lo_d[347]
    DIRECTION INPUT ;
    USE SIGNAL ;
    PORT
      LAYER M4 ;
        RECT  0 68.832 0.084 68.856 ;
    END
  END k_lo_d[347]
  PIN k_lo_d[348]
    DIRECTION INPUT ;
    USE SIGNAL ;
    PORT
      LAYER M4 ;
        RECT  0 69.024 0.084 69.048 ;
    END
  END k_lo_d[348]
  PIN k_lo_d[349]
    DIRECTION INPUT ;
    USE SIGNAL ;
    PORT
      LAYER M4 ;
        RECT  0 69.168 0.084 69.192 ;
    END
  END k_lo_d[349]
  PIN k_lo_d[34]
    DIRECTION INPUT ;
    USE SIGNAL ;
    PORT
      LAYER M4 ;
        RECT  0 12.528 0.084 12.552 ;
    END
  END k_lo_d[34]
  PIN k_lo_d[350]
    DIRECTION INPUT ;
    USE SIGNAL ;
    PORT
      LAYER M4 ;
        RECT  0 69.36 0.084 69.384 ;
    END
  END k_lo_d[350]
  PIN k_lo_d[351]
    DIRECTION INPUT ;
    USE SIGNAL ;
    PORT
      LAYER M4 ;
        RECT  0 69.552 0.084 69.576 ;
    END
  END k_lo_d[351]
  PIN k_lo_d[352]
    DIRECTION INPUT ;
    USE SIGNAL ;
    PORT
      LAYER M4 ;
        RECT  0 69.744 0.084 69.768 ;
    END
  END k_lo_d[352]
  PIN k_lo_d[353]
    DIRECTION INPUT ;
    USE SIGNAL ;
    PORT
      LAYER M4 ;
        RECT  0 69.888 0.084 69.912 ;
    END
  END k_lo_d[353]
  PIN k_lo_d[354]
    DIRECTION INPUT ;
    USE SIGNAL ;
    PORT
      LAYER M4 ;
        RECT  0 70.08 0.084 70.104 ;
    END
  END k_lo_d[354]
  PIN k_lo_d[355]
    DIRECTION INPUT ;
    USE SIGNAL ;
    PORT
      LAYER M4 ;
        RECT  0 70.272 0.084 70.296 ;
    END
  END k_lo_d[355]
  PIN k_lo_d[356]
    DIRECTION INPUT ;
    USE SIGNAL ;
    PORT
      LAYER M4 ;
        RECT  0 70.464 0.084 70.488 ;
    END
  END k_lo_d[356]
  PIN k_lo_d[357]
    DIRECTION INPUT ;
    USE SIGNAL ;
    PORT
      LAYER M4 ;
        RECT  0 70.608 0.084 70.632 ;
    END
  END k_lo_d[357]
  PIN k_lo_d[358]
    DIRECTION INPUT ;
    USE SIGNAL ;
    PORT
      LAYER M4 ;
        RECT  0 70.8 0.084 70.824 ;
    END
  END k_lo_d[358]
  PIN k_lo_d[359]
    DIRECTION INPUT ;
    USE SIGNAL ;
    PORT
      LAYER M4 ;
        RECT  0 70.992 0.084 71.016 ;
    END
  END k_lo_d[359]
  PIN k_lo_d[35]
    DIRECTION INPUT ;
    USE SIGNAL ;
    PORT
      LAYER M4 ;
        RECT  0 12.72 0.084 12.744 ;
    END
  END k_lo_d[35]
  PIN k_lo_d[360]
    DIRECTION INPUT ;
    USE SIGNAL ;
    PORT
      LAYER M4 ;
        RECT  0 71.184 0.084 71.208 ;
    END
  END k_lo_d[360]
  PIN k_lo_d[361]
    DIRECTION INPUT ;
    USE SIGNAL ;
    PORT
      LAYER M4 ;
        RECT  0 71.328 0.084 71.352 ;
    END
  END k_lo_d[361]
  PIN k_lo_d[362]
    DIRECTION INPUT ;
    USE SIGNAL ;
    PORT
      LAYER M4 ;
        RECT  0 71.52 0.084 71.544 ;
    END
  END k_lo_d[362]
  PIN k_lo_d[363]
    DIRECTION INPUT ;
    USE SIGNAL ;
    PORT
      LAYER M4 ;
        RECT  0 71.712 0.084 71.736 ;
    END
  END k_lo_d[363]
  PIN k_lo_d[364]
    DIRECTION INPUT ;
    USE SIGNAL ;
    PORT
      LAYER M4 ;
        RECT  0 71.904 0.084 71.928 ;
    END
  END k_lo_d[364]
  PIN k_lo_d[365]
    DIRECTION INPUT ;
    USE SIGNAL ;
    PORT
      LAYER M4 ;
        RECT  0 72.048 0.084 72.072 ;
    END
  END k_lo_d[365]
  PIN k_lo_d[366]
    DIRECTION INPUT ;
    USE SIGNAL ;
    PORT
      LAYER M4 ;
        RECT  0 72.24 0.084 72.264 ;
    END
  END k_lo_d[366]
  PIN k_lo_d[367]
    DIRECTION INPUT ;
    USE SIGNAL ;
    PORT
      LAYER M4 ;
        RECT  0 72.432 0.084 72.456 ;
    END
  END k_lo_d[367]
  PIN k_lo_d[368]
    DIRECTION INPUT ;
    USE SIGNAL ;
    PORT
      LAYER M4 ;
        RECT  0 72.624 0.084 72.648 ;
    END
  END k_lo_d[368]
  PIN k_lo_d[369]
    DIRECTION INPUT ;
    USE SIGNAL ;
    PORT
      LAYER M4 ;
        RECT  0 72.768 0.084 72.792 ;
    END
  END k_lo_d[369]
  PIN k_lo_d[36]
    DIRECTION INPUT ;
    USE SIGNAL ;
    PORT
      LAYER M4 ;
        RECT  0 12.864 0.084 12.888 ;
    END
  END k_lo_d[36]
  PIN k_lo_d[370]
    DIRECTION INPUT ;
    USE SIGNAL ;
    PORT
      LAYER M4 ;
        RECT  0 72.96 0.084 72.984 ;
    END
  END k_lo_d[370]
  PIN k_lo_d[371]
    DIRECTION INPUT ;
    USE SIGNAL ;
    PORT
      LAYER M4 ;
        RECT  0 73.152 0.084 73.176 ;
    END
  END k_lo_d[371]
  PIN k_lo_d[372]
    DIRECTION INPUT ;
    USE SIGNAL ;
    PORT
      LAYER M4 ;
        RECT  0 73.344 0.084 73.368 ;
    END
  END k_lo_d[372]
  PIN k_lo_d[373]
    DIRECTION INPUT ;
    USE SIGNAL ;
    PORT
      LAYER M4 ;
        RECT  0 73.488 0.084 73.512 ;
    END
  END k_lo_d[373]
  PIN k_lo_d[374]
    DIRECTION INPUT ;
    USE SIGNAL ;
    PORT
      LAYER M4 ;
        RECT  0 73.68 0.084 73.704 ;
    END
  END k_lo_d[374]
  PIN k_lo_d[375]
    DIRECTION INPUT ;
    USE SIGNAL ;
    PORT
      LAYER M4 ;
        RECT  0 73.872 0.084 73.896 ;
    END
  END k_lo_d[375]
  PIN k_lo_d[376]
    DIRECTION INPUT ;
    USE SIGNAL ;
    PORT
      LAYER M4 ;
        RECT  0 74.064 0.084 74.088 ;
    END
  END k_lo_d[376]
  PIN k_lo_d[377]
    DIRECTION INPUT ;
    USE SIGNAL ;
    PORT
      LAYER M4 ;
        RECT  0 74.208 0.084 74.232 ;
    END
  END k_lo_d[377]
  PIN k_lo_d[378]
    DIRECTION INPUT ;
    USE SIGNAL ;
    PORT
      LAYER M4 ;
        RECT  0 74.4 0.084 74.424 ;
    END
  END k_lo_d[378]
  PIN k_lo_d[379]
    DIRECTION INPUT ;
    USE SIGNAL ;
    PORT
      LAYER M4 ;
        RECT  0 74.592 0.084 74.616 ;
    END
  END k_lo_d[379]
  PIN k_lo_d[37]
    DIRECTION INPUT ;
    USE SIGNAL ;
    PORT
      LAYER M4 ;
        RECT  0 13.056 0.084 13.08 ;
    END
  END k_lo_d[37]
  PIN k_lo_d[380]
    DIRECTION INPUT ;
    USE SIGNAL ;
    PORT
      LAYER M4 ;
        RECT  0 74.784 0.084 74.808 ;
    END
  END k_lo_d[380]
  PIN k_lo_d[381]
    DIRECTION INPUT ;
    USE SIGNAL ;
    PORT
      LAYER M4 ;
        RECT  0 74.928 0.084 74.952 ;
    END
  END k_lo_d[381]
  PIN k_lo_d[382]
    DIRECTION INPUT ;
    USE SIGNAL ;
    PORT
      LAYER M4 ;
        RECT  0 75.12 0.084 75.144 ;
    END
  END k_lo_d[382]
  PIN k_lo_d[383]
    DIRECTION INPUT ;
    USE SIGNAL ;
    PORT
      LAYER M4 ;
        RECT  0 75.312 0.084 75.336 ;
    END
  END k_lo_d[383]
  PIN k_lo_d[384]
    DIRECTION INPUT ;
    USE SIGNAL ;
    PORT
      LAYER M4 ;
        RECT  0 75.504 0.084 75.528 ;
    END
  END k_lo_d[384]
  PIN k_lo_d[385]
    DIRECTION INPUT ;
    USE SIGNAL ;
    PORT
      LAYER M4 ;
        RECT  0 75.648 0.084 75.672 ;
    END
  END k_lo_d[385]
  PIN k_lo_d[386]
    DIRECTION INPUT ;
    USE SIGNAL ;
    PORT
      LAYER M4 ;
        RECT  0 75.84 0.084 75.864 ;
    END
  END k_lo_d[386]
  PIN k_lo_d[387]
    DIRECTION INPUT ;
    USE SIGNAL ;
    PORT
      LAYER M4 ;
        RECT  0 76.032 0.084 76.056 ;
    END
  END k_lo_d[387]
  PIN k_lo_d[388]
    DIRECTION INPUT ;
    USE SIGNAL ;
    PORT
      LAYER M4 ;
        RECT  0 76.224 0.084 76.248 ;
    END
  END k_lo_d[388]
  PIN k_lo_d[389]
    DIRECTION INPUT ;
    USE SIGNAL ;
    PORT
      LAYER M4 ;
        RECT  0 76.368 0.084 76.392 ;
    END
  END k_lo_d[389]
  PIN k_lo_d[38]
    DIRECTION INPUT ;
    USE SIGNAL ;
    PORT
      LAYER M4 ;
        RECT  0 13.248 0.084 13.272 ;
    END
  END k_lo_d[38]
  PIN k_lo_d[390]
    DIRECTION INPUT ;
    USE SIGNAL ;
    PORT
      LAYER M4 ;
        RECT  0 76.56 0.084 76.584 ;
    END
  END k_lo_d[390]
  PIN k_lo_d[391]
    DIRECTION INPUT ;
    USE SIGNAL ;
    PORT
      LAYER M4 ;
        RECT  0 76.752 0.084 76.776 ;
    END
  END k_lo_d[391]
  PIN k_lo_d[392]
    DIRECTION INPUT ;
    USE SIGNAL ;
    PORT
      LAYER M4 ;
        RECT  0 76.944 0.084 76.968 ;
    END
  END k_lo_d[392]
  PIN k_lo_d[393]
    DIRECTION INPUT ;
    USE SIGNAL ;
    PORT
      LAYER M4 ;
        RECT  0 77.088 0.084 77.112 ;
    END
  END k_lo_d[393]
  PIN k_lo_d[394]
    DIRECTION INPUT ;
    USE SIGNAL ;
    PORT
      LAYER M4 ;
        RECT  0 77.28 0.084 77.304 ;
    END
  END k_lo_d[394]
  PIN k_lo_d[395]
    DIRECTION INPUT ;
    USE SIGNAL ;
    PORT
      LAYER M4 ;
        RECT  0 77.472 0.084 77.496 ;
    END
  END k_lo_d[395]
  PIN k_lo_d[396]
    DIRECTION INPUT ;
    USE SIGNAL ;
    PORT
      LAYER M4 ;
        RECT  0 77.664 0.084 77.688 ;
    END
  END k_lo_d[396]
  PIN k_lo_d[397]
    DIRECTION INPUT ;
    USE SIGNAL ;
    PORT
      LAYER M4 ;
        RECT  0 77.808 0.084 77.832 ;
    END
  END k_lo_d[397]
  PIN k_lo_d[398]
    DIRECTION INPUT ;
    USE SIGNAL ;
    PORT
      LAYER M4 ;
        RECT  0 78 0.084 78.024 ;
    END
  END k_lo_d[398]
  PIN k_lo_d[399]
    DIRECTION INPUT ;
    USE SIGNAL ;
    PORT
      LAYER M4 ;
        RECT  0 78.192 0.084 78.216 ;
    END
  END k_lo_d[399]
  PIN k_lo_d[39]
    DIRECTION INPUT ;
    USE SIGNAL ;
    PORT
      LAYER M4 ;
        RECT  0 13.44 0.084 13.464 ;
    END
  END k_lo_d[39]
  PIN k_lo_d[3]
    DIRECTION INPUT ;
    USE SIGNAL ;
    PORT
      LAYER M4 ;
        RECT  0 6.96 0.084 6.984 ;
    END
  END k_lo_d[3]
  PIN k_lo_d[400]
    DIRECTION INPUT ;
    USE SIGNAL ;
    PORT
      LAYER M4 ;
        RECT  0 78.384 0.084 78.408 ;
    END
  END k_lo_d[400]
  PIN k_lo_d[401]
    DIRECTION INPUT ;
    USE SIGNAL ;
    PORT
      LAYER M4 ;
        RECT  0 78.528 0.084 78.552 ;
    END
  END k_lo_d[401]
  PIN k_lo_d[402]
    DIRECTION INPUT ;
    USE SIGNAL ;
    PORT
      LAYER M4 ;
        RECT  0 78.72 0.084 78.744 ;
    END
  END k_lo_d[402]
  PIN k_lo_d[403]
    DIRECTION INPUT ;
    USE SIGNAL ;
    PORT
      LAYER M4 ;
        RECT  0 78.912 0.084 78.936 ;
    END
  END k_lo_d[403]
  PIN k_lo_d[404]
    DIRECTION INPUT ;
    USE SIGNAL ;
    PORT
      LAYER M4 ;
        RECT  0 79.104 0.084 79.128 ;
    END
  END k_lo_d[404]
  PIN k_lo_d[405]
    DIRECTION INPUT ;
    USE SIGNAL ;
    PORT
      LAYER M4 ;
        RECT  0 79.248 0.084 79.272 ;
    END
  END k_lo_d[405]
  PIN k_lo_d[406]
    DIRECTION INPUT ;
    USE SIGNAL ;
    PORT
      LAYER M4 ;
        RECT  0 79.44 0.084 79.464 ;
    END
  END k_lo_d[406]
  PIN k_lo_d[407]
    DIRECTION INPUT ;
    USE SIGNAL ;
    PORT
      LAYER M4 ;
        RECT  0 79.632 0.084 79.656 ;
    END
  END k_lo_d[407]
  PIN k_lo_d[408]
    DIRECTION INPUT ;
    USE SIGNAL ;
    PORT
      LAYER M4 ;
        RECT  0 79.824 0.084 79.848 ;
    END
  END k_lo_d[408]
  PIN k_lo_d[409]
    DIRECTION INPUT ;
    USE SIGNAL ;
    PORT
      LAYER M4 ;
        RECT  0 79.968 0.084 79.992 ;
    END
  END k_lo_d[409]
  PIN k_lo_d[40]
    DIRECTION INPUT ;
    USE SIGNAL ;
    PORT
      LAYER M4 ;
        RECT  0 13.584 0.084 13.608 ;
    END
  END k_lo_d[40]
  PIN k_lo_d[410]
    DIRECTION INPUT ;
    USE SIGNAL ;
    PORT
      LAYER M4 ;
        RECT  0 80.16 0.084 80.184 ;
    END
  END k_lo_d[410]
  PIN k_lo_d[411]
    DIRECTION INPUT ;
    USE SIGNAL ;
    PORT
      LAYER M4 ;
        RECT  0 80.352 0.084 80.376 ;
    END
  END k_lo_d[411]
  PIN k_lo_d[412]
    DIRECTION INPUT ;
    USE SIGNAL ;
    PORT
      LAYER M4 ;
        RECT  0 80.544 0.084 80.568 ;
    END
  END k_lo_d[412]
  PIN k_lo_d[413]
    DIRECTION INPUT ;
    USE SIGNAL ;
    PORT
      LAYER M4 ;
        RECT  0 80.688 0.084 80.712 ;
    END
  END k_lo_d[413]
  PIN k_lo_d[414]
    DIRECTION INPUT ;
    USE SIGNAL ;
    PORT
      LAYER M4 ;
        RECT  0 80.88 0.084 80.904 ;
    END
  END k_lo_d[414]
  PIN k_lo_d[415]
    DIRECTION INPUT ;
    USE SIGNAL ;
    PORT
      LAYER M4 ;
        RECT  0 81.072 0.084 81.096 ;
    END
  END k_lo_d[415]
  PIN k_lo_d[416]
    DIRECTION INPUT ;
    USE SIGNAL ;
    PORT
      LAYER M4 ;
        RECT  0 81.264 0.084 81.288 ;
    END
  END k_lo_d[416]
  PIN k_lo_d[417]
    DIRECTION INPUT ;
    USE SIGNAL ;
    PORT
      LAYER M4 ;
        RECT  0 81.408 0.084 81.432 ;
    END
  END k_lo_d[417]
  PIN k_lo_d[418]
    DIRECTION INPUT ;
    USE SIGNAL ;
    PORT
      LAYER M4 ;
        RECT  0 81.6 0.084 81.624 ;
    END
  END k_lo_d[418]
  PIN k_lo_d[419]
    DIRECTION INPUT ;
    USE SIGNAL ;
    PORT
      LAYER M4 ;
        RECT  0 81.792 0.084 81.816 ;
    END
  END k_lo_d[419]
  PIN k_lo_d[41]
    DIRECTION INPUT ;
    USE SIGNAL ;
    PORT
      LAYER M4 ;
        RECT  0 13.776 0.084 13.8 ;
    END
  END k_lo_d[41]
  PIN k_lo_d[420]
    DIRECTION INPUT ;
    USE SIGNAL ;
    PORT
      LAYER M4 ;
        RECT  0 81.984 0.084 82.008 ;
    END
  END k_lo_d[420]
  PIN k_lo_d[421]
    DIRECTION INPUT ;
    USE SIGNAL ;
    PORT
      LAYER M4 ;
        RECT  0 82.128 0.084 82.152 ;
    END
  END k_lo_d[421]
  PIN k_lo_d[422]
    DIRECTION INPUT ;
    USE SIGNAL ;
    PORT
      LAYER M4 ;
        RECT  0 82.32 0.084 82.344 ;
    END
  END k_lo_d[422]
  PIN k_lo_d[423]
    DIRECTION INPUT ;
    USE SIGNAL ;
    PORT
      LAYER M4 ;
        RECT  0 82.512 0.084 82.536 ;
    END
  END k_lo_d[423]
  PIN k_lo_d[424]
    DIRECTION INPUT ;
    USE SIGNAL ;
    PORT
      LAYER M4 ;
        RECT  0 82.704 0.084 82.728 ;
    END
  END k_lo_d[424]
  PIN k_lo_d[425]
    DIRECTION INPUT ;
    USE SIGNAL ;
    PORT
      LAYER M4 ;
        RECT  0 82.848 0.084 82.872 ;
    END
  END k_lo_d[425]
  PIN k_lo_d[426]
    DIRECTION INPUT ;
    USE SIGNAL ;
    PORT
      LAYER M4 ;
        RECT  0 83.04 0.084 83.064 ;
    END
  END k_lo_d[426]
  PIN k_lo_d[427]
    DIRECTION INPUT ;
    USE SIGNAL ;
    PORT
      LAYER M4 ;
        RECT  0 83.232 0.084 83.256 ;
    END
  END k_lo_d[427]
  PIN k_lo_d[428]
    DIRECTION INPUT ;
    USE SIGNAL ;
    PORT
      LAYER M4 ;
        RECT  0 83.424 0.084 83.448 ;
    END
  END k_lo_d[428]
  PIN k_lo_d[429]
    DIRECTION INPUT ;
    USE SIGNAL ;
    PORT
      LAYER M4 ;
        RECT  0 83.568 0.084 83.592 ;
    END
  END k_lo_d[429]
  PIN k_lo_d[42]
    DIRECTION INPUT ;
    USE SIGNAL ;
    PORT
      LAYER M4 ;
        RECT  0 13.968 0.084 13.992 ;
    END
  END k_lo_d[42]
  PIN k_lo_d[430]
    DIRECTION INPUT ;
    USE SIGNAL ;
    PORT
      LAYER M4 ;
        RECT  0 83.76 0.084 83.784 ;
    END
  END k_lo_d[430]
  PIN k_lo_d[431]
    DIRECTION INPUT ;
    USE SIGNAL ;
    PORT
      LAYER M4 ;
        RECT  0 83.952 0.084 83.976 ;
    END
  END k_lo_d[431]
  PIN k_lo_d[432]
    DIRECTION INPUT ;
    USE SIGNAL ;
    PORT
      LAYER M4 ;
        RECT  0 84.144 0.084 84.168 ;
    END
  END k_lo_d[432]
  PIN k_lo_d[433]
    DIRECTION INPUT ;
    USE SIGNAL ;
    PORT
      LAYER M4 ;
        RECT  0 84.288 0.084 84.312 ;
    END
  END k_lo_d[433]
  PIN k_lo_d[434]
    DIRECTION INPUT ;
    USE SIGNAL ;
    PORT
      LAYER M4 ;
        RECT  0 84.48 0.084 84.504 ;
    END
  END k_lo_d[434]
  PIN k_lo_d[435]
    DIRECTION INPUT ;
    USE SIGNAL ;
    PORT
      LAYER M4 ;
        RECT  0 84.672 0.084 84.696 ;
    END
  END k_lo_d[435]
  PIN k_lo_d[436]
    DIRECTION INPUT ;
    USE SIGNAL ;
    PORT
      LAYER M4 ;
        RECT  0 84.864 0.084 84.888 ;
    END
  END k_lo_d[436]
  PIN k_lo_d[437]
    DIRECTION INPUT ;
    USE SIGNAL ;
    PORT
      LAYER M4 ;
        RECT  0 85.008 0.084 85.032 ;
    END
  END k_lo_d[437]
  PIN k_lo_d[438]
    DIRECTION INPUT ;
    USE SIGNAL ;
    PORT
      LAYER M4 ;
        RECT  0 85.2 0.084 85.224 ;
    END
  END k_lo_d[438]
  PIN k_lo_d[439]
    DIRECTION INPUT ;
    USE SIGNAL ;
    PORT
      LAYER M4 ;
        RECT  0 85.392 0.084 85.416 ;
    END
  END k_lo_d[439]
  PIN k_lo_d[43]
    DIRECTION INPUT ;
    USE SIGNAL ;
    PORT
      LAYER M4 ;
        RECT  0 14.16 0.084 14.184 ;
    END
  END k_lo_d[43]
  PIN k_lo_d[440]
    DIRECTION INPUT ;
    USE SIGNAL ;
    PORT
      LAYER M4 ;
        RECT  0 85.584 0.084 85.608 ;
    END
  END k_lo_d[440]
  PIN k_lo_d[441]
    DIRECTION INPUT ;
    USE SIGNAL ;
    PORT
      LAYER M4 ;
        RECT  0 85.728 0.084 85.752 ;
    END
  END k_lo_d[441]
  PIN k_lo_d[442]
    DIRECTION INPUT ;
    USE SIGNAL ;
    PORT
      LAYER M4 ;
        RECT  0 85.92 0.084 85.944 ;
    END
  END k_lo_d[442]
  PIN k_lo_d[443]
    DIRECTION INPUT ;
    USE SIGNAL ;
    PORT
      LAYER M4 ;
        RECT  0 86.112 0.084 86.136 ;
    END
  END k_lo_d[443]
  PIN k_lo_d[444]
    DIRECTION INPUT ;
    USE SIGNAL ;
    PORT
      LAYER M4 ;
        RECT  0 86.304 0.084 86.328 ;
    END
  END k_lo_d[444]
  PIN k_lo_d[445]
    DIRECTION INPUT ;
    USE SIGNAL ;
    PORT
      LAYER M4 ;
        RECT  0 86.448 0.084 86.472 ;
    END
  END k_lo_d[445]
  PIN k_lo_d[446]
    DIRECTION INPUT ;
    USE SIGNAL ;
    PORT
      LAYER M4 ;
        RECT  0 86.64 0.084 86.664 ;
    END
  END k_lo_d[446]
  PIN k_lo_d[447]
    DIRECTION INPUT ;
    USE SIGNAL ;
    PORT
      LAYER M4 ;
        RECT  0 86.832 0.084 86.856 ;
    END
  END k_lo_d[447]
  PIN k_lo_d[448]
    DIRECTION INPUT ;
    USE SIGNAL ;
    PORT
      LAYER M4 ;
        RECT  0 87.024 0.084 87.048 ;
    END
  END k_lo_d[448]
  PIN k_lo_d[449]
    DIRECTION INPUT ;
    USE SIGNAL ;
    PORT
      LAYER M4 ;
        RECT  0 87.168 0.084 87.192 ;
    END
  END k_lo_d[449]
  PIN k_lo_d[44]
    DIRECTION INPUT ;
    USE SIGNAL ;
    PORT
      LAYER M4 ;
        RECT  0 14.304 0.084 14.328 ;
    END
  END k_lo_d[44]
  PIN k_lo_d[450]
    DIRECTION INPUT ;
    USE SIGNAL ;
    PORT
      LAYER M4 ;
        RECT  0 87.36 0.084 87.384 ;
    END
  END k_lo_d[450]
  PIN k_lo_d[451]
    DIRECTION INPUT ;
    USE SIGNAL ;
    PORT
      LAYER M4 ;
        RECT  0 87.552 0.084 87.576 ;
    END
  END k_lo_d[451]
  PIN k_lo_d[452]
    DIRECTION INPUT ;
    USE SIGNAL ;
    PORT
      LAYER M4 ;
        RECT  0 87.744 0.084 87.768 ;
    END
  END k_lo_d[452]
  PIN k_lo_d[453]
    DIRECTION INPUT ;
    USE SIGNAL ;
    PORT
      LAYER M4 ;
        RECT  0 87.888 0.084 87.912 ;
    END
  END k_lo_d[453]
  PIN k_lo_d[454]
    DIRECTION INPUT ;
    USE SIGNAL ;
    PORT
      LAYER M4 ;
        RECT  0 88.08 0.084 88.104 ;
    END
  END k_lo_d[454]
  PIN k_lo_d[455]
    DIRECTION INPUT ;
    USE SIGNAL ;
    PORT
      LAYER M4 ;
        RECT  0 88.272 0.084 88.296 ;
    END
  END k_lo_d[455]
  PIN k_lo_d[456]
    DIRECTION INPUT ;
    USE SIGNAL ;
    PORT
      LAYER M4 ;
        RECT  0 88.464 0.084 88.488 ;
    END
  END k_lo_d[456]
  PIN k_lo_d[457]
    DIRECTION INPUT ;
    USE SIGNAL ;
    PORT
      LAYER M4 ;
        RECT  0 88.608 0.084 88.632 ;
    END
  END k_lo_d[457]
  PIN k_lo_d[458]
    DIRECTION INPUT ;
    USE SIGNAL ;
    PORT
      LAYER M4 ;
        RECT  0 88.8 0.084 88.824 ;
    END
  END k_lo_d[458]
  PIN k_lo_d[459]
    DIRECTION INPUT ;
    USE SIGNAL ;
    PORT
      LAYER M4 ;
        RECT  0 88.992 0.084 89.016 ;
    END
  END k_lo_d[459]
  PIN k_lo_d[45]
    DIRECTION INPUT ;
    USE SIGNAL ;
    PORT
      LAYER M4 ;
        RECT  0 14.496 0.084 14.52 ;
    END
  END k_lo_d[45]
  PIN k_lo_d[460]
    DIRECTION INPUT ;
    USE SIGNAL ;
    PORT
      LAYER M4 ;
        RECT  0 89.184 0.084 89.208 ;
    END
  END k_lo_d[460]
  PIN k_lo_d[461]
    DIRECTION INPUT ;
    USE SIGNAL ;
    PORT
      LAYER M4 ;
        RECT  0 89.328 0.084 89.352 ;
    END
  END k_lo_d[461]
  PIN k_lo_d[462]
    DIRECTION INPUT ;
    USE SIGNAL ;
    PORT
      LAYER M4 ;
        RECT  0 89.52 0.084 89.544 ;
    END
  END k_lo_d[462]
  PIN k_lo_d[463]
    DIRECTION INPUT ;
    USE SIGNAL ;
    PORT
      LAYER M4 ;
        RECT  0 89.712 0.084 89.736 ;
    END
  END k_lo_d[463]
  PIN k_lo_d[464]
    DIRECTION INPUT ;
    USE SIGNAL ;
    PORT
      LAYER M4 ;
        RECT  0 89.904 0.084 89.928 ;
    END
  END k_lo_d[464]
  PIN k_lo_d[465]
    DIRECTION INPUT ;
    USE SIGNAL ;
    PORT
      LAYER M4 ;
        RECT  0 90.048 0.084 90.072 ;
    END
  END k_lo_d[465]
  PIN k_lo_d[466]
    DIRECTION INPUT ;
    USE SIGNAL ;
    PORT
      LAYER M4 ;
        RECT  0 90.24 0.084 90.264 ;
    END
  END k_lo_d[466]
  PIN k_lo_d[467]
    DIRECTION INPUT ;
    USE SIGNAL ;
    PORT
      LAYER M4 ;
        RECT  0 90.432 0.084 90.456 ;
    END
  END k_lo_d[467]
  PIN k_lo_d[468]
    DIRECTION INPUT ;
    USE SIGNAL ;
    PORT
      LAYER M4 ;
        RECT  0 90.624 0.084 90.648 ;
    END
  END k_lo_d[468]
  PIN k_lo_d[469]
    DIRECTION INPUT ;
    USE SIGNAL ;
    PORT
      LAYER M4 ;
        RECT  0 90.768 0.084 90.792 ;
    END
  END k_lo_d[469]
  PIN k_lo_d[46]
    DIRECTION INPUT ;
    USE SIGNAL ;
    PORT
      LAYER M4 ;
        RECT  0 14.688 0.084 14.712 ;
    END
  END k_lo_d[46]
  PIN k_lo_d[470]
    DIRECTION INPUT ;
    USE SIGNAL ;
    PORT
      LAYER M4 ;
        RECT  0 90.96 0.084 90.984 ;
    END
  END k_lo_d[470]
  PIN k_lo_d[471]
    DIRECTION INPUT ;
    USE SIGNAL ;
    PORT
      LAYER M4 ;
        RECT  0 91.152 0.084 91.176 ;
    END
  END k_lo_d[471]
  PIN k_lo_d[472]
    DIRECTION INPUT ;
    USE SIGNAL ;
    PORT
      LAYER M4 ;
        RECT  0 91.344 0.084 91.368 ;
    END
  END k_lo_d[472]
  PIN k_lo_d[473]
    DIRECTION INPUT ;
    USE SIGNAL ;
    PORT
      LAYER M4 ;
        RECT  0 91.488 0.084 91.512 ;
    END
  END k_lo_d[473]
  PIN k_lo_d[474]
    DIRECTION INPUT ;
    USE SIGNAL ;
    PORT
      LAYER M4 ;
        RECT  0 91.68 0.084 91.704 ;
    END
  END k_lo_d[474]
  PIN k_lo_d[475]
    DIRECTION INPUT ;
    USE SIGNAL ;
    PORT
      LAYER M4 ;
        RECT  0 91.872 0.084 91.896 ;
    END
  END k_lo_d[475]
  PIN k_lo_d[476]
    DIRECTION INPUT ;
    USE SIGNAL ;
    PORT
      LAYER M4 ;
        RECT  0 92.064 0.084 92.088 ;
    END
  END k_lo_d[476]
  PIN k_lo_d[477]
    DIRECTION INPUT ;
    USE SIGNAL ;
    PORT
      LAYER M4 ;
        RECT  0 92.208 0.084 92.232 ;
    END
  END k_lo_d[477]
  PIN k_lo_d[478]
    DIRECTION INPUT ;
    USE SIGNAL ;
    PORT
      LAYER M4 ;
        RECT  0 92.4 0.084 92.424 ;
    END
  END k_lo_d[478]
  PIN k_lo_d[479]
    DIRECTION INPUT ;
    USE SIGNAL ;
    PORT
      LAYER M4 ;
        RECT  0 92.592 0.084 92.616 ;
    END
  END k_lo_d[479]
  PIN k_lo_d[47]
    DIRECTION INPUT ;
    USE SIGNAL ;
    PORT
      LAYER M4 ;
        RECT  0 14.88 0.084 14.904 ;
    END
  END k_lo_d[47]
  PIN k_lo_d[480]
    DIRECTION INPUT ;
    USE SIGNAL ;
    PORT
      LAYER M4 ;
        RECT  0 92.784 0.084 92.808 ;
    END
  END k_lo_d[480]
  PIN k_lo_d[481]
    DIRECTION INPUT ;
    USE SIGNAL ;
    PORT
      LAYER M4 ;
        RECT  0 92.928 0.084 92.952 ;
    END
  END k_lo_d[481]
  PIN k_lo_d[482]
    DIRECTION INPUT ;
    USE SIGNAL ;
    PORT
      LAYER M4 ;
        RECT  0 93.12 0.084 93.144 ;
    END
  END k_lo_d[482]
  PIN k_lo_d[483]
    DIRECTION INPUT ;
    USE SIGNAL ;
    PORT
      LAYER M4 ;
        RECT  0 93.312 0.084 93.336 ;
    END
  END k_lo_d[483]
  PIN k_lo_d[484]
    DIRECTION INPUT ;
    USE SIGNAL ;
    PORT
      LAYER M4 ;
        RECT  0 93.504 0.084 93.528 ;
    END
  END k_lo_d[484]
  PIN k_lo_d[485]
    DIRECTION INPUT ;
    USE SIGNAL ;
    PORT
      LAYER M4 ;
        RECT  0 93.648 0.084 93.672 ;
    END
  END k_lo_d[485]
  PIN k_lo_d[486]
    DIRECTION INPUT ;
    USE SIGNAL ;
    PORT
      LAYER M4 ;
        RECT  0 93.84 0.084 93.864 ;
    END
  END k_lo_d[486]
  PIN k_lo_d[487]
    DIRECTION INPUT ;
    USE SIGNAL ;
    PORT
      LAYER M4 ;
        RECT  0 94.032 0.084 94.056 ;
    END
  END k_lo_d[487]
  PIN k_lo_d[488]
    DIRECTION INPUT ;
    USE SIGNAL ;
    PORT
      LAYER M4 ;
        RECT  0 94.176 0.084 94.2 ;
    END
  END k_lo_d[488]
  PIN k_lo_d[489]
    DIRECTION INPUT ;
    USE SIGNAL ;
    PORT
      LAYER M4 ;
        RECT  0 94.368 0.084 94.392 ;
    END
  END k_lo_d[489]
  PIN k_lo_d[48]
    DIRECTION INPUT ;
    USE SIGNAL ;
    PORT
      LAYER M4 ;
        RECT  0 15.024 0.084 15.048 ;
    END
  END k_lo_d[48]
  PIN k_lo_d[490]
    DIRECTION INPUT ;
    USE SIGNAL ;
    PORT
      LAYER M4 ;
        RECT  0 94.56 0.084 94.584 ;
    END
  END k_lo_d[490]
  PIN k_lo_d[491]
    DIRECTION INPUT ;
    USE SIGNAL ;
    PORT
      LAYER M4 ;
        RECT  0 94.752 0.084 94.776 ;
    END
  END k_lo_d[491]
  PIN k_lo_d[492]
    DIRECTION INPUT ;
    USE SIGNAL ;
    PORT
      LAYER M4 ;
        RECT  0 94.896 0.084 94.92 ;
    END
  END k_lo_d[492]
  PIN k_lo_d[493]
    DIRECTION INPUT ;
    USE SIGNAL ;
    PORT
      LAYER M4 ;
        RECT  0 95.088 0.084 95.112 ;
    END
  END k_lo_d[493]
  PIN k_lo_d[494]
    DIRECTION INPUT ;
    USE SIGNAL ;
    PORT
      LAYER M4 ;
        RECT  0 95.28 0.084 95.304 ;
    END
  END k_lo_d[494]
  PIN k_lo_d[495]
    DIRECTION INPUT ;
    USE SIGNAL ;
    PORT
      LAYER M4 ;
        RECT  0 95.472 0.084 95.496 ;
    END
  END k_lo_d[495]
  PIN k_lo_d[496]
    DIRECTION INPUT ;
    USE SIGNAL ;
    PORT
      LAYER M4 ;
        RECT  0 95.616 0.084 95.64 ;
    END
  END k_lo_d[496]
  PIN k_lo_d[497]
    DIRECTION INPUT ;
    USE SIGNAL ;
    PORT
      LAYER M4 ;
        RECT  0 95.808 0.084 95.832 ;
    END
  END k_lo_d[497]
  PIN k_lo_d[498]
    DIRECTION INPUT ;
    USE SIGNAL ;
    PORT
      LAYER M4 ;
        RECT  0 96 0.084 96.024 ;
    END
  END k_lo_d[498]
  PIN k_lo_d[499]
    DIRECTION INPUT ;
    USE SIGNAL ;
    PORT
      LAYER M4 ;
        RECT  0 96.192 0.084 96.216 ;
    END
  END k_lo_d[499]
  PIN k_lo_d[49]
    DIRECTION INPUT ;
    USE SIGNAL ;
    PORT
      LAYER M4 ;
        RECT  0 15.216 0.084 15.24 ;
    END
  END k_lo_d[49]
  PIN k_lo_d[4]
    DIRECTION INPUT ;
    USE SIGNAL ;
    PORT
      LAYER M4 ;
        RECT  0 7.104 0.084 7.128 ;
    END
  END k_lo_d[4]
  PIN k_lo_d[500]
    DIRECTION INPUT ;
    USE SIGNAL ;
    PORT
      LAYER M4 ;
        RECT  0 96.336 0.084 96.36 ;
    END
  END k_lo_d[500]
  PIN k_lo_d[501]
    DIRECTION INPUT ;
    USE SIGNAL ;
    PORT
      LAYER M4 ;
        RECT  0 96.528 0.084 96.552 ;
    END
  END k_lo_d[501]
  PIN k_lo_d[502]
    DIRECTION INPUT ;
    USE SIGNAL ;
    PORT
      LAYER M4 ;
        RECT  0 96.72 0.084 96.744 ;
    END
  END k_lo_d[502]
  PIN k_lo_d[503]
    DIRECTION INPUT ;
    USE SIGNAL ;
    PORT
      LAYER M4 ;
        RECT  0 96.912 0.084 96.936 ;
    END
  END k_lo_d[503]
  PIN k_lo_d[504]
    DIRECTION INPUT ;
    USE SIGNAL ;
    PORT
      LAYER M4 ;
        RECT  0 97.056 0.084 97.08 ;
    END
  END k_lo_d[504]
  PIN k_lo_d[505]
    DIRECTION INPUT ;
    USE SIGNAL ;
    PORT
      LAYER M4 ;
        RECT  0 97.248 0.084 97.272 ;
    END
  END k_lo_d[505]
  PIN k_lo_d[506]
    DIRECTION INPUT ;
    USE SIGNAL ;
    PORT
      LAYER M4 ;
        RECT  0 97.44 0.084 97.464 ;
    END
  END k_lo_d[506]
  PIN k_lo_d[507]
    DIRECTION INPUT ;
    USE SIGNAL ;
    PORT
      LAYER M4 ;
        RECT  0 97.632 0.084 97.656 ;
    END
  END k_lo_d[507]
  PIN k_lo_d[508]
    DIRECTION INPUT ;
    USE SIGNAL ;
    PORT
      LAYER M4 ;
        RECT  0 97.776 0.084 97.8 ;
    END
  END k_lo_d[508]
  PIN k_lo_d[509]
    DIRECTION INPUT ;
    USE SIGNAL ;
    PORT
      LAYER M4 ;
        RECT  0 97.968 0.084 97.992 ;
    END
  END k_lo_d[509]
  PIN k_lo_d[50]
    DIRECTION INPUT ;
    USE SIGNAL ;
    PORT
      LAYER M4 ;
        RECT  0 15.408 0.084 15.432 ;
    END
  END k_lo_d[50]
  PIN k_lo_d[510]
    DIRECTION INPUT ;
    USE SIGNAL ;
    PORT
      LAYER M4 ;
        RECT  0 98.16 0.084 98.184 ;
    END
  END k_lo_d[510]
  PIN k_lo_d[511]
    DIRECTION INPUT ;
    USE SIGNAL ;
    PORT
      LAYER M4 ;
        RECT  0 98.352 0.084 98.376 ;
    END
  END k_lo_d[511]
  PIN k_lo_d[512]
    DIRECTION INPUT ;
    USE SIGNAL ;
    PORT
      LAYER M4 ;
        RECT  0 98.496 0.084 98.52 ;
    END
  END k_lo_d[512]
  PIN k_lo_d[513]
    DIRECTION INPUT ;
    USE SIGNAL ;
    PORT
      LAYER M4 ;
        RECT  0 98.688 0.084 98.712 ;
    END
  END k_lo_d[513]
  PIN k_lo_d[514]
    DIRECTION INPUT ;
    USE SIGNAL ;
    PORT
      LAYER M4 ;
        RECT  0 98.88 0.084 98.904 ;
    END
  END k_lo_d[514]
  PIN k_lo_d[515]
    DIRECTION INPUT ;
    USE SIGNAL ;
    PORT
      LAYER M4 ;
        RECT  0 99.072 0.084 99.096 ;
    END
  END k_lo_d[515]
  PIN k_lo_d[516]
    DIRECTION INPUT ;
    USE SIGNAL ;
    PORT
      LAYER M4 ;
        RECT  0 99.216 0.084 99.24 ;
    END
  END k_lo_d[516]
  PIN k_lo_d[517]
    DIRECTION INPUT ;
    USE SIGNAL ;
    PORT
      LAYER M4 ;
        RECT  0 99.408 0.084 99.432 ;
    END
  END k_lo_d[517]
  PIN k_lo_d[518]
    DIRECTION INPUT ;
    USE SIGNAL ;
    PORT
      LAYER M4 ;
        RECT  0 99.6 0.084 99.624 ;
    END
  END k_lo_d[518]
  PIN k_lo_d[519]
    DIRECTION INPUT ;
    USE SIGNAL ;
    PORT
      LAYER M4 ;
        RECT  0 99.792 0.084 99.816 ;
    END
  END k_lo_d[519]
  PIN k_lo_d[51]
    DIRECTION INPUT ;
    USE SIGNAL ;
    PORT
      LAYER M4 ;
        RECT  0 15.6 0.084 15.624 ;
    END
  END k_lo_d[51]
  PIN k_lo_d[520]
    DIRECTION INPUT ;
    USE SIGNAL ;
    PORT
      LAYER M4 ;
        RECT  0 99.936 0.084 99.96 ;
    END
  END k_lo_d[520]
  PIN k_lo_d[521]
    DIRECTION INPUT ;
    USE SIGNAL ;
    PORT
      LAYER M4 ;
        RECT  0 100.128 0.084 100.152 ;
    END
  END k_lo_d[521]
  PIN k_lo_d[522]
    DIRECTION INPUT ;
    USE SIGNAL ;
    PORT
      LAYER M4 ;
        RECT  0 100.32 0.084 100.344 ;
    END
  END k_lo_d[522]
  PIN k_lo_d[523]
    DIRECTION INPUT ;
    USE SIGNAL ;
    PORT
      LAYER M4 ;
        RECT  0 100.512 0.084 100.536 ;
    END
  END k_lo_d[523]
  PIN k_lo_d[524]
    DIRECTION INPUT ;
    USE SIGNAL ;
    PORT
      LAYER M4 ;
        RECT  0 100.656 0.084 100.68 ;
    END
  END k_lo_d[524]
  PIN k_lo_d[525]
    DIRECTION INPUT ;
    USE SIGNAL ;
    PORT
      LAYER M4 ;
        RECT  0 100.848 0.084 100.872 ;
    END
  END k_lo_d[525]
  PIN k_lo_d[526]
    DIRECTION INPUT ;
    USE SIGNAL ;
    PORT
      LAYER M4 ;
        RECT  0 101.04 0.084 101.064 ;
    END
  END k_lo_d[526]
  PIN k_lo_d[527]
    DIRECTION INPUT ;
    USE SIGNAL ;
    PORT
      LAYER M4 ;
        RECT  0 101.232 0.084 101.256 ;
    END
  END k_lo_d[527]
  PIN k_lo_d[528]
    DIRECTION INPUT ;
    USE SIGNAL ;
    PORT
      LAYER M4 ;
        RECT  0 101.376 0.084 101.4 ;
    END
  END k_lo_d[528]
  PIN k_lo_d[529]
    DIRECTION INPUT ;
    USE SIGNAL ;
    PORT
      LAYER M4 ;
        RECT  0 101.568 0.084 101.592 ;
    END
  END k_lo_d[529]
  PIN k_lo_d[52]
    DIRECTION INPUT ;
    USE SIGNAL ;
    PORT
      LAYER M4 ;
        RECT  0 15.744 0.084 15.768 ;
    END
  END k_lo_d[52]
  PIN k_lo_d[530]
    DIRECTION INPUT ;
    USE SIGNAL ;
    PORT
      LAYER M4 ;
        RECT  0 101.76 0.084 101.784 ;
    END
  END k_lo_d[530]
  PIN k_lo_d[531]
    DIRECTION INPUT ;
    USE SIGNAL ;
    PORT
      LAYER M4 ;
        RECT  0 101.952 0.084 101.976 ;
    END
  END k_lo_d[531]
  PIN k_lo_d[532]
    DIRECTION INPUT ;
    USE SIGNAL ;
    PORT
      LAYER M4 ;
        RECT  0 102.096 0.084 102.12 ;
    END
  END k_lo_d[532]
  PIN k_lo_d[533]
    DIRECTION INPUT ;
    USE SIGNAL ;
    PORT
      LAYER M4 ;
        RECT  0 102.288 0.084 102.312 ;
    END
  END k_lo_d[533]
  PIN k_lo_d[534]
    DIRECTION INPUT ;
    USE SIGNAL ;
    PORT
      LAYER M4 ;
        RECT  0 102.48 0.084 102.504 ;
    END
  END k_lo_d[534]
  PIN k_lo_d[535]
    DIRECTION INPUT ;
    USE SIGNAL ;
    PORT
      LAYER M4 ;
        RECT  0 102.672 0.084 102.696 ;
    END
  END k_lo_d[535]
  PIN k_lo_d[536]
    DIRECTION INPUT ;
    USE SIGNAL ;
    PORT
      LAYER M4 ;
        RECT  0 102.816 0.084 102.84 ;
    END
  END k_lo_d[536]
  PIN k_lo_d[537]
    DIRECTION INPUT ;
    USE SIGNAL ;
    PORT
      LAYER M4 ;
        RECT  0 103.008 0.084 103.032 ;
    END
  END k_lo_d[537]
  PIN k_lo_d[538]
    DIRECTION INPUT ;
    USE SIGNAL ;
    PORT
      LAYER M4 ;
        RECT  0 103.2 0.084 103.224 ;
    END
  END k_lo_d[538]
  PIN k_lo_d[539]
    DIRECTION INPUT ;
    USE SIGNAL ;
    PORT
      LAYER M4 ;
        RECT  0 103.392 0.084 103.416 ;
    END
  END k_lo_d[539]
  PIN k_lo_d[53]
    DIRECTION INPUT ;
    USE SIGNAL ;
    PORT
      LAYER M4 ;
        RECT  0 15.936 0.084 15.96 ;
    END
  END k_lo_d[53]
  PIN k_lo_d[540]
    DIRECTION INPUT ;
    USE SIGNAL ;
    PORT
      LAYER M4 ;
        RECT  0 103.536 0.084 103.56 ;
    END
  END k_lo_d[540]
  PIN k_lo_d[541]
    DIRECTION INPUT ;
    USE SIGNAL ;
    PORT
      LAYER M4 ;
        RECT  0 103.728 0.084 103.752 ;
    END
  END k_lo_d[541]
  PIN k_lo_d[542]
    DIRECTION INPUT ;
    USE SIGNAL ;
    PORT
      LAYER M4 ;
        RECT  0 103.92 0.084 103.944 ;
    END
  END k_lo_d[542]
  PIN k_lo_d[543]
    DIRECTION INPUT ;
    USE SIGNAL ;
    PORT
      LAYER M4 ;
        RECT  0 104.112 0.084 104.136 ;
    END
  END k_lo_d[543]
  PIN k_lo_d[544]
    DIRECTION INPUT ;
    USE SIGNAL ;
    PORT
      LAYER M4 ;
        RECT  0 104.256 0.084 104.28 ;
    END
  END k_lo_d[544]
  PIN k_lo_d[545]
    DIRECTION INPUT ;
    USE SIGNAL ;
    PORT
      LAYER M4 ;
        RECT  0 104.448 0.084 104.472 ;
    END
  END k_lo_d[545]
  PIN k_lo_d[546]
    DIRECTION INPUT ;
    USE SIGNAL ;
    PORT
      LAYER M4 ;
        RECT  0 104.64 0.084 104.664 ;
    END
  END k_lo_d[546]
  PIN k_lo_d[547]
    DIRECTION INPUT ;
    USE SIGNAL ;
    PORT
      LAYER M4 ;
        RECT  0 104.832 0.084 104.856 ;
    END
  END k_lo_d[547]
  PIN k_lo_d[548]
    DIRECTION INPUT ;
    USE SIGNAL ;
    PORT
      LAYER M4 ;
        RECT  0 104.976 0.084 105 ;
    END
  END k_lo_d[548]
  PIN k_lo_d[549]
    DIRECTION INPUT ;
    USE SIGNAL ;
    PORT
      LAYER M4 ;
        RECT  0 105.168 0.084 105.192 ;
    END
  END k_lo_d[549]
  PIN k_lo_d[54]
    DIRECTION INPUT ;
    USE SIGNAL ;
    PORT
      LAYER M4 ;
        RECT  0 16.128 0.084 16.152 ;
    END
  END k_lo_d[54]
  PIN k_lo_d[550]
    DIRECTION INPUT ;
    USE SIGNAL ;
    PORT
      LAYER M4 ;
        RECT  0 105.36 0.084 105.384 ;
    END
  END k_lo_d[550]
  PIN k_lo_d[551]
    DIRECTION INPUT ;
    USE SIGNAL ;
    PORT
      LAYER M4 ;
        RECT  0 105.552 0.084 105.576 ;
    END
  END k_lo_d[551]
  PIN k_lo_d[552]
    DIRECTION INPUT ;
    USE SIGNAL ;
    PORT
      LAYER M4 ;
        RECT  0 105.696 0.084 105.72 ;
    END
  END k_lo_d[552]
  PIN k_lo_d[55]
    DIRECTION INPUT ;
    USE SIGNAL ;
    PORT
      LAYER M4 ;
        RECT  0 16.32 0.084 16.344 ;
    END
  END k_lo_d[55]
  PIN k_lo_d[56]
    DIRECTION INPUT ;
    USE SIGNAL ;
    PORT
      LAYER M4 ;
        RECT  0 16.464 0.084 16.488 ;
    END
  END k_lo_d[56]
  PIN k_lo_d[57]
    DIRECTION INPUT ;
    USE SIGNAL ;
    PORT
      LAYER M4 ;
        RECT  0 16.656 0.084 16.68 ;
    END
  END k_lo_d[57]
  PIN k_lo_d[58]
    DIRECTION INPUT ;
    USE SIGNAL ;
    PORT
      LAYER M4 ;
        RECT  0 16.848 0.084 16.872 ;
    END
  END k_lo_d[58]
  PIN k_lo_d[59]
    DIRECTION INPUT ;
    USE SIGNAL ;
    PORT
      LAYER M4 ;
        RECT  0 17.04 0.084 17.064 ;
    END
  END k_lo_d[59]
  PIN k_lo_d[5]
    DIRECTION INPUT ;
    USE SIGNAL ;
    PORT
      LAYER M4 ;
        RECT  0 7.296 0.084 7.32 ;
    END
  END k_lo_d[5]
  PIN k_lo_d[60]
    DIRECTION INPUT ;
    USE SIGNAL ;
    PORT
      LAYER M4 ;
        RECT  0 17.184 0.084 17.208 ;
    END
  END k_lo_d[60]
  PIN k_lo_d[61]
    DIRECTION INPUT ;
    USE SIGNAL ;
    PORT
      LAYER M4 ;
        RECT  0 17.376 0.084 17.4 ;
    END
  END k_lo_d[61]
  PIN k_lo_d[62]
    DIRECTION INPUT ;
    USE SIGNAL ;
    PORT
      LAYER M4 ;
        RECT  0 17.568 0.084 17.592 ;
    END
  END k_lo_d[62]
  PIN k_lo_d[63]
    DIRECTION INPUT ;
    USE SIGNAL ;
    PORT
      LAYER M4 ;
        RECT  0 17.76 0.084 17.784 ;
    END
  END k_lo_d[63]
  PIN k_lo_d[64]
    DIRECTION INPUT ;
    USE SIGNAL ;
    PORT
      LAYER M4 ;
        RECT  0 17.904 0.084 17.928 ;
    END
  END k_lo_d[64]
  PIN k_lo_d[65]
    DIRECTION INPUT ;
    USE SIGNAL ;
    PORT
      LAYER M4 ;
        RECT  0 18.096 0.084 18.12 ;
    END
  END k_lo_d[65]
  PIN k_lo_d[66]
    DIRECTION INPUT ;
    USE SIGNAL ;
    PORT
      LAYER M4 ;
        RECT  0 18.288 0.084 18.312 ;
    END
  END k_lo_d[66]
  PIN k_lo_d[67]
    DIRECTION INPUT ;
    USE SIGNAL ;
    PORT
      LAYER M4 ;
        RECT  0 18.48 0.084 18.504 ;
    END
  END k_lo_d[67]
  PIN k_lo_d[68]
    DIRECTION INPUT ;
    USE SIGNAL ;
    PORT
      LAYER M4 ;
        RECT  0 18.624 0.084 18.648 ;
    END
  END k_lo_d[68]
  PIN k_lo_d[69]
    DIRECTION INPUT ;
    USE SIGNAL ;
    PORT
      LAYER M4 ;
        RECT  0 18.816 0.084 18.84 ;
    END
  END k_lo_d[69]
  PIN k_lo_d[6]
    DIRECTION INPUT ;
    USE SIGNAL ;
    PORT
      LAYER M4 ;
        RECT  0 7.488 0.084 7.512 ;
    END
  END k_lo_d[6]
  PIN k_lo_d[70]
    DIRECTION INPUT ;
    USE SIGNAL ;
    PORT
      LAYER M4 ;
        RECT  0 19.008 0.084 19.032 ;
    END
  END k_lo_d[70]
  PIN k_lo_d[71]
    DIRECTION INPUT ;
    USE SIGNAL ;
    PORT
      LAYER M4 ;
        RECT  0 19.152 0.084 19.176 ;
    END
  END k_lo_d[71]
  PIN k_lo_d[72]
    DIRECTION INPUT ;
    USE SIGNAL ;
    PORT
      LAYER M4 ;
        RECT  0 19.344 0.084 19.368 ;
    END
  END k_lo_d[72]
  PIN k_lo_d[73]
    DIRECTION INPUT ;
    USE SIGNAL ;
    PORT
      LAYER M4 ;
        RECT  0 19.536 0.084 19.56 ;
    END
  END k_lo_d[73]
  PIN k_lo_d[74]
    DIRECTION INPUT ;
    USE SIGNAL ;
    PORT
      LAYER M4 ;
        RECT  0 19.728 0.084 19.752 ;
    END
  END k_lo_d[74]
  PIN k_lo_d[75]
    DIRECTION INPUT ;
    USE SIGNAL ;
    PORT
      LAYER M4 ;
        RECT  0 19.872 0.084 19.896 ;
    END
  END k_lo_d[75]
  PIN k_lo_d[76]
    DIRECTION INPUT ;
    USE SIGNAL ;
    PORT
      LAYER M4 ;
        RECT  0 20.064 0.084 20.088 ;
    END
  END k_lo_d[76]
  PIN k_lo_d[77]
    DIRECTION INPUT ;
    USE SIGNAL ;
    PORT
      LAYER M4 ;
        RECT  0 20.256 0.084 20.28 ;
    END
  END k_lo_d[77]
  PIN k_lo_d[78]
    DIRECTION INPUT ;
    USE SIGNAL ;
    PORT
      LAYER M4 ;
        RECT  0 20.448 0.084 20.472 ;
    END
  END k_lo_d[78]
  PIN k_lo_d[79]
    DIRECTION INPUT ;
    USE SIGNAL ;
    PORT
      LAYER M4 ;
        RECT  0 20.592 0.084 20.616 ;
    END
  END k_lo_d[79]
  PIN k_lo_d[7]
    DIRECTION INPUT ;
    USE SIGNAL ;
    PORT
      LAYER M4 ;
        RECT  0 7.68 0.084 7.704 ;
    END
  END k_lo_d[7]
  PIN k_lo_d[80]
    DIRECTION INPUT ;
    USE SIGNAL ;
    PORT
      LAYER M4 ;
        RECT  0 20.784 0.084 20.808 ;
    END
  END k_lo_d[80]
  PIN k_lo_d[81]
    DIRECTION INPUT ;
    USE SIGNAL ;
    PORT
      LAYER M4 ;
        RECT  0 20.976 0.084 21 ;
    END
  END k_lo_d[81]
  PIN k_lo_d[82]
    DIRECTION INPUT ;
    USE SIGNAL ;
    PORT
      LAYER M4 ;
        RECT  0 21.168 0.084 21.192 ;
    END
  END k_lo_d[82]
  PIN k_lo_d[83]
    DIRECTION INPUT ;
    USE SIGNAL ;
    PORT
      LAYER M4 ;
        RECT  0 21.312 0.084 21.336 ;
    END
  END k_lo_d[83]
  PIN k_lo_d[84]
    DIRECTION INPUT ;
    USE SIGNAL ;
    PORT
      LAYER M4 ;
        RECT  0 21.504 0.084 21.528 ;
    END
  END k_lo_d[84]
  PIN k_lo_d[85]
    DIRECTION INPUT ;
    USE SIGNAL ;
    PORT
      LAYER M4 ;
        RECT  0 21.696 0.084 21.72 ;
    END
  END k_lo_d[85]
  PIN k_lo_d[86]
    DIRECTION INPUT ;
    USE SIGNAL ;
    PORT
      LAYER M4 ;
        RECT  0 21.888 0.084 21.912 ;
    END
  END k_lo_d[86]
  PIN k_lo_d[87]
    DIRECTION INPUT ;
    USE SIGNAL ;
    PORT
      LAYER M4 ;
        RECT  0 22.032 0.084 22.056 ;
    END
  END k_lo_d[87]
  PIN k_lo_d[88]
    DIRECTION INPUT ;
    USE SIGNAL ;
    PORT
      LAYER M4 ;
        RECT  0 22.224 0.084 22.248 ;
    END
  END k_lo_d[88]
  PIN k_lo_d[89]
    DIRECTION INPUT ;
    USE SIGNAL ;
    PORT
      LAYER M4 ;
        RECT  0 22.416 0.084 22.44 ;
    END
  END k_lo_d[89]
  PIN k_lo_d[8]
    DIRECTION INPUT ;
    USE SIGNAL ;
    PORT
      LAYER M4 ;
        RECT  0 7.824 0.084 7.848 ;
    END
  END k_lo_d[8]
  PIN k_lo_d[90]
    DIRECTION INPUT ;
    USE SIGNAL ;
    PORT
      LAYER M4 ;
        RECT  0 22.608 0.084 22.632 ;
    END
  END k_lo_d[90]
  PIN k_lo_d[91]
    DIRECTION INPUT ;
    USE SIGNAL ;
    PORT
      LAYER M4 ;
        RECT  0 22.752 0.084 22.776 ;
    END
  END k_lo_d[91]
  PIN k_lo_d[92]
    DIRECTION INPUT ;
    USE SIGNAL ;
    PORT
      LAYER M4 ;
        RECT  0 22.944 0.084 22.968 ;
    END
  END k_lo_d[92]
  PIN k_lo_d[93]
    DIRECTION INPUT ;
    USE SIGNAL ;
    PORT
      LAYER M4 ;
        RECT  0 23.136 0.084 23.16 ;
    END
  END k_lo_d[93]
  PIN k_lo_d[94]
    DIRECTION INPUT ;
    USE SIGNAL ;
    PORT
      LAYER M4 ;
        RECT  0 23.328 0.084 23.352 ;
    END
  END k_lo_d[94]
  PIN k_lo_d[95]
    DIRECTION INPUT ;
    USE SIGNAL ;
    PORT
      LAYER M4 ;
        RECT  0 23.472 0.084 23.496 ;
    END
  END k_lo_d[95]
  PIN k_lo_d[96]
    DIRECTION INPUT ;
    USE SIGNAL ;
    PORT
      LAYER M4 ;
        RECT  0 23.664 0.084 23.688 ;
    END
  END k_lo_d[96]
  PIN k_lo_d[97]
    DIRECTION INPUT ;
    USE SIGNAL ;
    PORT
      LAYER M4 ;
        RECT  0 23.856 0.084 23.88 ;
    END
  END k_lo_d[97]
  PIN k_lo_d[98]
    DIRECTION INPUT ;
    USE SIGNAL ;
    PORT
      LAYER M4 ;
        RECT  0 24.048 0.084 24.072 ;
    END
  END k_lo_d[98]
  PIN k_lo_d[99]
    DIRECTION INPUT ;
    USE SIGNAL ;
    PORT
      LAYER M4 ;
        RECT  0 24.192 0.084 24.216 ;
    END
  END k_lo_d[99]
  PIN k_lo_d[9]
    DIRECTION INPUT ;
    USE SIGNAL ;
    PORT
      LAYER M4 ;
        RECT  0 8.016 0.084 8.04 ;
    END
  END k_lo_d[9]
  PIN k_lo_r
    DIRECTION OUTPUT ;
    USE SIGNAL ;
    PORT
      LAYER M5 ;
        RECT  6.192 0 6.216 0.084 ;
    END
  END k_lo_r
  PIN k_lo_v
    DIRECTION INPUT ;
    USE SIGNAL ;
    PORT
      LAYER M4 ;
        RECT  0 6.24 0.084 6.264 ;
    END
  END k_lo_v
  PIN k_rxv
    DIRECTION INPUT ;
    USE SIGNAL ;
    PORT
      LAYER M4 ;
        RECT  0 106.08 0.084 106.104 ;
    END
  END k_rxv
  PIN n_flt[0]
    DIRECTION INPUT ;
    USE SIGNAL ;
    PORT
      LAYER M4 ;
        RECT  112.236 105.696 112.32 105.72 ;
    END
  END n_flt[0]
  PIN n_flt[1]
    DIRECTION INPUT ;
    USE SIGNAL ;
    PORT
      LAYER M4 ;
        RECT  112.236 105.888 112.32 105.912 ;
    END
  END n_flt[1]
  PIN n_flt[2]
    DIRECTION INPUT ;
    USE SIGNAL ;
    PORT
      LAYER M4 ;
        RECT  112.236 106.08 112.32 106.104 ;
    END
  END n_flt[2]
  PIN n_li_d[0]
    DIRECTION INPUT ;
    USE SIGNAL ;
    PORT
      LAYER M4 ;
        RECT  112.236 6.576 112.32 6.6 ;
    END
  END n_li_d[0]
  PIN n_li_d[100]
    DIRECTION INPUT ;
    USE SIGNAL ;
    PORT
      LAYER M4 ;
        RECT  112.236 24.528 112.32 24.552 ;
    END
  END n_li_d[100]
  PIN n_li_d[101]
    DIRECTION INPUT ;
    USE SIGNAL ;
    PORT
      LAYER M4 ;
        RECT  112.236 24.672 112.32 24.696 ;
    END
  END n_li_d[101]
  PIN n_li_d[102]
    DIRECTION INPUT ;
    USE SIGNAL ;
    PORT
      LAYER M4 ;
        RECT  112.236 24.864 112.32 24.888 ;
    END
  END n_li_d[102]
  PIN n_li_d[103]
    DIRECTION INPUT ;
    USE SIGNAL ;
    PORT
      LAYER M4 ;
        RECT  112.236 25.056 112.32 25.08 ;
    END
  END n_li_d[103]
  PIN n_li_d[104]
    DIRECTION INPUT ;
    USE SIGNAL ;
    PORT
      LAYER M4 ;
        RECT  112.236 25.248 112.32 25.272 ;
    END
  END n_li_d[104]
  PIN n_li_d[105]
    DIRECTION INPUT ;
    USE SIGNAL ;
    PORT
      LAYER M4 ;
        RECT  112.236 25.392 112.32 25.416 ;
    END
  END n_li_d[105]
  PIN n_li_d[106]
    DIRECTION INPUT ;
    USE SIGNAL ;
    PORT
      LAYER M4 ;
        RECT  112.236 25.584 112.32 25.608 ;
    END
  END n_li_d[106]
  PIN n_li_d[107]
    DIRECTION INPUT ;
    USE SIGNAL ;
    PORT
      LAYER M4 ;
        RECT  112.236 25.776 112.32 25.8 ;
    END
  END n_li_d[107]
  PIN n_li_d[108]
    DIRECTION INPUT ;
    USE SIGNAL ;
    PORT
      LAYER M4 ;
        RECT  112.236 25.92 112.32 25.944 ;
    END
  END n_li_d[108]
  PIN n_li_d[109]
    DIRECTION INPUT ;
    USE SIGNAL ;
    PORT
      LAYER M4 ;
        RECT  112.236 26.112 112.32 26.136 ;
    END
  END n_li_d[109]
  PIN n_li_d[10]
    DIRECTION INPUT ;
    USE SIGNAL ;
    PORT
      LAYER M4 ;
        RECT  112.236 8.352 112.32 8.376 ;
    END
  END n_li_d[10]
  PIN n_li_d[110]
    DIRECTION INPUT ;
    USE SIGNAL ;
    PORT
      LAYER M4 ;
        RECT  112.236 26.304 112.32 26.328 ;
    END
  END n_li_d[110]
  PIN n_li_d[111]
    DIRECTION INPUT ;
    USE SIGNAL ;
    PORT
      LAYER M4 ;
        RECT  112.236 26.496 112.32 26.52 ;
    END
  END n_li_d[111]
  PIN n_li_d[112]
    DIRECTION INPUT ;
    USE SIGNAL ;
    PORT
      LAYER M4 ;
        RECT  112.236 26.64 112.32 26.664 ;
    END
  END n_li_d[112]
  PIN n_li_d[113]
    DIRECTION INPUT ;
    USE SIGNAL ;
    PORT
      LAYER M4 ;
        RECT  112.236 26.832 112.32 26.856 ;
    END
  END n_li_d[113]
  PIN n_li_d[114]
    DIRECTION INPUT ;
    USE SIGNAL ;
    PORT
      LAYER M4 ;
        RECT  112.236 27.024 112.32 27.048 ;
    END
  END n_li_d[114]
  PIN n_li_d[115]
    DIRECTION INPUT ;
    USE SIGNAL ;
    PORT
      LAYER M4 ;
        RECT  112.236 27.216 112.32 27.24 ;
    END
  END n_li_d[115]
  PIN n_li_d[116]
    DIRECTION INPUT ;
    USE SIGNAL ;
    PORT
      LAYER M4 ;
        RECT  112.236 27.36 112.32 27.384 ;
    END
  END n_li_d[116]
  PIN n_li_d[117]
    DIRECTION INPUT ;
    USE SIGNAL ;
    PORT
      LAYER M4 ;
        RECT  112.236 27.552 112.32 27.576 ;
    END
  END n_li_d[117]
  PIN n_li_d[118]
    DIRECTION INPUT ;
    USE SIGNAL ;
    PORT
      LAYER M4 ;
        RECT  112.236 27.744 112.32 27.768 ;
    END
  END n_li_d[118]
  PIN n_li_d[119]
    DIRECTION INPUT ;
    USE SIGNAL ;
    PORT
      LAYER M4 ;
        RECT  112.236 27.936 112.32 27.96 ;
    END
  END n_li_d[119]
  PIN n_li_d[11]
    DIRECTION INPUT ;
    USE SIGNAL ;
    PORT
      LAYER M4 ;
        RECT  112.236 8.544 112.32 8.568 ;
    END
  END n_li_d[11]
  PIN n_li_d[120]
    DIRECTION INPUT ;
    USE SIGNAL ;
    PORT
      LAYER M4 ;
        RECT  112.236 28.08 112.32 28.104 ;
    END
  END n_li_d[120]
  PIN n_li_d[121]
    DIRECTION INPUT ;
    USE SIGNAL ;
    PORT
      LAYER M4 ;
        RECT  112.236 28.272 112.32 28.296 ;
    END
  END n_li_d[121]
  PIN n_li_d[122]
    DIRECTION INPUT ;
    USE SIGNAL ;
    PORT
      LAYER M4 ;
        RECT  112.236 28.464 112.32 28.488 ;
    END
  END n_li_d[122]
  PIN n_li_d[123]
    DIRECTION INPUT ;
    USE SIGNAL ;
    PORT
      LAYER M4 ;
        RECT  112.236 28.608 112.32 28.632 ;
    END
  END n_li_d[123]
  PIN n_li_d[124]
    DIRECTION INPUT ;
    USE SIGNAL ;
    PORT
      LAYER M4 ;
        RECT  112.236 28.8 112.32 28.824 ;
    END
  END n_li_d[124]
  PIN n_li_d[125]
    DIRECTION INPUT ;
    USE SIGNAL ;
    PORT
      LAYER M4 ;
        RECT  112.236 28.992 112.32 29.016 ;
    END
  END n_li_d[125]
  PIN n_li_d[126]
    DIRECTION INPUT ;
    USE SIGNAL ;
    PORT
      LAYER M4 ;
        RECT  112.236 29.184 112.32 29.208 ;
    END
  END n_li_d[126]
  PIN n_li_d[127]
    DIRECTION INPUT ;
    USE SIGNAL ;
    PORT
      LAYER M4 ;
        RECT  112.236 29.328 112.32 29.352 ;
    END
  END n_li_d[127]
  PIN n_li_d[128]
    DIRECTION INPUT ;
    USE SIGNAL ;
    PORT
      LAYER M4 ;
        RECT  112.236 29.52 112.32 29.544 ;
    END
  END n_li_d[128]
  PIN n_li_d[129]
    DIRECTION INPUT ;
    USE SIGNAL ;
    PORT
      LAYER M4 ;
        RECT  112.236 29.712 112.32 29.736 ;
    END
  END n_li_d[129]
  PIN n_li_d[12]
    DIRECTION INPUT ;
    USE SIGNAL ;
    PORT
      LAYER M4 ;
        RECT  112.236 8.736 112.32 8.76 ;
    END
  END n_li_d[12]
  PIN n_li_d[130]
    DIRECTION INPUT ;
    USE SIGNAL ;
    PORT
      LAYER M4 ;
        RECT  112.236 29.904 112.32 29.928 ;
    END
  END n_li_d[130]
  PIN n_li_d[131]
    DIRECTION INPUT ;
    USE SIGNAL ;
    PORT
      LAYER M4 ;
        RECT  112.236 30.048 112.32 30.072 ;
    END
  END n_li_d[131]
  PIN n_li_d[132]
    DIRECTION INPUT ;
    USE SIGNAL ;
    PORT
      LAYER M4 ;
        RECT  112.236 30.24 112.32 30.264 ;
    END
  END n_li_d[132]
  PIN n_li_d[133]
    DIRECTION INPUT ;
    USE SIGNAL ;
    PORT
      LAYER M4 ;
        RECT  112.236 30.432 112.32 30.456 ;
    END
  END n_li_d[133]
  PIN n_li_d[134]
    DIRECTION INPUT ;
    USE SIGNAL ;
    PORT
      LAYER M4 ;
        RECT  112.236 30.624 112.32 30.648 ;
    END
  END n_li_d[134]
  PIN n_li_d[135]
    DIRECTION INPUT ;
    USE SIGNAL ;
    PORT
      LAYER M4 ;
        RECT  112.236 30.768 112.32 30.792 ;
    END
  END n_li_d[135]
  PIN n_li_d[136]
    DIRECTION INPUT ;
    USE SIGNAL ;
    PORT
      LAYER M4 ;
        RECT  112.236 30.96 112.32 30.984 ;
    END
  END n_li_d[136]
  PIN n_li_d[137]
    DIRECTION INPUT ;
    USE SIGNAL ;
    PORT
      LAYER M4 ;
        RECT  112.236 31.152 112.32 31.176 ;
    END
  END n_li_d[137]
  PIN n_li_d[138]
    DIRECTION INPUT ;
    USE SIGNAL ;
    PORT
      LAYER M4 ;
        RECT  112.236 31.296 112.32 31.32 ;
    END
  END n_li_d[138]
  PIN n_li_d[139]
    DIRECTION INPUT ;
    USE SIGNAL ;
    PORT
      LAYER M4 ;
        RECT  112.236 31.488 112.32 31.512 ;
    END
  END n_li_d[139]
  PIN n_li_d[13]
    DIRECTION INPUT ;
    USE SIGNAL ;
    PORT
      LAYER M4 ;
        RECT  112.236 8.928 112.32 8.952 ;
    END
  END n_li_d[13]
  PIN n_li_d[140]
    DIRECTION INPUT ;
    USE SIGNAL ;
    PORT
      LAYER M4 ;
        RECT  112.236 31.68 112.32 31.704 ;
    END
  END n_li_d[140]
  PIN n_li_d[141]
    DIRECTION INPUT ;
    USE SIGNAL ;
    PORT
      LAYER M4 ;
        RECT  112.236 31.872 112.32 31.896 ;
    END
  END n_li_d[141]
  PIN n_li_d[142]
    DIRECTION INPUT ;
    USE SIGNAL ;
    PORT
      LAYER M4 ;
        RECT  112.236 32.016 112.32 32.04 ;
    END
  END n_li_d[142]
  PIN n_li_d[143]
    DIRECTION INPUT ;
    USE SIGNAL ;
    PORT
      LAYER M4 ;
        RECT  112.236 32.208 112.32 32.232 ;
    END
  END n_li_d[143]
  PIN n_li_d[144]
    DIRECTION INPUT ;
    USE SIGNAL ;
    PORT
      LAYER M4 ;
        RECT  112.236 32.4 112.32 32.424 ;
    END
  END n_li_d[144]
  PIN n_li_d[145]
    DIRECTION INPUT ;
    USE SIGNAL ;
    PORT
      LAYER M4 ;
        RECT  112.236 32.592 112.32 32.616 ;
    END
  END n_li_d[145]
  PIN n_li_d[146]
    DIRECTION INPUT ;
    USE SIGNAL ;
    PORT
      LAYER M4 ;
        RECT  112.236 32.736 112.32 32.76 ;
    END
  END n_li_d[146]
  PIN n_li_d[147]
    DIRECTION INPUT ;
    USE SIGNAL ;
    PORT
      LAYER M4 ;
        RECT  112.236 32.928 112.32 32.952 ;
    END
  END n_li_d[147]
  PIN n_li_d[148]
    DIRECTION INPUT ;
    USE SIGNAL ;
    PORT
      LAYER M4 ;
        RECT  112.236 33.12 112.32 33.144 ;
    END
  END n_li_d[148]
  PIN n_li_d[149]
    DIRECTION INPUT ;
    USE SIGNAL ;
    PORT
      LAYER M4 ;
        RECT  112.236 33.312 112.32 33.336 ;
    END
  END n_li_d[149]
  PIN n_li_d[14]
    DIRECTION INPUT ;
    USE SIGNAL ;
    PORT
      LAYER M4 ;
        RECT  112.236 9.072 112.32 9.096 ;
    END
  END n_li_d[14]
  PIN n_li_d[150]
    DIRECTION INPUT ;
    USE SIGNAL ;
    PORT
      LAYER M4 ;
        RECT  112.236 33.456 112.32 33.48 ;
    END
  END n_li_d[150]
  PIN n_li_d[151]
    DIRECTION INPUT ;
    USE SIGNAL ;
    PORT
      LAYER M4 ;
        RECT  112.236 33.648 112.32 33.672 ;
    END
  END n_li_d[151]
  PIN n_li_d[152]
    DIRECTION INPUT ;
    USE SIGNAL ;
    PORT
      LAYER M4 ;
        RECT  112.236 33.84 112.32 33.864 ;
    END
  END n_li_d[152]
  PIN n_li_d[153]
    DIRECTION INPUT ;
    USE SIGNAL ;
    PORT
      LAYER M4 ;
        RECT  112.236 34.032 112.32 34.056 ;
    END
  END n_li_d[153]
  PIN n_li_d[154]
    DIRECTION INPUT ;
    USE SIGNAL ;
    PORT
      LAYER M4 ;
        RECT  112.236 34.176 112.32 34.2 ;
    END
  END n_li_d[154]
  PIN n_li_d[155]
    DIRECTION INPUT ;
    USE SIGNAL ;
    PORT
      LAYER M4 ;
        RECT  112.236 34.368 112.32 34.392 ;
    END
  END n_li_d[155]
  PIN n_li_d[156]
    DIRECTION INPUT ;
    USE SIGNAL ;
    PORT
      LAYER M4 ;
        RECT  112.236 34.56 112.32 34.584 ;
    END
  END n_li_d[156]
  PIN n_li_d[157]
    DIRECTION INPUT ;
    USE SIGNAL ;
    PORT
      LAYER M4 ;
        RECT  112.236 34.704 112.32 34.728 ;
    END
  END n_li_d[157]
  PIN n_li_d[158]
    DIRECTION INPUT ;
    USE SIGNAL ;
    PORT
      LAYER M4 ;
        RECT  112.236 34.896 112.32 34.92 ;
    END
  END n_li_d[158]
  PIN n_li_d[159]
    DIRECTION INPUT ;
    USE SIGNAL ;
    PORT
      LAYER M4 ;
        RECT  112.236 35.088 112.32 35.112 ;
    END
  END n_li_d[159]
  PIN n_li_d[15]
    DIRECTION INPUT ;
    USE SIGNAL ;
    PORT
      LAYER M4 ;
        RECT  112.236 9.264 112.32 9.288 ;
    END
  END n_li_d[15]
  PIN n_li_d[160]
    DIRECTION INPUT ;
    USE SIGNAL ;
    PORT
      LAYER M4 ;
        RECT  112.236 35.28 112.32 35.304 ;
    END
  END n_li_d[160]
  PIN n_li_d[161]
    DIRECTION INPUT ;
    USE SIGNAL ;
    PORT
      LAYER M4 ;
        RECT  112.236 35.424 112.32 35.448 ;
    END
  END n_li_d[161]
  PIN n_li_d[162]
    DIRECTION INPUT ;
    USE SIGNAL ;
    PORT
      LAYER M4 ;
        RECT  112.236 35.616 112.32 35.64 ;
    END
  END n_li_d[162]
  PIN n_li_d[163]
    DIRECTION INPUT ;
    USE SIGNAL ;
    PORT
      LAYER M4 ;
        RECT  112.236 35.808 112.32 35.832 ;
    END
  END n_li_d[163]
  PIN n_li_d[164]
    DIRECTION INPUT ;
    USE SIGNAL ;
    PORT
      LAYER M4 ;
        RECT  112.236 36 112.32 36.024 ;
    END
  END n_li_d[164]
  PIN n_li_d[165]
    DIRECTION INPUT ;
    USE SIGNAL ;
    PORT
      LAYER M4 ;
        RECT  112.236 36.144 112.32 36.168 ;
    END
  END n_li_d[165]
  PIN n_li_d[166]
    DIRECTION INPUT ;
    USE SIGNAL ;
    PORT
      LAYER M4 ;
        RECT  112.236 36.336 112.32 36.36 ;
    END
  END n_li_d[166]
  PIN n_li_d[167]
    DIRECTION INPUT ;
    USE SIGNAL ;
    PORT
      LAYER M4 ;
        RECT  112.236 36.528 112.32 36.552 ;
    END
  END n_li_d[167]
  PIN n_li_d[168]
    DIRECTION INPUT ;
    USE SIGNAL ;
    PORT
      LAYER M4 ;
        RECT  112.236 36.72 112.32 36.744 ;
    END
  END n_li_d[168]
  PIN n_li_d[169]
    DIRECTION INPUT ;
    USE SIGNAL ;
    PORT
      LAYER M4 ;
        RECT  112.236 36.864 112.32 36.888 ;
    END
  END n_li_d[169]
  PIN n_li_d[16]
    DIRECTION INPUT ;
    USE SIGNAL ;
    PORT
      LAYER M4 ;
        RECT  112.236 9.456 112.32 9.48 ;
    END
  END n_li_d[16]
  PIN n_li_d[170]
    DIRECTION INPUT ;
    USE SIGNAL ;
    PORT
      LAYER M4 ;
        RECT  112.236 37.056 112.32 37.08 ;
    END
  END n_li_d[170]
  PIN n_li_d[171]
    DIRECTION INPUT ;
    USE SIGNAL ;
    PORT
      LAYER M4 ;
        RECT  112.236 37.248 112.32 37.272 ;
    END
  END n_li_d[171]
  PIN n_li_d[172]
    DIRECTION INPUT ;
    USE SIGNAL ;
    PORT
      LAYER M4 ;
        RECT  112.236 37.392 112.32 37.416 ;
    END
  END n_li_d[172]
  PIN n_li_d[173]
    DIRECTION INPUT ;
    USE SIGNAL ;
    PORT
      LAYER M4 ;
        RECT  112.236 37.584 112.32 37.608 ;
    END
  END n_li_d[173]
  PIN n_li_d[174]
    DIRECTION INPUT ;
    USE SIGNAL ;
    PORT
      LAYER M4 ;
        RECT  112.236 37.776 112.32 37.8 ;
    END
  END n_li_d[174]
  PIN n_li_d[175]
    DIRECTION INPUT ;
    USE SIGNAL ;
    PORT
      LAYER M4 ;
        RECT  112.236 37.968 112.32 37.992 ;
    END
  END n_li_d[175]
  PIN n_li_d[176]
    DIRECTION INPUT ;
    USE SIGNAL ;
    PORT
      LAYER M4 ;
        RECT  112.236 38.112 112.32 38.136 ;
    END
  END n_li_d[176]
  PIN n_li_d[177]
    DIRECTION INPUT ;
    USE SIGNAL ;
    PORT
      LAYER M4 ;
        RECT  112.236 38.304 112.32 38.328 ;
    END
  END n_li_d[177]
  PIN n_li_d[178]
    DIRECTION INPUT ;
    USE SIGNAL ;
    PORT
      LAYER M4 ;
        RECT  112.236 38.496 112.32 38.52 ;
    END
  END n_li_d[178]
  PIN n_li_d[179]
    DIRECTION INPUT ;
    USE SIGNAL ;
    PORT
      LAYER M4 ;
        RECT  112.236 38.688 112.32 38.712 ;
    END
  END n_li_d[179]
  PIN n_li_d[17]
    DIRECTION INPUT ;
    USE SIGNAL ;
    PORT
      LAYER M4 ;
        RECT  112.236 9.648 112.32 9.672 ;
    END
  END n_li_d[17]
  PIN n_li_d[180]
    DIRECTION INPUT ;
    USE SIGNAL ;
    PORT
      LAYER M4 ;
        RECT  112.236 38.832 112.32 38.856 ;
    END
  END n_li_d[180]
  PIN n_li_d[181]
    DIRECTION INPUT ;
    USE SIGNAL ;
    PORT
      LAYER M4 ;
        RECT  112.236 39.024 112.32 39.048 ;
    END
  END n_li_d[181]
  PIN n_li_d[182]
    DIRECTION INPUT ;
    USE SIGNAL ;
    PORT
      LAYER M4 ;
        RECT  112.236 39.216 112.32 39.24 ;
    END
  END n_li_d[182]
  PIN n_li_d[183]
    DIRECTION INPUT ;
    USE SIGNAL ;
    PORT
      LAYER M4 ;
        RECT  112.236 39.408 112.32 39.432 ;
    END
  END n_li_d[183]
  PIN n_li_d[184]
    DIRECTION INPUT ;
    USE SIGNAL ;
    PORT
      LAYER M4 ;
        RECT  112.236 39.552 112.32 39.576 ;
    END
  END n_li_d[184]
  PIN n_li_d[185]
    DIRECTION INPUT ;
    USE SIGNAL ;
    PORT
      LAYER M4 ;
        RECT  112.236 39.744 112.32 39.768 ;
    END
  END n_li_d[185]
  PIN n_li_d[186]
    DIRECTION INPUT ;
    USE SIGNAL ;
    PORT
      LAYER M4 ;
        RECT  112.236 39.936 112.32 39.96 ;
    END
  END n_li_d[186]
  PIN n_li_d[187]
    DIRECTION INPUT ;
    USE SIGNAL ;
    PORT
      LAYER M4 ;
        RECT  112.236 40.08 112.32 40.104 ;
    END
  END n_li_d[187]
  PIN n_li_d[188]
    DIRECTION INPUT ;
    USE SIGNAL ;
    PORT
      LAYER M4 ;
        RECT  112.236 40.272 112.32 40.296 ;
    END
  END n_li_d[188]
  PIN n_li_d[189]
    DIRECTION INPUT ;
    USE SIGNAL ;
    PORT
      LAYER M4 ;
        RECT  112.236 40.464 112.32 40.488 ;
    END
  END n_li_d[189]
  PIN n_li_d[18]
    DIRECTION INPUT ;
    USE SIGNAL ;
    PORT
      LAYER M4 ;
        RECT  112.236 9.792 112.32 9.816 ;
    END
  END n_li_d[18]
  PIN n_li_d[190]
    DIRECTION INPUT ;
    USE SIGNAL ;
    PORT
      LAYER M4 ;
        RECT  112.236 40.656 112.32 40.68 ;
    END
  END n_li_d[190]
  PIN n_li_d[191]
    DIRECTION INPUT ;
    USE SIGNAL ;
    PORT
      LAYER M4 ;
        RECT  112.236 40.8 112.32 40.824 ;
    END
  END n_li_d[191]
  PIN n_li_d[192]
    DIRECTION INPUT ;
    USE SIGNAL ;
    PORT
      LAYER M4 ;
        RECT  112.236 40.992 112.32 41.016 ;
    END
  END n_li_d[192]
  PIN n_li_d[193]
    DIRECTION INPUT ;
    USE SIGNAL ;
    PORT
      LAYER M4 ;
        RECT  112.236 41.184 112.32 41.208 ;
    END
  END n_li_d[193]
  PIN n_li_d[194]
    DIRECTION INPUT ;
    USE SIGNAL ;
    PORT
      LAYER M4 ;
        RECT  112.236 41.376 112.32 41.4 ;
    END
  END n_li_d[194]
  PIN n_li_d[195]
    DIRECTION INPUT ;
    USE SIGNAL ;
    PORT
      LAYER M4 ;
        RECT  112.236 41.52 112.32 41.544 ;
    END
  END n_li_d[195]
  PIN n_li_d[196]
    DIRECTION INPUT ;
    USE SIGNAL ;
    PORT
      LAYER M4 ;
        RECT  112.236 41.712 112.32 41.736 ;
    END
  END n_li_d[196]
  PIN n_li_d[197]
    DIRECTION INPUT ;
    USE SIGNAL ;
    PORT
      LAYER M4 ;
        RECT  112.236 41.904 112.32 41.928 ;
    END
  END n_li_d[197]
  PIN n_li_d[198]
    DIRECTION INPUT ;
    USE SIGNAL ;
    PORT
      LAYER M4 ;
        RECT  112.236 42.096 112.32 42.12 ;
    END
  END n_li_d[198]
  PIN n_li_d[199]
    DIRECTION INPUT ;
    USE SIGNAL ;
    PORT
      LAYER M4 ;
        RECT  112.236 42.24 112.32 42.264 ;
    END
  END n_li_d[199]
  PIN n_li_d[19]
    DIRECTION INPUT ;
    USE SIGNAL ;
    PORT
      LAYER M4 ;
        RECT  112.236 9.984 112.32 10.008 ;
    END
  END n_li_d[19]
  PIN n_li_d[1]
    DIRECTION INPUT ;
    USE SIGNAL ;
    PORT
      LAYER M4 ;
        RECT  112.236 6.768 112.32 6.792 ;
    END
  END n_li_d[1]
  PIN n_li_d[200]
    DIRECTION INPUT ;
    USE SIGNAL ;
    PORT
      LAYER M4 ;
        RECT  112.236 42.432 112.32 42.456 ;
    END
  END n_li_d[200]
  PIN n_li_d[201]
    DIRECTION INPUT ;
    USE SIGNAL ;
    PORT
      LAYER M4 ;
        RECT  112.236 42.624 112.32 42.648 ;
    END
  END n_li_d[201]
  PIN n_li_d[202]
    DIRECTION INPUT ;
    USE SIGNAL ;
    PORT
      LAYER M4 ;
        RECT  112.236 42.816 112.32 42.84 ;
    END
  END n_li_d[202]
  PIN n_li_d[203]
    DIRECTION INPUT ;
    USE SIGNAL ;
    PORT
      LAYER M4 ;
        RECT  112.236 42.96 112.32 42.984 ;
    END
  END n_li_d[203]
  PIN n_li_d[204]
    DIRECTION INPUT ;
    USE SIGNAL ;
    PORT
      LAYER M4 ;
        RECT  112.236 43.152 112.32 43.176 ;
    END
  END n_li_d[204]
  PIN n_li_d[205]
    DIRECTION INPUT ;
    USE SIGNAL ;
    PORT
      LAYER M4 ;
        RECT  112.236 43.344 112.32 43.368 ;
    END
  END n_li_d[205]
  PIN n_li_d[206]
    DIRECTION INPUT ;
    USE SIGNAL ;
    PORT
      LAYER M4 ;
        RECT  112.236 43.488 112.32 43.512 ;
    END
  END n_li_d[206]
  PIN n_li_d[207]
    DIRECTION INPUT ;
    USE SIGNAL ;
    PORT
      LAYER M4 ;
        RECT  112.236 43.68 112.32 43.704 ;
    END
  END n_li_d[207]
  PIN n_li_d[208]
    DIRECTION INPUT ;
    USE SIGNAL ;
    PORT
      LAYER M4 ;
        RECT  112.236 43.872 112.32 43.896 ;
    END
  END n_li_d[208]
  PIN n_li_d[209]
    DIRECTION INPUT ;
    USE SIGNAL ;
    PORT
      LAYER M4 ;
        RECT  112.236 44.064 112.32 44.088 ;
    END
  END n_li_d[209]
  PIN n_li_d[20]
    DIRECTION INPUT ;
    USE SIGNAL ;
    PORT
      LAYER M4 ;
        RECT  112.236 10.176 112.32 10.2 ;
    END
  END n_li_d[20]
  PIN n_li_d[210]
    DIRECTION INPUT ;
    USE SIGNAL ;
    PORT
      LAYER M4 ;
        RECT  112.236 44.208 112.32 44.232 ;
    END
  END n_li_d[210]
  PIN n_li_d[211]
    DIRECTION INPUT ;
    USE SIGNAL ;
    PORT
      LAYER M4 ;
        RECT  112.236 44.4 112.32 44.424 ;
    END
  END n_li_d[211]
  PIN n_li_d[212]
    DIRECTION INPUT ;
    USE SIGNAL ;
    PORT
      LAYER M4 ;
        RECT  112.236 44.592 112.32 44.616 ;
    END
  END n_li_d[212]
  PIN n_li_d[213]
    DIRECTION INPUT ;
    USE SIGNAL ;
    PORT
      LAYER M4 ;
        RECT  112.236 44.784 112.32 44.808 ;
    END
  END n_li_d[213]
  PIN n_li_d[214]
    DIRECTION INPUT ;
    USE SIGNAL ;
    PORT
      LAYER M4 ;
        RECT  112.236 44.928 112.32 44.952 ;
    END
  END n_li_d[214]
  PIN n_li_d[215]
    DIRECTION INPUT ;
    USE SIGNAL ;
    PORT
      LAYER M4 ;
        RECT  112.236 45.12 112.32 45.144 ;
    END
  END n_li_d[215]
  PIN n_li_d[216]
    DIRECTION INPUT ;
    USE SIGNAL ;
    PORT
      LAYER M4 ;
        RECT  112.236 45.312 112.32 45.336 ;
    END
  END n_li_d[216]
  PIN n_li_d[217]
    DIRECTION INPUT ;
    USE SIGNAL ;
    PORT
      LAYER M4 ;
        RECT  112.236 45.504 112.32 45.528 ;
    END
  END n_li_d[217]
  PIN n_li_d[218]
    DIRECTION INPUT ;
    USE SIGNAL ;
    PORT
      LAYER M4 ;
        RECT  112.236 45.648 112.32 45.672 ;
    END
  END n_li_d[218]
  PIN n_li_d[219]
    DIRECTION INPUT ;
    USE SIGNAL ;
    PORT
      LAYER M4 ;
        RECT  112.236 45.84 112.32 45.864 ;
    END
  END n_li_d[219]
  PIN n_li_d[21]
    DIRECTION INPUT ;
    USE SIGNAL ;
    PORT
      LAYER M4 ;
        RECT  112.236 10.368 112.32 10.392 ;
    END
  END n_li_d[21]
  PIN n_li_d[220]
    DIRECTION INPUT ;
    USE SIGNAL ;
    PORT
      LAYER M4 ;
        RECT  112.236 46.032 112.32 46.056 ;
    END
  END n_li_d[220]
  PIN n_li_d[221]
    DIRECTION INPUT ;
    USE SIGNAL ;
    PORT
      LAYER M4 ;
        RECT  112.236 46.176 112.32 46.2 ;
    END
  END n_li_d[221]
  PIN n_li_d[222]
    DIRECTION INPUT ;
    USE SIGNAL ;
    PORT
      LAYER M4 ;
        RECT  112.236 46.368 112.32 46.392 ;
    END
  END n_li_d[222]
  PIN n_li_d[223]
    DIRECTION INPUT ;
    USE SIGNAL ;
    PORT
      LAYER M4 ;
        RECT  112.236 46.56 112.32 46.584 ;
    END
  END n_li_d[223]
  PIN n_li_d[224]
    DIRECTION INPUT ;
    USE SIGNAL ;
    PORT
      LAYER M4 ;
        RECT  112.236 46.752 112.32 46.776 ;
    END
  END n_li_d[224]
  PIN n_li_d[225]
    DIRECTION INPUT ;
    USE SIGNAL ;
    PORT
      LAYER M4 ;
        RECT  112.236 46.896 112.32 46.92 ;
    END
  END n_li_d[225]
  PIN n_li_d[226]
    DIRECTION INPUT ;
    USE SIGNAL ;
    PORT
      LAYER M4 ;
        RECT  112.236 47.088 112.32 47.112 ;
    END
  END n_li_d[226]
  PIN n_li_d[227]
    DIRECTION INPUT ;
    USE SIGNAL ;
    PORT
      LAYER M4 ;
        RECT  112.236 47.28 112.32 47.304 ;
    END
  END n_li_d[227]
  PIN n_li_d[228]
    DIRECTION INPUT ;
    USE SIGNAL ;
    PORT
      LAYER M4 ;
        RECT  112.236 47.472 112.32 47.496 ;
    END
  END n_li_d[228]
  PIN n_li_d[229]
    DIRECTION INPUT ;
    USE SIGNAL ;
    PORT
      LAYER M4 ;
        RECT  112.236 47.616 112.32 47.64 ;
    END
  END n_li_d[229]
  PIN n_li_d[22]
    DIRECTION INPUT ;
    USE SIGNAL ;
    PORT
      LAYER M4 ;
        RECT  112.236 10.512 112.32 10.536 ;
    END
  END n_li_d[22]
  PIN n_li_d[230]
    DIRECTION INPUT ;
    USE SIGNAL ;
    PORT
      LAYER M4 ;
        RECT  112.236 47.808 112.32 47.832 ;
    END
  END n_li_d[230]
  PIN n_li_d[231]
    DIRECTION INPUT ;
    USE SIGNAL ;
    PORT
      LAYER M4 ;
        RECT  112.236 48 112.32 48.024 ;
    END
  END n_li_d[231]
  PIN n_li_d[232]
    DIRECTION INPUT ;
    USE SIGNAL ;
    PORT
      LAYER M4 ;
        RECT  112.236 48.192 112.32 48.216 ;
    END
  END n_li_d[232]
  PIN n_li_d[233]
    DIRECTION INPUT ;
    USE SIGNAL ;
    PORT
      LAYER M4 ;
        RECT  112.236 48.336 112.32 48.36 ;
    END
  END n_li_d[233]
  PIN n_li_d[234]
    DIRECTION INPUT ;
    USE SIGNAL ;
    PORT
      LAYER M4 ;
        RECT  112.236 48.528 112.32 48.552 ;
    END
  END n_li_d[234]
  PIN n_li_d[235]
    DIRECTION INPUT ;
    USE SIGNAL ;
    PORT
      LAYER M4 ;
        RECT  112.236 48.72 112.32 48.744 ;
    END
  END n_li_d[235]
  PIN n_li_d[236]
    DIRECTION INPUT ;
    USE SIGNAL ;
    PORT
      LAYER M4 ;
        RECT  112.236 48.864 112.32 48.888 ;
    END
  END n_li_d[236]
  PIN n_li_d[237]
    DIRECTION INPUT ;
    USE SIGNAL ;
    PORT
      LAYER M4 ;
        RECT  112.236 49.056 112.32 49.08 ;
    END
  END n_li_d[237]
  PIN n_li_d[238]
    DIRECTION INPUT ;
    USE SIGNAL ;
    PORT
      LAYER M4 ;
        RECT  112.236 49.248 112.32 49.272 ;
    END
  END n_li_d[238]
  PIN n_li_d[239]
    DIRECTION INPUT ;
    USE SIGNAL ;
    PORT
      LAYER M4 ;
        RECT  112.236 49.44 112.32 49.464 ;
    END
  END n_li_d[239]
  PIN n_li_d[23]
    DIRECTION INPUT ;
    USE SIGNAL ;
    PORT
      LAYER M4 ;
        RECT  112.236 10.704 112.32 10.728 ;
    END
  END n_li_d[23]
  PIN n_li_d[240]
    DIRECTION INPUT ;
    USE SIGNAL ;
    PORT
      LAYER M4 ;
        RECT  112.236 49.584 112.32 49.608 ;
    END
  END n_li_d[240]
  PIN n_li_d[241]
    DIRECTION INPUT ;
    USE SIGNAL ;
    PORT
      LAYER M4 ;
        RECT  112.236 49.776 112.32 49.8 ;
    END
  END n_li_d[241]
  PIN n_li_d[242]
    DIRECTION INPUT ;
    USE SIGNAL ;
    PORT
      LAYER M4 ;
        RECT  112.236 49.968 112.32 49.992 ;
    END
  END n_li_d[242]
  PIN n_li_d[243]
    DIRECTION INPUT ;
    USE SIGNAL ;
    PORT
      LAYER M4 ;
        RECT  112.236 50.16 112.32 50.184 ;
    END
  END n_li_d[243]
  PIN n_li_d[244]
    DIRECTION INPUT ;
    USE SIGNAL ;
    PORT
      LAYER M4 ;
        RECT  112.236 50.304 112.32 50.328 ;
    END
  END n_li_d[244]
  PIN n_li_d[245]
    DIRECTION INPUT ;
    USE SIGNAL ;
    PORT
      LAYER M4 ;
        RECT  112.236 50.496 112.32 50.52 ;
    END
  END n_li_d[245]
  PIN n_li_d[246]
    DIRECTION INPUT ;
    USE SIGNAL ;
    PORT
      LAYER M4 ;
        RECT  112.236 50.688 112.32 50.712 ;
    END
  END n_li_d[246]
  PIN n_li_d[247]
    DIRECTION INPUT ;
    USE SIGNAL ;
    PORT
      LAYER M4 ;
        RECT  112.236 50.88 112.32 50.904 ;
    END
  END n_li_d[247]
  PIN n_li_d[248]
    DIRECTION INPUT ;
    USE SIGNAL ;
    PORT
      LAYER M4 ;
        RECT  112.236 51.024 112.32 51.048 ;
    END
  END n_li_d[248]
  PIN n_li_d[249]
    DIRECTION INPUT ;
    USE SIGNAL ;
    PORT
      LAYER M4 ;
        RECT  112.236 51.216 112.32 51.24 ;
    END
  END n_li_d[249]
  PIN n_li_d[24]
    DIRECTION INPUT ;
    USE SIGNAL ;
    PORT
      LAYER M4 ;
        RECT  112.236 10.896 112.32 10.92 ;
    END
  END n_li_d[24]
  PIN n_li_d[250]
    DIRECTION INPUT ;
    USE SIGNAL ;
    PORT
      LAYER M4 ;
        RECT  112.236 51.408 112.32 51.432 ;
    END
  END n_li_d[250]
  PIN n_li_d[251]
    DIRECTION INPUT ;
    USE SIGNAL ;
    PORT
      LAYER M4 ;
        RECT  112.236 51.6 112.32 51.624 ;
    END
  END n_li_d[251]
  PIN n_li_d[252]
    DIRECTION INPUT ;
    USE SIGNAL ;
    PORT
      LAYER M4 ;
        RECT  112.236 51.744 112.32 51.768 ;
    END
  END n_li_d[252]
  PIN n_li_d[253]
    DIRECTION INPUT ;
    USE SIGNAL ;
    PORT
      LAYER M4 ;
        RECT  112.236 51.936 112.32 51.96 ;
    END
  END n_li_d[253]
  PIN n_li_d[254]
    DIRECTION INPUT ;
    USE SIGNAL ;
    PORT
      LAYER M4 ;
        RECT  112.236 52.128 112.32 52.152 ;
    END
  END n_li_d[254]
  PIN n_li_d[255]
    DIRECTION INPUT ;
    USE SIGNAL ;
    PORT
      LAYER M4 ;
        RECT  112.236 52.272 112.32 52.296 ;
    END
  END n_li_d[255]
  PIN n_li_d[256]
    DIRECTION INPUT ;
    USE SIGNAL ;
    PORT
      LAYER M4 ;
        RECT  112.236 52.464 112.32 52.488 ;
    END
  END n_li_d[256]
  PIN n_li_d[257]
    DIRECTION INPUT ;
    USE SIGNAL ;
    PORT
      LAYER M4 ;
        RECT  112.236 52.656 112.32 52.68 ;
    END
  END n_li_d[257]
  PIN n_li_d[258]
    DIRECTION INPUT ;
    USE SIGNAL ;
    PORT
      LAYER M4 ;
        RECT  112.236 52.848 112.32 52.872 ;
    END
  END n_li_d[258]
  PIN n_li_d[259]
    DIRECTION INPUT ;
    USE SIGNAL ;
    PORT
      LAYER M4 ;
        RECT  112.236 52.992 112.32 53.016 ;
    END
  END n_li_d[259]
  PIN n_li_d[25]
    DIRECTION INPUT ;
    USE SIGNAL ;
    PORT
      LAYER M4 ;
        RECT  112.236 11.04 112.32 11.064 ;
    END
  END n_li_d[25]
  PIN n_li_d[260]
    DIRECTION INPUT ;
    USE SIGNAL ;
    PORT
      LAYER M4 ;
        RECT  112.236 53.184 112.32 53.208 ;
    END
  END n_li_d[260]
  PIN n_li_d[261]
    DIRECTION INPUT ;
    USE SIGNAL ;
    PORT
      LAYER M4 ;
        RECT  112.236 53.376 112.32 53.4 ;
    END
  END n_li_d[261]
  PIN n_li_d[262]
    DIRECTION INPUT ;
    USE SIGNAL ;
    PORT
      LAYER M4 ;
        RECT  112.236 53.568 112.32 53.592 ;
    END
  END n_li_d[262]
  PIN n_li_d[263]
    DIRECTION INPUT ;
    USE SIGNAL ;
    PORT
      LAYER M4 ;
        RECT  112.236 53.712 112.32 53.736 ;
    END
  END n_li_d[263]
  PIN n_li_d[264]
    DIRECTION INPUT ;
    USE SIGNAL ;
    PORT
      LAYER M4 ;
        RECT  112.236 53.904 112.32 53.928 ;
    END
  END n_li_d[264]
  PIN n_li_d[265]
    DIRECTION INPUT ;
    USE SIGNAL ;
    PORT
      LAYER M4 ;
        RECT  112.236 54.096 112.32 54.12 ;
    END
  END n_li_d[265]
  PIN n_li_d[266]
    DIRECTION INPUT ;
    USE SIGNAL ;
    PORT
      LAYER M4 ;
        RECT  112.236 54.288 112.32 54.312 ;
    END
  END n_li_d[266]
  PIN n_li_d[267]
    DIRECTION INPUT ;
    USE SIGNAL ;
    PORT
      LAYER M4 ;
        RECT  112.236 54.432 112.32 54.456 ;
    END
  END n_li_d[267]
  PIN n_li_d[268]
    DIRECTION INPUT ;
    USE SIGNAL ;
    PORT
      LAYER M4 ;
        RECT  112.236 54.624 112.32 54.648 ;
    END
  END n_li_d[268]
  PIN n_li_d[269]
    DIRECTION INPUT ;
    USE SIGNAL ;
    PORT
      LAYER M4 ;
        RECT  112.236 54.816 112.32 54.84 ;
    END
  END n_li_d[269]
  PIN n_li_d[26]
    DIRECTION INPUT ;
    USE SIGNAL ;
    PORT
      LAYER M4 ;
        RECT  112.236 11.232 112.32 11.256 ;
    END
  END n_li_d[26]
  PIN n_li_d[270]
    DIRECTION INPUT ;
    USE SIGNAL ;
    PORT
      LAYER M4 ;
        RECT  112.236 54.96 112.32 54.984 ;
    END
  END n_li_d[270]
  PIN n_li_d[271]
    DIRECTION INPUT ;
    USE SIGNAL ;
    PORT
      LAYER M4 ;
        RECT  112.236 55.152 112.32 55.176 ;
    END
  END n_li_d[271]
  PIN n_li_d[272]
    DIRECTION INPUT ;
    USE SIGNAL ;
    PORT
      LAYER M4 ;
        RECT  112.236 55.344 112.32 55.368 ;
    END
  END n_li_d[272]
  PIN n_li_d[273]
    DIRECTION INPUT ;
    USE SIGNAL ;
    PORT
      LAYER M4 ;
        RECT  112.236 55.536 112.32 55.56 ;
    END
  END n_li_d[273]
  PIN n_li_d[274]
    DIRECTION INPUT ;
    USE SIGNAL ;
    PORT
      LAYER M4 ;
        RECT  112.236 55.68 112.32 55.704 ;
    END
  END n_li_d[274]
  PIN n_li_d[275]
    DIRECTION INPUT ;
    USE SIGNAL ;
    PORT
      LAYER M4 ;
        RECT  112.236 55.872 112.32 55.896 ;
    END
  END n_li_d[275]
  PIN n_li_d[276]
    DIRECTION INPUT ;
    USE SIGNAL ;
    PORT
      LAYER M4 ;
        RECT  112.236 56.064 112.32 56.088 ;
    END
  END n_li_d[276]
  PIN n_li_d[277]
    DIRECTION INPUT ;
    USE SIGNAL ;
    PORT
      LAYER M4 ;
        RECT  112.236 56.256 112.32 56.28 ;
    END
  END n_li_d[277]
  PIN n_li_d[278]
    DIRECTION INPUT ;
    USE SIGNAL ;
    PORT
      LAYER M4 ;
        RECT  112.236 56.4 112.32 56.424 ;
    END
  END n_li_d[278]
  PIN n_li_d[279]
    DIRECTION INPUT ;
    USE SIGNAL ;
    PORT
      LAYER M4 ;
        RECT  112.236 56.592 112.32 56.616 ;
    END
  END n_li_d[279]
  PIN n_li_d[27]
    DIRECTION INPUT ;
    USE SIGNAL ;
    PORT
      LAYER M4 ;
        RECT  112.236 11.424 112.32 11.448 ;
    END
  END n_li_d[27]
  PIN n_li_d[280]
    DIRECTION INPUT ;
    USE SIGNAL ;
    PORT
      LAYER M4 ;
        RECT  112.236 56.784 112.32 56.808 ;
    END
  END n_li_d[280]
  PIN n_li_d[281]
    DIRECTION INPUT ;
    USE SIGNAL ;
    PORT
      LAYER M4 ;
        RECT  112.236 56.976 112.32 57 ;
    END
  END n_li_d[281]
  PIN n_li_d[282]
    DIRECTION INPUT ;
    USE SIGNAL ;
    PORT
      LAYER M4 ;
        RECT  112.236 57.12 112.32 57.144 ;
    END
  END n_li_d[282]
  PIN n_li_d[283]
    DIRECTION INPUT ;
    USE SIGNAL ;
    PORT
      LAYER M4 ;
        RECT  112.236 57.312 112.32 57.336 ;
    END
  END n_li_d[283]
  PIN n_li_d[284]
    DIRECTION INPUT ;
    USE SIGNAL ;
    PORT
      LAYER M4 ;
        RECT  112.236 57.504 112.32 57.528 ;
    END
  END n_li_d[284]
  PIN n_li_d[285]
    DIRECTION INPUT ;
    USE SIGNAL ;
    PORT
      LAYER M4 ;
        RECT  112.236 57.648 112.32 57.672 ;
    END
  END n_li_d[285]
  PIN n_li_d[286]
    DIRECTION INPUT ;
    USE SIGNAL ;
    PORT
      LAYER M4 ;
        RECT  112.236 57.84 112.32 57.864 ;
    END
  END n_li_d[286]
  PIN n_li_d[287]
    DIRECTION INPUT ;
    USE SIGNAL ;
    PORT
      LAYER M4 ;
        RECT  112.236 58.032 112.32 58.056 ;
    END
  END n_li_d[287]
  PIN n_li_d[288]
    DIRECTION INPUT ;
    USE SIGNAL ;
    PORT
      LAYER M4 ;
        RECT  112.236 58.224 112.32 58.248 ;
    END
  END n_li_d[288]
  PIN n_li_d[289]
    DIRECTION INPUT ;
    USE SIGNAL ;
    PORT
      LAYER M4 ;
        RECT  112.236 58.368 112.32 58.392 ;
    END
  END n_li_d[289]
  PIN n_li_d[28]
    DIRECTION INPUT ;
    USE SIGNAL ;
    PORT
      LAYER M4 ;
        RECT  112.236 11.616 112.32 11.64 ;
    END
  END n_li_d[28]
  PIN n_li_d[290]
    DIRECTION INPUT ;
    USE SIGNAL ;
    PORT
      LAYER M4 ;
        RECT  112.236 58.56 112.32 58.584 ;
    END
  END n_li_d[290]
  PIN n_li_d[291]
    DIRECTION INPUT ;
    USE SIGNAL ;
    PORT
      LAYER M4 ;
        RECT  112.236 58.752 112.32 58.776 ;
    END
  END n_li_d[291]
  PIN n_li_d[292]
    DIRECTION INPUT ;
    USE SIGNAL ;
    PORT
      LAYER M4 ;
        RECT  112.236 58.944 112.32 58.968 ;
    END
  END n_li_d[292]
  PIN n_li_d[293]
    DIRECTION INPUT ;
    USE SIGNAL ;
    PORT
      LAYER M4 ;
        RECT  112.236 59.088 112.32 59.112 ;
    END
  END n_li_d[293]
  PIN n_li_d[294]
    DIRECTION INPUT ;
    USE SIGNAL ;
    PORT
      LAYER M4 ;
        RECT  112.236 59.28 112.32 59.304 ;
    END
  END n_li_d[294]
  PIN n_li_d[295]
    DIRECTION INPUT ;
    USE SIGNAL ;
    PORT
      LAYER M4 ;
        RECT  112.236 59.472 112.32 59.496 ;
    END
  END n_li_d[295]
  PIN n_li_d[296]
    DIRECTION INPUT ;
    USE SIGNAL ;
    PORT
      LAYER M4 ;
        RECT  112.236 59.664 112.32 59.688 ;
    END
  END n_li_d[296]
  PIN n_li_d[297]
    DIRECTION INPUT ;
    USE SIGNAL ;
    PORT
      LAYER M4 ;
        RECT  112.236 59.808 112.32 59.832 ;
    END
  END n_li_d[297]
  PIN n_li_d[298]
    DIRECTION INPUT ;
    USE SIGNAL ;
    PORT
      LAYER M4 ;
        RECT  112.236 60 112.32 60.024 ;
    END
  END n_li_d[298]
  PIN n_li_d[299]
    DIRECTION INPUT ;
    USE SIGNAL ;
    PORT
      LAYER M4 ;
        RECT  112.236 60.192 112.32 60.216 ;
    END
  END n_li_d[299]
  PIN n_li_d[29]
    DIRECTION INPUT ;
    USE SIGNAL ;
    PORT
      LAYER M4 ;
        RECT  112.236 11.76 112.32 11.784 ;
    END
  END n_li_d[29]
  PIN n_li_d[2]
    DIRECTION INPUT ;
    USE SIGNAL ;
    PORT
      LAYER M4 ;
        RECT  112.236 6.96 112.32 6.984 ;
    END
  END n_li_d[2]
  PIN n_li_d[300]
    DIRECTION INPUT ;
    USE SIGNAL ;
    PORT
      LAYER M4 ;
        RECT  112.236 60.384 112.32 60.408 ;
    END
  END n_li_d[300]
  PIN n_li_d[301]
    DIRECTION INPUT ;
    USE SIGNAL ;
    PORT
      LAYER M4 ;
        RECT  112.236 60.528 112.32 60.552 ;
    END
  END n_li_d[301]
  PIN n_li_d[302]
    DIRECTION INPUT ;
    USE SIGNAL ;
    PORT
      LAYER M4 ;
        RECT  112.236 60.72 112.32 60.744 ;
    END
  END n_li_d[302]
  PIN n_li_d[303]
    DIRECTION INPUT ;
    USE SIGNAL ;
    PORT
      LAYER M4 ;
        RECT  112.236 60.912 112.32 60.936 ;
    END
  END n_li_d[303]
  PIN n_li_d[304]
    DIRECTION INPUT ;
    USE SIGNAL ;
    PORT
      LAYER M4 ;
        RECT  112.236 61.056 112.32 61.08 ;
    END
  END n_li_d[304]
  PIN n_li_d[305]
    DIRECTION INPUT ;
    USE SIGNAL ;
    PORT
      LAYER M4 ;
        RECT  112.236 61.248 112.32 61.272 ;
    END
  END n_li_d[305]
  PIN n_li_d[306]
    DIRECTION INPUT ;
    USE SIGNAL ;
    PORT
      LAYER M4 ;
        RECT  112.236 61.44 112.32 61.464 ;
    END
  END n_li_d[306]
  PIN n_li_d[307]
    DIRECTION INPUT ;
    USE SIGNAL ;
    PORT
      LAYER M4 ;
        RECT  112.236 61.632 112.32 61.656 ;
    END
  END n_li_d[307]
  PIN n_li_d[308]
    DIRECTION INPUT ;
    USE SIGNAL ;
    PORT
      LAYER M4 ;
        RECT  112.236 61.776 112.32 61.8 ;
    END
  END n_li_d[308]
  PIN n_li_d[309]
    DIRECTION INPUT ;
    USE SIGNAL ;
    PORT
      LAYER M4 ;
        RECT  112.236 61.968 112.32 61.992 ;
    END
  END n_li_d[309]
  PIN n_li_d[30]
    DIRECTION INPUT ;
    USE SIGNAL ;
    PORT
      LAYER M4 ;
        RECT  112.236 11.952 112.32 11.976 ;
    END
  END n_li_d[30]
  PIN n_li_d[310]
    DIRECTION INPUT ;
    USE SIGNAL ;
    PORT
      LAYER M4 ;
        RECT  112.236 62.16 112.32 62.184 ;
    END
  END n_li_d[310]
  PIN n_li_d[311]
    DIRECTION INPUT ;
    USE SIGNAL ;
    PORT
      LAYER M4 ;
        RECT  112.236 62.352 112.32 62.376 ;
    END
  END n_li_d[311]
  PIN n_li_d[312]
    DIRECTION INPUT ;
    USE SIGNAL ;
    PORT
      LAYER M4 ;
        RECT  112.236 62.496 112.32 62.52 ;
    END
  END n_li_d[312]
  PIN n_li_d[313]
    DIRECTION INPUT ;
    USE SIGNAL ;
    PORT
      LAYER M4 ;
        RECT  112.236 62.688 112.32 62.712 ;
    END
  END n_li_d[313]
  PIN n_li_d[314]
    DIRECTION INPUT ;
    USE SIGNAL ;
    PORT
      LAYER M4 ;
        RECT  112.236 62.88 112.32 62.904 ;
    END
  END n_li_d[314]
  PIN n_li_d[315]
    DIRECTION INPUT ;
    USE SIGNAL ;
    PORT
      LAYER M4 ;
        RECT  112.236 63.072 112.32 63.096 ;
    END
  END n_li_d[315]
  PIN n_li_d[316]
    DIRECTION INPUT ;
    USE SIGNAL ;
    PORT
      LAYER M4 ;
        RECT  112.236 63.216 112.32 63.24 ;
    END
  END n_li_d[316]
  PIN n_li_d[317]
    DIRECTION INPUT ;
    USE SIGNAL ;
    PORT
      LAYER M4 ;
        RECT  112.236 63.408 112.32 63.432 ;
    END
  END n_li_d[317]
  PIN n_li_d[318]
    DIRECTION INPUT ;
    USE SIGNAL ;
    PORT
      LAYER M4 ;
        RECT  112.236 63.6 112.32 63.624 ;
    END
  END n_li_d[318]
  PIN n_li_d[319]
    DIRECTION INPUT ;
    USE SIGNAL ;
    PORT
      LAYER M4 ;
        RECT  112.236 63.744 112.32 63.768 ;
    END
  END n_li_d[319]
  PIN n_li_d[31]
    DIRECTION INPUT ;
    USE SIGNAL ;
    PORT
      LAYER M4 ;
        RECT  112.236 12.144 112.32 12.168 ;
    END
  END n_li_d[31]
  PIN n_li_d[320]
    DIRECTION INPUT ;
    USE SIGNAL ;
    PORT
      LAYER M4 ;
        RECT  112.236 63.936 112.32 63.96 ;
    END
  END n_li_d[320]
  PIN n_li_d[321]
    DIRECTION INPUT ;
    USE SIGNAL ;
    PORT
      LAYER M4 ;
        RECT  112.236 64.128 112.32 64.152 ;
    END
  END n_li_d[321]
  PIN n_li_d[322]
    DIRECTION INPUT ;
    USE SIGNAL ;
    PORT
      LAYER M4 ;
        RECT  112.236 64.32 112.32 64.344 ;
    END
  END n_li_d[322]
  PIN n_li_d[323]
    DIRECTION INPUT ;
    USE SIGNAL ;
    PORT
      LAYER M4 ;
        RECT  112.236 64.464 112.32 64.488 ;
    END
  END n_li_d[323]
  PIN n_li_d[324]
    DIRECTION INPUT ;
    USE SIGNAL ;
    PORT
      LAYER M4 ;
        RECT  112.236 64.656 112.32 64.68 ;
    END
  END n_li_d[324]
  PIN n_li_d[325]
    DIRECTION INPUT ;
    USE SIGNAL ;
    PORT
      LAYER M4 ;
        RECT  112.236 64.848 112.32 64.872 ;
    END
  END n_li_d[325]
  PIN n_li_d[326]
    DIRECTION INPUT ;
    USE SIGNAL ;
    PORT
      LAYER M4 ;
        RECT  112.236 65.04 112.32 65.064 ;
    END
  END n_li_d[326]
  PIN n_li_d[327]
    DIRECTION INPUT ;
    USE SIGNAL ;
    PORT
      LAYER M4 ;
        RECT  112.236 65.184 112.32 65.208 ;
    END
  END n_li_d[327]
  PIN n_li_d[328]
    DIRECTION INPUT ;
    USE SIGNAL ;
    PORT
      LAYER M4 ;
        RECT  112.236 65.376 112.32 65.4 ;
    END
  END n_li_d[328]
  PIN n_li_d[329]
    DIRECTION INPUT ;
    USE SIGNAL ;
    PORT
      LAYER M4 ;
        RECT  112.236 65.568 112.32 65.592 ;
    END
  END n_li_d[329]
  PIN n_li_d[32]
    DIRECTION INPUT ;
    USE SIGNAL ;
    PORT
      LAYER M4 ;
        RECT  112.236 12.336 112.32 12.36 ;
    END
  END n_li_d[32]
  PIN n_li_d[330]
    DIRECTION INPUT ;
    USE SIGNAL ;
    PORT
      LAYER M4 ;
        RECT  112.236 65.76 112.32 65.784 ;
    END
  END n_li_d[330]
  PIN n_li_d[331]
    DIRECTION INPUT ;
    USE SIGNAL ;
    PORT
      LAYER M4 ;
        RECT  112.236 65.904 112.32 65.928 ;
    END
  END n_li_d[331]
  PIN n_li_d[332]
    DIRECTION INPUT ;
    USE SIGNAL ;
    PORT
      LAYER M4 ;
        RECT  112.236 66.096 112.32 66.12 ;
    END
  END n_li_d[332]
  PIN n_li_d[333]
    DIRECTION INPUT ;
    USE SIGNAL ;
    PORT
      LAYER M4 ;
        RECT  112.236 66.288 112.32 66.312 ;
    END
  END n_li_d[333]
  PIN n_li_d[334]
    DIRECTION INPUT ;
    USE SIGNAL ;
    PORT
      LAYER M4 ;
        RECT  112.236 66.432 112.32 66.456 ;
    END
  END n_li_d[334]
  PIN n_li_d[335]
    DIRECTION INPUT ;
    USE SIGNAL ;
    PORT
      LAYER M4 ;
        RECT  112.236 66.624 112.32 66.648 ;
    END
  END n_li_d[335]
  PIN n_li_d[336]
    DIRECTION INPUT ;
    USE SIGNAL ;
    PORT
      LAYER M4 ;
        RECT  112.236 66.816 112.32 66.84 ;
    END
  END n_li_d[336]
  PIN n_li_d[337]
    DIRECTION INPUT ;
    USE SIGNAL ;
    PORT
      LAYER M4 ;
        RECT  112.236 67.008 112.32 67.032 ;
    END
  END n_li_d[337]
  PIN n_li_d[338]
    DIRECTION INPUT ;
    USE SIGNAL ;
    PORT
      LAYER M4 ;
        RECT  112.236 67.152 112.32 67.176 ;
    END
  END n_li_d[338]
  PIN n_li_d[339]
    DIRECTION INPUT ;
    USE SIGNAL ;
    PORT
      LAYER M4 ;
        RECT  112.236 67.344 112.32 67.368 ;
    END
  END n_li_d[339]
  PIN n_li_d[33]
    DIRECTION INPUT ;
    USE SIGNAL ;
    PORT
      LAYER M4 ;
        RECT  112.236 12.48 112.32 12.504 ;
    END
  END n_li_d[33]
  PIN n_li_d[340]
    DIRECTION INPUT ;
    USE SIGNAL ;
    PORT
      LAYER M4 ;
        RECT  112.236 67.536 112.32 67.56 ;
    END
  END n_li_d[340]
  PIN n_li_d[341]
    DIRECTION INPUT ;
    USE SIGNAL ;
    PORT
      LAYER M4 ;
        RECT  112.236 67.728 112.32 67.752 ;
    END
  END n_li_d[341]
  PIN n_li_d[342]
    DIRECTION INPUT ;
    USE SIGNAL ;
    PORT
      LAYER M4 ;
        RECT  112.236 67.872 112.32 67.896 ;
    END
  END n_li_d[342]
  PIN n_li_d[343]
    DIRECTION INPUT ;
    USE SIGNAL ;
    PORT
      LAYER M4 ;
        RECT  112.236 68.064 112.32 68.088 ;
    END
  END n_li_d[343]
  PIN n_li_d[344]
    DIRECTION INPUT ;
    USE SIGNAL ;
    PORT
      LAYER M4 ;
        RECT  112.236 68.256 112.32 68.28 ;
    END
  END n_li_d[344]
  PIN n_li_d[345]
    DIRECTION INPUT ;
    USE SIGNAL ;
    PORT
      LAYER M4 ;
        RECT  112.236 68.448 112.32 68.472 ;
    END
  END n_li_d[345]
  PIN n_li_d[346]
    DIRECTION INPUT ;
    USE SIGNAL ;
    PORT
      LAYER M4 ;
        RECT  112.236 68.592 112.32 68.616 ;
    END
  END n_li_d[346]
  PIN n_li_d[347]
    DIRECTION INPUT ;
    USE SIGNAL ;
    PORT
      LAYER M4 ;
        RECT  112.236 68.784 112.32 68.808 ;
    END
  END n_li_d[347]
  PIN n_li_d[348]
    DIRECTION INPUT ;
    USE SIGNAL ;
    PORT
      LAYER M4 ;
        RECT  112.236 68.976 112.32 69 ;
    END
  END n_li_d[348]
  PIN n_li_d[349]
    DIRECTION INPUT ;
    USE SIGNAL ;
    PORT
      LAYER M4 ;
        RECT  112.236 69.168 112.32 69.192 ;
    END
  END n_li_d[349]
  PIN n_li_d[34]
    DIRECTION INPUT ;
    USE SIGNAL ;
    PORT
      LAYER M4 ;
        RECT  112.236 12.672 112.32 12.696 ;
    END
  END n_li_d[34]
  PIN n_li_d[350]
    DIRECTION INPUT ;
    USE SIGNAL ;
    PORT
      LAYER M4 ;
        RECT  112.236 69.312 112.32 69.336 ;
    END
  END n_li_d[350]
  PIN n_li_d[351]
    DIRECTION INPUT ;
    USE SIGNAL ;
    PORT
      LAYER M4 ;
        RECT  112.236 69.504 112.32 69.528 ;
    END
  END n_li_d[351]
  PIN n_li_d[352]
    DIRECTION INPUT ;
    USE SIGNAL ;
    PORT
      LAYER M4 ;
        RECT  112.236 69.696 112.32 69.72 ;
    END
  END n_li_d[352]
  PIN n_li_d[353]
    DIRECTION INPUT ;
    USE SIGNAL ;
    PORT
      LAYER M4 ;
        RECT  112.236 69.84 112.32 69.864 ;
    END
  END n_li_d[353]
  PIN n_li_d[354]
    DIRECTION INPUT ;
    USE SIGNAL ;
    PORT
      LAYER M4 ;
        RECT  112.236 70.032 112.32 70.056 ;
    END
  END n_li_d[354]
  PIN n_li_d[355]
    DIRECTION INPUT ;
    USE SIGNAL ;
    PORT
      LAYER M4 ;
        RECT  112.236 70.224 112.32 70.248 ;
    END
  END n_li_d[355]
  PIN n_li_d[356]
    DIRECTION INPUT ;
    USE SIGNAL ;
    PORT
      LAYER M4 ;
        RECT  112.236 70.416 112.32 70.44 ;
    END
  END n_li_d[356]
  PIN n_li_d[357]
    DIRECTION INPUT ;
    USE SIGNAL ;
    PORT
      LAYER M4 ;
        RECT  112.236 70.56 112.32 70.584 ;
    END
  END n_li_d[357]
  PIN n_li_d[358]
    DIRECTION INPUT ;
    USE SIGNAL ;
    PORT
      LAYER M4 ;
        RECT  112.236 70.752 112.32 70.776 ;
    END
  END n_li_d[358]
  PIN n_li_d[359]
    DIRECTION INPUT ;
    USE SIGNAL ;
    PORT
      LAYER M4 ;
        RECT  112.236 70.944 112.32 70.968 ;
    END
  END n_li_d[359]
  PIN n_li_d[35]
    DIRECTION INPUT ;
    USE SIGNAL ;
    PORT
      LAYER M4 ;
        RECT  112.236 12.864 112.32 12.888 ;
    END
  END n_li_d[35]
  PIN n_li_d[360]
    DIRECTION INPUT ;
    USE SIGNAL ;
    PORT
      LAYER M4 ;
        RECT  112.236 71.136 112.32 71.16 ;
    END
  END n_li_d[360]
  PIN n_li_d[361]
    DIRECTION INPUT ;
    USE SIGNAL ;
    PORT
      LAYER M4 ;
        RECT  112.236 71.28 112.32 71.304 ;
    END
  END n_li_d[361]
  PIN n_li_d[362]
    DIRECTION INPUT ;
    USE SIGNAL ;
    PORT
      LAYER M4 ;
        RECT  112.236 71.472 112.32 71.496 ;
    END
  END n_li_d[362]
  PIN n_li_d[363]
    DIRECTION INPUT ;
    USE SIGNAL ;
    PORT
      LAYER M4 ;
        RECT  112.236 71.664 112.32 71.688 ;
    END
  END n_li_d[363]
  PIN n_li_d[364]
    DIRECTION INPUT ;
    USE SIGNAL ;
    PORT
      LAYER M4 ;
        RECT  112.236 71.856 112.32 71.88 ;
    END
  END n_li_d[364]
  PIN n_li_d[365]
    DIRECTION INPUT ;
    USE SIGNAL ;
    PORT
      LAYER M4 ;
        RECT  112.236 72 112.32 72.024 ;
    END
  END n_li_d[365]
  PIN n_li_d[366]
    DIRECTION INPUT ;
    USE SIGNAL ;
    PORT
      LAYER M4 ;
        RECT  112.236 72.192 112.32 72.216 ;
    END
  END n_li_d[366]
  PIN n_li_d[367]
    DIRECTION INPUT ;
    USE SIGNAL ;
    PORT
      LAYER M4 ;
        RECT  112.236 72.384 112.32 72.408 ;
    END
  END n_li_d[367]
  PIN n_li_d[368]
    DIRECTION INPUT ;
    USE SIGNAL ;
    PORT
      LAYER M4 ;
        RECT  112.236 72.528 112.32 72.552 ;
    END
  END n_li_d[368]
  PIN n_li_d[369]
    DIRECTION INPUT ;
    USE SIGNAL ;
    PORT
      LAYER M4 ;
        RECT  112.236 72.72 112.32 72.744 ;
    END
  END n_li_d[369]
  PIN n_li_d[36]
    DIRECTION INPUT ;
    USE SIGNAL ;
    PORT
      LAYER M4 ;
        RECT  112.236 13.056 112.32 13.08 ;
    END
  END n_li_d[36]
  PIN n_li_d[370]
    DIRECTION INPUT ;
    USE SIGNAL ;
    PORT
      LAYER M4 ;
        RECT  112.236 72.912 112.32 72.936 ;
    END
  END n_li_d[370]
  PIN n_li_d[371]
    DIRECTION INPUT ;
    USE SIGNAL ;
    PORT
      LAYER M4 ;
        RECT  112.236 73.104 112.32 73.128 ;
    END
  END n_li_d[371]
  PIN n_li_d[372]
    DIRECTION INPUT ;
    USE SIGNAL ;
    PORT
      LAYER M4 ;
        RECT  112.236 73.248 112.32 73.272 ;
    END
  END n_li_d[372]
  PIN n_li_d[373]
    DIRECTION INPUT ;
    USE SIGNAL ;
    PORT
      LAYER M4 ;
        RECT  112.236 73.44 112.32 73.464 ;
    END
  END n_li_d[373]
  PIN n_li_d[374]
    DIRECTION INPUT ;
    USE SIGNAL ;
    PORT
      LAYER M4 ;
        RECT  112.236 73.632 112.32 73.656 ;
    END
  END n_li_d[374]
  PIN n_li_d[375]
    DIRECTION INPUT ;
    USE SIGNAL ;
    PORT
      LAYER M4 ;
        RECT  112.236 73.824 112.32 73.848 ;
    END
  END n_li_d[375]
  PIN n_li_d[376]
    DIRECTION INPUT ;
    USE SIGNAL ;
    PORT
      LAYER M4 ;
        RECT  112.236 73.968 112.32 73.992 ;
    END
  END n_li_d[376]
  PIN n_li_d[377]
    DIRECTION INPUT ;
    USE SIGNAL ;
    PORT
      LAYER M4 ;
        RECT  112.236 74.16 112.32 74.184 ;
    END
  END n_li_d[377]
  PIN n_li_d[378]
    DIRECTION INPUT ;
    USE SIGNAL ;
    PORT
      LAYER M4 ;
        RECT  112.236 74.352 112.32 74.376 ;
    END
  END n_li_d[378]
  PIN n_li_d[379]
    DIRECTION INPUT ;
    USE SIGNAL ;
    PORT
      LAYER M4 ;
        RECT  112.236 74.544 112.32 74.568 ;
    END
  END n_li_d[379]
  PIN n_li_d[37]
    DIRECTION INPUT ;
    USE SIGNAL ;
    PORT
      LAYER M4 ;
        RECT  112.236 13.2 112.32 13.224 ;
    END
  END n_li_d[37]
  PIN n_li_d[380]
    DIRECTION INPUT ;
    USE SIGNAL ;
    PORT
      LAYER M4 ;
        RECT  112.236 74.688 112.32 74.712 ;
    END
  END n_li_d[380]
  PIN n_li_d[381]
    DIRECTION INPUT ;
    USE SIGNAL ;
    PORT
      LAYER M4 ;
        RECT  112.236 74.88 112.32 74.904 ;
    END
  END n_li_d[381]
  PIN n_li_d[382]
    DIRECTION INPUT ;
    USE SIGNAL ;
    PORT
      LAYER M4 ;
        RECT  112.236 75.072 112.32 75.096 ;
    END
  END n_li_d[382]
  PIN n_li_d[383]
    DIRECTION INPUT ;
    USE SIGNAL ;
    PORT
      LAYER M4 ;
        RECT  112.236 75.264 112.32 75.288 ;
    END
  END n_li_d[383]
  PIN n_li_d[384]
    DIRECTION INPUT ;
    USE SIGNAL ;
    PORT
      LAYER M4 ;
        RECT  112.236 75.408 112.32 75.432 ;
    END
  END n_li_d[384]
  PIN n_li_d[385]
    DIRECTION INPUT ;
    USE SIGNAL ;
    PORT
      LAYER M4 ;
        RECT  112.236 75.6 112.32 75.624 ;
    END
  END n_li_d[385]
  PIN n_li_d[386]
    DIRECTION INPUT ;
    USE SIGNAL ;
    PORT
      LAYER M4 ;
        RECT  112.236 75.792 112.32 75.816 ;
    END
  END n_li_d[386]
  PIN n_li_d[387]
    DIRECTION INPUT ;
    USE SIGNAL ;
    PORT
      LAYER M4 ;
        RECT  112.236 75.936 112.32 75.96 ;
    END
  END n_li_d[387]
  PIN n_li_d[388]
    DIRECTION INPUT ;
    USE SIGNAL ;
    PORT
      LAYER M4 ;
        RECT  112.236 76.128 112.32 76.152 ;
    END
  END n_li_d[388]
  PIN n_li_d[389]
    DIRECTION INPUT ;
    USE SIGNAL ;
    PORT
      LAYER M4 ;
        RECT  112.236 76.32 112.32 76.344 ;
    END
  END n_li_d[389]
  PIN n_li_d[38]
    DIRECTION INPUT ;
    USE SIGNAL ;
    PORT
      LAYER M4 ;
        RECT  112.236 13.392 112.32 13.416 ;
    END
  END n_li_d[38]
  PIN n_li_d[390]
    DIRECTION INPUT ;
    USE SIGNAL ;
    PORT
      LAYER M4 ;
        RECT  112.236 76.512 112.32 76.536 ;
    END
  END n_li_d[390]
  PIN n_li_d[391]
    DIRECTION INPUT ;
    USE SIGNAL ;
    PORT
      LAYER M4 ;
        RECT  112.236 76.656 112.32 76.68 ;
    END
  END n_li_d[391]
  PIN n_li_d[392]
    DIRECTION INPUT ;
    USE SIGNAL ;
    PORT
      LAYER M4 ;
        RECT  112.236 76.848 112.32 76.872 ;
    END
  END n_li_d[392]
  PIN n_li_d[393]
    DIRECTION INPUT ;
    USE SIGNAL ;
    PORT
      LAYER M4 ;
        RECT  112.236 77.04 112.32 77.064 ;
    END
  END n_li_d[393]
  PIN n_li_d[394]
    DIRECTION INPUT ;
    USE SIGNAL ;
    PORT
      LAYER M4 ;
        RECT  112.236 77.232 112.32 77.256 ;
    END
  END n_li_d[394]
  PIN n_li_d[395]
    DIRECTION INPUT ;
    USE SIGNAL ;
    PORT
      LAYER M4 ;
        RECT  112.236 77.376 112.32 77.4 ;
    END
  END n_li_d[395]
  PIN n_li_d[396]
    DIRECTION INPUT ;
    USE SIGNAL ;
    PORT
      LAYER M4 ;
        RECT  112.236 77.568 112.32 77.592 ;
    END
  END n_li_d[396]
  PIN n_li_d[397]
    DIRECTION INPUT ;
    USE SIGNAL ;
    PORT
      LAYER M4 ;
        RECT  112.236 77.76 112.32 77.784 ;
    END
  END n_li_d[397]
  PIN n_li_d[398]
    DIRECTION INPUT ;
    USE SIGNAL ;
    PORT
      LAYER M4 ;
        RECT  112.236 77.952 112.32 77.976 ;
    END
  END n_li_d[398]
  PIN n_li_d[399]
    DIRECTION INPUT ;
    USE SIGNAL ;
    PORT
      LAYER M4 ;
        RECT  112.236 78.096 112.32 78.12 ;
    END
  END n_li_d[399]
  PIN n_li_d[39]
    DIRECTION INPUT ;
    USE SIGNAL ;
    PORT
      LAYER M4 ;
        RECT  112.236 13.584 112.32 13.608 ;
    END
  END n_li_d[39]
  PIN n_li_d[3]
    DIRECTION INPUT ;
    USE SIGNAL ;
    PORT
      LAYER M4 ;
        RECT  112.236 7.104 112.32 7.128 ;
    END
  END n_li_d[3]
  PIN n_li_d[400]
    DIRECTION INPUT ;
    USE SIGNAL ;
    PORT
      LAYER M4 ;
        RECT  112.236 78.288 112.32 78.312 ;
    END
  END n_li_d[400]
  PIN n_li_d[401]
    DIRECTION INPUT ;
    USE SIGNAL ;
    PORT
      LAYER M4 ;
        RECT  112.236 78.48 112.32 78.504 ;
    END
  END n_li_d[401]
  PIN n_li_d[402]
    DIRECTION INPUT ;
    USE SIGNAL ;
    PORT
      LAYER M4 ;
        RECT  112.236 78.624 112.32 78.648 ;
    END
  END n_li_d[402]
  PIN n_li_d[403]
    DIRECTION INPUT ;
    USE SIGNAL ;
    PORT
      LAYER M4 ;
        RECT  112.236 78.816 112.32 78.84 ;
    END
  END n_li_d[403]
  PIN n_li_d[404]
    DIRECTION INPUT ;
    USE SIGNAL ;
    PORT
      LAYER M4 ;
        RECT  112.236 79.008 112.32 79.032 ;
    END
  END n_li_d[404]
  PIN n_li_d[405]
    DIRECTION INPUT ;
    USE SIGNAL ;
    PORT
      LAYER M4 ;
        RECT  112.236 79.2 112.32 79.224 ;
    END
  END n_li_d[405]
  PIN n_li_d[406]
    DIRECTION INPUT ;
    USE SIGNAL ;
    PORT
      LAYER M4 ;
        RECT  112.236 79.344 112.32 79.368 ;
    END
  END n_li_d[406]
  PIN n_li_d[407]
    DIRECTION INPUT ;
    USE SIGNAL ;
    PORT
      LAYER M4 ;
        RECT  112.236 79.536 112.32 79.56 ;
    END
  END n_li_d[407]
  PIN n_li_d[408]
    DIRECTION INPUT ;
    USE SIGNAL ;
    PORT
      LAYER M4 ;
        RECT  112.236 79.728 112.32 79.752 ;
    END
  END n_li_d[408]
  PIN n_li_d[409]
    DIRECTION INPUT ;
    USE SIGNAL ;
    PORT
      LAYER M4 ;
        RECT  112.236 79.92 112.32 79.944 ;
    END
  END n_li_d[409]
  PIN n_li_d[40]
    DIRECTION INPUT ;
    USE SIGNAL ;
    PORT
      LAYER M4 ;
        RECT  112.236 13.728 112.32 13.752 ;
    END
  END n_li_d[40]
  PIN n_li_d[410]
    DIRECTION INPUT ;
    USE SIGNAL ;
    PORT
      LAYER M4 ;
        RECT  112.236 80.064 112.32 80.088 ;
    END
  END n_li_d[410]
  PIN n_li_d[411]
    DIRECTION INPUT ;
    USE SIGNAL ;
    PORT
      LAYER M4 ;
        RECT  112.236 80.256 112.32 80.28 ;
    END
  END n_li_d[411]
  PIN n_li_d[412]
    DIRECTION INPUT ;
    USE SIGNAL ;
    PORT
      LAYER M4 ;
        RECT  112.236 80.448 112.32 80.472 ;
    END
  END n_li_d[412]
  PIN n_li_d[413]
    DIRECTION INPUT ;
    USE SIGNAL ;
    PORT
      LAYER M4 ;
        RECT  112.236 80.64 112.32 80.664 ;
    END
  END n_li_d[413]
  PIN n_li_d[414]
    DIRECTION INPUT ;
    USE SIGNAL ;
    PORT
      LAYER M4 ;
        RECT  112.236 80.784 112.32 80.808 ;
    END
  END n_li_d[414]
  PIN n_li_d[415]
    DIRECTION INPUT ;
    USE SIGNAL ;
    PORT
      LAYER M4 ;
        RECT  112.236 80.976 112.32 81 ;
    END
  END n_li_d[415]
  PIN n_li_d[416]
    DIRECTION INPUT ;
    USE SIGNAL ;
    PORT
      LAYER M4 ;
        RECT  112.236 81.168 112.32 81.192 ;
    END
  END n_li_d[416]
  PIN n_li_d[417]
    DIRECTION INPUT ;
    USE SIGNAL ;
    PORT
      LAYER M4 ;
        RECT  112.236 81.312 112.32 81.336 ;
    END
  END n_li_d[417]
  PIN n_li_d[418]
    DIRECTION INPUT ;
    USE SIGNAL ;
    PORT
      LAYER M4 ;
        RECT  112.236 81.504 112.32 81.528 ;
    END
  END n_li_d[418]
  PIN n_li_d[419]
    DIRECTION INPUT ;
    USE SIGNAL ;
    PORT
      LAYER M4 ;
        RECT  112.236 81.696 112.32 81.72 ;
    END
  END n_li_d[419]
  PIN n_li_d[41]
    DIRECTION INPUT ;
    USE SIGNAL ;
    PORT
      LAYER M4 ;
        RECT  112.236 13.92 112.32 13.944 ;
    END
  END n_li_d[41]
  PIN n_li_d[420]
    DIRECTION INPUT ;
    USE SIGNAL ;
    PORT
      LAYER M4 ;
        RECT  112.236 81.888 112.32 81.912 ;
    END
  END n_li_d[420]
  PIN n_li_d[421]
    DIRECTION INPUT ;
    USE SIGNAL ;
    PORT
      LAYER M4 ;
        RECT  112.236 82.032 112.32 82.056 ;
    END
  END n_li_d[421]
  PIN n_li_d[422]
    DIRECTION INPUT ;
    USE SIGNAL ;
    PORT
      LAYER M4 ;
        RECT  112.236 82.224 112.32 82.248 ;
    END
  END n_li_d[422]
  PIN n_li_d[423]
    DIRECTION INPUT ;
    USE SIGNAL ;
    PORT
      LAYER M4 ;
        RECT  112.236 82.416 112.32 82.44 ;
    END
  END n_li_d[423]
  PIN n_li_d[424]
    DIRECTION INPUT ;
    USE SIGNAL ;
    PORT
      LAYER M4 ;
        RECT  112.236 82.608 112.32 82.632 ;
    END
  END n_li_d[424]
  PIN n_li_d[425]
    DIRECTION INPUT ;
    USE SIGNAL ;
    PORT
      LAYER M4 ;
        RECT  112.236 82.752 112.32 82.776 ;
    END
  END n_li_d[425]
  PIN n_li_d[426]
    DIRECTION INPUT ;
    USE SIGNAL ;
    PORT
      LAYER M4 ;
        RECT  112.236 82.944 112.32 82.968 ;
    END
  END n_li_d[426]
  PIN n_li_d[427]
    DIRECTION INPUT ;
    USE SIGNAL ;
    PORT
      LAYER M4 ;
        RECT  112.236 83.136 112.32 83.16 ;
    END
  END n_li_d[427]
  PIN n_li_d[428]
    DIRECTION INPUT ;
    USE SIGNAL ;
    PORT
      LAYER M4 ;
        RECT  112.236 83.328 112.32 83.352 ;
    END
  END n_li_d[428]
  PIN n_li_d[429]
    DIRECTION INPUT ;
    USE SIGNAL ;
    PORT
      LAYER M4 ;
        RECT  112.236 83.472 112.32 83.496 ;
    END
  END n_li_d[429]
  PIN n_li_d[42]
    DIRECTION INPUT ;
    USE SIGNAL ;
    PORT
      LAYER M4 ;
        RECT  112.236 14.112 112.32 14.136 ;
    END
  END n_li_d[42]
  PIN n_li_d[430]
    DIRECTION INPUT ;
    USE SIGNAL ;
    PORT
      LAYER M4 ;
        RECT  112.236 83.664 112.32 83.688 ;
    END
  END n_li_d[430]
  PIN n_li_d[431]
    DIRECTION INPUT ;
    USE SIGNAL ;
    PORT
      LAYER M4 ;
        RECT  112.236 83.856 112.32 83.88 ;
    END
  END n_li_d[431]
  PIN n_li_d[432]
    DIRECTION INPUT ;
    USE SIGNAL ;
    PORT
      LAYER M4 ;
        RECT  112.236 84.048 112.32 84.072 ;
    END
  END n_li_d[432]
  PIN n_li_d[433]
    DIRECTION INPUT ;
    USE SIGNAL ;
    PORT
      LAYER M4 ;
        RECT  112.236 84.192 112.32 84.216 ;
    END
  END n_li_d[433]
  PIN n_li_d[434]
    DIRECTION INPUT ;
    USE SIGNAL ;
    PORT
      LAYER M4 ;
        RECT  112.236 84.384 112.32 84.408 ;
    END
  END n_li_d[434]
  PIN n_li_d[435]
    DIRECTION INPUT ;
    USE SIGNAL ;
    PORT
      LAYER M4 ;
        RECT  112.236 84.576 112.32 84.6 ;
    END
  END n_li_d[435]
  PIN n_li_d[436]
    DIRECTION INPUT ;
    USE SIGNAL ;
    PORT
      LAYER M4 ;
        RECT  112.236 84.72 112.32 84.744 ;
    END
  END n_li_d[436]
  PIN n_li_d[437]
    DIRECTION INPUT ;
    USE SIGNAL ;
    PORT
      LAYER M4 ;
        RECT  112.236 84.912 112.32 84.936 ;
    END
  END n_li_d[437]
  PIN n_li_d[438]
    DIRECTION INPUT ;
    USE SIGNAL ;
    PORT
      LAYER M4 ;
        RECT  112.236 85.104 112.32 85.128 ;
    END
  END n_li_d[438]
  PIN n_li_d[439]
    DIRECTION INPUT ;
    USE SIGNAL ;
    PORT
      LAYER M4 ;
        RECT  112.236 85.296 112.32 85.32 ;
    END
  END n_li_d[439]
  PIN n_li_d[43]
    DIRECTION INPUT ;
    USE SIGNAL ;
    PORT
      LAYER M4 ;
        RECT  112.236 14.304 112.32 14.328 ;
    END
  END n_li_d[43]
  PIN n_li_d[440]
    DIRECTION INPUT ;
    USE SIGNAL ;
    PORT
      LAYER M4 ;
        RECT  112.236 85.44 112.32 85.464 ;
    END
  END n_li_d[440]
  PIN n_li_d[441]
    DIRECTION INPUT ;
    USE SIGNAL ;
    PORT
      LAYER M4 ;
        RECT  112.236 85.632 112.32 85.656 ;
    END
  END n_li_d[441]
  PIN n_li_d[442]
    DIRECTION INPUT ;
    USE SIGNAL ;
    PORT
      LAYER M4 ;
        RECT  112.236 85.824 112.32 85.848 ;
    END
  END n_li_d[442]
  PIN n_li_d[443]
    DIRECTION INPUT ;
    USE SIGNAL ;
    PORT
      LAYER M4 ;
        RECT  112.236 86.016 112.32 86.04 ;
    END
  END n_li_d[443]
  PIN n_li_d[444]
    DIRECTION INPUT ;
    USE SIGNAL ;
    PORT
      LAYER M4 ;
        RECT  112.236 86.16 112.32 86.184 ;
    END
  END n_li_d[444]
  PIN n_li_d[445]
    DIRECTION INPUT ;
    USE SIGNAL ;
    PORT
      LAYER M4 ;
        RECT  112.236 86.352 112.32 86.376 ;
    END
  END n_li_d[445]
  PIN n_li_d[446]
    DIRECTION INPUT ;
    USE SIGNAL ;
    PORT
      LAYER M4 ;
        RECT  112.236 86.544 112.32 86.568 ;
    END
  END n_li_d[446]
  PIN n_li_d[447]
    DIRECTION INPUT ;
    USE SIGNAL ;
    PORT
      LAYER M4 ;
        RECT  112.236 86.736 112.32 86.76 ;
    END
  END n_li_d[447]
  PIN n_li_d[448]
    DIRECTION INPUT ;
    USE SIGNAL ;
    PORT
      LAYER M4 ;
        RECT  112.236 86.88 112.32 86.904 ;
    END
  END n_li_d[448]
  PIN n_li_d[449]
    DIRECTION INPUT ;
    USE SIGNAL ;
    PORT
      LAYER M4 ;
        RECT  112.236 87.072 112.32 87.096 ;
    END
  END n_li_d[449]
  PIN n_li_d[44]
    DIRECTION INPUT ;
    USE SIGNAL ;
    PORT
      LAYER M4 ;
        RECT  112.236 14.448 112.32 14.472 ;
    END
  END n_li_d[44]
  PIN n_li_d[450]
    DIRECTION INPUT ;
    USE SIGNAL ;
    PORT
      LAYER M4 ;
        RECT  112.236 87.264 112.32 87.288 ;
    END
  END n_li_d[450]
  PIN n_li_d[451]
    DIRECTION INPUT ;
    USE SIGNAL ;
    PORT
      LAYER M4 ;
        RECT  112.236 87.408 112.32 87.432 ;
    END
  END n_li_d[451]
  PIN n_li_d[452]
    DIRECTION INPUT ;
    USE SIGNAL ;
    PORT
      LAYER M4 ;
        RECT  112.236 87.6 112.32 87.624 ;
    END
  END n_li_d[452]
  PIN n_li_d[453]
    DIRECTION INPUT ;
    USE SIGNAL ;
    PORT
      LAYER M4 ;
        RECT  112.236 87.792 112.32 87.816 ;
    END
  END n_li_d[453]
  PIN n_li_d[454]
    DIRECTION INPUT ;
    USE SIGNAL ;
    PORT
      LAYER M4 ;
        RECT  112.236 87.984 112.32 88.008 ;
    END
  END n_li_d[454]
  PIN n_li_d[455]
    DIRECTION INPUT ;
    USE SIGNAL ;
    PORT
      LAYER M4 ;
        RECT  112.236 88.128 112.32 88.152 ;
    END
  END n_li_d[455]
  PIN n_li_d[456]
    DIRECTION INPUT ;
    USE SIGNAL ;
    PORT
      LAYER M4 ;
        RECT  112.236 88.32 112.32 88.344 ;
    END
  END n_li_d[456]
  PIN n_li_d[457]
    DIRECTION INPUT ;
    USE SIGNAL ;
    PORT
      LAYER M4 ;
        RECT  112.236 88.512 112.32 88.536 ;
    END
  END n_li_d[457]
  PIN n_li_d[458]
    DIRECTION INPUT ;
    USE SIGNAL ;
    PORT
      LAYER M4 ;
        RECT  112.236 88.704 112.32 88.728 ;
    END
  END n_li_d[458]
  PIN n_li_d[459]
    DIRECTION INPUT ;
    USE SIGNAL ;
    PORT
      LAYER M4 ;
        RECT  112.236 88.848 112.32 88.872 ;
    END
  END n_li_d[459]
  PIN n_li_d[45]
    DIRECTION INPUT ;
    USE SIGNAL ;
    PORT
      LAYER M4 ;
        RECT  112.236 14.64 112.32 14.664 ;
    END
  END n_li_d[45]
  PIN n_li_d[460]
    DIRECTION INPUT ;
    USE SIGNAL ;
    PORT
      LAYER M4 ;
        RECT  112.236 89.04 112.32 89.064 ;
    END
  END n_li_d[460]
  PIN n_li_d[461]
    DIRECTION INPUT ;
    USE SIGNAL ;
    PORT
      LAYER M4 ;
        RECT  112.236 89.232 112.32 89.256 ;
    END
  END n_li_d[461]
  PIN n_li_d[462]
    DIRECTION INPUT ;
    USE SIGNAL ;
    PORT
      LAYER M4 ;
        RECT  112.236 89.424 112.32 89.448 ;
    END
  END n_li_d[462]
  PIN n_li_d[463]
    DIRECTION INPUT ;
    USE SIGNAL ;
    PORT
      LAYER M4 ;
        RECT  112.236 89.568 112.32 89.592 ;
    END
  END n_li_d[463]
  PIN n_li_d[464]
    DIRECTION INPUT ;
    USE SIGNAL ;
    PORT
      LAYER M4 ;
        RECT  112.236 89.76 112.32 89.784 ;
    END
  END n_li_d[464]
  PIN n_li_d[465]
    DIRECTION INPUT ;
    USE SIGNAL ;
    PORT
      LAYER M4 ;
        RECT  112.236 89.952 112.32 89.976 ;
    END
  END n_li_d[465]
  PIN n_li_d[466]
    DIRECTION INPUT ;
    USE SIGNAL ;
    PORT
      LAYER M4 ;
        RECT  112.236 90.096 112.32 90.12 ;
    END
  END n_li_d[466]
  PIN n_li_d[467]
    DIRECTION INPUT ;
    USE SIGNAL ;
    PORT
      LAYER M4 ;
        RECT  112.236 90.288 112.32 90.312 ;
    END
  END n_li_d[467]
  PIN n_li_d[468]
    DIRECTION INPUT ;
    USE SIGNAL ;
    PORT
      LAYER M4 ;
        RECT  112.236 90.48 112.32 90.504 ;
    END
  END n_li_d[468]
  PIN n_li_d[469]
    DIRECTION INPUT ;
    USE SIGNAL ;
    PORT
      LAYER M4 ;
        RECT  112.236 90.672 112.32 90.696 ;
    END
  END n_li_d[469]
  PIN n_li_d[46]
    DIRECTION INPUT ;
    USE SIGNAL ;
    PORT
      LAYER M4 ;
        RECT  112.236 14.832 112.32 14.856 ;
    END
  END n_li_d[46]
  PIN n_li_d[470]
    DIRECTION INPUT ;
    USE SIGNAL ;
    PORT
      LAYER M4 ;
        RECT  112.236 90.816 112.32 90.84 ;
    END
  END n_li_d[470]
  PIN n_li_d[471]
    DIRECTION INPUT ;
    USE SIGNAL ;
    PORT
      LAYER M4 ;
        RECT  112.236 91.008 112.32 91.032 ;
    END
  END n_li_d[471]
  PIN n_li_d[472]
    DIRECTION INPUT ;
    USE SIGNAL ;
    PORT
      LAYER M4 ;
        RECT  112.236 91.2 112.32 91.224 ;
    END
  END n_li_d[472]
  PIN n_li_d[473]
    DIRECTION INPUT ;
    USE SIGNAL ;
    PORT
      LAYER M4 ;
        RECT  112.236 91.392 112.32 91.416 ;
    END
  END n_li_d[473]
  PIN n_li_d[474]
    DIRECTION INPUT ;
    USE SIGNAL ;
    PORT
      LAYER M4 ;
        RECT  112.236 91.536 112.32 91.56 ;
    END
  END n_li_d[474]
  PIN n_li_d[475]
    DIRECTION INPUT ;
    USE SIGNAL ;
    PORT
      LAYER M4 ;
        RECT  112.236 91.728 112.32 91.752 ;
    END
  END n_li_d[475]
  PIN n_li_d[476]
    DIRECTION INPUT ;
    USE SIGNAL ;
    PORT
      LAYER M4 ;
        RECT  112.236 91.92 112.32 91.944 ;
    END
  END n_li_d[476]
  PIN n_li_d[477]
    DIRECTION INPUT ;
    USE SIGNAL ;
    PORT
      LAYER M4 ;
        RECT  112.236 92.112 112.32 92.136 ;
    END
  END n_li_d[477]
  PIN n_li_d[478]
    DIRECTION INPUT ;
    USE SIGNAL ;
    PORT
      LAYER M4 ;
        RECT  112.236 92.256 112.32 92.28 ;
    END
  END n_li_d[478]
  PIN n_li_d[479]
    DIRECTION INPUT ;
    USE SIGNAL ;
    PORT
      LAYER M4 ;
        RECT  112.236 92.448 112.32 92.472 ;
    END
  END n_li_d[479]
  PIN n_li_d[47]
    DIRECTION INPUT ;
    USE SIGNAL ;
    PORT
      LAYER M4 ;
        RECT  112.236 15.024 112.32 15.048 ;
    END
  END n_li_d[47]
  PIN n_li_d[480]
    DIRECTION INPUT ;
    USE SIGNAL ;
    PORT
      LAYER M4 ;
        RECT  112.236 92.64 112.32 92.664 ;
    END
  END n_li_d[480]
  PIN n_li_d[481]
    DIRECTION INPUT ;
    USE SIGNAL ;
    PORT
      LAYER M4 ;
        RECT  112.236 92.832 112.32 92.856 ;
    END
  END n_li_d[481]
  PIN n_li_d[482]
    DIRECTION INPUT ;
    USE SIGNAL ;
    PORT
      LAYER M4 ;
        RECT  112.236 92.976 112.32 93 ;
    END
  END n_li_d[482]
  PIN n_li_d[483]
    DIRECTION INPUT ;
    USE SIGNAL ;
    PORT
      LAYER M4 ;
        RECT  112.236 93.168 112.32 93.192 ;
    END
  END n_li_d[483]
  PIN n_li_d[484]
    DIRECTION INPUT ;
    USE SIGNAL ;
    PORT
      LAYER M4 ;
        RECT  112.236 93.36 112.32 93.384 ;
    END
  END n_li_d[484]
  PIN n_li_d[485]
    DIRECTION INPUT ;
    USE SIGNAL ;
    PORT
      LAYER M4 ;
        RECT  112.236 93.504 112.32 93.528 ;
    END
  END n_li_d[485]
  PIN n_li_d[486]
    DIRECTION INPUT ;
    USE SIGNAL ;
    PORT
      LAYER M4 ;
        RECT  112.236 93.696 112.32 93.72 ;
    END
  END n_li_d[486]
  PIN n_li_d[487]
    DIRECTION INPUT ;
    USE SIGNAL ;
    PORT
      LAYER M4 ;
        RECT  112.236 93.888 112.32 93.912 ;
    END
  END n_li_d[487]
  PIN n_li_d[488]
    DIRECTION INPUT ;
    USE SIGNAL ;
    PORT
      LAYER M4 ;
        RECT  112.236 94.08 112.32 94.104 ;
    END
  END n_li_d[488]
  PIN n_li_d[489]
    DIRECTION INPUT ;
    USE SIGNAL ;
    PORT
      LAYER M4 ;
        RECT  112.236 94.224 112.32 94.248 ;
    END
  END n_li_d[489]
  PIN n_li_d[48]
    DIRECTION INPUT ;
    USE SIGNAL ;
    PORT
      LAYER M4 ;
        RECT  112.236 15.168 112.32 15.192 ;
    END
  END n_li_d[48]
  PIN n_li_d[490]
    DIRECTION INPUT ;
    USE SIGNAL ;
    PORT
      LAYER M4 ;
        RECT  112.236 94.416 112.32 94.44 ;
    END
  END n_li_d[490]
  PIN n_li_d[491]
    DIRECTION INPUT ;
    USE SIGNAL ;
    PORT
      LAYER M4 ;
        RECT  112.236 94.608 112.32 94.632 ;
    END
  END n_li_d[491]
  PIN n_li_d[492]
    DIRECTION INPUT ;
    USE SIGNAL ;
    PORT
      LAYER M4 ;
        RECT  112.236 94.8 112.32 94.824 ;
    END
  END n_li_d[492]
  PIN n_li_d[493]
    DIRECTION INPUT ;
    USE SIGNAL ;
    PORT
      LAYER M4 ;
        RECT  112.236 94.944 112.32 94.968 ;
    END
  END n_li_d[493]
  PIN n_li_d[494]
    DIRECTION INPUT ;
    USE SIGNAL ;
    PORT
      LAYER M4 ;
        RECT  112.236 95.136 112.32 95.16 ;
    END
  END n_li_d[494]
  PIN n_li_d[495]
    DIRECTION INPUT ;
    USE SIGNAL ;
    PORT
      LAYER M4 ;
        RECT  112.236 95.328 112.32 95.352 ;
    END
  END n_li_d[495]
  PIN n_li_d[496]
    DIRECTION INPUT ;
    USE SIGNAL ;
    PORT
      LAYER M4 ;
        RECT  112.236 95.52 112.32 95.544 ;
    END
  END n_li_d[496]
  PIN n_li_d[497]
    DIRECTION INPUT ;
    USE SIGNAL ;
    PORT
      LAYER M4 ;
        RECT  112.236 95.664 112.32 95.688 ;
    END
  END n_li_d[497]
  PIN n_li_d[498]
    DIRECTION INPUT ;
    USE SIGNAL ;
    PORT
      LAYER M4 ;
        RECT  112.236 95.856 112.32 95.88 ;
    END
  END n_li_d[498]
  PIN n_li_d[499]
    DIRECTION INPUT ;
    USE SIGNAL ;
    PORT
      LAYER M4 ;
        RECT  112.236 96.048 112.32 96.072 ;
    END
  END n_li_d[499]
  PIN n_li_d[49]
    DIRECTION INPUT ;
    USE SIGNAL ;
    PORT
      LAYER M4 ;
        RECT  112.236 15.36 112.32 15.384 ;
    END
  END n_li_d[49]
  PIN n_li_d[4]
    DIRECTION INPUT ;
    USE SIGNAL ;
    PORT
      LAYER M4 ;
        RECT  112.236 7.296 112.32 7.32 ;
    END
  END n_li_d[4]
  PIN n_li_d[500]
    DIRECTION INPUT ;
    USE SIGNAL ;
    PORT
      LAYER M4 ;
        RECT  112.236 96.192 112.32 96.216 ;
    END
  END n_li_d[500]
  PIN n_li_d[501]
    DIRECTION INPUT ;
    USE SIGNAL ;
    PORT
      LAYER M4 ;
        RECT  112.236 96.384 112.32 96.408 ;
    END
  END n_li_d[501]
  PIN n_li_d[502]
    DIRECTION INPUT ;
    USE SIGNAL ;
    PORT
      LAYER M4 ;
        RECT  112.236 96.576 112.32 96.6 ;
    END
  END n_li_d[502]
  PIN n_li_d[503]
    DIRECTION INPUT ;
    USE SIGNAL ;
    PORT
      LAYER M4 ;
        RECT  112.236 96.768 112.32 96.792 ;
    END
  END n_li_d[503]
  PIN n_li_d[504]
    DIRECTION INPUT ;
    USE SIGNAL ;
    PORT
      LAYER M4 ;
        RECT  112.236 96.912 112.32 96.936 ;
    END
  END n_li_d[504]
  PIN n_li_d[505]
    DIRECTION INPUT ;
    USE SIGNAL ;
    PORT
      LAYER M4 ;
        RECT  112.236 97.104 112.32 97.128 ;
    END
  END n_li_d[505]
  PIN n_li_d[506]
    DIRECTION INPUT ;
    USE SIGNAL ;
    PORT
      LAYER M4 ;
        RECT  112.236 97.296 112.32 97.32 ;
    END
  END n_li_d[506]
  PIN n_li_d[507]
    DIRECTION INPUT ;
    USE SIGNAL ;
    PORT
      LAYER M4 ;
        RECT  112.236 97.488 112.32 97.512 ;
    END
  END n_li_d[507]
  PIN n_li_d[508]
    DIRECTION INPUT ;
    USE SIGNAL ;
    PORT
      LAYER M4 ;
        RECT  112.236 97.632 112.32 97.656 ;
    END
  END n_li_d[508]
  PIN n_li_d[509]
    DIRECTION INPUT ;
    USE SIGNAL ;
    PORT
      LAYER M4 ;
        RECT  112.236 97.824 112.32 97.848 ;
    END
  END n_li_d[509]
  PIN n_li_d[50]
    DIRECTION INPUT ;
    USE SIGNAL ;
    PORT
      LAYER M4 ;
        RECT  112.236 15.552 112.32 15.576 ;
    END
  END n_li_d[50]
  PIN n_li_d[510]
    DIRECTION INPUT ;
    USE SIGNAL ;
    PORT
      LAYER M4 ;
        RECT  112.236 98.016 112.32 98.04 ;
    END
  END n_li_d[510]
  PIN n_li_d[511]
    DIRECTION INPUT ;
    USE SIGNAL ;
    PORT
      LAYER M4 ;
        RECT  112.236 98.208 112.32 98.232 ;
    END
  END n_li_d[511]
  PIN n_li_d[512]
    DIRECTION INPUT ;
    USE SIGNAL ;
    PORT
      LAYER M4 ;
        RECT  112.236 98.352 112.32 98.376 ;
    END
  END n_li_d[512]
  PIN n_li_d[513]
    DIRECTION INPUT ;
    USE SIGNAL ;
    PORT
      LAYER M4 ;
        RECT  112.236 98.544 112.32 98.568 ;
    END
  END n_li_d[513]
  PIN n_li_d[514]
    DIRECTION INPUT ;
    USE SIGNAL ;
    PORT
      LAYER M4 ;
        RECT  112.236 98.736 112.32 98.76 ;
    END
  END n_li_d[514]
  PIN n_li_d[515]
    DIRECTION INPUT ;
    USE SIGNAL ;
    PORT
      LAYER M4 ;
        RECT  112.236 98.88 112.32 98.904 ;
    END
  END n_li_d[515]
  PIN n_li_d[516]
    DIRECTION INPUT ;
    USE SIGNAL ;
    PORT
      LAYER M4 ;
        RECT  112.236 99.072 112.32 99.096 ;
    END
  END n_li_d[516]
  PIN n_li_d[517]
    DIRECTION INPUT ;
    USE SIGNAL ;
    PORT
      LAYER M4 ;
        RECT  112.236 99.264 112.32 99.288 ;
    END
  END n_li_d[517]
  PIN n_li_d[518]
    DIRECTION INPUT ;
    USE SIGNAL ;
    PORT
      LAYER M4 ;
        RECT  112.236 99.456 112.32 99.48 ;
    END
  END n_li_d[518]
  PIN n_li_d[519]
    DIRECTION INPUT ;
    USE SIGNAL ;
    PORT
      LAYER M4 ;
        RECT  112.236 99.6 112.32 99.624 ;
    END
  END n_li_d[519]
  PIN n_li_d[51]
    DIRECTION INPUT ;
    USE SIGNAL ;
    PORT
      LAYER M4 ;
        RECT  112.236 15.744 112.32 15.768 ;
    END
  END n_li_d[51]
  PIN n_li_d[520]
    DIRECTION INPUT ;
    USE SIGNAL ;
    PORT
      LAYER M4 ;
        RECT  112.236 99.792 112.32 99.816 ;
    END
  END n_li_d[520]
  PIN n_li_d[521]
    DIRECTION INPUT ;
    USE SIGNAL ;
    PORT
      LAYER M4 ;
        RECT  112.236 99.984 112.32 100.008 ;
    END
  END n_li_d[521]
  PIN n_li_d[522]
    DIRECTION INPUT ;
    USE SIGNAL ;
    PORT
      LAYER M4 ;
        RECT  112.236 100.176 112.32 100.2 ;
    END
  END n_li_d[522]
  PIN n_li_d[523]
    DIRECTION INPUT ;
    USE SIGNAL ;
    PORT
      LAYER M4 ;
        RECT  112.236 100.32 112.32 100.344 ;
    END
  END n_li_d[523]
  PIN n_li_d[524]
    DIRECTION INPUT ;
    USE SIGNAL ;
    PORT
      LAYER M4 ;
        RECT  112.236 100.512 112.32 100.536 ;
    END
  END n_li_d[524]
  PIN n_li_d[525]
    DIRECTION INPUT ;
    USE SIGNAL ;
    PORT
      LAYER M4 ;
        RECT  112.236 100.704 112.32 100.728 ;
    END
  END n_li_d[525]
  PIN n_li_d[526]
    DIRECTION INPUT ;
    USE SIGNAL ;
    PORT
      LAYER M4 ;
        RECT  112.236 100.896 112.32 100.92 ;
    END
  END n_li_d[526]
  PIN n_li_d[527]
    DIRECTION INPUT ;
    USE SIGNAL ;
    PORT
      LAYER M4 ;
        RECT  112.236 101.04 112.32 101.064 ;
    END
  END n_li_d[527]
  PIN n_li_d[528]
    DIRECTION INPUT ;
    USE SIGNAL ;
    PORT
      LAYER M4 ;
        RECT  112.236 101.232 112.32 101.256 ;
    END
  END n_li_d[528]
  PIN n_li_d[529]
    DIRECTION INPUT ;
    USE SIGNAL ;
    PORT
      LAYER M4 ;
        RECT  112.236 101.424 112.32 101.448 ;
    END
  END n_li_d[529]
  PIN n_li_d[52]
    DIRECTION INPUT ;
    USE SIGNAL ;
    PORT
      LAYER M4 ;
        RECT  112.236 15.888 112.32 15.912 ;
    END
  END n_li_d[52]
  PIN n_li_d[530]
    DIRECTION INPUT ;
    USE SIGNAL ;
    PORT
      LAYER M4 ;
        RECT  112.236 101.616 112.32 101.64 ;
    END
  END n_li_d[530]
  PIN n_li_d[531]
    DIRECTION INPUT ;
    USE SIGNAL ;
    PORT
      LAYER M4 ;
        RECT  112.236 101.76 112.32 101.784 ;
    END
  END n_li_d[531]
  PIN n_li_d[532]
    DIRECTION INPUT ;
    USE SIGNAL ;
    PORT
      LAYER M4 ;
        RECT  112.236 101.952 112.32 101.976 ;
    END
  END n_li_d[532]
  PIN n_li_d[533]
    DIRECTION INPUT ;
    USE SIGNAL ;
    PORT
      LAYER M4 ;
        RECT  112.236 102.144 112.32 102.168 ;
    END
  END n_li_d[533]
  PIN n_li_d[534]
    DIRECTION INPUT ;
    USE SIGNAL ;
    PORT
      LAYER M4 ;
        RECT  112.236 102.288 112.32 102.312 ;
    END
  END n_li_d[534]
  PIN n_li_d[535]
    DIRECTION INPUT ;
    USE SIGNAL ;
    PORT
      LAYER M4 ;
        RECT  112.236 102.48 112.32 102.504 ;
    END
  END n_li_d[535]
  PIN n_li_d[536]
    DIRECTION INPUT ;
    USE SIGNAL ;
    PORT
      LAYER M4 ;
        RECT  112.236 102.672 112.32 102.696 ;
    END
  END n_li_d[536]
  PIN n_li_d[537]
    DIRECTION INPUT ;
    USE SIGNAL ;
    PORT
      LAYER M4 ;
        RECT  112.236 102.864 112.32 102.888 ;
    END
  END n_li_d[537]
  PIN n_li_d[538]
    DIRECTION INPUT ;
    USE SIGNAL ;
    PORT
      LAYER M4 ;
        RECT  112.236 103.008 112.32 103.032 ;
    END
  END n_li_d[538]
  PIN n_li_d[539]
    DIRECTION INPUT ;
    USE SIGNAL ;
    PORT
      LAYER M4 ;
        RECT  112.236 103.2 112.32 103.224 ;
    END
  END n_li_d[539]
  PIN n_li_d[53]
    DIRECTION INPUT ;
    USE SIGNAL ;
    PORT
      LAYER M4 ;
        RECT  112.236 16.08 112.32 16.104 ;
    END
  END n_li_d[53]
  PIN n_li_d[540]
    DIRECTION INPUT ;
    USE SIGNAL ;
    PORT
      LAYER M4 ;
        RECT  112.236 103.392 112.32 103.416 ;
    END
  END n_li_d[540]
  PIN n_li_d[541]
    DIRECTION INPUT ;
    USE SIGNAL ;
    PORT
      LAYER M4 ;
        RECT  112.236 103.584 112.32 103.608 ;
    END
  END n_li_d[541]
  PIN n_li_d[542]
    DIRECTION INPUT ;
    USE SIGNAL ;
    PORT
      LAYER M4 ;
        RECT  112.236 103.728 112.32 103.752 ;
    END
  END n_li_d[542]
  PIN n_li_d[543]
    DIRECTION INPUT ;
    USE SIGNAL ;
    PORT
      LAYER M4 ;
        RECT  112.236 103.92 112.32 103.944 ;
    END
  END n_li_d[543]
  PIN n_li_d[544]
    DIRECTION INPUT ;
    USE SIGNAL ;
    PORT
      LAYER M4 ;
        RECT  112.236 104.112 112.32 104.136 ;
    END
  END n_li_d[544]
  PIN n_li_d[545]
    DIRECTION INPUT ;
    USE SIGNAL ;
    PORT
      LAYER M4 ;
        RECT  112.236 104.304 112.32 104.328 ;
    END
  END n_li_d[545]
  PIN n_li_d[546]
    DIRECTION INPUT ;
    USE SIGNAL ;
    PORT
      LAYER M4 ;
        RECT  112.236 104.448 112.32 104.472 ;
    END
  END n_li_d[546]
  PIN n_li_d[547]
    DIRECTION INPUT ;
    USE SIGNAL ;
    PORT
      LAYER M4 ;
        RECT  112.236 104.64 112.32 104.664 ;
    END
  END n_li_d[547]
  PIN n_li_d[548]
    DIRECTION INPUT ;
    USE SIGNAL ;
    PORT
      LAYER M4 ;
        RECT  112.236 104.832 112.32 104.856 ;
    END
  END n_li_d[548]
  PIN n_li_d[549]
    DIRECTION INPUT ;
    USE SIGNAL ;
    PORT
      LAYER M4 ;
        RECT  112.236 104.976 112.32 105 ;
    END
  END n_li_d[549]
  PIN n_li_d[54]
    DIRECTION INPUT ;
    USE SIGNAL ;
    PORT
      LAYER M4 ;
        RECT  112.236 16.272 112.32 16.296 ;
    END
  END n_li_d[54]
  PIN n_li_d[550]
    DIRECTION INPUT ;
    USE SIGNAL ;
    PORT
      LAYER M4 ;
        RECT  112.236 105.168 112.32 105.192 ;
    END
  END n_li_d[550]
  PIN n_li_d[551]
    DIRECTION INPUT ;
    USE SIGNAL ;
    PORT
      LAYER M4 ;
        RECT  112.236 105.36 112.32 105.384 ;
    END
  END n_li_d[551]
  PIN n_li_d[552]
    DIRECTION INPUT ;
    USE SIGNAL ;
    PORT
      LAYER M4 ;
        RECT  112.236 105.552 112.32 105.576 ;
    END
  END n_li_d[552]
  PIN n_li_d[55]
    DIRECTION INPUT ;
    USE SIGNAL ;
    PORT
      LAYER M4 ;
        RECT  112.236 16.416 112.32 16.44 ;
    END
  END n_li_d[55]
  PIN n_li_d[56]
    DIRECTION INPUT ;
    USE SIGNAL ;
    PORT
      LAYER M4 ;
        RECT  112.236 16.608 112.32 16.632 ;
    END
  END n_li_d[56]
  PIN n_li_d[57]
    DIRECTION INPUT ;
    USE SIGNAL ;
    PORT
      LAYER M4 ;
        RECT  112.236 16.8 112.32 16.824 ;
    END
  END n_li_d[57]
  PIN n_li_d[58]
    DIRECTION INPUT ;
    USE SIGNAL ;
    PORT
      LAYER M4 ;
        RECT  112.236 16.992 112.32 17.016 ;
    END
  END n_li_d[58]
  PIN n_li_d[59]
    DIRECTION INPUT ;
    USE SIGNAL ;
    PORT
      LAYER M4 ;
        RECT  112.236 17.136 112.32 17.16 ;
    END
  END n_li_d[59]
  PIN n_li_d[5]
    DIRECTION INPUT ;
    USE SIGNAL ;
    PORT
      LAYER M4 ;
        RECT  112.236 7.488 112.32 7.512 ;
    END
  END n_li_d[5]
  PIN n_li_d[60]
    DIRECTION INPUT ;
    USE SIGNAL ;
    PORT
      LAYER M4 ;
        RECT  112.236 17.328 112.32 17.352 ;
    END
  END n_li_d[60]
  PIN n_li_d[61]
    DIRECTION INPUT ;
    USE SIGNAL ;
    PORT
      LAYER M4 ;
        RECT  112.236 17.52 112.32 17.544 ;
    END
  END n_li_d[61]
  PIN n_li_d[62]
    DIRECTION INPUT ;
    USE SIGNAL ;
    PORT
      LAYER M4 ;
        RECT  112.236 17.712 112.32 17.736 ;
    END
  END n_li_d[62]
  PIN n_li_d[63]
    DIRECTION INPUT ;
    USE SIGNAL ;
    PORT
      LAYER M4 ;
        RECT  112.236 17.856 112.32 17.88 ;
    END
  END n_li_d[63]
  PIN n_li_d[64]
    DIRECTION INPUT ;
    USE SIGNAL ;
    PORT
      LAYER M4 ;
        RECT  112.236 18.048 112.32 18.072 ;
    END
  END n_li_d[64]
  PIN n_li_d[65]
    DIRECTION INPUT ;
    USE SIGNAL ;
    PORT
      LAYER M4 ;
        RECT  112.236 18.24 112.32 18.264 ;
    END
  END n_li_d[65]
  PIN n_li_d[66]
    DIRECTION INPUT ;
    USE SIGNAL ;
    PORT
      LAYER M4 ;
        RECT  112.236 18.432 112.32 18.456 ;
    END
  END n_li_d[66]
  PIN n_li_d[67]
    DIRECTION INPUT ;
    USE SIGNAL ;
    PORT
      LAYER M4 ;
        RECT  112.236 18.576 112.32 18.6 ;
    END
  END n_li_d[67]
  PIN n_li_d[68]
    DIRECTION INPUT ;
    USE SIGNAL ;
    PORT
      LAYER M4 ;
        RECT  112.236 18.768 112.32 18.792 ;
    END
  END n_li_d[68]
  PIN n_li_d[69]
    DIRECTION INPUT ;
    USE SIGNAL ;
    PORT
      LAYER M4 ;
        RECT  112.236 18.96 112.32 18.984 ;
    END
  END n_li_d[69]
  PIN n_li_d[6]
    DIRECTION INPUT ;
    USE SIGNAL ;
    PORT
      LAYER M4 ;
        RECT  112.236 7.632 112.32 7.656 ;
    END
  END n_li_d[6]
  PIN n_li_d[70]
    DIRECTION INPUT ;
    USE SIGNAL ;
    PORT
      LAYER M4 ;
        RECT  112.236 19.152 112.32 19.176 ;
    END
  END n_li_d[70]
  PIN n_li_d[71]
    DIRECTION INPUT ;
    USE SIGNAL ;
    PORT
      LAYER M4 ;
        RECT  112.236 19.296 112.32 19.32 ;
    END
  END n_li_d[71]
  PIN n_li_d[72]
    DIRECTION INPUT ;
    USE SIGNAL ;
    PORT
      LAYER M4 ;
        RECT  112.236 19.488 112.32 19.512 ;
    END
  END n_li_d[72]
  PIN n_li_d[73]
    DIRECTION INPUT ;
    USE SIGNAL ;
    PORT
      LAYER M4 ;
        RECT  112.236 19.68 112.32 19.704 ;
    END
  END n_li_d[73]
  PIN n_li_d[74]
    DIRECTION INPUT ;
    USE SIGNAL ;
    PORT
      LAYER M4 ;
        RECT  112.236 19.824 112.32 19.848 ;
    END
  END n_li_d[74]
  PIN n_li_d[75]
    DIRECTION INPUT ;
    USE SIGNAL ;
    PORT
      LAYER M4 ;
        RECT  112.236 20.016 112.32 20.04 ;
    END
  END n_li_d[75]
  PIN n_li_d[76]
    DIRECTION INPUT ;
    USE SIGNAL ;
    PORT
      LAYER M4 ;
        RECT  112.236 20.208 112.32 20.232 ;
    END
  END n_li_d[76]
  PIN n_li_d[77]
    DIRECTION INPUT ;
    USE SIGNAL ;
    PORT
      LAYER M4 ;
        RECT  112.236 20.4 112.32 20.424 ;
    END
  END n_li_d[77]
  PIN n_li_d[78]
    DIRECTION INPUT ;
    USE SIGNAL ;
    PORT
      LAYER M4 ;
        RECT  112.236 20.544 112.32 20.568 ;
    END
  END n_li_d[78]
  PIN n_li_d[79]
    DIRECTION INPUT ;
    USE SIGNAL ;
    PORT
      LAYER M4 ;
        RECT  112.236 20.736 112.32 20.76 ;
    END
  END n_li_d[79]
  PIN n_li_d[7]
    DIRECTION INPUT ;
    USE SIGNAL ;
    PORT
      LAYER M4 ;
        RECT  112.236 7.824 112.32 7.848 ;
    END
  END n_li_d[7]
  PIN n_li_d[80]
    DIRECTION INPUT ;
    USE SIGNAL ;
    PORT
      LAYER M4 ;
        RECT  112.236 20.928 112.32 20.952 ;
    END
  END n_li_d[80]
  PIN n_li_d[81]
    DIRECTION INPUT ;
    USE SIGNAL ;
    PORT
      LAYER M4 ;
        RECT  112.236 21.12 112.32 21.144 ;
    END
  END n_li_d[81]
  PIN n_li_d[82]
    DIRECTION INPUT ;
    USE SIGNAL ;
    PORT
      LAYER M4 ;
        RECT  112.236 21.264 112.32 21.288 ;
    END
  END n_li_d[82]
  PIN n_li_d[83]
    DIRECTION INPUT ;
    USE SIGNAL ;
    PORT
      LAYER M4 ;
        RECT  112.236 21.456 112.32 21.48 ;
    END
  END n_li_d[83]
  PIN n_li_d[84]
    DIRECTION INPUT ;
    USE SIGNAL ;
    PORT
      LAYER M4 ;
        RECT  112.236 21.648 112.32 21.672 ;
    END
  END n_li_d[84]
  PIN n_li_d[85]
    DIRECTION INPUT ;
    USE SIGNAL ;
    PORT
      LAYER M4 ;
        RECT  112.236 21.84 112.32 21.864 ;
    END
  END n_li_d[85]
  PIN n_li_d[86]
    DIRECTION INPUT ;
    USE SIGNAL ;
    PORT
      LAYER M4 ;
        RECT  112.236 21.984 112.32 22.008 ;
    END
  END n_li_d[86]
  PIN n_li_d[87]
    DIRECTION INPUT ;
    USE SIGNAL ;
    PORT
      LAYER M4 ;
        RECT  112.236 22.176 112.32 22.2 ;
    END
  END n_li_d[87]
  PIN n_li_d[88]
    DIRECTION INPUT ;
    USE SIGNAL ;
    PORT
      LAYER M4 ;
        RECT  112.236 22.368 112.32 22.392 ;
    END
  END n_li_d[88]
  PIN n_li_d[89]
    DIRECTION INPUT ;
    USE SIGNAL ;
    PORT
      LAYER M4 ;
        RECT  112.236 22.512 112.32 22.536 ;
    END
  END n_li_d[89]
  PIN n_li_d[8]
    DIRECTION INPUT ;
    USE SIGNAL ;
    PORT
      LAYER M4 ;
        RECT  112.236 8.016 112.32 8.04 ;
    END
  END n_li_d[8]
  PIN n_li_d[90]
    DIRECTION INPUT ;
    USE SIGNAL ;
    PORT
      LAYER M4 ;
        RECT  112.236 22.704 112.32 22.728 ;
    END
  END n_li_d[90]
  PIN n_li_d[91]
    DIRECTION INPUT ;
    USE SIGNAL ;
    PORT
      LAYER M4 ;
        RECT  112.236 22.896 112.32 22.92 ;
    END
  END n_li_d[91]
  PIN n_li_d[92]
    DIRECTION INPUT ;
    USE SIGNAL ;
    PORT
      LAYER M4 ;
        RECT  112.236 23.088 112.32 23.112 ;
    END
  END n_li_d[92]
  PIN n_li_d[93]
    DIRECTION INPUT ;
    USE SIGNAL ;
    PORT
      LAYER M4 ;
        RECT  112.236 23.232 112.32 23.256 ;
    END
  END n_li_d[93]
  PIN n_li_d[94]
    DIRECTION INPUT ;
    USE SIGNAL ;
    PORT
      LAYER M4 ;
        RECT  112.236 23.424 112.32 23.448 ;
    END
  END n_li_d[94]
  PIN n_li_d[95]
    DIRECTION INPUT ;
    USE SIGNAL ;
    PORT
      LAYER M4 ;
        RECT  112.236 23.616 112.32 23.64 ;
    END
  END n_li_d[95]
  PIN n_li_d[96]
    DIRECTION INPUT ;
    USE SIGNAL ;
    PORT
      LAYER M4 ;
        RECT  112.236 23.808 112.32 23.832 ;
    END
  END n_li_d[96]
  PIN n_li_d[97]
    DIRECTION INPUT ;
    USE SIGNAL ;
    PORT
      LAYER M4 ;
        RECT  112.236 23.952 112.32 23.976 ;
    END
  END n_li_d[97]
  PIN n_li_d[98]
    DIRECTION INPUT ;
    USE SIGNAL ;
    PORT
      LAYER M4 ;
        RECT  112.236 24.144 112.32 24.168 ;
    END
  END n_li_d[98]
  PIN n_li_d[99]
    DIRECTION INPUT ;
    USE SIGNAL ;
    PORT
      LAYER M4 ;
        RECT  112.236 24.336 112.32 24.36 ;
    END
  END n_li_d[99]
  PIN n_li_d[9]
    DIRECTION INPUT ;
    USE SIGNAL ;
    PORT
      LAYER M4 ;
        RECT  112.236 8.208 112.32 8.232 ;
    END
  END n_li_d[9]
  PIN n_li_r
    DIRECTION OUTPUT ;
    USE SIGNAL ;
    PORT
      LAYER M5 ;
        RECT  105.552 112.236 105.576 112.32 ;
    END
  END n_li_r
  PIN n_li_v
    DIRECTION INPUT ;
    USE SIGNAL ;
    PORT
      LAYER M4 ;
        RECT  112.236 6.384 112.32 6.408 ;
    END
  END n_li_v
  PIN n_lo_d[0]
    DIRECTION OUTPUT ;
    USE SIGNAL ;
    PORT
      LAYER M5 ;
        RECT  6.768 112.236 6.792 112.32 ;
    END
  END n_lo_d[0]
  PIN n_lo_d[100]
    DIRECTION OUTPUT ;
    USE SIGNAL ;
    PORT
      LAYER M5 ;
        RECT  24.384 112.236 24.408 112.32 ;
    END
  END n_lo_d[100]
  PIN n_lo_d[101]
    DIRECTION OUTPUT ;
    USE SIGNAL ;
    PORT
      LAYER M5 ;
        RECT  24.576 112.236 24.6 112.32 ;
    END
  END n_lo_d[101]
  PIN n_lo_d[102]
    DIRECTION OUTPUT ;
    USE SIGNAL ;
    PORT
      LAYER M5 ;
        RECT  24.768 112.236 24.792 112.32 ;
    END
  END n_lo_d[102]
  PIN n_lo_d[103]
    DIRECTION OUTPUT ;
    USE SIGNAL ;
    PORT
      LAYER M5 ;
        RECT  24.912 112.236 24.936 112.32 ;
    END
  END n_lo_d[103]
  PIN n_lo_d[104]
    DIRECTION OUTPUT ;
    USE SIGNAL ;
    PORT
      LAYER M5 ;
        RECT  25.104 112.236 25.128 112.32 ;
    END
  END n_lo_d[104]
  PIN n_lo_d[105]
    DIRECTION OUTPUT ;
    USE SIGNAL ;
    PORT
      LAYER M5 ;
        RECT  25.296 112.236 25.32 112.32 ;
    END
  END n_lo_d[105]
  PIN n_lo_d[106]
    DIRECTION OUTPUT ;
    USE SIGNAL ;
    PORT
      LAYER M5 ;
        RECT  25.488 112.236 25.512 112.32 ;
    END
  END n_lo_d[106]
  PIN n_lo_d[107]
    DIRECTION OUTPUT ;
    USE SIGNAL ;
    PORT
      LAYER M5 ;
        RECT  25.632 112.236 25.656 112.32 ;
    END
  END n_lo_d[107]
  PIN n_lo_d[108]
    DIRECTION OUTPUT ;
    USE SIGNAL ;
    PORT
      LAYER M5 ;
        RECT  25.824 112.236 25.848 112.32 ;
    END
  END n_lo_d[108]
  PIN n_lo_d[109]
    DIRECTION OUTPUT ;
    USE SIGNAL ;
    PORT
      LAYER M5 ;
        RECT  26.016 112.236 26.04 112.32 ;
    END
  END n_lo_d[109]
  PIN n_lo_d[10]
    DIRECTION OUTPUT ;
    USE SIGNAL ;
    PORT
      LAYER M5 ;
        RECT  8.208 112.236 8.232 112.32 ;
    END
  END n_lo_d[10]
  PIN n_lo_d[110]
    DIRECTION OUTPUT ;
    USE SIGNAL ;
    PORT
      LAYER M5 ;
        RECT  26.208 112.236 26.232 112.32 ;
    END
  END n_lo_d[110]
  PIN n_lo_d[111]
    DIRECTION OUTPUT ;
    USE SIGNAL ;
    PORT
      LAYER M5 ;
        RECT  26.352 112.236 26.376 112.32 ;
    END
  END n_lo_d[111]
  PIN n_lo_d[112]
    DIRECTION OUTPUT ;
    USE SIGNAL ;
    PORT
      LAYER M5 ;
        RECT  26.544 112.236 26.568 112.32 ;
    END
  END n_lo_d[112]
  PIN n_lo_d[113]
    DIRECTION OUTPUT ;
    USE SIGNAL ;
    PORT
      LAYER M5 ;
        RECT  26.736 112.236 26.76 112.32 ;
    END
  END n_lo_d[113]
  PIN n_lo_d[114]
    DIRECTION OUTPUT ;
    USE SIGNAL ;
    PORT
      LAYER M5 ;
        RECT  26.928 112.236 26.952 112.32 ;
    END
  END n_lo_d[114]
  PIN n_lo_d[115]
    DIRECTION OUTPUT ;
    USE SIGNAL ;
    PORT
      LAYER M5 ;
        RECT  27.072 112.236 27.096 112.32 ;
    END
  END n_lo_d[115]
  PIN n_lo_d[116]
    DIRECTION OUTPUT ;
    USE SIGNAL ;
    PORT
      LAYER M5 ;
        RECT  27.264 112.236 27.288 112.32 ;
    END
  END n_lo_d[116]
  PIN n_lo_d[117]
    DIRECTION OUTPUT ;
    USE SIGNAL ;
    PORT
      LAYER M5 ;
        RECT  27.456 112.236 27.48 112.32 ;
    END
  END n_lo_d[117]
  PIN n_lo_d[118]
    DIRECTION OUTPUT ;
    USE SIGNAL ;
    PORT
      LAYER M5 ;
        RECT  27.648 112.236 27.672 112.32 ;
    END
  END n_lo_d[118]
  PIN n_lo_d[119]
    DIRECTION OUTPUT ;
    USE SIGNAL ;
    PORT
      LAYER M5 ;
        RECT  27.792 112.236 27.816 112.32 ;
    END
  END n_lo_d[119]
  PIN n_lo_d[11]
    DIRECTION OUTPUT ;
    USE SIGNAL ;
    PORT
      LAYER M5 ;
        RECT  8.4 112.236 8.424 112.32 ;
    END
  END n_lo_d[11]
  PIN n_lo_d[120]
    DIRECTION OUTPUT ;
    USE SIGNAL ;
    PORT
      LAYER M5 ;
        RECT  28.368 112.236 28.392 112.32 ;
    END
  END n_lo_d[120]
  PIN n_lo_d[121]
    DIRECTION OUTPUT ;
    USE SIGNAL ;
    PORT
      LAYER M5 ;
        RECT  28.416 112.236 28.44 112.32 ;
    END
  END n_lo_d[121]
  PIN n_lo_d[122]
    DIRECTION OUTPUT ;
    USE SIGNAL ;
    PORT
      LAYER M5 ;
        RECT  28.464 112.236 28.488 112.32 ;
    END
  END n_lo_d[122]
  PIN n_lo_d[123]
    DIRECTION OUTPUT ;
    USE SIGNAL ;
    PORT
      LAYER M5 ;
        RECT  28.512 112.236 28.536 112.32 ;
    END
  END n_lo_d[123]
  PIN n_lo_d[124]
    DIRECTION OUTPUT ;
    USE SIGNAL ;
    PORT
      LAYER M5 ;
        RECT  28.704 112.236 28.728 112.32 ;
    END
  END n_lo_d[124]
  PIN n_lo_d[125]
    DIRECTION OUTPUT ;
    USE SIGNAL ;
    PORT
      LAYER M5 ;
        RECT  28.896 112.236 28.92 112.32 ;
    END
  END n_lo_d[125]
  PIN n_lo_d[126]
    DIRECTION OUTPUT ;
    USE SIGNAL ;
    PORT
      LAYER M5 ;
        RECT  29.088 112.236 29.112 112.32 ;
    END
  END n_lo_d[126]
  PIN n_lo_d[127]
    DIRECTION OUTPUT ;
    USE SIGNAL ;
    PORT
      LAYER M5 ;
        RECT  29.232 112.236 29.256 112.32 ;
    END
  END n_lo_d[127]
  PIN n_lo_d[128]
    DIRECTION OUTPUT ;
    USE SIGNAL ;
    PORT
      LAYER M5 ;
        RECT  29.424 112.236 29.448 112.32 ;
    END
  END n_lo_d[128]
  PIN n_lo_d[129]
    DIRECTION OUTPUT ;
    USE SIGNAL ;
    PORT
      LAYER M5 ;
        RECT  29.616 112.236 29.64 112.32 ;
    END
  END n_lo_d[129]
  PIN n_lo_d[12]
    DIRECTION OUTPUT ;
    USE SIGNAL ;
    PORT
      LAYER M5 ;
        RECT  8.544 112.236 8.568 112.32 ;
    END
  END n_lo_d[12]
  PIN n_lo_d[130]
    DIRECTION OUTPUT ;
    USE SIGNAL ;
    PORT
      LAYER M5 ;
        RECT  29.808 112.236 29.832 112.32 ;
    END
  END n_lo_d[130]
  PIN n_lo_d[131]
    DIRECTION OUTPUT ;
    USE SIGNAL ;
    PORT
      LAYER M5 ;
        RECT  29.952 112.236 29.976 112.32 ;
    END
  END n_lo_d[131]
  PIN n_lo_d[132]
    DIRECTION OUTPUT ;
    USE SIGNAL ;
    PORT
      LAYER M5 ;
        RECT  30.144 112.236 30.168 112.32 ;
    END
  END n_lo_d[132]
  PIN n_lo_d[133]
    DIRECTION OUTPUT ;
    USE SIGNAL ;
    PORT
      LAYER M5 ;
        RECT  30.336 112.236 30.36 112.32 ;
    END
  END n_lo_d[133]
  PIN n_lo_d[134]
    DIRECTION OUTPUT ;
    USE SIGNAL ;
    PORT
      LAYER M5 ;
        RECT  30.528 112.236 30.552 112.32 ;
    END
  END n_lo_d[134]
  PIN n_lo_d[135]
    DIRECTION OUTPUT ;
    USE SIGNAL ;
    PORT
      LAYER M5 ;
        RECT  30.672 112.236 30.696 112.32 ;
    END
  END n_lo_d[135]
  PIN n_lo_d[136]
    DIRECTION OUTPUT ;
    USE SIGNAL ;
    PORT
      LAYER M5 ;
        RECT  30.864 112.236 30.888 112.32 ;
    END
  END n_lo_d[136]
  PIN n_lo_d[137]
    DIRECTION OUTPUT ;
    USE SIGNAL ;
    PORT
      LAYER M5 ;
        RECT  31.056 112.236 31.08 112.32 ;
    END
  END n_lo_d[137]
  PIN n_lo_d[138]
    DIRECTION OUTPUT ;
    USE SIGNAL ;
    PORT
      LAYER M5 ;
        RECT  31.248 112.236 31.272 112.32 ;
    END
  END n_lo_d[138]
  PIN n_lo_d[139]
    DIRECTION OUTPUT ;
    USE SIGNAL ;
    PORT
      LAYER M5 ;
        RECT  31.392 112.236 31.416 112.32 ;
    END
  END n_lo_d[139]
  PIN n_lo_d[13]
    DIRECTION OUTPUT ;
    USE SIGNAL ;
    PORT
      LAYER M5 ;
        RECT  8.736 112.236 8.76 112.32 ;
    END
  END n_lo_d[13]
  PIN n_lo_d[140]
    DIRECTION OUTPUT ;
    USE SIGNAL ;
    PORT
      LAYER M5 ;
        RECT  31.584 112.236 31.608 112.32 ;
    END
  END n_lo_d[140]
  PIN n_lo_d[141]
    DIRECTION OUTPUT ;
    USE SIGNAL ;
    PORT
      LAYER M5 ;
        RECT  31.776 112.236 31.8 112.32 ;
    END
  END n_lo_d[141]
  PIN n_lo_d[142]
    DIRECTION OUTPUT ;
    USE SIGNAL ;
    PORT
      LAYER M5 ;
        RECT  31.968 112.236 31.992 112.32 ;
    END
  END n_lo_d[142]
  PIN n_lo_d[143]
    DIRECTION OUTPUT ;
    USE SIGNAL ;
    PORT
      LAYER M5 ;
        RECT  32.112 112.236 32.136 112.32 ;
    END
  END n_lo_d[143]
  PIN n_lo_d[144]
    DIRECTION OUTPUT ;
    USE SIGNAL ;
    PORT
      LAYER M5 ;
        RECT  32.688 112.236 32.712 112.32 ;
    END
  END n_lo_d[144]
  PIN n_lo_d[145]
    DIRECTION OUTPUT ;
    USE SIGNAL ;
    PORT
      LAYER M5 ;
        RECT  32.736 112.236 32.76 112.32 ;
    END
  END n_lo_d[145]
  PIN n_lo_d[146]
    DIRECTION OUTPUT ;
    USE SIGNAL ;
    PORT
      LAYER M5 ;
        RECT  32.784 112.236 32.808 112.32 ;
    END
  END n_lo_d[146]
  PIN n_lo_d[147]
    DIRECTION OUTPUT ;
    USE SIGNAL ;
    PORT
      LAYER M5 ;
        RECT  32.832 112.236 32.856 112.32 ;
    END
  END n_lo_d[147]
  PIN n_lo_d[148]
    DIRECTION OUTPUT ;
    USE SIGNAL ;
    PORT
      LAYER M5 ;
        RECT  33.024 112.236 33.048 112.32 ;
    END
  END n_lo_d[148]
  PIN n_lo_d[149]
    DIRECTION OUTPUT ;
    USE SIGNAL ;
    PORT
      LAYER M5 ;
        RECT  33.216 112.236 33.24 112.32 ;
    END
  END n_lo_d[149]
  PIN n_lo_d[14]
    DIRECTION OUTPUT ;
    USE SIGNAL ;
    PORT
      LAYER M5 ;
        RECT  8.928 112.236 8.952 112.32 ;
    END
  END n_lo_d[14]
  PIN n_lo_d[150]
    DIRECTION OUTPUT ;
    USE SIGNAL ;
    PORT
      LAYER M5 ;
        RECT  33.408 112.236 33.432 112.32 ;
    END
  END n_lo_d[150]
  PIN n_lo_d[151]
    DIRECTION OUTPUT ;
    USE SIGNAL ;
    PORT
      LAYER M5 ;
        RECT  33.552 112.236 33.576 112.32 ;
    END
  END n_lo_d[151]
  PIN n_lo_d[152]
    DIRECTION OUTPUT ;
    USE SIGNAL ;
    PORT
      LAYER M5 ;
        RECT  33.744 112.236 33.768 112.32 ;
    END
  END n_lo_d[152]
  PIN n_lo_d[153]
    DIRECTION OUTPUT ;
    USE SIGNAL ;
    PORT
      LAYER M5 ;
        RECT  33.936 112.236 33.96 112.32 ;
    END
  END n_lo_d[153]
  PIN n_lo_d[154]
    DIRECTION OUTPUT ;
    USE SIGNAL ;
    PORT
      LAYER M5 ;
        RECT  34.128 112.236 34.152 112.32 ;
    END
  END n_lo_d[154]
  PIN n_lo_d[155]
    DIRECTION OUTPUT ;
    USE SIGNAL ;
    PORT
      LAYER M5 ;
        RECT  34.272 112.236 34.296 112.32 ;
    END
  END n_lo_d[155]
  PIN n_lo_d[156]
    DIRECTION OUTPUT ;
    USE SIGNAL ;
    PORT
      LAYER M5 ;
        RECT  34.464 112.236 34.488 112.32 ;
    END
  END n_lo_d[156]
  PIN n_lo_d[157]
    DIRECTION OUTPUT ;
    USE SIGNAL ;
    PORT
      LAYER M5 ;
        RECT  34.656 112.236 34.68 112.32 ;
    END
  END n_lo_d[157]
  PIN n_lo_d[158]
    DIRECTION OUTPUT ;
    USE SIGNAL ;
    PORT
      LAYER M5 ;
        RECT  34.848 112.236 34.872 112.32 ;
    END
  END n_lo_d[158]
  PIN n_lo_d[159]
    DIRECTION OUTPUT ;
    USE SIGNAL ;
    PORT
      LAYER M5 ;
        RECT  34.992 112.236 35.016 112.32 ;
    END
  END n_lo_d[159]
  PIN n_lo_d[15]
    DIRECTION OUTPUT ;
    USE SIGNAL ;
    PORT
      LAYER M5 ;
        RECT  9.12 112.236 9.144 112.32 ;
    END
  END n_lo_d[15]
  PIN n_lo_d[160]
    DIRECTION OUTPUT ;
    USE SIGNAL ;
    PORT
      LAYER M5 ;
        RECT  35.184 112.236 35.208 112.32 ;
    END
  END n_lo_d[160]
  PIN n_lo_d[161]
    DIRECTION OUTPUT ;
    USE SIGNAL ;
    PORT
      LAYER M5 ;
        RECT  35.376 112.236 35.4 112.32 ;
    END
  END n_lo_d[161]
  PIN n_lo_d[162]
    DIRECTION OUTPUT ;
    USE SIGNAL ;
    PORT
      LAYER M5 ;
        RECT  35.568 112.236 35.592 112.32 ;
    END
  END n_lo_d[162]
  PIN n_lo_d[163]
    DIRECTION OUTPUT ;
    USE SIGNAL ;
    PORT
      LAYER M5 ;
        RECT  35.712 112.236 35.736 112.32 ;
    END
  END n_lo_d[163]
  PIN n_lo_d[164]
    DIRECTION OUTPUT ;
    USE SIGNAL ;
    PORT
      LAYER M5 ;
        RECT  35.904 112.236 35.928 112.32 ;
    END
  END n_lo_d[164]
  PIN n_lo_d[165]
    DIRECTION OUTPUT ;
    USE SIGNAL ;
    PORT
      LAYER M5 ;
        RECT  36.096 112.236 36.12 112.32 ;
    END
  END n_lo_d[165]
  PIN n_lo_d[166]
    DIRECTION OUTPUT ;
    USE SIGNAL ;
    PORT
      LAYER M5 ;
        RECT  36.288 112.236 36.312 112.32 ;
    END
  END n_lo_d[166]
  PIN n_lo_d[167]
    DIRECTION OUTPUT ;
    USE SIGNAL ;
    PORT
      LAYER M5 ;
        RECT  36.432 112.236 36.456 112.32 ;
    END
  END n_lo_d[167]
  PIN n_lo_d[168]
    DIRECTION OUTPUT ;
    USE SIGNAL ;
    PORT
      LAYER M5 ;
        RECT  37.008 112.236 37.032 112.32 ;
    END
  END n_lo_d[168]
  PIN n_lo_d[169]
    DIRECTION OUTPUT ;
    USE SIGNAL ;
    PORT
      LAYER M5 ;
        RECT  37.056 112.236 37.08 112.32 ;
    END
  END n_lo_d[169]
  PIN n_lo_d[16]
    DIRECTION OUTPUT ;
    USE SIGNAL ;
    PORT
      LAYER M5 ;
        RECT  9.264 112.236 9.288 112.32 ;
    END
  END n_lo_d[16]
  PIN n_lo_d[170]
    DIRECTION OUTPUT ;
    USE SIGNAL ;
    PORT
      LAYER M5 ;
        RECT  37.104 112.236 37.128 112.32 ;
    END
  END n_lo_d[170]
  PIN n_lo_d[171]
    DIRECTION OUTPUT ;
    USE SIGNAL ;
    PORT
      LAYER M5 ;
        RECT  37.152 112.236 37.176 112.32 ;
    END
  END n_lo_d[171]
  PIN n_lo_d[172]
    DIRECTION OUTPUT ;
    USE SIGNAL ;
    PORT
      LAYER M5 ;
        RECT  37.344 112.236 37.368 112.32 ;
    END
  END n_lo_d[172]
  PIN n_lo_d[173]
    DIRECTION OUTPUT ;
    USE SIGNAL ;
    PORT
      LAYER M5 ;
        RECT  37.536 112.236 37.56 112.32 ;
    END
  END n_lo_d[173]
  PIN n_lo_d[174]
    DIRECTION OUTPUT ;
    USE SIGNAL ;
    PORT
      LAYER M5 ;
        RECT  37.728 112.236 37.752 112.32 ;
    END
  END n_lo_d[174]
  PIN n_lo_d[175]
    DIRECTION OUTPUT ;
    USE SIGNAL ;
    PORT
      LAYER M5 ;
        RECT  37.872 112.236 37.896 112.32 ;
    END
  END n_lo_d[175]
  PIN n_lo_d[176]
    DIRECTION OUTPUT ;
    USE SIGNAL ;
    PORT
      LAYER M5 ;
        RECT  38.064 112.236 38.088 112.32 ;
    END
  END n_lo_d[176]
  PIN n_lo_d[177]
    DIRECTION OUTPUT ;
    USE SIGNAL ;
    PORT
      LAYER M5 ;
        RECT  38.256 112.236 38.28 112.32 ;
    END
  END n_lo_d[177]
  PIN n_lo_d[178]
    DIRECTION OUTPUT ;
    USE SIGNAL ;
    PORT
      LAYER M5 ;
        RECT  38.448 112.236 38.472 112.32 ;
    END
  END n_lo_d[178]
  PIN n_lo_d[179]
    DIRECTION OUTPUT ;
    USE SIGNAL ;
    PORT
      LAYER M5 ;
        RECT  38.592 112.236 38.616 112.32 ;
    END
  END n_lo_d[179]
  PIN n_lo_d[17]
    DIRECTION OUTPUT ;
    USE SIGNAL ;
    PORT
      LAYER M5 ;
        RECT  9.456 112.236 9.48 112.32 ;
    END
  END n_lo_d[17]
  PIN n_lo_d[180]
    DIRECTION OUTPUT ;
    USE SIGNAL ;
    PORT
      LAYER M5 ;
        RECT  38.784 112.236 38.808 112.32 ;
    END
  END n_lo_d[180]
  PIN n_lo_d[181]
    DIRECTION OUTPUT ;
    USE SIGNAL ;
    PORT
      LAYER M5 ;
        RECT  38.976 112.236 39 112.32 ;
    END
  END n_lo_d[181]
  PIN n_lo_d[182]
    DIRECTION OUTPUT ;
    USE SIGNAL ;
    PORT
      LAYER M5 ;
        RECT  39.168 112.236 39.192 112.32 ;
    END
  END n_lo_d[182]
  PIN n_lo_d[183]
    DIRECTION OUTPUT ;
    USE SIGNAL ;
    PORT
      LAYER M5 ;
        RECT  39.312 112.236 39.336 112.32 ;
    END
  END n_lo_d[183]
  PIN n_lo_d[184]
    DIRECTION OUTPUT ;
    USE SIGNAL ;
    PORT
      LAYER M5 ;
        RECT  39.504 112.236 39.528 112.32 ;
    END
  END n_lo_d[184]
  PIN n_lo_d[185]
    DIRECTION OUTPUT ;
    USE SIGNAL ;
    PORT
      LAYER M5 ;
        RECT  39.696 112.236 39.72 112.32 ;
    END
  END n_lo_d[185]
  PIN n_lo_d[186]
    DIRECTION OUTPUT ;
    USE SIGNAL ;
    PORT
      LAYER M5 ;
        RECT  39.888 112.236 39.912 112.32 ;
    END
  END n_lo_d[186]
  PIN n_lo_d[187]
    DIRECTION OUTPUT ;
    USE SIGNAL ;
    PORT
      LAYER M5 ;
        RECT  40.032 112.236 40.056 112.32 ;
    END
  END n_lo_d[187]
  PIN n_lo_d[188]
    DIRECTION OUTPUT ;
    USE SIGNAL ;
    PORT
      LAYER M5 ;
        RECT  40.224 112.236 40.248 112.32 ;
    END
  END n_lo_d[188]
  PIN n_lo_d[189]
    DIRECTION OUTPUT ;
    USE SIGNAL ;
    PORT
      LAYER M5 ;
        RECT  40.416 112.236 40.44 112.32 ;
    END
  END n_lo_d[189]
  PIN n_lo_d[18]
    DIRECTION OUTPUT ;
    USE SIGNAL ;
    PORT
      LAYER M5 ;
        RECT  9.648 112.236 9.672 112.32 ;
    END
  END n_lo_d[18]
  PIN n_lo_d[190]
    DIRECTION OUTPUT ;
    USE SIGNAL ;
    PORT
      LAYER M5 ;
        RECT  40.608 112.236 40.632 112.32 ;
    END
  END n_lo_d[190]
  PIN n_lo_d[191]
    DIRECTION OUTPUT ;
    USE SIGNAL ;
    PORT
      LAYER M5 ;
        RECT  40.752 112.236 40.776 112.32 ;
    END
  END n_lo_d[191]
  PIN n_lo_d[192]
    DIRECTION OUTPUT ;
    USE SIGNAL ;
    PORT
      LAYER M5 ;
        RECT  41.328 112.236 41.352 112.32 ;
    END
  END n_lo_d[192]
  PIN n_lo_d[193]
    DIRECTION OUTPUT ;
    USE SIGNAL ;
    PORT
      LAYER M5 ;
        RECT  41.376 112.236 41.4 112.32 ;
    END
  END n_lo_d[193]
  PIN n_lo_d[194]
    DIRECTION OUTPUT ;
    USE SIGNAL ;
    PORT
      LAYER M5 ;
        RECT  41.424 112.236 41.448 112.32 ;
    END
  END n_lo_d[194]
  PIN n_lo_d[195]
    DIRECTION OUTPUT ;
    USE SIGNAL ;
    PORT
      LAYER M5 ;
        RECT  41.472 112.236 41.496 112.32 ;
    END
  END n_lo_d[195]
  PIN n_lo_d[196]
    DIRECTION OUTPUT ;
    USE SIGNAL ;
    PORT
      LAYER M5 ;
        RECT  41.664 112.236 41.688 112.32 ;
    END
  END n_lo_d[196]
  PIN n_lo_d[197]
    DIRECTION OUTPUT ;
    USE SIGNAL ;
    PORT
      LAYER M5 ;
        RECT  41.856 112.236 41.88 112.32 ;
    END
  END n_lo_d[197]
  PIN n_lo_d[198]
    DIRECTION OUTPUT ;
    USE SIGNAL ;
    PORT
      LAYER M5 ;
        RECT  42.048 112.236 42.072 112.32 ;
    END
  END n_lo_d[198]
  PIN n_lo_d[199]
    DIRECTION OUTPUT ;
    USE SIGNAL ;
    PORT
      LAYER M5 ;
        RECT  42.192 112.236 42.216 112.32 ;
    END
  END n_lo_d[199]
  PIN n_lo_d[19]
    DIRECTION OUTPUT ;
    USE SIGNAL ;
    PORT
      LAYER M5 ;
        RECT  9.84 112.236 9.864 112.32 ;
    END
  END n_lo_d[19]
  PIN n_lo_d[1]
    DIRECTION OUTPUT ;
    USE SIGNAL ;
    PORT
      LAYER M5 ;
        RECT  6.816 112.236 6.84 112.32 ;
    END
  END n_lo_d[1]
  PIN n_lo_d[200]
    DIRECTION OUTPUT ;
    USE SIGNAL ;
    PORT
      LAYER M5 ;
        RECT  42.384 112.236 42.408 112.32 ;
    END
  END n_lo_d[200]
  PIN n_lo_d[201]
    DIRECTION OUTPUT ;
    USE SIGNAL ;
    PORT
      LAYER M5 ;
        RECT  42.576 112.236 42.6 112.32 ;
    END
  END n_lo_d[201]
  PIN n_lo_d[202]
    DIRECTION OUTPUT ;
    USE SIGNAL ;
    PORT
      LAYER M5 ;
        RECT  42.768 112.236 42.792 112.32 ;
    END
  END n_lo_d[202]
  PIN n_lo_d[203]
    DIRECTION OUTPUT ;
    USE SIGNAL ;
    PORT
      LAYER M5 ;
        RECT  42.912 112.236 42.936 112.32 ;
    END
  END n_lo_d[203]
  PIN n_lo_d[204]
    DIRECTION OUTPUT ;
    USE SIGNAL ;
    PORT
      LAYER M5 ;
        RECT  43.104 112.236 43.128 112.32 ;
    END
  END n_lo_d[204]
  PIN n_lo_d[205]
    DIRECTION OUTPUT ;
    USE SIGNAL ;
    PORT
      LAYER M5 ;
        RECT  43.296 112.236 43.32 112.32 ;
    END
  END n_lo_d[205]
  PIN n_lo_d[206]
    DIRECTION OUTPUT ;
    USE SIGNAL ;
    PORT
      LAYER M5 ;
        RECT  43.488 112.236 43.512 112.32 ;
    END
  END n_lo_d[206]
  PIN n_lo_d[207]
    DIRECTION OUTPUT ;
    USE SIGNAL ;
    PORT
      LAYER M5 ;
        RECT  43.632 112.236 43.656 112.32 ;
    END
  END n_lo_d[207]
  PIN n_lo_d[208]
    DIRECTION OUTPUT ;
    USE SIGNAL ;
    PORT
      LAYER M5 ;
        RECT  43.824 112.236 43.848 112.32 ;
    END
  END n_lo_d[208]
  PIN n_lo_d[209]
    DIRECTION OUTPUT ;
    USE SIGNAL ;
    PORT
      LAYER M5 ;
        RECT  44.016 112.236 44.04 112.32 ;
    END
  END n_lo_d[209]
  PIN n_lo_d[20]
    DIRECTION OUTPUT ;
    USE SIGNAL ;
    PORT
      LAYER M5 ;
        RECT  9.984 112.236 10.008 112.32 ;
    END
  END n_lo_d[20]
  PIN n_lo_d[210]
    DIRECTION OUTPUT ;
    USE SIGNAL ;
    PORT
      LAYER M5 ;
        RECT  44.16 112.236 44.184 112.32 ;
    END
  END n_lo_d[210]
  PIN n_lo_d[211]
    DIRECTION OUTPUT ;
    USE SIGNAL ;
    PORT
      LAYER M5 ;
        RECT  44.352 112.236 44.376 112.32 ;
    END
  END n_lo_d[211]
  PIN n_lo_d[212]
    DIRECTION OUTPUT ;
    USE SIGNAL ;
    PORT
      LAYER M5 ;
        RECT  44.544 112.236 44.568 112.32 ;
    END
  END n_lo_d[212]
  PIN n_lo_d[213]
    DIRECTION OUTPUT ;
    USE SIGNAL ;
    PORT
      LAYER M5 ;
        RECT  44.736 112.236 44.76 112.32 ;
    END
  END n_lo_d[213]
  PIN n_lo_d[214]
    DIRECTION OUTPUT ;
    USE SIGNAL ;
    PORT
      LAYER M5 ;
        RECT  44.88 112.236 44.904 112.32 ;
    END
  END n_lo_d[214]
  PIN n_lo_d[215]
    DIRECTION OUTPUT ;
    USE SIGNAL ;
    PORT
      LAYER M5 ;
        RECT  45.072 112.236 45.096 112.32 ;
    END
  END n_lo_d[215]
  PIN n_lo_d[216]
    DIRECTION OUTPUT ;
    USE SIGNAL ;
    PORT
      LAYER M5 ;
        RECT  45.648 112.236 45.672 112.32 ;
    END
  END n_lo_d[216]
  PIN n_lo_d[217]
    DIRECTION OUTPUT ;
    USE SIGNAL ;
    PORT
      LAYER M5 ;
        RECT  45.696 112.236 45.72 112.32 ;
    END
  END n_lo_d[217]
  PIN n_lo_d[218]
    DIRECTION OUTPUT ;
    USE SIGNAL ;
    PORT
      LAYER M5 ;
        RECT  45.744 112.236 45.768 112.32 ;
    END
  END n_lo_d[218]
  PIN n_lo_d[219]
    DIRECTION OUTPUT ;
    USE SIGNAL ;
    PORT
      LAYER M5 ;
        RECT  45.792 112.236 45.816 112.32 ;
    END
  END n_lo_d[219]
  PIN n_lo_d[21]
    DIRECTION OUTPUT ;
    USE SIGNAL ;
    PORT
      LAYER M5 ;
        RECT  10.176 112.236 10.2 112.32 ;
    END
  END n_lo_d[21]
  PIN n_lo_d[220]
    DIRECTION OUTPUT ;
    USE SIGNAL ;
    PORT
      LAYER M5 ;
        RECT  45.984 112.236 46.008 112.32 ;
    END
  END n_lo_d[220]
  PIN n_lo_d[221]
    DIRECTION OUTPUT ;
    USE SIGNAL ;
    PORT
      LAYER M5 ;
        RECT  46.176 112.236 46.2 112.32 ;
    END
  END n_lo_d[221]
  PIN n_lo_d[222]
    DIRECTION OUTPUT ;
    USE SIGNAL ;
    PORT
      LAYER M5 ;
        RECT  46.32 112.236 46.344 112.32 ;
    END
  END n_lo_d[222]
  PIN n_lo_d[223]
    DIRECTION OUTPUT ;
    USE SIGNAL ;
    PORT
      LAYER M5 ;
        RECT  46.512 112.236 46.536 112.32 ;
    END
  END n_lo_d[223]
  PIN n_lo_d[224]
    DIRECTION OUTPUT ;
    USE SIGNAL ;
    PORT
      LAYER M5 ;
        RECT  46.704 112.236 46.728 112.32 ;
    END
  END n_lo_d[224]
  PIN n_lo_d[225]
    DIRECTION OUTPUT ;
    USE SIGNAL ;
    PORT
      LAYER M5 ;
        RECT  46.896 112.236 46.92 112.32 ;
    END
  END n_lo_d[225]
  PIN n_lo_d[226]
    DIRECTION OUTPUT ;
    USE SIGNAL ;
    PORT
      LAYER M5 ;
        RECT  47.04 112.236 47.064 112.32 ;
    END
  END n_lo_d[226]
  PIN n_lo_d[227]
    DIRECTION OUTPUT ;
    USE SIGNAL ;
    PORT
      LAYER M5 ;
        RECT  47.232 112.236 47.256 112.32 ;
    END
  END n_lo_d[227]
  PIN n_lo_d[228]
    DIRECTION OUTPUT ;
    USE SIGNAL ;
    PORT
      LAYER M5 ;
        RECT  47.424 112.236 47.448 112.32 ;
    END
  END n_lo_d[228]
  PIN n_lo_d[229]
    DIRECTION OUTPUT ;
    USE SIGNAL ;
    PORT
      LAYER M5 ;
        RECT  47.616 112.236 47.64 112.32 ;
    END
  END n_lo_d[229]
  PIN n_lo_d[22]
    DIRECTION OUTPUT ;
    USE SIGNAL ;
    PORT
      LAYER M5 ;
        RECT  10.368 112.236 10.392 112.32 ;
    END
  END n_lo_d[22]
  PIN n_lo_d[230]
    DIRECTION OUTPUT ;
    USE SIGNAL ;
    PORT
      LAYER M5 ;
        RECT  47.76 112.236 47.784 112.32 ;
    END
  END n_lo_d[230]
  PIN n_lo_d[231]
    DIRECTION OUTPUT ;
    USE SIGNAL ;
    PORT
      LAYER M5 ;
        RECT  47.952 112.236 47.976 112.32 ;
    END
  END n_lo_d[231]
  PIN n_lo_d[232]
    DIRECTION OUTPUT ;
    USE SIGNAL ;
    PORT
      LAYER M5 ;
        RECT  48.144 112.236 48.168 112.32 ;
    END
  END n_lo_d[232]
  PIN n_lo_d[233]
    DIRECTION OUTPUT ;
    USE SIGNAL ;
    PORT
      LAYER M5 ;
        RECT  48.336 112.236 48.36 112.32 ;
    END
  END n_lo_d[233]
  PIN n_lo_d[234]
    DIRECTION OUTPUT ;
    USE SIGNAL ;
    PORT
      LAYER M5 ;
        RECT  48.48 112.236 48.504 112.32 ;
    END
  END n_lo_d[234]
  PIN n_lo_d[235]
    DIRECTION OUTPUT ;
    USE SIGNAL ;
    PORT
      LAYER M5 ;
        RECT  48.672 112.236 48.696 112.32 ;
    END
  END n_lo_d[235]
  PIN n_lo_d[236]
    DIRECTION OUTPUT ;
    USE SIGNAL ;
    PORT
      LAYER M5 ;
        RECT  48.864 112.236 48.888 112.32 ;
    END
  END n_lo_d[236]
  PIN n_lo_d[237]
    DIRECTION OUTPUT ;
    USE SIGNAL ;
    PORT
      LAYER M5 ;
        RECT  49.056 112.236 49.08 112.32 ;
    END
  END n_lo_d[237]
  PIN n_lo_d[238]
    DIRECTION OUTPUT ;
    USE SIGNAL ;
    PORT
      LAYER M5 ;
        RECT  49.2 112.236 49.224 112.32 ;
    END
  END n_lo_d[238]
  PIN n_lo_d[239]
    DIRECTION OUTPUT ;
    USE SIGNAL ;
    PORT
      LAYER M5 ;
        RECT  49.392 112.236 49.416 112.32 ;
    END
  END n_lo_d[239]
  PIN n_lo_d[23]
    DIRECTION OUTPUT ;
    USE SIGNAL ;
    PORT
      LAYER M5 ;
        RECT  10.512 112.236 10.536 112.32 ;
    END
  END n_lo_d[23]
  PIN n_lo_d[240]
    DIRECTION OUTPUT ;
    USE SIGNAL ;
    PORT
      LAYER M5 ;
        RECT  49.968 112.236 49.992 112.32 ;
    END
  END n_lo_d[240]
  PIN n_lo_d[241]
    DIRECTION OUTPUT ;
    USE SIGNAL ;
    PORT
      LAYER M5 ;
        RECT  50.016 112.236 50.04 112.32 ;
    END
  END n_lo_d[241]
  PIN n_lo_d[242]
    DIRECTION OUTPUT ;
    USE SIGNAL ;
    PORT
      LAYER M5 ;
        RECT  50.064 112.236 50.088 112.32 ;
    END
  END n_lo_d[242]
  PIN n_lo_d[243]
    DIRECTION OUTPUT ;
    USE SIGNAL ;
    PORT
      LAYER M5 ;
        RECT  50.112 112.236 50.136 112.32 ;
    END
  END n_lo_d[243]
  PIN n_lo_d[244]
    DIRECTION OUTPUT ;
    USE SIGNAL ;
    PORT
      LAYER M5 ;
        RECT  50.304 112.236 50.328 112.32 ;
    END
  END n_lo_d[244]
  PIN n_lo_d[245]
    DIRECTION OUTPUT ;
    USE SIGNAL ;
    PORT
      LAYER M5 ;
        RECT  50.496 112.236 50.52 112.32 ;
    END
  END n_lo_d[245]
  PIN n_lo_d[246]
    DIRECTION OUTPUT ;
    USE SIGNAL ;
    PORT
      LAYER M5 ;
        RECT  50.64 112.236 50.664 112.32 ;
    END
  END n_lo_d[246]
  PIN n_lo_d[247]
    DIRECTION OUTPUT ;
    USE SIGNAL ;
    PORT
      LAYER M5 ;
        RECT  50.832 112.236 50.856 112.32 ;
    END
  END n_lo_d[247]
  PIN n_lo_d[248]
    DIRECTION OUTPUT ;
    USE SIGNAL ;
    PORT
      LAYER M5 ;
        RECT  51.024 112.236 51.048 112.32 ;
    END
  END n_lo_d[248]
  PIN n_lo_d[249]
    DIRECTION OUTPUT ;
    USE SIGNAL ;
    PORT
      LAYER M5 ;
        RECT  51.216 112.236 51.24 112.32 ;
    END
  END n_lo_d[249]
  PIN n_lo_d[24]
    DIRECTION OUTPUT ;
    USE SIGNAL ;
    PORT
      LAYER M5 ;
        RECT  11.088 112.236 11.112 112.32 ;
    END
  END n_lo_d[24]
  PIN n_lo_d[250]
    DIRECTION OUTPUT ;
    USE SIGNAL ;
    PORT
      LAYER M5 ;
        RECT  51.36 112.236 51.384 112.32 ;
    END
  END n_lo_d[250]
  PIN n_lo_d[251]
    DIRECTION OUTPUT ;
    USE SIGNAL ;
    PORT
      LAYER M5 ;
        RECT  51.552 112.236 51.576 112.32 ;
    END
  END n_lo_d[251]
  PIN n_lo_d[252]
    DIRECTION OUTPUT ;
    USE SIGNAL ;
    PORT
      LAYER M5 ;
        RECT  51.744 112.236 51.768 112.32 ;
    END
  END n_lo_d[252]
  PIN n_lo_d[253]
    DIRECTION OUTPUT ;
    USE SIGNAL ;
    PORT
      LAYER M5 ;
        RECT  51.936 112.236 51.96 112.32 ;
    END
  END n_lo_d[253]
  PIN n_lo_d[254]
    DIRECTION OUTPUT ;
    USE SIGNAL ;
    PORT
      LAYER M5 ;
        RECT  52.08 112.236 52.104 112.32 ;
    END
  END n_lo_d[254]
  PIN n_lo_d[255]
    DIRECTION OUTPUT ;
    USE SIGNAL ;
    PORT
      LAYER M5 ;
        RECT  52.272 112.236 52.296 112.32 ;
    END
  END n_lo_d[255]
  PIN n_lo_d[256]
    DIRECTION OUTPUT ;
    USE SIGNAL ;
    PORT
      LAYER M5 ;
        RECT  52.464 112.236 52.488 112.32 ;
    END
  END n_lo_d[256]
  PIN n_lo_d[257]
    DIRECTION OUTPUT ;
    USE SIGNAL ;
    PORT
      LAYER M5 ;
        RECT  52.656 112.236 52.68 112.32 ;
    END
  END n_lo_d[257]
  PIN n_lo_d[258]
    DIRECTION OUTPUT ;
    USE SIGNAL ;
    PORT
      LAYER M5 ;
        RECT  52.8 112.236 52.824 112.32 ;
    END
  END n_lo_d[258]
  PIN n_lo_d[259]
    DIRECTION OUTPUT ;
    USE SIGNAL ;
    PORT
      LAYER M5 ;
        RECT  52.992 112.236 53.016 112.32 ;
    END
  END n_lo_d[259]
  PIN n_lo_d[25]
    DIRECTION OUTPUT ;
    USE SIGNAL ;
    PORT
      LAYER M5 ;
        RECT  11.136 112.236 11.16 112.32 ;
    END
  END n_lo_d[25]
  PIN n_lo_d[260]
    DIRECTION OUTPUT ;
    USE SIGNAL ;
    PORT
      LAYER M5 ;
        RECT  53.184 112.236 53.208 112.32 ;
    END
  END n_lo_d[260]
  PIN n_lo_d[261]
    DIRECTION OUTPUT ;
    USE SIGNAL ;
    PORT
      LAYER M5 ;
        RECT  53.376 112.236 53.4 112.32 ;
    END
  END n_lo_d[261]
  PIN n_lo_d[262]
    DIRECTION OUTPUT ;
    USE SIGNAL ;
    PORT
      LAYER M5 ;
        RECT  53.52 112.236 53.544 112.32 ;
    END
  END n_lo_d[262]
  PIN n_lo_d[263]
    DIRECTION OUTPUT ;
    USE SIGNAL ;
    PORT
      LAYER M5 ;
        RECT  53.712 112.236 53.736 112.32 ;
    END
  END n_lo_d[263]
  PIN n_lo_d[264]
    DIRECTION OUTPUT ;
    USE SIGNAL ;
    PORT
      LAYER M5 ;
        RECT  54.288 112.236 54.312 112.32 ;
    END
  END n_lo_d[264]
  PIN n_lo_d[265]
    DIRECTION OUTPUT ;
    USE SIGNAL ;
    PORT
      LAYER M5 ;
        RECT  54.336 112.236 54.36 112.32 ;
    END
  END n_lo_d[265]
  PIN n_lo_d[266]
    DIRECTION OUTPUT ;
    USE SIGNAL ;
    PORT
      LAYER M5 ;
        RECT  54.384 112.236 54.408 112.32 ;
    END
  END n_lo_d[266]
  PIN n_lo_d[267]
    DIRECTION OUTPUT ;
    USE SIGNAL ;
    PORT
      LAYER M5 ;
        RECT  54.432 112.236 54.456 112.32 ;
    END
  END n_lo_d[267]
  PIN n_lo_d[268]
    DIRECTION OUTPUT ;
    USE SIGNAL ;
    PORT
      LAYER M5 ;
        RECT  54.624 112.236 54.648 112.32 ;
    END
  END n_lo_d[268]
  PIN n_lo_d[269]
    DIRECTION OUTPUT ;
    USE SIGNAL ;
    PORT
      LAYER M5 ;
        RECT  54.816 112.236 54.84 112.32 ;
    END
  END n_lo_d[269]
  PIN n_lo_d[26]
    DIRECTION OUTPUT ;
    USE SIGNAL ;
    PORT
      LAYER M5 ;
        RECT  11.184 112.236 11.208 112.32 ;
    END
  END n_lo_d[26]
  PIN n_lo_d[270]
    DIRECTION OUTPUT ;
    USE SIGNAL ;
    PORT
      LAYER M5 ;
        RECT  54.96 112.236 54.984 112.32 ;
    END
  END n_lo_d[270]
  PIN n_lo_d[271]
    DIRECTION OUTPUT ;
    USE SIGNAL ;
    PORT
      LAYER M5 ;
        RECT  55.152 112.236 55.176 112.32 ;
    END
  END n_lo_d[271]
  PIN n_lo_d[272]
    DIRECTION OUTPUT ;
    USE SIGNAL ;
    PORT
      LAYER M5 ;
        RECT  55.344 112.236 55.368 112.32 ;
    END
  END n_lo_d[272]
  PIN n_lo_d[273]
    DIRECTION OUTPUT ;
    USE SIGNAL ;
    PORT
      LAYER M5 ;
        RECT  55.536 112.236 55.56 112.32 ;
    END
  END n_lo_d[273]
  PIN n_lo_d[274]
    DIRECTION OUTPUT ;
    USE SIGNAL ;
    PORT
      LAYER M5 ;
        RECT  55.68 112.236 55.704 112.32 ;
    END
  END n_lo_d[274]
  PIN n_lo_d[275]
    DIRECTION OUTPUT ;
    USE SIGNAL ;
    PORT
      LAYER M5 ;
        RECT  55.872 112.236 55.896 112.32 ;
    END
  END n_lo_d[275]
  PIN n_lo_d[276]
    DIRECTION OUTPUT ;
    USE SIGNAL ;
    PORT
      LAYER M5 ;
        RECT  56.064 112.236 56.088 112.32 ;
    END
  END n_lo_d[276]
  PIN n_lo_d[277]
    DIRECTION OUTPUT ;
    USE SIGNAL ;
    PORT
      LAYER M5 ;
        RECT  56.256 112.236 56.28 112.32 ;
    END
  END n_lo_d[277]
  PIN n_lo_d[278]
    DIRECTION OUTPUT ;
    USE SIGNAL ;
    PORT
      LAYER M5 ;
        RECT  56.4 112.236 56.424 112.32 ;
    END
  END n_lo_d[278]
  PIN n_lo_d[279]
    DIRECTION OUTPUT ;
    USE SIGNAL ;
    PORT
      LAYER M5 ;
        RECT  56.592 112.236 56.616 112.32 ;
    END
  END n_lo_d[279]
  PIN n_lo_d[27]
    DIRECTION OUTPUT ;
    USE SIGNAL ;
    PORT
      LAYER M5 ;
        RECT  11.28 112.236 11.304 112.32 ;
    END
  END n_lo_d[27]
  PIN n_lo_d[280]
    DIRECTION OUTPUT ;
    USE SIGNAL ;
    PORT
      LAYER M5 ;
        RECT  56.784 112.236 56.808 112.32 ;
    END
  END n_lo_d[280]
  PIN n_lo_d[281]
    DIRECTION OUTPUT ;
    USE SIGNAL ;
    PORT
      LAYER M5 ;
        RECT  56.976 112.236 57 112.32 ;
    END
  END n_lo_d[281]
  PIN n_lo_d[282]
    DIRECTION OUTPUT ;
    USE SIGNAL ;
    PORT
      LAYER M5 ;
        RECT  57.12 112.236 57.144 112.32 ;
    END
  END n_lo_d[282]
  PIN n_lo_d[283]
    DIRECTION OUTPUT ;
    USE SIGNAL ;
    PORT
      LAYER M5 ;
        RECT  57.312 112.236 57.336 112.32 ;
    END
  END n_lo_d[283]
  PIN n_lo_d[284]
    DIRECTION OUTPUT ;
    USE SIGNAL ;
    PORT
      LAYER M5 ;
        RECT  57.504 112.236 57.528 112.32 ;
    END
  END n_lo_d[284]
  PIN n_lo_d[285]
    DIRECTION OUTPUT ;
    USE SIGNAL ;
    PORT
      LAYER M5 ;
        RECT  57.696 112.236 57.72 112.32 ;
    END
  END n_lo_d[285]
  PIN n_lo_d[286]
    DIRECTION OUTPUT ;
    USE SIGNAL ;
    PORT
      LAYER M5 ;
        RECT  57.84 112.236 57.864 112.32 ;
    END
  END n_lo_d[286]
  PIN n_lo_d[287]
    DIRECTION OUTPUT ;
    USE SIGNAL ;
    PORT
      LAYER M5 ;
        RECT  57.936 112.236 57.96 112.32 ;
    END
  END n_lo_d[287]
  PIN n_lo_d[288]
    DIRECTION OUTPUT ;
    USE SIGNAL ;
    PORT
      LAYER M5 ;
        RECT  57.984 112.236 58.008 112.32 ;
    END
  END n_lo_d[288]
  PIN n_lo_d[289]
    DIRECTION OUTPUT ;
    USE SIGNAL ;
    PORT
      LAYER M5 ;
        RECT  58.032 112.236 58.056 112.32 ;
    END
  END n_lo_d[289]
  PIN n_lo_d[28]
    DIRECTION OUTPUT ;
    USE SIGNAL ;
    PORT
      LAYER M5 ;
        RECT  11.424 112.236 11.448 112.32 ;
    END
  END n_lo_d[28]
  PIN n_lo_d[290]
    DIRECTION OUTPUT ;
    USE SIGNAL ;
    PORT
      LAYER M5 ;
        RECT  58.608 112.236 58.632 112.32 ;
    END
  END n_lo_d[290]
  PIN n_lo_d[291]
    DIRECTION OUTPUT ;
    USE SIGNAL ;
    PORT
      LAYER M5 ;
        RECT  58.752 112.236 58.776 112.32 ;
    END
  END n_lo_d[291]
  PIN n_lo_d[292]
    DIRECTION OUTPUT ;
    USE SIGNAL ;
    PORT
      LAYER M5 ;
        RECT  58.944 112.236 58.968 112.32 ;
    END
  END n_lo_d[292]
  PIN n_lo_d[293]
    DIRECTION OUTPUT ;
    USE SIGNAL ;
    PORT
      LAYER M5 ;
        RECT  59.136 112.236 59.16 112.32 ;
    END
  END n_lo_d[293]
  PIN n_lo_d[294]
    DIRECTION OUTPUT ;
    USE SIGNAL ;
    PORT
      LAYER M5 ;
        RECT  59.28 112.236 59.304 112.32 ;
    END
  END n_lo_d[294]
  PIN n_lo_d[295]
    DIRECTION OUTPUT ;
    USE SIGNAL ;
    PORT
      LAYER M5 ;
        RECT  59.472 112.236 59.496 112.32 ;
    END
  END n_lo_d[295]
  PIN n_lo_d[296]
    DIRECTION OUTPUT ;
    USE SIGNAL ;
    PORT
      LAYER M5 ;
        RECT  59.664 112.236 59.688 112.32 ;
    END
  END n_lo_d[296]
  PIN n_lo_d[297]
    DIRECTION OUTPUT ;
    USE SIGNAL ;
    PORT
      LAYER M5 ;
        RECT  59.856 112.236 59.88 112.32 ;
    END
  END n_lo_d[297]
  PIN n_lo_d[298]
    DIRECTION OUTPUT ;
    USE SIGNAL ;
    PORT
      LAYER M5 ;
        RECT  60 112.236 60.024 112.32 ;
    END
  END n_lo_d[298]
  PIN n_lo_d[299]
    DIRECTION OUTPUT ;
    USE SIGNAL ;
    PORT
      LAYER M5 ;
        RECT  60.192 112.236 60.216 112.32 ;
    END
  END n_lo_d[299]
  PIN n_lo_d[29]
    DIRECTION OUTPUT ;
    USE SIGNAL ;
    PORT
      LAYER M5 ;
        RECT  11.616 112.236 11.64 112.32 ;
    END
  END n_lo_d[29]
  PIN n_lo_d[2]
    DIRECTION OUTPUT ;
    USE SIGNAL ;
    PORT
      LAYER M5 ;
        RECT  6.864 112.236 6.888 112.32 ;
    END
  END n_lo_d[2]
  PIN n_lo_d[300]
    DIRECTION OUTPUT ;
    USE SIGNAL ;
    PORT
      LAYER M5 ;
        RECT  60.384 112.236 60.408 112.32 ;
    END
  END n_lo_d[300]
  PIN n_lo_d[301]
    DIRECTION OUTPUT ;
    USE SIGNAL ;
    PORT
      LAYER M5 ;
        RECT  60.576 112.236 60.6 112.32 ;
    END
  END n_lo_d[301]
  PIN n_lo_d[302]
    DIRECTION OUTPUT ;
    USE SIGNAL ;
    PORT
      LAYER M5 ;
        RECT  60.72 112.236 60.744 112.32 ;
    END
  END n_lo_d[302]
  PIN n_lo_d[303]
    DIRECTION OUTPUT ;
    USE SIGNAL ;
    PORT
      LAYER M5 ;
        RECT  60.912 112.236 60.936 112.32 ;
    END
  END n_lo_d[303]
  PIN n_lo_d[304]
    DIRECTION OUTPUT ;
    USE SIGNAL ;
    PORT
      LAYER M5 ;
        RECT  61.104 112.236 61.128 112.32 ;
    END
  END n_lo_d[304]
  PIN n_lo_d[305]
    DIRECTION OUTPUT ;
    USE SIGNAL ;
    PORT
      LAYER M5 ;
        RECT  61.296 112.236 61.32 112.32 ;
    END
  END n_lo_d[305]
  PIN n_lo_d[306]
    DIRECTION OUTPUT ;
    USE SIGNAL ;
    PORT
      LAYER M5 ;
        RECT  61.44 112.236 61.464 112.32 ;
    END
  END n_lo_d[306]
  PIN n_lo_d[307]
    DIRECTION OUTPUT ;
    USE SIGNAL ;
    PORT
      LAYER M5 ;
        RECT  61.632 112.236 61.656 112.32 ;
    END
  END n_lo_d[307]
  PIN n_lo_d[308]
    DIRECTION OUTPUT ;
    USE SIGNAL ;
    PORT
      LAYER M5 ;
        RECT  61.824 112.236 61.848 112.32 ;
    END
  END n_lo_d[308]
  PIN n_lo_d[309]
    DIRECTION OUTPUT ;
    USE SIGNAL ;
    PORT
      LAYER M5 ;
        RECT  62.016 112.236 62.04 112.32 ;
    END
  END n_lo_d[309]
  PIN n_lo_d[30]
    DIRECTION OUTPUT ;
    USE SIGNAL ;
    PORT
      LAYER M5 ;
        RECT  11.808 112.236 11.832 112.32 ;
    END
  END n_lo_d[30]
  PIN n_lo_d[310]
    DIRECTION OUTPUT ;
    USE SIGNAL ;
    PORT
      LAYER M5 ;
        RECT  62.16 112.236 62.184 112.32 ;
    END
  END n_lo_d[310]
  PIN n_lo_d[311]
    DIRECTION OUTPUT ;
    USE SIGNAL ;
    PORT
      LAYER M5 ;
        RECT  62.256 112.236 62.28 112.32 ;
    END
  END n_lo_d[311]
  PIN n_lo_d[312]
    DIRECTION OUTPUT ;
    USE SIGNAL ;
    PORT
      LAYER M5 ;
        RECT  62.304 112.236 62.328 112.32 ;
    END
  END n_lo_d[312]
  PIN n_lo_d[313]
    DIRECTION OUTPUT ;
    USE SIGNAL ;
    PORT
      LAYER M5 ;
        RECT  62.352 112.236 62.376 112.32 ;
    END
  END n_lo_d[313]
  PIN n_lo_d[314]
    DIRECTION OUTPUT ;
    USE SIGNAL ;
    PORT
      LAYER M5 ;
        RECT  62.928 112.236 62.952 112.32 ;
    END
  END n_lo_d[314]
  PIN n_lo_d[315]
    DIRECTION OUTPUT ;
    USE SIGNAL ;
    PORT
      LAYER M5 ;
        RECT  63.072 112.236 63.096 112.32 ;
    END
  END n_lo_d[315]
  PIN n_lo_d[316]
    DIRECTION OUTPUT ;
    USE SIGNAL ;
    PORT
      LAYER M5 ;
        RECT  63.264 112.236 63.288 112.32 ;
    END
  END n_lo_d[316]
  PIN n_lo_d[317]
    DIRECTION OUTPUT ;
    USE SIGNAL ;
    PORT
      LAYER M5 ;
        RECT  63.456 112.236 63.48 112.32 ;
    END
  END n_lo_d[317]
  PIN n_lo_d[318]
    DIRECTION OUTPUT ;
    USE SIGNAL ;
    PORT
      LAYER M5 ;
        RECT  63.6 112.236 63.624 112.32 ;
    END
  END n_lo_d[318]
  PIN n_lo_d[319]
    DIRECTION OUTPUT ;
    USE SIGNAL ;
    PORT
      LAYER M5 ;
        RECT  63.792 112.236 63.816 112.32 ;
    END
  END n_lo_d[319]
  PIN n_lo_d[31]
    DIRECTION OUTPUT ;
    USE SIGNAL ;
    PORT
      LAYER M5 ;
        RECT  12 112.236 12.024 112.32 ;
    END
  END n_lo_d[31]
  PIN n_lo_d[320]
    DIRECTION OUTPUT ;
    USE SIGNAL ;
    PORT
      LAYER M5 ;
        RECT  63.984 112.236 64.008 112.32 ;
    END
  END n_lo_d[320]
  PIN n_lo_d[321]
    DIRECTION OUTPUT ;
    USE SIGNAL ;
    PORT
      LAYER M5 ;
        RECT  64.176 112.236 64.2 112.32 ;
    END
  END n_lo_d[321]
  PIN n_lo_d[322]
    DIRECTION OUTPUT ;
    USE SIGNAL ;
    PORT
      LAYER M5 ;
        RECT  64.32 112.236 64.344 112.32 ;
    END
  END n_lo_d[322]
  PIN n_lo_d[323]
    DIRECTION OUTPUT ;
    USE SIGNAL ;
    PORT
      LAYER M5 ;
        RECT  64.512 112.236 64.536 112.32 ;
    END
  END n_lo_d[323]
  PIN n_lo_d[324]
    DIRECTION OUTPUT ;
    USE SIGNAL ;
    PORT
      LAYER M5 ;
        RECT  64.704 112.236 64.728 112.32 ;
    END
  END n_lo_d[324]
  PIN n_lo_d[325]
    DIRECTION OUTPUT ;
    USE SIGNAL ;
    PORT
      LAYER M5 ;
        RECT  64.896 112.236 64.92 112.32 ;
    END
  END n_lo_d[325]
  PIN n_lo_d[326]
    DIRECTION OUTPUT ;
    USE SIGNAL ;
    PORT
      LAYER M5 ;
        RECT  65.04 112.236 65.064 112.32 ;
    END
  END n_lo_d[326]
  PIN n_lo_d[327]
    DIRECTION OUTPUT ;
    USE SIGNAL ;
    PORT
      LAYER M5 ;
        RECT  65.232 112.236 65.256 112.32 ;
    END
  END n_lo_d[327]
  PIN n_lo_d[328]
    DIRECTION OUTPUT ;
    USE SIGNAL ;
    PORT
      LAYER M5 ;
        RECT  65.424 112.236 65.448 112.32 ;
    END
  END n_lo_d[328]
  PIN n_lo_d[329]
    DIRECTION OUTPUT ;
    USE SIGNAL ;
    PORT
      LAYER M5 ;
        RECT  65.616 112.236 65.64 112.32 ;
    END
  END n_lo_d[329]
  PIN n_lo_d[32]
    DIRECTION OUTPUT ;
    USE SIGNAL ;
    PORT
      LAYER M5 ;
        RECT  12.144 112.236 12.168 112.32 ;
    END
  END n_lo_d[32]
  PIN n_lo_d[330]
    DIRECTION OUTPUT ;
    USE SIGNAL ;
    PORT
      LAYER M5 ;
        RECT  65.76 112.236 65.784 112.32 ;
    END
  END n_lo_d[330]
  PIN n_lo_d[331]
    DIRECTION OUTPUT ;
    USE SIGNAL ;
    PORT
      LAYER M5 ;
        RECT  65.952 112.236 65.976 112.32 ;
    END
  END n_lo_d[331]
  PIN n_lo_d[332]
    DIRECTION OUTPUT ;
    USE SIGNAL ;
    PORT
      LAYER M5 ;
        RECT  66.144 112.236 66.168 112.32 ;
    END
  END n_lo_d[332]
  PIN n_lo_d[333]
    DIRECTION OUTPUT ;
    USE SIGNAL ;
    PORT
      LAYER M5 ;
        RECT  66.336 112.236 66.36 112.32 ;
    END
  END n_lo_d[333]
  PIN n_lo_d[334]
    DIRECTION OUTPUT ;
    USE SIGNAL ;
    PORT
      LAYER M5 ;
        RECT  66.48 112.236 66.504 112.32 ;
    END
  END n_lo_d[334]
  PIN n_lo_d[335]
    DIRECTION OUTPUT ;
    USE SIGNAL ;
    PORT
      LAYER M5 ;
        RECT  66.576 112.236 66.6 112.32 ;
    END
  END n_lo_d[335]
  PIN n_lo_d[336]
    DIRECTION OUTPUT ;
    USE SIGNAL ;
    PORT
      LAYER M5 ;
        RECT  66.624 112.236 66.648 112.32 ;
    END
  END n_lo_d[336]
  PIN n_lo_d[337]
    DIRECTION OUTPUT ;
    USE SIGNAL ;
    PORT
      LAYER M5 ;
        RECT  66.672 112.236 66.696 112.32 ;
    END
  END n_lo_d[337]
  PIN n_lo_d[338]
    DIRECTION OUTPUT ;
    USE SIGNAL ;
    PORT
      LAYER M5 ;
        RECT  67.248 112.236 67.272 112.32 ;
    END
  END n_lo_d[338]
  PIN n_lo_d[339]
    DIRECTION OUTPUT ;
    USE SIGNAL ;
    PORT
      LAYER M5 ;
        RECT  67.392 112.236 67.416 112.32 ;
    END
  END n_lo_d[339]
  PIN n_lo_d[33]
    DIRECTION OUTPUT ;
    USE SIGNAL ;
    PORT
      LAYER M5 ;
        RECT  12.336 112.236 12.36 112.32 ;
    END
  END n_lo_d[33]
  PIN n_lo_d[340]
    DIRECTION OUTPUT ;
    USE SIGNAL ;
    PORT
      LAYER M5 ;
        RECT  67.584 112.236 67.608 112.32 ;
    END
  END n_lo_d[340]
  PIN n_lo_d[341]
    DIRECTION OUTPUT ;
    USE SIGNAL ;
    PORT
      LAYER M5 ;
        RECT  67.776 112.236 67.8 112.32 ;
    END
  END n_lo_d[341]
  PIN n_lo_d[342]
    DIRECTION OUTPUT ;
    USE SIGNAL ;
    PORT
      LAYER M5 ;
        RECT  67.92 112.236 67.944 112.32 ;
    END
  END n_lo_d[342]
  PIN n_lo_d[343]
    DIRECTION OUTPUT ;
    USE SIGNAL ;
    PORT
      LAYER M5 ;
        RECT  68.112 112.236 68.136 112.32 ;
    END
  END n_lo_d[343]
  PIN n_lo_d[344]
    DIRECTION OUTPUT ;
    USE SIGNAL ;
    PORT
      LAYER M5 ;
        RECT  68.304 112.236 68.328 112.32 ;
    END
  END n_lo_d[344]
  PIN n_lo_d[345]
    DIRECTION OUTPUT ;
    USE SIGNAL ;
    PORT
      LAYER M5 ;
        RECT  68.496 112.236 68.52 112.32 ;
    END
  END n_lo_d[345]
  PIN n_lo_d[346]
    DIRECTION OUTPUT ;
    USE SIGNAL ;
    PORT
      LAYER M5 ;
        RECT  68.64 112.236 68.664 112.32 ;
    END
  END n_lo_d[346]
  PIN n_lo_d[347]
    DIRECTION OUTPUT ;
    USE SIGNAL ;
    PORT
      LAYER M5 ;
        RECT  68.832 112.236 68.856 112.32 ;
    END
  END n_lo_d[347]
  PIN n_lo_d[348]
    DIRECTION OUTPUT ;
    USE SIGNAL ;
    PORT
      LAYER M5 ;
        RECT  69.024 112.236 69.048 112.32 ;
    END
  END n_lo_d[348]
  PIN n_lo_d[349]
    DIRECTION OUTPUT ;
    USE SIGNAL ;
    PORT
      LAYER M5 ;
        RECT  69.168 112.236 69.192 112.32 ;
    END
  END n_lo_d[349]
  PIN n_lo_d[34]
    DIRECTION OUTPUT ;
    USE SIGNAL ;
    PORT
      LAYER M5 ;
        RECT  12.528 112.236 12.552 112.32 ;
    END
  END n_lo_d[34]
  PIN n_lo_d[350]
    DIRECTION OUTPUT ;
    USE SIGNAL ;
    PORT
      LAYER M5 ;
        RECT  69.36 112.236 69.384 112.32 ;
    END
  END n_lo_d[350]
  PIN n_lo_d[351]
    DIRECTION OUTPUT ;
    USE SIGNAL ;
    PORT
      LAYER M5 ;
        RECT  69.552 112.236 69.576 112.32 ;
    END
  END n_lo_d[351]
  PIN n_lo_d[352]
    DIRECTION OUTPUT ;
    USE SIGNAL ;
    PORT
      LAYER M5 ;
        RECT  69.744 112.236 69.768 112.32 ;
    END
  END n_lo_d[352]
  PIN n_lo_d[353]
    DIRECTION OUTPUT ;
    USE SIGNAL ;
    PORT
      LAYER M5 ;
        RECT  69.888 112.236 69.912 112.32 ;
    END
  END n_lo_d[353]
  PIN n_lo_d[354]
    DIRECTION OUTPUT ;
    USE SIGNAL ;
    PORT
      LAYER M5 ;
        RECT  70.08 112.236 70.104 112.32 ;
    END
  END n_lo_d[354]
  PIN n_lo_d[355]
    DIRECTION OUTPUT ;
    USE SIGNAL ;
    PORT
      LAYER M5 ;
        RECT  70.272 112.236 70.296 112.32 ;
    END
  END n_lo_d[355]
  PIN n_lo_d[356]
    DIRECTION OUTPUT ;
    USE SIGNAL ;
    PORT
      LAYER M5 ;
        RECT  70.464 112.236 70.488 112.32 ;
    END
  END n_lo_d[356]
  PIN n_lo_d[357]
    DIRECTION OUTPUT ;
    USE SIGNAL ;
    PORT
      LAYER M5 ;
        RECT  70.608 112.236 70.632 112.32 ;
    END
  END n_lo_d[357]
  PIN n_lo_d[358]
    DIRECTION OUTPUT ;
    USE SIGNAL ;
    PORT
      LAYER M5 ;
        RECT  70.8 112.236 70.824 112.32 ;
    END
  END n_lo_d[358]
  PIN n_lo_d[359]
    DIRECTION OUTPUT ;
    USE SIGNAL ;
    PORT
      LAYER M5 ;
        RECT  70.896 112.236 70.92 112.32 ;
    END
  END n_lo_d[359]
  PIN n_lo_d[35]
    DIRECTION OUTPUT ;
    USE SIGNAL ;
    PORT
      LAYER M5 ;
        RECT  12.72 112.236 12.744 112.32 ;
    END
  END n_lo_d[35]
  PIN n_lo_d[360]
    DIRECTION OUTPUT ;
    USE SIGNAL ;
    PORT
      LAYER M5 ;
        RECT  70.944 112.236 70.968 112.32 ;
    END
  END n_lo_d[360]
  PIN n_lo_d[361]
    DIRECTION OUTPUT ;
    USE SIGNAL ;
    PORT
      LAYER M5 ;
        RECT  70.992 112.236 71.016 112.32 ;
    END
  END n_lo_d[361]
  PIN n_lo_d[362]
    DIRECTION OUTPUT ;
    USE SIGNAL ;
    PORT
      LAYER M5 ;
        RECT  71.568 112.236 71.592 112.32 ;
    END
  END n_lo_d[362]
  PIN n_lo_d[363]
    DIRECTION OUTPUT ;
    USE SIGNAL ;
    PORT
      LAYER M5 ;
        RECT  71.712 112.236 71.736 112.32 ;
    END
  END n_lo_d[363]
  PIN n_lo_d[364]
    DIRECTION OUTPUT ;
    USE SIGNAL ;
    PORT
      LAYER M5 ;
        RECT  71.904 112.236 71.928 112.32 ;
    END
  END n_lo_d[364]
  PIN n_lo_d[365]
    DIRECTION OUTPUT ;
    USE SIGNAL ;
    PORT
      LAYER M5 ;
        RECT  72.048 112.236 72.072 112.32 ;
    END
  END n_lo_d[365]
  PIN n_lo_d[366]
    DIRECTION OUTPUT ;
    USE SIGNAL ;
    PORT
      LAYER M5 ;
        RECT  72.24 112.236 72.264 112.32 ;
    END
  END n_lo_d[366]
  PIN n_lo_d[367]
    DIRECTION OUTPUT ;
    USE SIGNAL ;
    PORT
      LAYER M5 ;
        RECT  72.432 112.236 72.456 112.32 ;
    END
  END n_lo_d[367]
  PIN n_lo_d[368]
    DIRECTION OUTPUT ;
    USE SIGNAL ;
    PORT
      LAYER M5 ;
        RECT  72.624 112.236 72.648 112.32 ;
    END
  END n_lo_d[368]
  PIN n_lo_d[369]
    DIRECTION OUTPUT ;
    USE SIGNAL ;
    PORT
      LAYER M5 ;
        RECT  72.768 112.236 72.792 112.32 ;
    END
  END n_lo_d[369]
  PIN n_lo_d[36]
    DIRECTION OUTPUT ;
    USE SIGNAL ;
    PORT
      LAYER M5 ;
        RECT  12.864 112.236 12.888 112.32 ;
    END
  END n_lo_d[36]
  PIN n_lo_d[370]
    DIRECTION OUTPUT ;
    USE SIGNAL ;
    PORT
      LAYER M5 ;
        RECT  72.96 112.236 72.984 112.32 ;
    END
  END n_lo_d[370]
  PIN n_lo_d[371]
    DIRECTION OUTPUT ;
    USE SIGNAL ;
    PORT
      LAYER M5 ;
        RECT  73.152 112.236 73.176 112.32 ;
    END
  END n_lo_d[371]
  PIN n_lo_d[372]
    DIRECTION OUTPUT ;
    USE SIGNAL ;
    PORT
      LAYER M5 ;
        RECT  73.344 112.236 73.368 112.32 ;
    END
  END n_lo_d[372]
  PIN n_lo_d[373]
    DIRECTION OUTPUT ;
    USE SIGNAL ;
    PORT
      LAYER M5 ;
        RECT  73.488 112.236 73.512 112.32 ;
    END
  END n_lo_d[373]
  PIN n_lo_d[374]
    DIRECTION OUTPUT ;
    USE SIGNAL ;
    PORT
      LAYER M5 ;
        RECT  73.68 112.236 73.704 112.32 ;
    END
  END n_lo_d[374]
  PIN n_lo_d[375]
    DIRECTION OUTPUT ;
    USE SIGNAL ;
    PORT
      LAYER M5 ;
        RECT  73.872 112.236 73.896 112.32 ;
    END
  END n_lo_d[375]
  PIN n_lo_d[376]
    DIRECTION OUTPUT ;
    USE SIGNAL ;
    PORT
      LAYER M5 ;
        RECT  74.064 112.236 74.088 112.32 ;
    END
  END n_lo_d[376]
  PIN n_lo_d[377]
    DIRECTION OUTPUT ;
    USE SIGNAL ;
    PORT
      LAYER M5 ;
        RECT  74.208 112.236 74.232 112.32 ;
    END
  END n_lo_d[377]
  PIN n_lo_d[378]
    DIRECTION OUTPUT ;
    USE SIGNAL ;
    PORT
      LAYER M5 ;
        RECT  74.4 112.236 74.424 112.32 ;
    END
  END n_lo_d[378]
  PIN n_lo_d[379]
    DIRECTION OUTPUT ;
    USE SIGNAL ;
    PORT
      LAYER M5 ;
        RECT  74.592 112.236 74.616 112.32 ;
    END
  END n_lo_d[379]
  PIN n_lo_d[37]
    DIRECTION OUTPUT ;
    USE SIGNAL ;
    PORT
      LAYER M5 ;
        RECT  13.056 112.236 13.08 112.32 ;
    END
  END n_lo_d[37]
  PIN n_lo_d[380]
    DIRECTION OUTPUT ;
    USE SIGNAL ;
    PORT
      LAYER M5 ;
        RECT  74.784 112.236 74.808 112.32 ;
    END
  END n_lo_d[380]
  PIN n_lo_d[381]
    DIRECTION OUTPUT ;
    USE SIGNAL ;
    PORT
      LAYER M5 ;
        RECT  74.928 112.236 74.952 112.32 ;
    END
  END n_lo_d[381]
  PIN n_lo_d[382]
    DIRECTION OUTPUT ;
    USE SIGNAL ;
    PORT
      LAYER M5 ;
        RECT  75.12 112.236 75.144 112.32 ;
    END
  END n_lo_d[382]
  PIN n_lo_d[383]
    DIRECTION OUTPUT ;
    USE SIGNAL ;
    PORT
      LAYER M5 ;
        RECT  75.216 112.236 75.24 112.32 ;
    END
  END n_lo_d[383]
  PIN n_lo_d[384]
    DIRECTION OUTPUT ;
    USE SIGNAL ;
    PORT
      LAYER M5 ;
        RECT  75.264 112.236 75.288 112.32 ;
    END
  END n_lo_d[384]
  PIN n_lo_d[385]
    DIRECTION OUTPUT ;
    USE SIGNAL ;
    PORT
      LAYER M5 ;
        RECT  75.312 112.236 75.336 112.32 ;
    END
  END n_lo_d[385]
  PIN n_lo_d[386]
    DIRECTION OUTPUT ;
    USE SIGNAL ;
    PORT
      LAYER M5 ;
        RECT  75.888 112.236 75.912 112.32 ;
    END
  END n_lo_d[386]
  PIN n_lo_d[387]
    DIRECTION OUTPUT ;
    USE SIGNAL ;
    PORT
      LAYER M5 ;
        RECT  76.032 112.236 76.056 112.32 ;
    END
  END n_lo_d[387]
  PIN n_lo_d[388]
    DIRECTION OUTPUT ;
    USE SIGNAL ;
    PORT
      LAYER M5 ;
        RECT  76.224 112.236 76.248 112.32 ;
    END
  END n_lo_d[388]
  PIN n_lo_d[389]
    DIRECTION OUTPUT ;
    USE SIGNAL ;
    PORT
      LAYER M5 ;
        RECT  76.368 112.236 76.392 112.32 ;
    END
  END n_lo_d[389]
  PIN n_lo_d[38]
    DIRECTION OUTPUT ;
    USE SIGNAL ;
    PORT
      LAYER M5 ;
        RECT  13.248 112.236 13.272 112.32 ;
    END
  END n_lo_d[38]
  PIN n_lo_d[390]
    DIRECTION OUTPUT ;
    USE SIGNAL ;
    PORT
      LAYER M5 ;
        RECT  76.56 112.236 76.584 112.32 ;
    END
  END n_lo_d[390]
  PIN n_lo_d[391]
    DIRECTION OUTPUT ;
    USE SIGNAL ;
    PORT
      LAYER M5 ;
        RECT  76.752 112.236 76.776 112.32 ;
    END
  END n_lo_d[391]
  PIN n_lo_d[392]
    DIRECTION OUTPUT ;
    USE SIGNAL ;
    PORT
      LAYER M5 ;
        RECT  76.944 112.236 76.968 112.32 ;
    END
  END n_lo_d[392]
  PIN n_lo_d[393]
    DIRECTION OUTPUT ;
    USE SIGNAL ;
    PORT
      LAYER M5 ;
        RECT  77.088 112.236 77.112 112.32 ;
    END
  END n_lo_d[393]
  PIN n_lo_d[394]
    DIRECTION OUTPUT ;
    USE SIGNAL ;
    PORT
      LAYER M5 ;
        RECT  77.28 112.236 77.304 112.32 ;
    END
  END n_lo_d[394]
  PIN n_lo_d[395]
    DIRECTION OUTPUT ;
    USE SIGNAL ;
    PORT
      LAYER M5 ;
        RECT  77.472 112.236 77.496 112.32 ;
    END
  END n_lo_d[395]
  PIN n_lo_d[396]
    DIRECTION OUTPUT ;
    USE SIGNAL ;
    PORT
      LAYER M5 ;
        RECT  77.664 112.236 77.688 112.32 ;
    END
  END n_lo_d[396]
  PIN n_lo_d[397]
    DIRECTION OUTPUT ;
    USE SIGNAL ;
    PORT
      LAYER M5 ;
        RECT  77.808 112.236 77.832 112.32 ;
    END
  END n_lo_d[397]
  PIN n_lo_d[398]
    DIRECTION OUTPUT ;
    USE SIGNAL ;
    PORT
      LAYER M5 ;
        RECT  78 112.236 78.024 112.32 ;
    END
  END n_lo_d[398]
  PIN n_lo_d[399]
    DIRECTION OUTPUT ;
    USE SIGNAL ;
    PORT
      LAYER M5 ;
        RECT  78.192 112.236 78.216 112.32 ;
    END
  END n_lo_d[399]
  PIN n_lo_d[39]
    DIRECTION OUTPUT ;
    USE SIGNAL ;
    PORT
      LAYER M5 ;
        RECT  13.44 112.236 13.464 112.32 ;
    END
  END n_lo_d[39]
  PIN n_lo_d[3]
    DIRECTION OUTPUT ;
    USE SIGNAL ;
    PORT
      LAYER M5 ;
        RECT  6.96 112.236 6.984 112.32 ;
    END
  END n_lo_d[3]
  PIN n_lo_d[400]
    DIRECTION OUTPUT ;
    USE SIGNAL ;
    PORT
      LAYER M5 ;
        RECT  78.384 112.236 78.408 112.32 ;
    END
  END n_lo_d[400]
  PIN n_lo_d[401]
    DIRECTION OUTPUT ;
    USE SIGNAL ;
    PORT
      LAYER M5 ;
        RECT  78.528 112.236 78.552 112.32 ;
    END
  END n_lo_d[401]
  PIN n_lo_d[402]
    DIRECTION OUTPUT ;
    USE SIGNAL ;
    PORT
      LAYER M5 ;
        RECT  78.72 112.236 78.744 112.32 ;
    END
  END n_lo_d[402]
  PIN n_lo_d[403]
    DIRECTION OUTPUT ;
    USE SIGNAL ;
    PORT
      LAYER M5 ;
        RECT  78.912 112.236 78.936 112.32 ;
    END
  END n_lo_d[403]
  PIN n_lo_d[404]
    DIRECTION OUTPUT ;
    USE SIGNAL ;
    PORT
      LAYER M5 ;
        RECT  79.104 112.236 79.128 112.32 ;
    END
  END n_lo_d[404]
  PIN n_lo_d[405]
    DIRECTION OUTPUT ;
    USE SIGNAL ;
    PORT
      LAYER M5 ;
        RECT  79.248 112.236 79.272 112.32 ;
    END
  END n_lo_d[405]
  PIN n_lo_d[406]
    DIRECTION OUTPUT ;
    USE SIGNAL ;
    PORT
      LAYER M5 ;
        RECT  79.44 112.236 79.464 112.32 ;
    END
  END n_lo_d[406]
  PIN n_lo_d[407]
    DIRECTION OUTPUT ;
    USE SIGNAL ;
    PORT
      LAYER M5 ;
        RECT  79.536 112.236 79.56 112.32 ;
    END
  END n_lo_d[407]
  PIN n_lo_d[408]
    DIRECTION OUTPUT ;
    USE SIGNAL ;
    PORT
      LAYER M5 ;
        RECT  79.584 112.236 79.608 112.32 ;
    END
  END n_lo_d[408]
  PIN n_lo_d[409]
    DIRECTION OUTPUT ;
    USE SIGNAL ;
    PORT
      LAYER M5 ;
        RECT  79.632 112.236 79.656 112.32 ;
    END
  END n_lo_d[409]
  PIN n_lo_d[40]
    DIRECTION OUTPUT ;
    USE SIGNAL ;
    PORT
      LAYER M5 ;
        RECT  13.584 112.236 13.608 112.32 ;
    END
  END n_lo_d[40]
  PIN n_lo_d[410]
    DIRECTION OUTPUT ;
    USE SIGNAL ;
    PORT
      LAYER M5 ;
        RECT  80.208 112.236 80.232 112.32 ;
    END
  END n_lo_d[410]
  PIN n_lo_d[411]
    DIRECTION OUTPUT ;
    USE SIGNAL ;
    PORT
      LAYER M5 ;
        RECT  80.352 112.236 80.376 112.32 ;
    END
  END n_lo_d[411]
  PIN n_lo_d[412]
    DIRECTION OUTPUT ;
    USE SIGNAL ;
    PORT
      LAYER M5 ;
        RECT  80.544 112.236 80.568 112.32 ;
    END
  END n_lo_d[412]
  PIN n_lo_d[413]
    DIRECTION OUTPUT ;
    USE SIGNAL ;
    PORT
      LAYER M5 ;
        RECT  80.688 112.236 80.712 112.32 ;
    END
  END n_lo_d[413]
  PIN n_lo_d[414]
    DIRECTION OUTPUT ;
    USE SIGNAL ;
    PORT
      LAYER M5 ;
        RECT  80.88 112.236 80.904 112.32 ;
    END
  END n_lo_d[414]
  PIN n_lo_d[415]
    DIRECTION OUTPUT ;
    USE SIGNAL ;
    PORT
      LAYER M5 ;
        RECT  81.072 112.236 81.096 112.32 ;
    END
  END n_lo_d[415]
  PIN n_lo_d[416]
    DIRECTION OUTPUT ;
    USE SIGNAL ;
    PORT
      LAYER M5 ;
        RECT  81.264 112.236 81.288 112.32 ;
    END
  END n_lo_d[416]
  PIN n_lo_d[417]
    DIRECTION OUTPUT ;
    USE SIGNAL ;
    PORT
      LAYER M5 ;
        RECT  81.408 112.236 81.432 112.32 ;
    END
  END n_lo_d[417]
  PIN n_lo_d[418]
    DIRECTION OUTPUT ;
    USE SIGNAL ;
    PORT
      LAYER M5 ;
        RECT  81.6 112.236 81.624 112.32 ;
    END
  END n_lo_d[418]
  PIN n_lo_d[419]
    DIRECTION OUTPUT ;
    USE SIGNAL ;
    PORT
      LAYER M5 ;
        RECT  81.792 112.236 81.816 112.32 ;
    END
  END n_lo_d[419]
  PIN n_lo_d[41]
    DIRECTION OUTPUT ;
    USE SIGNAL ;
    PORT
      LAYER M5 ;
        RECT  13.776 112.236 13.8 112.32 ;
    END
  END n_lo_d[41]
  PIN n_lo_d[420]
    DIRECTION OUTPUT ;
    USE SIGNAL ;
    PORT
      LAYER M5 ;
        RECT  81.984 112.236 82.008 112.32 ;
    END
  END n_lo_d[420]
  PIN n_lo_d[421]
    DIRECTION OUTPUT ;
    USE SIGNAL ;
    PORT
      LAYER M5 ;
        RECT  82.128 112.236 82.152 112.32 ;
    END
  END n_lo_d[421]
  PIN n_lo_d[422]
    DIRECTION OUTPUT ;
    USE SIGNAL ;
    PORT
      LAYER M5 ;
        RECT  82.32 112.236 82.344 112.32 ;
    END
  END n_lo_d[422]
  PIN n_lo_d[423]
    DIRECTION OUTPUT ;
    USE SIGNAL ;
    PORT
      LAYER M5 ;
        RECT  82.512 112.236 82.536 112.32 ;
    END
  END n_lo_d[423]
  PIN n_lo_d[424]
    DIRECTION OUTPUT ;
    USE SIGNAL ;
    PORT
      LAYER M5 ;
        RECT  82.704 112.236 82.728 112.32 ;
    END
  END n_lo_d[424]
  PIN n_lo_d[425]
    DIRECTION OUTPUT ;
    USE SIGNAL ;
    PORT
      LAYER M5 ;
        RECT  82.848 112.236 82.872 112.32 ;
    END
  END n_lo_d[425]
  PIN n_lo_d[426]
    DIRECTION OUTPUT ;
    USE SIGNAL ;
    PORT
      LAYER M5 ;
        RECT  83.04 112.236 83.064 112.32 ;
    END
  END n_lo_d[426]
  PIN n_lo_d[427]
    DIRECTION OUTPUT ;
    USE SIGNAL ;
    PORT
      LAYER M5 ;
        RECT  83.232 112.236 83.256 112.32 ;
    END
  END n_lo_d[427]
  PIN n_lo_d[428]
    DIRECTION OUTPUT ;
    USE SIGNAL ;
    PORT
      LAYER M5 ;
        RECT  83.424 112.236 83.448 112.32 ;
    END
  END n_lo_d[428]
  PIN n_lo_d[429]
    DIRECTION OUTPUT ;
    USE SIGNAL ;
    PORT
      LAYER M5 ;
        RECT  83.568 112.236 83.592 112.32 ;
    END
  END n_lo_d[429]
  PIN n_lo_d[42]
    DIRECTION OUTPUT ;
    USE SIGNAL ;
    PORT
      LAYER M5 ;
        RECT  13.968 112.236 13.992 112.32 ;
    END
  END n_lo_d[42]
  PIN n_lo_d[430]
    DIRECTION OUTPUT ;
    USE SIGNAL ;
    PORT
      LAYER M5 ;
        RECT  83.76 112.236 83.784 112.32 ;
    END
  END n_lo_d[430]
  PIN n_lo_d[431]
    DIRECTION OUTPUT ;
    USE SIGNAL ;
    PORT
      LAYER M5 ;
        RECT  83.856 112.236 83.88 112.32 ;
    END
  END n_lo_d[431]
  PIN n_lo_d[432]
    DIRECTION OUTPUT ;
    USE SIGNAL ;
    PORT
      LAYER M5 ;
        RECT  83.904 112.236 83.928 112.32 ;
    END
  END n_lo_d[432]
  PIN n_lo_d[433]
    DIRECTION OUTPUT ;
    USE SIGNAL ;
    PORT
      LAYER M5 ;
        RECT  83.952 112.236 83.976 112.32 ;
    END
  END n_lo_d[433]
  PIN n_lo_d[434]
    DIRECTION OUTPUT ;
    USE SIGNAL ;
    PORT
      LAYER M5 ;
        RECT  84.528 112.236 84.552 112.32 ;
    END
  END n_lo_d[434]
  PIN n_lo_d[435]
    DIRECTION OUTPUT ;
    USE SIGNAL ;
    PORT
      LAYER M5 ;
        RECT  84.672 112.236 84.696 112.32 ;
    END
  END n_lo_d[435]
  PIN n_lo_d[436]
    DIRECTION OUTPUT ;
    USE SIGNAL ;
    PORT
      LAYER M5 ;
        RECT  84.864 112.236 84.888 112.32 ;
    END
  END n_lo_d[436]
  PIN n_lo_d[437]
    DIRECTION OUTPUT ;
    USE SIGNAL ;
    PORT
      LAYER M5 ;
        RECT  85.008 112.236 85.032 112.32 ;
    END
  END n_lo_d[437]
  PIN n_lo_d[438]
    DIRECTION OUTPUT ;
    USE SIGNAL ;
    PORT
      LAYER M5 ;
        RECT  85.2 112.236 85.224 112.32 ;
    END
  END n_lo_d[438]
  PIN n_lo_d[439]
    DIRECTION OUTPUT ;
    USE SIGNAL ;
    PORT
      LAYER M5 ;
        RECT  85.392 112.236 85.416 112.32 ;
    END
  END n_lo_d[439]
  PIN n_lo_d[43]
    DIRECTION OUTPUT ;
    USE SIGNAL ;
    PORT
      LAYER M5 ;
        RECT  14.16 112.236 14.184 112.32 ;
    END
  END n_lo_d[43]
  PIN n_lo_d[440]
    DIRECTION OUTPUT ;
    USE SIGNAL ;
    PORT
      LAYER M5 ;
        RECT  85.584 112.236 85.608 112.32 ;
    END
  END n_lo_d[440]
  PIN n_lo_d[441]
    DIRECTION OUTPUT ;
    USE SIGNAL ;
    PORT
      LAYER M5 ;
        RECT  85.728 112.236 85.752 112.32 ;
    END
  END n_lo_d[441]
  PIN n_lo_d[442]
    DIRECTION OUTPUT ;
    USE SIGNAL ;
    PORT
      LAYER M5 ;
        RECT  85.92 112.236 85.944 112.32 ;
    END
  END n_lo_d[442]
  PIN n_lo_d[443]
    DIRECTION OUTPUT ;
    USE SIGNAL ;
    PORT
      LAYER M5 ;
        RECT  86.112 112.236 86.136 112.32 ;
    END
  END n_lo_d[443]
  PIN n_lo_d[444]
    DIRECTION OUTPUT ;
    USE SIGNAL ;
    PORT
      LAYER M5 ;
        RECT  86.304 112.236 86.328 112.32 ;
    END
  END n_lo_d[444]
  PIN n_lo_d[445]
    DIRECTION OUTPUT ;
    USE SIGNAL ;
    PORT
      LAYER M5 ;
        RECT  86.448 112.236 86.472 112.32 ;
    END
  END n_lo_d[445]
  PIN n_lo_d[446]
    DIRECTION OUTPUT ;
    USE SIGNAL ;
    PORT
      LAYER M5 ;
        RECT  86.64 112.236 86.664 112.32 ;
    END
  END n_lo_d[446]
  PIN n_lo_d[447]
    DIRECTION OUTPUT ;
    USE SIGNAL ;
    PORT
      LAYER M5 ;
        RECT  86.832 112.236 86.856 112.32 ;
    END
  END n_lo_d[447]
  PIN n_lo_d[448]
    DIRECTION OUTPUT ;
    USE SIGNAL ;
    PORT
      LAYER M5 ;
        RECT  87.024 112.236 87.048 112.32 ;
    END
  END n_lo_d[448]
  PIN n_lo_d[449]
    DIRECTION OUTPUT ;
    USE SIGNAL ;
    PORT
      LAYER M5 ;
        RECT  87.168 112.236 87.192 112.32 ;
    END
  END n_lo_d[449]
  PIN n_lo_d[44]
    DIRECTION OUTPUT ;
    USE SIGNAL ;
    PORT
      LAYER M5 ;
        RECT  14.304 112.236 14.328 112.32 ;
    END
  END n_lo_d[44]
  PIN n_lo_d[450]
    DIRECTION OUTPUT ;
    USE SIGNAL ;
    PORT
      LAYER M5 ;
        RECT  87.36 112.236 87.384 112.32 ;
    END
  END n_lo_d[450]
  PIN n_lo_d[451]
    DIRECTION OUTPUT ;
    USE SIGNAL ;
    PORT
      LAYER M5 ;
        RECT  87.552 112.236 87.576 112.32 ;
    END
  END n_lo_d[451]
  PIN n_lo_d[452]
    DIRECTION OUTPUT ;
    USE SIGNAL ;
    PORT
      LAYER M5 ;
        RECT  87.744 112.236 87.768 112.32 ;
    END
  END n_lo_d[452]
  PIN n_lo_d[453]
    DIRECTION OUTPUT ;
    USE SIGNAL ;
    PORT
      LAYER M5 ;
        RECT  87.888 112.236 87.912 112.32 ;
    END
  END n_lo_d[453]
  PIN n_lo_d[454]
    DIRECTION OUTPUT ;
    USE SIGNAL ;
    PORT
      LAYER M5 ;
        RECT  88.08 112.236 88.104 112.32 ;
    END
  END n_lo_d[454]
  PIN n_lo_d[455]
    DIRECTION OUTPUT ;
    USE SIGNAL ;
    PORT
      LAYER M5 ;
        RECT  88.176 112.236 88.2 112.32 ;
    END
  END n_lo_d[455]
  PIN n_lo_d[456]
    DIRECTION OUTPUT ;
    USE SIGNAL ;
    PORT
      LAYER M5 ;
        RECT  88.224 112.236 88.248 112.32 ;
    END
  END n_lo_d[456]
  PIN n_lo_d[457]
    DIRECTION OUTPUT ;
    USE SIGNAL ;
    PORT
      LAYER M5 ;
        RECT  88.272 112.236 88.296 112.32 ;
    END
  END n_lo_d[457]
  PIN n_lo_d[458]
    DIRECTION OUTPUT ;
    USE SIGNAL ;
    PORT
      LAYER M5 ;
        RECT  88.848 112.236 88.872 112.32 ;
    END
  END n_lo_d[458]
  PIN n_lo_d[459]
    DIRECTION OUTPUT ;
    USE SIGNAL ;
    PORT
      LAYER M5 ;
        RECT  88.992 112.236 89.016 112.32 ;
    END
  END n_lo_d[459]
  PIN n_lo_d[45]
    DIRECTION OUTPUT ;
    USE SIGNAL ;
    PORT
      LAYER M5 ;
        RECT  14.496 112.236 14.52 112.32 ;
    END
  END n_lo_d[45]
  PIN n_lo_d[460]
    DIRECTION OUTPUT ;
    USE SIGNAL ;
    PORT
      LAYER M5 ;
        RECT  89.184 112.236 89.208 112.32 ;
    END
  END n_lo_d[460]
  PIN n_lo_d[461]
    DIRECTION OUTPUT ;
    USE SIGNAL ;
    PORT
      LAYER M5 ;
        RECT  89.328 112.236 89.352 112.32 ;
    END
  END n_lo_d[461]
  PIN n_lo_d[462]
    DIRECTION OUTPUT ;
    USE SIGNAL ;
    PORT
      LAYER M5 ;
        RECT  89.52 112.236 89.544 112.32 ;
    END
  END n_lo_d[462]
  PIN n_lo_d[463]
    DIRECTION OUTPUT ;
    USE SIGNAL ;
    PORT
      LAYER M5 ;
        RECT  89.712 112.236 89.736 112.32 ;
    END
  END n_lo_d[463]
  PIN n_lo_d[464]
    DIRECTION OUTPUT ;
    USE SIGNAL ;
    PORT
      LAYER M5 ;
        RECT  89.904 112.236 89.928 112.32 ;
    END
  END n_lo_d[464]
  PIN n_lo_d[465]
    DIRECTION OUTPUT ;
    USE SIGNAL ;
    PORT
      LAYER M5 ;
        RECT  90.048 112.236 90.072 112.32 ;
    END
  END n_lo_d[465]
  PIN n_lo_d[466]
    DIRECTION OUTPUT ;
    USE SIGNAL ;
    PORT
      LAYER M5 ;
        RECT  90.24 112.236 90.264 112.32 ;
    END
  END n_lo_d[466]
  PIN n_lo_d[467]
    DIRECTION OUTPUT ;
    USE SIGNAL ;
    PORT
      LAYER M5 ;
        RECT  90.432 112.236 90.456 112.32 ;
    END
  END n_lo_d[467]
  PIN n_lo_d[468]
    DIRECTION OUTPUT ;
    USE SIGNAL ;
    PORT
      LAYER M5 ;
        RECT  90.624 112.236 90.648 112.32 ;
    END
  END n_lo_d[468]
  PIN n_lo_d[469]
    DIRECTION OUTPUT ;
    USE SIGNAL ;
    PORT
      LAYER M5 ;
        RECT  90.768 112.236 90.792 112.32 ;
    END
  END n_lo_d[469]
  PIN n_lo_d[46]
    DIRECTION OUTPUT ;
    USE SIGNAL ;
    PORT
      LAYER M5 ;
        RECT  14.688 112.236 14.712 112.32 ;
    END
  END n_lo_d[46]
  PIN n_lo_d[470]
    DIRECTION OUTPUT ;
    USE SIGNAL ;
    PORT
      LAYER M5 ;
        RECT  90.96 112.236 90.984 112.32 ;
    END
  END n_lo_d[470]
  PIN n_lo_d[471]
    DIRECTION OUTPUT ;
    USE SIGNAL ;
    PORT
      LAYER M5 ;
        RECT  91.152 112.236 91.176 112.32 ;
    END
  END n_lo_d[471]
  PIN n_lo_d[472]
    DIRECTION OUTPUT ;
    USE SIGNAL ;
    PORT
      LAYER M5 ;
        RECT  91.344 112.236 91.368 112.32 ;
    END
  END n_lo_d[472]
  PIN n_lo_d[473]
    DIRECTION OUTPUT ;
    USE SIGNAL ;
    PORT
      LAYER M5 ;
        RECT  91.488 112.236 91.512 112.32 ;
    END
  END n_lo_d[473]
  PIN n_lo_d[474]
    DIRECTION OUTPUT ;
    USE SIGNAL ;
    PORT
      LAYER M5 ;
        RECT  91.68 112.236 91.704 112.32 ;
    END
  END n_lo_d[474]
  PIN n_lo_d[475]
    DIRECTION OUTPUT ;
    USE SIGNAL ;
    PORT
      LAYER M5 ;
        RECT  91.872 112.236 91.896 112.32 ;
    END
  END n_lo_d[475]
  PIN n_lo_d[476]
    DIRECTION OUTPUT ;
    USE SIGNAL ;
    PORT
      LAYER M5 ;
        RECT  92.064 112.236 92.088 112.32 ;
    END
  END n_lo_d[476]
  PIN n_lo_d[477]
    DIRECTION OUTPUT ;
    USE SIGNAL ;
    PORT
      LAYER M5 ;
        RECT  92.208 112.236 92.232 112.32 ;
    END
  END n_lo_d[477]
  PIN n_lo_d[478]
    DIRECTION OUTPUT ;
    USE SIGNAL ;
    PORT
      LAYER M5 ;
        RECT  92.4 112.236 92.424 112.32 ;
    END
  END n_lo_d[478]
  PIN n_lo_d[479]
    DIRECTION OUTPUT ;
    USE SIGNAL ;
    PORT
      LAYER M5 ;
        RECT  92.496 112.236 92.52 112.32 ;
    END
  END n_lo_d[479]
  PIN n_lo_d[47]
    DIRECTION OUTPUT ;
    USE SIGNAL ;
    PORT
      LAYER M5 ;
        RECT  14.832 112.236 14.856 112.32 ;
    END
  END n_lo_d[47]
  PIN n_lo_d[480]
    DIRECTION OUTPUT ;
    USE SIGNAL ;
    PORT
      LAYER M5 ;
        RECT  92.544 112.236 92.568 112.32 ;
    END
  END n_lo_d[480]
  PIN n_lo_d[481]
    DIRECTION OUTPUT ;
    USE SIGNAL ;
    PORT
      LAYER M5 ;
        RECT  92.592 112.236 92.616 112.32 ;
    END
  END n_lo_d[481]
  PIN n_lo_d[482]
    DIRECTION OUTPUT ;
    USE SIGNAL ;
    PORT
      LAYER M5 ;
        RECT  93.168 112.236 93.192 112.32 ;
    END
  END n_lo_d[482]
  PIN n_lo_d[483]
    DIRECTION OUTPUT ;
    USE SIGNAL ;
    PORT
      LAYER M5 ;
        RECT  93.312 112.236 93.336 112.32 ;
    END
  END n_lo_d[483]
  PIN n_lo_d[484]
    DIRECTION OUTPUT ;
    USE SIGNAL ;
    PORT
      LAYER M5 ;
        RECT  93.504 112.236 93.528 112.32 ;
    END
  END n_lo_d[484]
  PIN n_lo_d[485]
    DIRECTION OUTPUT ;
    USE SIGNAL ;
    PORT
      LAYER M5 ;
        RECT  93.648 112.236 93.672 112.32 ;
    END
  END n_lo_d[485]
  PIN n_lo_d[486]
    DIRECTION OUTPUT ;
    USE SIGNAL ;
    PORT
      LAYER M5 ;
        RECT  93.84 112.236 93.864 112.32 ;
    END
  END n_lo_d[486]
  PIN n_lo_d[487]
    DIRECTION OUTPUT ;
    USE SIGNAL ;
    PORT
      LAYER M5 ;
        RECT  94.032 112.236 94.056 112.32 ;
    END
  END n_lo_d[487]
  PIN n_lo_d[488]
    DIRECTION OUTPUT ;
    USE SIGNAL ;
    PORT
      LAYER M5 ;
        RECT  94.176 112.236 94.2 112.32 ;
    END
  END n_lo_d[488]
  PIN n_lo_d[489]
    DIRECTION OUTPUT ;
    USE SIGNAL ;
    PORT
      LAYER M5 ;
        RECT  94.368 112.236 94.392 112.32 ;
    END
  END n_lo_d[489]
  PIN n_lo_d[48]
    DIRECTION OUTPUT ;
    USE SIGNAL ;
    PORT
      LAYER M5 ;
        RECT  15.408 112.236 15.432 112.32 ;
    END
  END n_lo_d[48]
  PIN n_lo_d[490]
    DIRECTION OUTPUT ;
    USE SIGNAL ;
    PORT
      LAYER M5 ;
        RECT  94.56 112.236 94.584 112.32 ;
    END
  END n_lo_d[490]
  PIN n_lo_d[491]
    DIRECTION OUTPUT ;
    USE SIGNAL ;
    PORT
      LAYER M5 ;
        RECT  94.752 112.236 94.776 112.32 ;
    END
  END n_lo_d[491]
  PIN n_lo_d[492]
    DIRECTION OUTPUT ;
    USE SIGNAL ;
    PORT
      LAYER M5 ;
        RECT  94.896 112.236 94.92 112.32 ;
    END
  END n_lo_d[492]
  PIN n_lo_d[493]
    DIRECTION OUTPUT ;
    USE SIGNAL ;
    PORT
      LAYER M5 ;
        RECT  95.088 112.236 95.112 112.32 ;
    END
  END n_lo_d[493]
  PIN n_lo_d[494]
    DIRECTION OUTPUT ;
    USE SIGNAL ;
    PORT
      LAYER M5 ;
        RECT  95.28 112.236 95.304 112.32 ;
    END
  END n_lo_d[494]
  PIN n_lo_d[495]
    DIRECTION OUTPUT ;
    USE SIGNAL ;
    PORT
      LAYER M5 ;
        RECT  95.472 112.236 95.496 112.32 ;
    END
  END n_lo_d[495]
  PIN n_lo_d[496]
    DIRECTION OUTPUT ;
    USE SIGNAL ;
    PORT
      LAYER M5 ;
        RECT  95.616 112.236 95.64 112.32 ;
    END
  END n_lo_d[496]
  PIN n_lo_d[497]
    DIRECTION OUTPUT ;
    USE SIGNAL ;
    PORT
      LAYER M5 ;
        RECT  95.808 112.236 95.832 112.32 ;
    END
  END n_lo_d[497]
  PIN n_lo_d[498]
    DIRECTION OUTPUT ;
    USE SIGNAL ;
    PORT
      LAYER M5 ;
        RECT  96 112.236 96.024 112.32 ;
    END
  END n_lo_d[498]
  PIN n_lo_d[499]
    DIRECTION OUTPUT ;
    USE SIGNAL ;
    PORT
      LAYER M5 ;
        RECT  96.192 112.236 96.216 112.32 ;
    END
  END n_lo_d[499]
  PIN n_lo_d[49]
    DIRECTION OUTPUT ;
    USE SIGNAL ;
    PORT
      LAYER M5 ;
        RECT  15.456 112.236 15.48 112.32 ;
    END
  END n_lo_d[49]
  PIN n_lo_d[4]
    DIRECTION OUTPUT ;
    USE SIGNAL ;
    PORT
      LAYER M5 ;
        RECT  7.104 112.236 7.128 112.32 ;
    END
  END n_lo_d[4]
  PIN n_lo_d[500]
    DIRECTION OUTPUT ;
    USE SIGNAL ;
    PORT
      LAYER M5 ;
        RECT  96.336 112.236 96.36 112.32 ;
    END
  END n_lo_d[500]
  PIN n_lo_d[501]
    DIRECTION OUTPUT ;
    USE SIGNAL ;
    PORT
      LAYER M5 ;
        RECT  96.528 112.236 96.552 112.32 ;
    END
  END n_lo_d[501]
  PIN n_lo_d[502]
    DIRECTION OUTPUT ;
    USE SIGNAL ;
    PORT
      LAYER M5 ;
        RECT  96.72 112.236 96.744 112.32 ;
    END
  END n_lo_d[502]
  PIN n_lo_d[503]
    DIRECTION OUTPUT ;
    USE SIGNAL ;
    PORT
      LAYER M5 ;
        RECT  96.816 112.236 96.84 112.32 ;
    END
  END n_lo_d[503]
  PIN n_lo_d[504]
    DIRECTION OUTPUT ;
    USE SIGNAL ;
    PORT
      LAYER M5 ;
        RECT  96.864 112.236 96.888 112.32 ;
    END
  END n_lo_d[504]
  PIN n_lo_d[505]
    DIRECTION OUTPUT ;
    USE SIGNAL ;
    PORT
      LAYER M5 ;
        RECT  96.912 112.236 96.936 112.32 ;
    END
  END n_lo_d[505]
  PIN n_lo_d[506]
    DIRECTION OUTPUT ;
    USE SIGNAL ;
    PORT
      LAYER M5 ;
        RECT  97.488 112.236 97.512 112.32 ;
    END
  END n_lo_d[506]
  PIN n_lo_d[507]
    DIRECTION OUTPUT ;
    USE SIGNAL ;
    PORT
      LAYER M5 ;
        RECT  97.632 112.236 97.656 112.32 ;
    END
  END n_lo_d[507]
  PIN n_lo_d[508]
    DIRECTION OUTPUT ;
    USE SIGNAL ;
    PORT
      LAYER M5 ;
        RECT  97.776 112.236 97.8 112.32 ;
    END
  END n_lo_d[508]
  PIN n_lo_d[509]
    DIRECTION OUTPUT ;
    USE SIGNAL ;
    PORT
      LAYER M5 ;
        RECT  97.968 112.236 97.992 112.32 ;
    END
  END n_lo_d[509]
  PIN n_lo_d[50]
    DIRECTION OUTPUT ;
    USE SIGNAL ;
    PORT
      LAYER M5 ;
        RECT  15.504 112.236 15.528 112.32 ;
    END
  END n_lo_d[50]
  PIN n_lo_d[510]
    DIRECTION OUTPUT ;
    USE SIGNAL ;
    PORT
      LAYER M5 ;
        RECT  98.16 112.236 98.184 112.32 ;
    END
  END n_lo_d[510]
  PIN n_lo_d[511]
    DIRECTION OUTPUT ;
    USE SIGNAL ;
    PORT
      LAYER M5 ;
        RECT  98.352 112.236 98.376 112.32 ;
    END
  END n_lo_d[511]
  PIN n_lo_d[512]
    DIRECTION OUTPUT ;
    USE SIGNAL ;
    PORT
      LAYER M5 ;
        RECT  98.496 112.236 98.52 112.32 ;
    END
  END n_lo_d[512]
  PIN n_lo_d[513]
    DIRECTION OUTPUT ;
    USE SIGNAL ;
    PORT
      LAYER M5 ;
        RECT  98.688 112.236 98.712 112.32 ;
    END
  END n_lo_d[513]
  PIN n_lo_d[514]
    DIRECTION OUTPUT ;
    USE SIGNAL ;
    PORT
      LAYER M5 ;
        RECT  98.88 112.236 98.904 112.32 ;
    END
  END n_lo_d[514]
  PIN n_lo_d[515]
    DIRECTION OUTPUT ;
    USE SIGNAL ;
    PORT
      LAYER M5 ;
        RECT  99.072 112.236 99.096 112.32 ;
    END
  END n_lo_d[515]
  PIN n_lo_d[516]
    DIRECTION OUTPUT ;
    USE SIGNAL ;
    PORT
      LAYER M5 ;
        RECT  99.216 112.236 99.24 112.32 ;
    END
  END n_lo_d[516]
  PIN n_lo_d[517]
    DIRECTION OUTPUT ;
    USE SIGNAL ;
    PORT
      LAYER M5 ;
        RECT  99.408 112.236 99.432 112.32 ;
    END
  END n_lo_d[517]
  PIN n_lo_d[518]
    DIRECTION OUTPUT ;
    USE SIGNAL ;
    PORT
      LAYER M5 ;
        RECT  99.6 112.236 99.624 112.32 ;
    END
  END n_lo_d[518]
  PIN n_lo_d[519]
    DIRECTION OUTPUT ;
    USE SIGNAL ;
    PORT
      LAYER M5 ;
        RECT  99.792 112.236 99.816 112.32 ;
    END
  END n_lo_d[519]
  PIN n_lo_d[51]
    DIRECTION OUTPUT ;
    USE SIGNAL ;
    PORT
      LAYER M5 ;
        RECT  15.6 112.236 15.624 112.32 ;
    END
  END n_lo_d[51]
  PIN n_lo_d[520]
    DIRECTION OUTPUT ;
    USE SIGNAL ;
    PORT
      LAYER M5 ;
        RECT  99.936 112.236 99.96 112.32 ;
    END
  END n_lo_d[520]
  PIN n_lo_d[521]
    DIRECTION OUTPUT ;
    USE SIGNAL ;
    PORT
      LAYER M5 ;
        RECT  100.128 112.236 100.152 112.32 ;
    END
  END n_lo_d[521]
  PIN n_lo_d[522]
    DIRECTION OUTPUT ;
    USE SIGNAL ;
    PORT
      LAYER M5 ;
        RECT  100.32 112.236 100.344 112.32 ;
    END
  END n_lo_d[522]
  PIN n_lo_d[523]
    DIRECTION OUTPUT ;
    USE SIGNAL ;
    PORT
      LAYER M5 ;
        RECT  100.512 112.236 100.536 112.32 ;
    END
  END n_lo_d[523]
  PIN n_lo_d[524]
    DIRECTION OUTPUT ;
    USE SIGNAL ;
    PORT
      LAYER M5 ;
        RECT  100.656 112.236 100.68 112.32 ;
    END
  END n_lo_d[524]
  PIN n_lo_d[525]
    DIRECTION OUTPUT ;
    USE SIGNAL ;
    PORT
      LAYER M5 ;
        RECT  100.848 112.236 100.872 112.32 ;
    END
  END n_lo_d[525]
  PIN n_lo_d[526]
    DIRECTION OUTPUT ;
    USE SIGNAL ;
    PORT
      LAYER M5 ;
        RECT  101.04 112.236 101.064 112.32 ;
    END
  END n_lo_d[526]
  PIN n_lo_d[527]
    DIRECTION OUTPUT ;
    USE SIGNAL ;
    PORT
      LAYER M5 ;
        RECT  101.136 112.236 101.16 112.32 ;
    END
  END n_lo_d[527]
  PIN n_lo_d[528]
    DIRECTION OUTPUT ;
    USE SIGNAL ;
    PORT
      LAYER M5 ;
        RECT  101.184 112.236 101.208 112.32 ;
    END
  END n_lo_d[528]
  PIN n_lo_d[529]
    DIRECTION OUTPUT ;
    USE SIGNAL ;
    PORT
      LAYER M5 ;
        RECT  101.232 112.236 101.256 112.32 ;
    END
  END n_lo_d[529]
  PIN n_lo_d[52]
    DIRECTION OUTPUT ;
    USE SIGNAL ;
    PORT
      LAYER M5 ;
        RECT  15.744 112.236 15.768 112.32 ;
    END
  END n_lo_d[52]
  PIN n_lo_d[530]
    DIRECTION OUTPUT ;
    USE SIGNAL ;
    PORT
      LAYER M5 ;
        RECT  101.808 112.236 101.832 112.32 ;
    END
  END n_lo_d[530]
  PIN n_lo_d[531]
    DIRECTION OUTPUT ;
    USE SIGNAL ;
    PORT
      LAYER M5 ;
        RECT  101.952 112.236 101.976 112.32 ;
    END
  END n_lo_d[531]
  PIN n_lo_d[532]
    DIRECTION OUTPUT ;
    USE SIGNAL ;
    PORT
      LAYER M5 ;
        RECT  102.096 112.236 102.12 112.32 ;
    END
  END n_lo_d[532]
  PIN n_lo_d[533]
    DIRECTION OUTPUT ;
    USE SIGNAL ;
    PORT
      LAYER M5 ;
        RECT  102.288 112.236 102.312 112.32 ;
    END
  END n_lo_d[533]
  PIN n_lo_d[534]
    DIRECTION OUTPUT ;
    USE SIGNAL ;
    PORT
      LAYER M5 ;
        RECT  102.48 112.236 102.504 112.32 ;
    END
  END n_lo_d[534]
  PIN n_lo_d[535]
    DIRECTION OUTPUT ;
    USE SIGNAL ;
    PORT
      LAYER M5 ;
        RECT  102.672 112.236 102.696 112.32 ;
    END
  END n_lo_d[535]
  PIN n_lo_d[536]
    DIRECTION OUTPUT ;
    USE SIGNAL ;
    PORT
      LAYER M5 ;
        RECT  102.816 112.236 102.84 112.32 ;
    END
  END n_lo_d[536]
  PIN n_lo_d[537]
    DIRECTION OUTPUT ;
    USE SIGNAL ;
    PORT
      LAYER M5 ;
        RECT  103.008 112.236 103.032 112.32 ;
    END
  END n_lo_d[537]
  PIN n_lo_d[538]
    DIRECTION OUTPUT ;
    USE SIGNAL ;
    PORT
      LAYER M5 ;
        RECT  103.2 112.236 103.224 112.32 ;
    END
  END n_lo_d[538]
  PIN n_lo_d[539]
    DIRECTION OUTPUT ;
    USE SIGNAL ;
    PORT
      LAYER M5 ;
        RECT  103.392 112.236 103.416 112.32 ;
    END
  END n_lo_d[539]
  PIN n_lo_d[53]
    DIRECTION OUTPUT ;
    USE SIGNAL ;
    PORT
      LAYER M5 ;
        RECT  15.936 112.236 15.96 112.32 ;
    END
  END n_lo_d[53]
  PIN n_lo_d[540]
    DIRECTION OUTPUT ;
    USE SIGNAL ;
    PORT
      LAYER M5 ;
        RECT  103.536 112.236 103.56 112.32 ;
    END
  END n_lo_d[540]
  PIN n_lo_d[541]
    DIRECTION OUTPUT ;
    USE SIGNAL ;
    PORT
      LAYER M5 ;
        RECT  103.728 112.236 103.752 112.32 ;
    END
  END n_lo_d[541]
  PIN n_lo_d[542]
    DIRECTION OUTPUT ;
    USE SIGNAL ;
    PORT
      LAYER M5 ;
        RECT  103.92 112.236 103.944 112.32 ;
    END
  END n_lo_d[542]
  PIN n_lo_d[543]
    DIRECTION OUTPUT ;
    USE SIGNAL ;
    PORT
      LAYER M5 ;
        RECT  104.112 112.236 104.136 112.32 ;
    END
  END n_lo_d[543]
  PIN n_lo_d[544]
    DIRECTION OUTPUT ;
    USE SIGNAL ;
    PORT
      LAYER M5 ;
        RECT  104.256 112.236 104.28 112.32 ;
    END
  END n_lo_d[544]
  PIN n_lo_d[545]
    DIRECTION OUTPUT ;
    USE SIGNAL ;
    PORT
      LAYER M5 ;
        RECT  104.448 112.236 104.472 112.32 ;
    END
  END n_lo_d[545]
  PIN n_lo_d[546]
    DIRECTION OUTPUT ;
    USE SIGNAL ;
    PORT
      LAYER M5 ;
        RECT  104.64 112.236 104.664 112.32 ;
    END
  END n_lo_d[546]
  PIN n_lo_d[547]
    DIRECTION OUTPUT ;
    USE SIGNAL ;
    PORT
      LAYER M5 ;
        RECT  104.832 112.236 104.856 112.32 ;
    END
  END n_lo_d[547]
  PIN n_lo_d[548]
    DIRECTION OUTPUT ;
    USE SIGNAL ;
    PORT
      LAYER M5 ;
        RECT  104.976 112.236 105 112.32 ;
    END
  END n_lo_d[548]
  PIN n_lo_d[549]
    DIRECTION OUTPUT ;
    USE SIGNAL ;
    PORT
      LAYER M5 ;
        RECT  105.168 112.236 105.192 112.32 ;
    END
  END n_lo_d[549]
  PIN n_lo_d[54]
    DIRECTION OUTPUT ;
    USE SIGNAL ;
    PORT
      LAYER M5 ;
        RECT  16.128 112.236 16.152 112.32 ;
    END
  END n_lo_d[54]
  PIN n_lo_d[550]
    DIRECTION OUTPUT ;
    USE SIGNAL ;
    PORT
      LAYER M5 ;
        RECT  105.36 112.236 105.384 112.32 ;
    END
  END n_lo_d[550]
  PIN n_lo_d[551]
    DIRECTION OUTPUT ;
    USE SIGNAL ;
    PORT
      LAYER M5 ;
        RECT  105.456 112.236 105.48 112.32 ;
    END
  END n_lo_d[551]
  PIN n_lo_d[552]
    DIRECTION OUTPUT ;
    USE SIGNAL ;
    PORT
      LAYER M5 ;
        RECT  105.504 112.236 105.528 112.32 ;
    END
  END n_lo_d[552]
  PIN n_lo_d[55]
    DIRECTION OUTPUT ;
    USE SIGNAL ;
    PORT
      LAYER M5 ;
        RECT  16.32 112.236 16.344 112.32 ;
    END
  END n_lo_d[55]
  PIN n_lo_d[56]
    DIRECTION OUTPUT ;
    USE SIGNAL ;
    PORT
      LAYER M5 ;
        RECT  16.464 112.236 16.488 112.32 ;
    END
  END n_lo_d[56]
  PIN n_lo_d[57]
    DIRECTION OUTPUT ;
    USE SIGNAL ;
    PORT
      LAYER M5 ;
        RECT  16.656 112.236 16.68 112.32 ;
    END
  END n_lo_d[57]
  PIN n_lo_d[58]
    DIRECTION OUTPUT ;
    USE SIGNAL ;
    PORT
      LAYER M5 ;
        RECT  16.848 112.236 16.872 112.32 ;
    END
  END n_lo_d[58]
  PIN n_lo_d[59]
    DIRECTION OUTPUT ;
    USE SIGNAL ;
    PORT
      LAYER M5 ;
        RECT  17.04 112.236 17.064 112.32 ;
    END
  END n_lo_d[59]
  PIN n_lo_d[5]
    DIRECTION OUTPUT ;
    USE SIGNAL ;
    PORT
      LAYER M5 ;
        RECT  7.296 112.236 7.32 112.32 ;
    END
  END n_lo_d[5]
  PIN n_lo_d[60]
    DIRECTION OUTPUT ;
    USE SIGNAL ;
    PORT
      LAYER M5 ;
        RECT  17.184 112.236 17.208 112.32 ;
    END
  END n_lo_d[60]
  PIN n_lo_d[61]
    DIRECTION OUTPUT ;
    USE SIGNAL ;
    PORT
      LAYER M5 ;
        RECT  17.376 112.236 17.4 112.32 ;
    END
  END n_lo_d[61]
  PIN n_lo_d[62]
    DIRECTION OUTPUT ;
    USE SIGNAL ;
    PORT
      LAYER M5 ;
        RECT  17.568 112.236 17.592 112.32 ;
    END
  END n_lo_d[62]
  PIN n_lo_d[63]
    DIRECTION OUTPUT ;
    USE SIGNAL ;
    PORT
      LAYER M5 ;
        RECT  17.76 112.236 17.784 112.32 ;
    END
  END n_lo_d[63]
  PIN n_lo_d[64]
    DIRECTION OUTPUT ;
    USE SIGNAL ;
    PORT
      LAYER M5 ;
        RECT  17.904 112.236 17.928 112.32 ;
    END
  END n_lo_d[64]
  PIN n_lo_d[65]
    DIRECTION OUTPUT ;
    USE SIGNAL ;
    PORT
      LAYER M5 ;
        RECT  18.096 112.236 18.12 112.32 ;
    END
  END n_lo_d[65]
  PIN n_lo_d[66]
    DIRECTION OUTPUT ;
    USE SIGNAL ;
    PORT
      LAYER M5 ;
        RECT  18.288 112.236 18.312 112.32 ;
    END
  END n_lo_d[66]
  PIN n_lo_d[67]
    DIRECTION OUTPUT ;
    USE SIGNAL ;
    PORT
      LAYER M5 ;
        RECT  18.48 112.236 18.504 112.32 ;
    END
  END n_lo_d[67]
  PIN n_lo_d[68]
    DIRECTION OUTPUT ;
    USE SIGNAL ;
    PORT
      LAYER M5 ;
        RECT  18.624 112.236 18.648 112.32 ;
    END
  END n_lo_d[68]
  PIN n_lo_d[69]
    DIRECTION OUTPUT ;
    USE SIGNAL ;
    PORT
      LAYER M5 ;
        RECT  18.816 112.236 18.84 112.32 ;
    END
  END n_lo_d[69]
  PIN n_lo_d[6]
    DIRECTION OUTPUT ;
    USE SIGNAL ;
    PORT
      LAYER M5 ;
        RECT  7.488 112.236 7.512 112.32 ;
    END
  END n_lo_d[6]
  PIN n_lo_d[70]
    DIRECTION OUTPUT ;
    USE SIGNAL ;
    PORT
      LAYER M5 ;
        RECT  19.008 112.236 19.032 112.32 ;
    END
  END n_lo_d[70]
  PIN n_lo_d[71]
    DIRECTION OUTPUT ;
    USE SIGNAL ;
    PORT
      LAYER M5 ;
        RECT  19.152 112.236 19.176 112.32 ;
    END
  END n_lo_d[71]
  PIN n_lo_d[72]
    DIRECTION OUTPUT ;
    USE SIGNAL ;
    PORT
      LAYER M5 ;
        RECT  19.728 112.236 19.752 112.32 ;
    END
  END n_lo_d[72]
  PIN n_lo_d[73]
    DIRECTION OUTPUT ;
    USE SIGNAL ;
    PORT
      LAYER M5 ;
        RECT  19.776 112.236 19.8 112.32 ;
    END
  END n_lo_d[73]
  PIN n_lo_d[74]
    DIRECTION OUTPUT ;
    USE SIGNAL ;
    PORT
      LAYER M5 ;
        RECT  19.824 112.236 19.848 112.32 ;
    END
  END n_lo_d[74]
  PIN n_lo_d[75]
    DIRECTION OUTPUT ;
    USE SIGNAL ;
    PORT
      LAYER M5 ;
        RECT  19.872 112.236 19.896 112.32 ;
    END
  END n_lo_d[75]
  PIN n_lo_d[76]
    DIRECTION OUTPUT ;
    USE SIGNAL ;
    PORT
      LAYER M5 ;
        RECT  20.064 112.236 20.088 112.32 ;
    END
  END n_lo_d[76]
  PIN n_lo_d[77]
    DIRECTION OUTPUT ;
    USE SIGNAL ;
    PORT
      LAYER M5 ;
        RECT  20.256 112.236 20.28 112.32 ;
    END
  END n_lo_d[77]
  PIN n_lo_d[78]
    DIRECTION OUTPUT ;
    USE SIGNAL ;
    PORT
      LAYER M5 ;
        RECT  20.448 112.236 20.472 112.32 ;
    END
  END n_lo_d[78]
  PIN n_lo_d[79]
    DIRECTION OUTPUT ;
    USE SIGNAL ;
    PORT
      LAYER M5 ;
        RECT  20.592 112.236 20.616 112.32 ;
    END
  END n_lo_d[79]
  PIN n_lo_d[7]
    DIRECTION OUTPUT ;
    USE SIGNAL ;
    PORT
      LAYER M5 ;
        RECT  7.68 112.236 7.704 112.32 ;
    END
  END n_lo_d[7]
  PIN n_lo_d[80]
    DIRECTION OUTPUT ;
    USE SIGNAL ;
    PORT
      LAYER M5 ;
        RECT  20.784 112.236 20.808 112.32 ;
    END
  END n_lo_d[80]
  PIN n_lo_d[81]
    DIRECTION OUTPUT ;
    USE SIGNAL ;
    PORT
      LAYER M5 ;
        RECT  20.976 112.236 21 112.32 ;
    END
  END n_lo_d[81]
  PIN n_lo_d[82]
    DIRECTION OUTPUT ;
    USE SIGNAL ;
    PORT
      LAYER M5 ;
        RECT  21.168 112.236 21.192 112.32 ;
    END
  END n_lo_d[82]
  PIN n_lo_d[83]
    DIRECTION OUTPUT ;
    USE SIGNAL ;
    PORT
      LAYER M5 ;
        RECT  21.312 112.236 21.336 112.32 ;
    END
  END n_lo_d[83]
  PIN n_lo_d[84]
    DIRECTION OUTPUT ;
    USE SIGNAL ;
    PORT
      LAYER M5 ;
        RECT  21.504 112.236 21.528 112.32 ;
    END
  END n_lo_d[84]
  PIN n_lo_d[85]
    DIRECTION OUTPUT ;
    USE SIGNAL ;
    PORT
      LAYER M5 ;
        RECT  21.696 112.236 21.72 112.32 ;
    END
  END n_lo_d[85]
  PIN n_lo_d[86]
    DIRECTION OUTPUT ;
    USE SIGNAL ;
    PORT
      LAYER M5 ;
        RECT  21.888 112.236 21.912 112.32 ;
    END
  END n_lo_d[86]
  PIN n_lo_d[87]
    DIRECTION OUTPUT ;
    USE SIGNAL ;
    PORT
      LAYER M5 ;
        RECT  22.032 112.236 22.056 112.32 ;
    END
  END n_lo_d[87]
  PIN n_lo_d[88]
    DIRECTION OUTPUT ;
    USE SIGNAL ;
    PORT
      LAYER M5 ;
        RECT  22.224 112.236 22.248 112.32 ;
    END
  END n_lo_d[88]
  PIN n_lo_d[89]
    DIRECTION OUTPUT ;
    USE SIGNAL ;
    PORT
      LAYER M5 ;
        RECT  22.416 112.236 22.44 112.32 ;
    END
  END n_lo_d[89]
  PIN n_lo_d[8]
    DIRECTION OUTPUT ;
    USE SIGNAL ;
    PORT
      LAYER M5 ;
        RECT  7.824 112.236 7.848 112.32 ;
    END
  END n_lo_d[8]
  PIN n_lo_d[90]
    DIRECTION OUTPUT ;
    USE SIGNAL ;
    PORT
      LAYER M5 ;
        RECT  22.608 112.236 22.632 112.32 ;
    END
  END n_lo_d[90]
  PIN n_lo_d[91]
    DIRECTION OUTPUT ;
    USE SIGNAL ;
    PORT
      LAYER M5 ;
        RECT  22.752 112.236 22.776 112.32 ;
    END
  END n_lo_d[91]
  PIN n_lo_d[92]
    DIRECTION OUTPUT ;
    USE SIGNAL ;
    PORT
      LAYER M5 ;
        RECT  22.944 112.236 22.968 112.32 ;
    END
  END n_lo_d[92]
  PIN n_lo_d[93]
    DIRECTION OUTPUT ;
    USE SIGNAL ;
    PORT
      LAYER M5 ;
        RECT  23.136 112.236 23.16 112.32 ;
    END
  END n_lo_d[93]
  PIN n_lo_d[94]
    DIRECTION OUTPUT ;
    USE SIGNAL ;
    PORT
      LAYER M5 ;
        RECT  23.328 112.236 23.352 112.32 ;
    END
  END n_lo_d[94]
  PIN n_lo_d[95]
    DIRECTION OUTPUT ;
    USE SIGNAL ;
    PORT
      LAYER M5 ;
        RECT  23.472 112.236 23.496 112.32 ;
    END
  END n_lo_d[95]
  PIN n_lo_d[96]
    DIRECTION OUTPUT ;
    USE SIGNAL ;
    PORT
      LAYER M5 ;
        RECT  24.048 112.236 24.072 112.32 ;
    END
  END n_lo_d[96]
  PIN n_lo_d[97]
    DIRECTION OUTPUT ;
    USE SIGNAL ;
    PORT
      LAYER M5 ;
        RECT  24.096 112.236 24.12 112.32 ;
    END
  END n_lo_d[97]
  PIN n_lo_d[98]
    DIRECTION OUTPUT ;
    USE SIGNAL ;
    PORT
      LAYER M5 ;
        RECT  24.144 112.236 24.168 112.32 ;
    END
  END n_lo_d[98]
  PIN n_lo_d[99]
    DIRECTION OUTPUT ;
    USE SIGNAL ;
    PORT
      LAYER M5 ;
        RECT  24.192 112.236 24.216 112.32 ;
    END
  END n_lo_d[99]
  PIN n_lo_d[9]
    DIRECTION OUTPUT ;
    USE SIGNAL ;
    PORT
      LAYER M5 ;
        RECT  8.016 112.236 8.04 112.32 ;
    END
  END n_lo_d[9]
  PIN n_lo_r
    DIRECTION INPUT ;
    USE SIGNAL ;
    PORT
      LAYER M4 ;
        RECT  112.236 6.24 112.32 6.264 ;
    END
  END n_lo_r
  PIN n_lo_v
    DIRECTION OUTPUT ;
    USE SIGNAL ;
    PORT
      LAYER M5 ;
        RECT  6.192 112.236 6.216 112.32 ;
    END
  END n_lo_v
  PIN n_rxv
    DIRECTION OUTPUT ;
    USE SIGNAL ;
    PORT
      LAYER M5 ;
        RECT  106.128 112.236 106.152 112.32 ;
    END
  END n_rxv
  PIN rs_k
    DIRECTION INPUT ;
    USE SIGNAL ;
    PORT
      LAYER M5 ;
        RECT  4.32 0 4.344 0.084 ;
    END
  END rs_k
  PIN rs_n
    DIRECTION INPUT ;
    USE SIGNAL ;
    PORT
      LAYER M5 ;
        RECT  107.952 0 107.976 0.084 ;
    END
  END rs_n
  PIN VSS
    DIRECTION INOUT ;
    USE GROUND ;
    PORT
      LAYER M5 ;
        RECT  105.684 4.297 105.804 108.023 ;
        RECT  101.364 4.297 101.484 108.023 ;
        RECT  97.044 4.297 97.164 108.023 ;
        RECT  92.724 4.297 92.844 108.023 ;
        RECT  88.404 4.297 88.524 108.023 ;
        RECT  84.084 4.297 84.204 108.023 ;
        RECT  79.764 4.297 79.884 108.023 ;
        RECT  75.444 4.297 75.564 108.023 ;
        RECT  71.124 4.297 71.244 108.023 ;
        RECT  66.804 4.297 66.924 108.023 ;
        RECT  62.484 4.297 62.604 108.023 ;
        RECT  58.164 4.297 58.284 108.023 ;
        RECT  53.844 4.297 53.964 108.023 ;
        RECT  49.524 4.297 49.644 108.023 ;
        RECT  45.204 4.297 45.324 108.023 ;
        RECT  40.884 4.297 41.004 108.023 ;
        RECT  36.564 4.297 36.684 108.023 ;
        RECT  32.244 4.297 32.364 108.023 ;
        RECT  27.924 4.297 28.044 108.023 ;
        RECT  23.604 4.297 23.724 108.023 ;
        RECT  19.284 4.297 19.404 108.023 ;
        RECT  14.964 4.297 15.084 108.023 ;
        RECT  10.644 4.297 10.764 108.023 ;
        RECT  6.324 4.297 6.444 108.023 ;
    END
  END VSS
  PIN VDD
    DIRECTION INOUT ;
    USE POWER ;
    PORT
      LAYER M5 ;
        RECT  105.876 4.311 105.996 108.009 ;
        RECT  101.556 4.311 101.676 108.009 ;
        RECT  97.236 4.311 97.356 108.009 ;
        RECT  92.916 4.311 93.036 108.009 ;
        RECT  88.596 4.311 88.716 108.009 ;
        RECT  84.276 4.311 84.396 108.009 ;
        RECT  79.956 4.311 80.076 108.009 ;
        RECT  75.636 4.311 75.756 108.009 ;
        RECT  71.316 4.311 71.436 108.009 ;
        RECT  66.996 4.311 67.116 108.009 ;
        RECT  62.676 4.311 62.796 108.009 ;
        RECT  58.356 4.311 58.476 108.009 ;
        RECT  54.036 4.311 54.156 108.009 ;
        RECT  49.716 4.311 49.836 108.009 ;
        RECT  45.396 4.311 45.516 108.009 ;
        RECT  41.076 4.311 41.196 108.009 ;
        RECT  36.756 4.311 36.876 108.009 ;
        RECT  32.436 4.311 32.556 108.009 ;
        RECT  28.116 4.311 28.236 108.009 ;
        RECT  23.796 4.311 23.916 108.009 ;
        RECT  19.476 4.311 19.596 108.009 ;
        RECT  15.156 4.311 15.276 108.009 ;
        RECT  10.836 4.311 10.956 108.009 ;
        RECT  6.516 4.311 6.636 108.009 ;
    END
  END VDD
  OBS
    LAYER RVTN ;
     RECT  0 0 112.32 112.32 ;
    LAYER RVTP ;
     RECT  0 0 112.32 112.32 ;
    LAYER M1 ;
     RECT  0 0 112.32 112.32 ;
    LAYER M2 ;
     RECT  0 0 112.32 112.32 ;
    LAYER M3 ;
     RECT  0 0 112.32 112.32 ;
    LAYER M4 ;
     RECT  0 0 112.32 112.32 ;
    LAYER M5 ;
     RECT  0 0 112.32 112.32 ;
  END
END ot_s81_mu72_lnland_nst
END LIBRARY
